VERSION 5.8 ;
BUSBITCHARS "[]" ;
DIVIDERCHAR "/" ;
UNITS
    DATABASE MICRONS 1000 ;
END UNITS

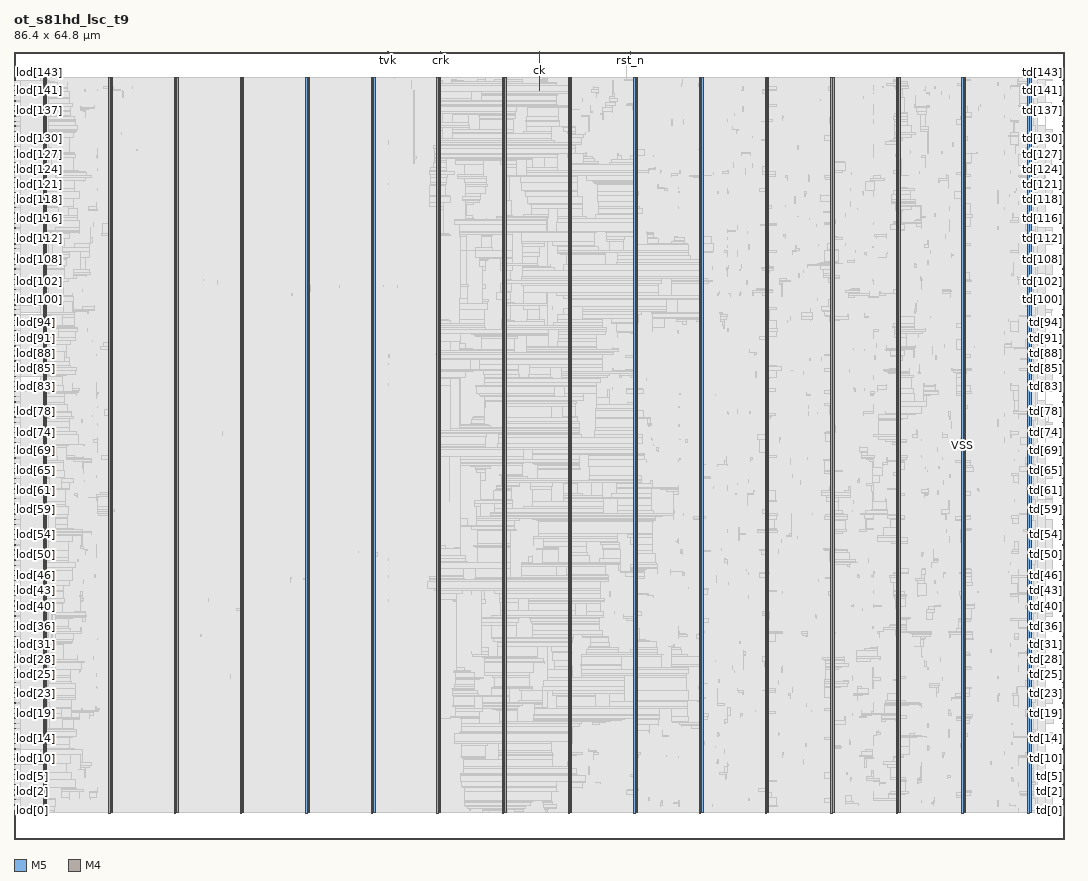
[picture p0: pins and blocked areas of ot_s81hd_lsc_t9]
MACRO ot_s81hd_lsc_t9
  FOREIGN ot_s81hd_lsc_t9 0 0 ;
  CLASS BLOCK ;
  SIZE 86.4 BY 64.8 ;
  PIN ck
    DIRECTION INPUT ;
    USE SIGNAL ;
    PORT
      LAYER M5 ;
        RECT  43.2 64.716 43.224 64.8 ;
    END
    PORT
      LAYER M5 ;
        RECT  43.2 61.619 43.224 64.784 ;
    END
  END ck
  PIN crk
    DIRECTION INPUT ;
    USE SIGNAL ;
    PORT
      LAYER M5 ;
        RECT  35.088 64.716 35.112 64.8 ;
    END
    PORT
      LAYER M5 ;
        RECT  35.088 64.691 35.112 64.784 ;
    END
  END crk
  PIN lod[0]
    DIRECTION OUTPUT ;
    USE SIGNAL ;
    PORT
      LAYER M4 ;
        RECT  0 2.352 0.084 2.376 ;
    END
  END lod[0]
  PIN lod[100]
    DIRECTION OUTPUT ;
    USE SIGNAL ;
    PORT
      LAYER M4 ;
        RECT  0 44.352 0.084 44.376 ;
    END
  END lod[100]
  PIN lod[101]
    DIRECTION OUTPUT ;
    USE SIGNAL ;
    PORT
      LAYER M4 ;
        RECT  0 44.784 0.084 44.808 ;
    END
  END lod[101]
  PIN lod[102]
    DIRECTION OUTPUT ;
    USE SIGNAL ;
    PORT
      LAYER M4 ;
        RECT  0 45.216 0.084 45.24 ;
    END
  END lod[102]
  PIN lod[103]
    DIRECTION OUTPUT ;
    USE SIGNAL ;
    PORT
      LAYER M4 ;
        RECT  0 45.6 0.084 45.624 ;
    END
  END lod[103]
  PIN lod[104]
    DIRECTION OUTPUT ;
    USE SIGNAL ;
    PORT
      LAYER M4 ;
        RECT  0 46.032 0.084 46.056 ;
    END
  END lod[104]
  PIN lod[105]
    DIRECTION OUTPUT ;
    USE SIGNAL ;
    PORT
      LAYER M4 ;
        RECT  0 46.464 0.084 46.488 ;
    END
  END lod[105]
  PIN lod[106]
    DIRECTION OUTPUT ;
    USE SIGNAL ;
    PORT
      LAYER M4 ;
        RECT  0 46.896 0.084 46.92 ;
    END
  END lod[106]
  PIN lod[107]
    DIRECTION OUTPUT ;
    USE SIGNAL ;
    PORT
      LAYER M4 ;
        RECT  0 47.28 0.084 47.304 ;
    END
  END lod[107]
  PIN lod[108]
    DIRECTION OUTPUT ;
    USE SIGNAL ;
    PORT
      LAYER M4 ;
        RECT  0 47.712 0.084 47.736 ;
    END
  END lod[108]
  PIN lod[109]
    DIRECTION OUTPUT ;
    USE SIGNAL ;
    PORT
      LAYER M4 ;
        RECT  0 48.144 0.084 48.168 ;
    END
  END lod[109]
  PIN lod[10]
    DIRECTION OUTPUT ;
    USE SIGNAL ;
    PORT
      LAYER M4 ;
        RECT  0 6.576 0.084 6.6 ;
    END
  END lod[10]
  PIN lod[110]
    DIRECTION OUTPUT ;
    USE SIGNAL ;
    PORT
      LAYER M4 ;
        RECT  0 48.576 0.084 48.6 ;
    END
  END lod[110]
  PIN lod[111]
    DIRECTION OUTPUT ;
    USE SIGNAL ;
    PORT
      LAYER M4 ;
        RECT  0 48.96 0.084 48.984 ;
    END
  END lod[111]
  PIN lod[112]
    DIRECTION OUTPUT ;
    USE SIGNAL ;
    PORT
      LAYER M4 ;
        RECT  0 49.392 0.084 49.416 ;
    END
  END lod[112]
  PIN lod[113]
    DIRECTION OUTPUT ;
    USE SIGNAL ;
    PORT
      LAYER M4 ;
        RECT  0 49.824 0.084 49.848 ;
    END
  END lod[113]
  PIN lod[114]
    DIRECTION OUTPUT ;
    USE SIGNAL ;
    PORT
      LAYER M4 ;
        RECT  0 50.256 0.084 50.28 ;
    END
  END lod[114]
  PIN lod[115]
    DIRECTION OUTPUT ;
    USE SIGNAL ;
    PORT
      LAYER M4 ;
        RECT  0 50.64 0.084 50.664 ;
    END
  END lod[115]
  PIN lod[116]
    DIRECTION OUTPUT ;
    USE SIGNAL ;
    PORT
      LAYER M4 ;
        RECT  0 51.072 0.084 51.096 ;
    END
  END lod[116]
  PIN lod[117]
    DIRECTION OUTPUT ;
    USE SIGNAL ;
    PORT
      LAYER M4 ;
        RECT  0 51.504 0.084 51.528 ;
    END
  END lod[117]
  PIN lod[118]
    DIRECTION OUTPUT ;
    USE SIGNAL ;
    PORT
      LAYER M4 ;
        RECT  0 51.936 0.084 51.96 ;
    END
  END lod[118]
  PIN lod[119]
    DIRECTION OUTPUT ;
    USE SIGNAL ;
    PORT
      LAYER M4 ;
        RECT  0 52.32 0.084 52.344 ;
    END
  END lod[119]
  PIN lod[11]
    DIRECTION OUTPUT ;
    USE SIGNAL ;
    PORT
      LAYER M4 ;
        RECT  0 6.96 0.084 6.984 ;
    END
  END lod[11]
  PIN lod[120]
    DIRECTION OUTPUT ;
    USE SIGNAL ;
    PORT
      LAYER M4 ;
        RECT  0 52.752 0.084 52.776 ;
    END
  END lod[120]
  PIN lod[121]
    DIRECTION OUTPUT ;
    USE SIGNAL ;
    PORT
      LAYER M4 ;
        RECT  0 53.184 0.084 53.208 ;
    END
  END lod[121]
  PIN lod[122]
    DIRECTION OUTPUT ;
    USE SIGNAL ;
    PORT
      LAYER M4 ;
        RECT  0 53.616 0.084 53.64 ;
    END
  END lod[122]
  PIN lod[123]
    DIRECTION OUTPUT ;
    USE SIGNAL ;
    PORT
      LAYER M4 ;
        RECT  0 54 0.084 54.024 ;
    END
  END lod[123]
  PIN lod[124]
    DIRECTION OUTPUT ;
    USE SIGNAL ;
    PORT
      LAYER M4 ;
        RECT  0 54.432 0.084 54.456 ;
    END
  END lod[124]
  PIN lod[125]
    DIRECTION OUTPUT ;
    USE SIGNAL ;
    PORT
      LAYER M4 ;
        RECT  0 54.864 0.084 54.888 ;
    END
  END lod[125]
  PIN lod[126]
    DIRECTION OUTPUT ;
    USE SIGNAL ;
    PORT
      LAYER M4 ;
        RECT  0 55.296 0.084 55.32 ;
    END
  END lod[126]
  PIN lod[127]
    DIRECTION OUTPUT ;
    USE SIGNAL ;
    PORT
      LAYER M4 ;
        RECT  0 55.68 0.084 55.704 ;
    END
  END lod[127]
  PIN lod[128]
    DIRECTION OUTPUT ;
    USE SIGNAL ;
    PORT
      LAYER M4 ;
        RECT  0 56.112 0.084 56.136 ;
    END
  END lod[128]
  PIN lod[129]
    DIRECTION OUTPUT ;
    USE SIGNAL ;
    PORT
      LAYER M4 ;
        RECT  0 56.544 0.084 56.568 ;
    END
  END lod[129]
  PIN lod[12]
    DIRECTION OUTPUT ;
    USE SIGNAL ;
    PORT
      LAYER M4 ;
        RECT  0 7.392 0.084 7.416 ;
    END
  END lod[12]
  PIN lod[130]
    DIRECTION OUTPUT ;
    USE SIGNAL ;
    PORT
      LAYER M4 ;
        RECT  0 56.976 0.084 57 ;
    END
  END lod[130]
  PIN lod[131]
    DIRECTION OUTPUT ;
    USE SIGNAL ;
    PORT
      LAYER M4 ;
        RECT  0 57.36 0.084 57.384 ;
    END
  END lod[131]
  PIN lod[132]
    DIRECTION OUTPUT ;
    USE SIGNAL ;
    PORT
      LAYER M4 ;
        RECT  0 57.792 0.084 57.816 ;
    END
  END lod[132]
  PIN lod[133]
    DIRECTION OUTPUT ;
    USE SIGNAL ;
    PORT
      LAYER M4 ;
        RECT  0 58.224 0.084 58.248 ;
    END
  END lod[133]
  PIN lod[134]
    DIRECTION OUTPUT ;
    USE SIGNAL ;
    PORT
      LAYER M4 ;
        RECT  0 58.656 0.084 58.68 ;
    END
  END lod[134]
  PIN lod[135]
    DIRECTION OUTPUT ;
    USE SIGNAL ;
    PORT
      LAYER M4 ;
        RECT  0 59.04 0.084 59.064 ;
    END
  END lod[135]
  PIN lod[136]
    DIRECTION OUTPUT ;
    USE SIGNAL ;
    PORT
      LAYER M4 ;
        RECT  0 59.472 0.084 59.496 ;
    END
  END lod[136]
  PIN lod[137]
    DIRECTION OUTPUT ;
    USE SIGNAL ;
    PORT
      LAYER M4 ;
        RECT  0 59.904 0.084 59.928 ;
    END
  END lod[137]
  PIN lod[138]
    DIRECTION OUTPUT ;
    USE SIGNAL ;
    PORT
      LAYER M4 ;
        RECT  0 60.336 0.084 60.36 ;
    END
  END lod[138]
  PIN lod[139]
    DIRECTION OUTPUT ;
    USE SIGNAL ;
    PORT
      LAYER M4 ;
        RECT  0 60.72 0.084 60.744 ;
    END
  END lod[139]
  PIN lod[13]
    DIRECTION OUTPUT ;
    USE SIGNAL ;
    PORT
      LAYER M4 ;
        RECT  0 7.824 0.084 7.848 ;
    END
  END lod[13]
  PIN lod[140]
    DIRECTION OUTPUT ;
    USE SIGNAL ;
    PORT
      LAYER M4 ;
        RECT  0 61.152 0.084 61.176 ;
    END
  END lod[140]
  PIN lod[141]
    DIRECTION OUTPUT ;
    USE SIGNAL ;
    PORT
      LAYER M4 ;
        RECT  0 61.584 0.084 61.608 ;
    END
  END lod[141]
  PIN lod[142]
    DIRECTION OUTPUT ;
    USE SIGNAL ;
    PORT
      LAYER M4 ;
        RECT  0 62.016 0.084 62.04 ;
    END
  END lod[142]
  PIN lod[143]
    DIRECTION OUTPUT ;
    USE SIGNAL ;
    PORT
      LAYER M4 ;
        RECT  0 62.4 0.084 62.424 ;
    END
  END lod[143]
  PIN lod[14]
    DIRECTION OUTPUT ;
    USE SIGNAL ;
    PORT
      LAYER M4 ;
        RECT  0 8.256 0.084 8.28 ;
    END
  END lod[14]
  PIN lod[15]
    DIRECTION OUTPUT ;
    USE SIGNAL ;
    PORT
      LAYER M4 ;
        RECT  0 8.64 0.084 8.664 ;
    END
  END lod[15]
  PIN lod[16]
    DIRECTION OUTPUT ;
    USE SIGNAL ;
    PORT
      LAYER M4 ;
        RECT  0 9.072 0.084 9.096 ;
    END
  END lod[16]
  PIN lod[17]
    DIRECTION OUTPUT ;
    USE SIGNAL ;
    PORT
      LAYER M4 ;
        RECT  0 9.504 0.084 9.528 ;
    END
  END lod[17]
  PIN lod[18]
    DIRECTION OUTPUT ;
    USE SIGNAL ;
    PORT
      LAYER M4 ;
        RECT  0 9.936 0.084 9.96 ;
    END
  END lod[18]
  PIN lod[19]
    DIRECTION OUTPUT ;
    USE SIGNAL ;
    PORT
      LAYER M4 ;
        RECT  0 10.32 0.084 10.344 ;
    END
  END lod[19]
  PIN lod[1]
    DIRECTION OUTPUT ;
    USE SIGNAL ;
    PORT
      LAYER M4 ;
        RECT  0 2.784 0.084 2.808 ;
    END
  END lod[1]
  PIN lod[20]
    DIRECTION OUTPUT ;
    USE SIGNAL ;
    PORT
      LAYER M4 ;
        RECT  0 10.752 0.084 10.776 ;
    END
  END lod[20]
  PIN lod[21]
    DIRECTION OUTPUT ;
    USE SIGNAL ;
    PORT
      LAYER M4 ;
        RECT  0 11.184 0.084 11.208 ;
    END
  END lod[21]
  PIN lod[22]
    DIRECTION OUTPUT ;
    USE SIGNAL ;
    PORT
      LAYER M4 ;
        RECT  0 11.616 0.084 11.64 ;
    END
  END lod[22]
  PIN lod[23]
    DIRECTION OUTPUT ;
    USE SIGNAL ;
    PORT
      LAYER M4 ;
        RECT  0 12 0.084 12.024 ;
    END
  END lod[23]
  PIN lod[24]
    DIRECTION OUTPUT ;
    USE SIGNAL ;
    PORT
      LAYER M4 ;
        RECT  0 12.432 0.084 12.456 ;
    END
  END lod[24]
  PIN lod[25]
    DIRECTION OUTPUT ;
    USE SIGNAL ;
    PORT
      LAYER M4 ;
        RECT  0 12.864 0.084 12.888 ;
    END
  END lod[25]
  PIN lod[26]
    DIRECTION OUTPUT ;
    USE SIGNAL ;
    PORT
      LAYER M4 ;
        RECT  0 13.296 0.084 13.32 ;
    END
  END lod[26]
  PIN lod[27]
    DIRECTION OUTPUT ;
    USE SIGNAL ;
    PORT
      LAYER M4 ;
        RECT  0 13.68 0.084 13.704 ;
    END
  END lod[27]
  PIN lod[28]
    DIRECTION OUTPUT ;
    USE SIGNAL ;
    PORT
      LAYER M4 ;
        RECT  0 14.112 0.084 14.136 ;
    END
  END lod[28]
  PIN lod[29]
    DIRECTION OUTPUT ;
    USE SIGNAL ;
    PORT
      LAYER M4 ;
        RECT  0 14.544 0.084 14.568 ;
    END
  END lod[29]
  PIN lod[2]
    DIRECTION OUTPUT ;
    USE SIGNAL ;
    PORT
      LAYER M4 ;
        RECT  0 3.216 0.084 3.24 ;
    END
  END lod[2]
  PIN lod[30]
    DIRECTION OUTPUT ;
    USE SIGNAL ;
    PORT
      LAYER M4 ;
        RECT  0 14.976 0.084 15 ;
    END
  END lod[30]
  PIN lod[31]
    DIRECTION OUTPUT ;
    USE SIGNAL ;
    PORT
      LAYER M4 ;
        RECT  0 15.36 0.084 15.384 ;
    END
  END lod[31]
  PIN lod[32]
    DIRECTION OUTPUT ;
    USE SIGNAL ;
    PORT
      LAYER M4 ;
        RECT  0 15.792 0.084 15.816 ;
    END
  END lod[32]
  PIN lod[33]
    DIRECTION OUTPUT ;
    USE SIGNAL ;
    PORT
      LAYER M4 ;
        RECT  0 16.224 0.084 16.248 ;
    END
  END lod[33]
  PIN lod[34]
    DIRECTION OUTPUT ;
    USE SIGNAL ;
    PORT
      LAYER M4 ;
        RECT  0 16.656 0.084 16.68 ;
    END
  END lod[34]
  PIN lod[35]
    DIRECTION OUTPUT ;
    USE SIGNAL ;
    PORT
      LAYER M4 ;
        RECT  0 17.04 0.084 17.064 ;
    END
  END lod[35]
  PIN lod[36]
    DIRECTION OUTPUT ;
    USE SIGNAL ;
    PORT
      LAYER M4 ;
        RECT  0 17.472 0.084 17.496 ;
    END
  END lod[36]
  PIN lod[37]
    DIRECTION OUTPUT ;
    USE SIGNAL ;
    PORT
      LAYER M4 ;
        RECT  0 17.904 0.084 17.928 ;
    END
  END lod[37]
  PIN lod[38]
    DIRECTION OUTPUT ;
    USE SIGNAL ;
    PORT
      LAYER M4 ;
        RECT  0 18.336 0.084 18.36 ;
    END
  END lod[38]
  PIN lod[39]
    DIRECTION OUTPUT ;
    USE SIGNAL ;
    PORT
      LAYER M4 ;
        RECT  0 18.72 0.084 18.744 ;
    END
  END lod[39]
  PIN lod[3]
    DIRECTION OUTPUT ;
    USE SIGNAL ;
    PORT
      LAYER M4 ;
        RECT  0 3.6 0.084 3.624 ;
    END
  END lod[3]
  PIN lod[40]
    DIRECTION OUTPUT ;
    USE SIGNAL ;
    PORT
      LAYER M4 ;
        RECT  0 19.152 0.084 19.176 ;
    END
  END lod[40]
  PIN lod[41]
    DIRECTION OUTPUT ;
    USE SIGNAL ;
    PORT
      LAYER M4 ;
        RECT  0 19.584 0.084 19.608 ;
    END
  END lod[41]
  PIN lod[42]
    DIRECTION OUTPUT ;
    USE SIGNAL ;
    PORT
      LAYER M4 ;
        RECT  0 20.016 0.084 20.04 ;
    END
  END lod[42]
  PIN lod[43]
    DIRECTION OUTPUT ;
    USE SIGNAL ;
    PORT
      LAYER M4 ;
        RECT  0 20.4 0.084 20.424 ;
    END
  END lod[43]
  PIN lod[44]
    DIRECTION OUTPUT ;
    USE SIGNAL ;
    PORT
      LAYER M4 ;
        RECT  0 20.832 0.084 20.856 ;
    END
  END lod[44]
  PIN lod[45]
    DIRECTION OUTPUT ;
    USE SIGNAL ;
    PORT
      LAYER M4 ;
        RECT  0 21.264 0.084 21.288 ;
    END
  END lod[45]
  PIN lod[46]
    DIRECTION OUTPUT ;
    USE SIGNAL ;
    PORT
      LAYER M4 ;
        RECT  0 21.696 0.084 21.72 ;
    END
  END lod[46]
  PIN lod[47]
    DIRECTION OUTPUT ;
    USE SIGNAL ;
    PORT
      LAYER M4 ;
        RECT  0 22.08 0.084 22.104 ;
    END
  END lod[47]
  PIN lod[48]
    DIRECTION OUTPUT ;
    USE SIGNAL ;
    PORT
      LAYER M4 ;
        RECT  0 22.512 0.084 22.536 ;
    END
  END lod[48]
  PIN lod[49]
    DIRECTION OUTPUT ;
    USE SIGNAL ;
    PORT
      LAYER M4 ;
        RECT  0 22.944 0.084 22.968 ;
    END
  END lod[49]
  PIN lod[4]
    DIRECTION OUTPUT ;
    USE SIGNAL ;
    PORT
      LAYER M4 ;
        RECT  0 4.032 0.084 4.056 ;
    END
  END lod[4]
  PIN lod[50]
    DIRECTION OUTPUT ;
    USE SIGNAL ;
    PORT
      LAYER M4 ;
        RECT  0 23.376 0.084 23.4 ;
    END
  END lod[50]
  PIN lod[51]
    DIRECTION OUTPUT ;
    USE SIGNAL ;
    PORT
      LAYER M4 ;
        RECT  0 23.76 0.084 23.784 ;
    END
  END lod[51]
  PIN lod[52]
    DIRECTION OUTPUT ;
    USE SIGNAL ;
    PORT
      LAYER M4 ;
        RECT  0 24.192 0.084 24.216 ;
    END
  END lod[52]
  PIN lod[53]
    DIRECTION OUTPUT ;
    USE SIGNAL ;
    PORT
      LAYER M4 ;
        RECT  0 24.624 0.084 24.648 ;
    END
  END lod[53]
  PIN lod[54]
    DIRECTION OUTPUT ;
    USE SIGNAL ;
    PORT
      LAYER M4 ;
        RECT  0 25.056 0.084 25.08 ;
    END
  END lod[54]
  PIN lod[55]
    DIRECTION OUTPUT ;
    USE SIGNAL ;
    PORT
      LAYER M4 ;
        RECT  0 25.44 0.084 25.464 ;
    END
  END lod[55]
  PIN lod[56]
    DIRECTION OUTPUT ;
    USE SIGNAL ;
    PORT
      LAYER M4 ;
        RECT  0 25.872 0.084 25.896 ;
    END
  END lod[56]
  PIN lod[57]
    DIRECTION OUTPUT ;
    USE SIGNAL ;
    PORT
      LAYER M4 ;
        RECT  0 26.304 0.084 26.328 ;
    END
  END lod[57]
  PIN lod[58]
    DIRECTION OUTPUT ;
    USE SIGNAL ;
    PORT
      LAYER M4 ;
        RECT  0 26.736 0.084 26.76 ;
    END
  END lod[58]
  PIN lod[59]
    DIRECTION OUTPUT ;
    USE SIGNAL ;
    PORT
      LAYER M4 ;
        RECT  0 27.12 0.084 27.144 ;
    END
  END lod[59]
  PIN lod[5]
    DIRECTION OUTPUT ;
    USE SIGNAL ;
    PORT
      LAYER M4 ;
        RECT  0 4.464 0.084 4.488 ;
    END
  END lod[5]
  PIN lod[60]
    DIRECTION OUTPUT ;
    USE SIGNAL ;
    PORT
      LAYER M4 ;
        RECT  0 27.552 0.084 27.576 ;
    END
  END lod[60]
  PIN lod[61]
    DIRECTION OUTPUT ;
    USE SIGNAL ;
    PORT
      LAYER M4 ;
        RECT  0 27.984 0.084 28.008 ;
    END
  END lod[61]
  PIN lod[62]
    DIRECTION OUTPUT ;
    USE SIGNAL ;
    PORT
      LAYER M4 ;
        RECT  0 28.416 0.084 28.44 ;
    END
  END lod[62]
  PIN lod[63]
    DIRECTION OUTPUT ;
    USE SIGNAL ;
    PORT
      LAYER M4 ;
        RECT  0 28.8 0.084 28.824 ;
    END
  END lod[63]
  PIN lod[64]
    DIRECTION OUTPUT ;
    USE SIGNAL ;
    PORT
      LAYER M4 ;
        RECT  0 29.232 0.084 29.256 ;
    END
  END lod[64]
  PIN lod[65]
    DIRECTION OUTPUT ;
    USE SIGNAL ;
    PORT
      LAYER M4 ;
        RECT  0 29.664 0.084 29.688 ;
    END
  END lod[65]
  PIN lod[66]
    DIRECTION OUTPUT ;
    USE SIGNAL ;
    PORT
      LAYER M4 ;
        RECT  0 30.096 0.084 30.12 ;
    END
  END lod[66]
  PIN lod[67]
    DIRECTION OUTPUT ;
    USE SIGNAL ;
    PORT
      LAYER M4 ;
        RECT  0 30.48 0.084 30.504 ;
    END
  END lod[67]
  PIN lod[68]
    DIRECTION OUTPUT ;
    USE SIGNAL ;
    PORT
      LAYER M4 ;
        RECT  0 30.912 0.084 30.936 ;
    END
  END lod[68]
  PIN lod[69]
    DIRECTION OUTPUT ;
    USE SIGNAL ;
    PORT
      LAYER M4 ;
        RECT  0 31.344 0.084 31.368 ;
    END
  END lod[69]
  PIN lod[6]
    DIRECTION OUTPUT ;
    USE SIGNAL ;
    PORT
      LAYER M4 ;
        RECT  0 4.896 0.084 4.92 ;
    END
  END lod[6]
  PIN lod[70]
    DIRECTION OUTPUT ;
    USE SIGNAL ;
    PORT
      LAYER M4 ;
        RECT  0 31.776 0.084 31.8 ;
    END
  END lod[70]
  PIN lod[71]
    DIRECTION OUTPUT ;
    USE SIGNAL ;
    PORT
      LAYER M4 ;
        RECT  0 32.16 0.084 32.184 ;
    END
  END lod[71]
  PIN lod[72]
    DIRECTION OUTPUT ;
    USE SIGNAL ;
    PORT
      LAYER M4 ;
        RECT  0 32.592 0.084 32.616 ;
    END
  END lod[72]
  PIN lod[73]
    DIRECTION OUTPUT ;
    USE SIGNAL ;
    PORT
      LAYER M4 ;
        RECT  0 33.024 0.084 33.048 ;
    END
  END lod[73]
  PIN lod[74]
    DIRECTION OUTPUT ;
    USE SIGNAL ;
    PORT
      LAYER M4 ;
        RECT  0 33.456 0.084 33.48 ;
    END
  END lod[74]
  PIN lod[75]
    DIRECTION OUTPUT ;
    USE SIGNAL ;
    PORT
      LAYER M4 ;
        RECT  0 33.84 0.084 33.864 ;
    END
  END lod[75]
  PIN lod[76]
    DIRECTION OUTPUT ;
    USE SIGNAL ;
    PORT
      LAYER M4 ;
        RECT  0 34.272 0.084 34.296 ;
    END
  END lod[76]
  PIN lod[77]
    DIRECTION OUTPUT ;
    USE SIGNAL ;
    PORT
      LAYER M4 ;
        RECT  0 34.704 0.084 34.728 ;
    END
  END lod[77]
  PIN lod[78]
    DIRECTION OUTPUT ;
    USE SIGNAL ;
    PORT
      LAYER M4 ;
        RECT  0 35.136 0.084 35.16 ;
    END
  END lod[78]
  PIN lod[79]
    DIRECTION OUTPUT ;
    USE SIGNAL ;
    PORT
      LAYER M4 ;
        RECT  0 35.52 0.084 35.544 ;
    END
  END lod[79]
  PIN lod[7]
    DIRECTION OUTPUT ;
    USE SIGNAL ;
    PORT
      LAYER M4 ;
        RECT  0 5.28 0.084 5.304 ;
    END
  END lod[7]
  PIN lod[80]
    DIRECTION OUTPUT ;
    USE SIGNAL ;
    PORT
      LAYER M4 ;
        RECT  0 35.952 0.084 35.976 ;
    END
  END lod[80]
  PIN lod[81]
    DIRECTION OUTPUT ;
    USE SIGNAL ;
    PORT
      LAYER M4 ;
        RECT  0 36.384 0.084 36.408 ;
    END
  END lod[81]
  PIN lod[82]
    DIRECTION OUTPUT ;
    USE SIGNAL ;
    PORT
      LAYER M4 ;
        RECT  0 36.816 0.084 36.84 ;
    END
  END lod[82]
  PIN lod[83]
    DIRECTION OUTPUT ;
    USE SIGNAL ;
    PORT
      LAYER M4 ;
        RECT  0 37.2 0.084 37.224 ;
    END
  END lod[83]
  PIN lod[84]
    DIRECTION OUTPUT ;
    USE SIGNAL ;
    PORT
      LAYER M4 ;
        RECT  0 37.632 0.084 37.656 ;
    END
  END lod[84]
  PIN lod[85]
    DIRECTION OUTPUT ;
    USE SIGNAL ;
    PORT
      LAYER M4 ;
        RECT  0 38.064 0.084 38.088 ;
    END
  END lod[85]
  PIN lod[86]
    DIRECTION OUTPUT ;
    USE SIGNAL ;
    PORT
      LAYER M4 ;
        RECT  0 38.496 0.084 38.52 ;
    END
  END lod[86]
  PIN lod[87]
    DIRECTION OUTPUT ;
    USE SIGNAL ;
    PORT
      LAYER M4 ;
        RECT  0 38.88 0.084 38.904 ;
    END
  END lod[87]
  PIN lod[88]
    DIRECTION OUTPUT ;
    USE SIGNAL ;
    PORT
      LAYER M4 ;
        RECT  0 39.312 0.084 39.336 ;
    END
  END lod[88]
  PIN lod[89]
    DIRECTION OUTPUT ;
    USE SIGNAL ;
    PORT
      LAYER M4 ;
        RECT  0 39.744 0.084 39.768 ;
    END
  END lod[89]
  PIN lod[8]
    DIRECTION OUTPUT ;
    USE SIGNAL ;
    PORT
      LAYER M4 ;
        RECT  0 5.712 0.084 5.736 ;
    END
  END lod[8]
  PIN lod[90]
    DIRECTION OUTPUT ;
    USE SIGNAL ;
    PORT
      LAYER M4 ;
        RECT  0 40.176 0.084 40.2 ;
    END
  END lod[90]
  PIN lod[91]
    DIRECTION OUTPUT ;
    USE SIGNAL ;
    PORT
      LAYER M4 ;
        RECT  0 40.56 0.084 40.584 ;
    END
  END lod[91]
  PIN lod[92]
    DIRECTION OUTPUT ;
    USE SIGNAL ;
    PORT
      LAYER M4 ;
        RECT  0 40.992 0.084 41.016 ;
    END
  END lod[92]
  PIN lod[93]
    DIRECTION OUTPUT ;
    USE SIGNAL ;
    PORT
      LAYER M4 ;
        RECT  0 41.424 0.084 41.448 ;
    END
  END lod[93]
  PIN lod[94]
    DIRECTION OUTPUT ;
    USE SIGNAL ;
    PORT
      LAYER M4 ;
        RECT  0 41.856 0.084 41.88 ;
    END
  END lod[94]
  PIN lod[95]
    DIRECTION OUTPUT ;
    USE SIGNAL ;
    PORT
      LAYER M4 ;
        RECT  0 42.24 0.084 42.264 ;
    END
  END lod[95]
  PIN lod[96]
    DIRECTION OUTPUT ;
    USE SIGNAL ;
    PORT
      LAYER M4 ;
        RECT  0 42.672 0.084 42.696 ;
    END
  END lod[96]
  PIN lod[97]
    DIRECTION OUTPUT ;
    USE SIGNAL ;
    PORT
      LAYER M4 ;
        RECT  0 43.104 0.084 43.128 ;
    END
  END lod[97]
  PIN lod[98]
    DIRECTION OUTPUT ;
    USE SIGNAL ;
    PORT
      LAYER M4 ;
        RECT  0 43.536 0.084 43.56 ;
    END
  END lod[98]
  PIN lod[99]
    DIRECTION OUTPUT ;
    USE SIGNAL ;
    PORT
      LAYER M4 ;
        RECT  0 43.92 0.084 43.944 ;
    END
  END lod[99]
  PIN lod[9]
    DIRECTION OUTPUT ;
    USE SIGNAL ;
    PORT
      LAYER M4 ;
        RECT  0 6.144 0.084 6.168 ;
    END
  END lod[9]
  PIN rst_n
    DIRECTION INPUT ;
    USE SIGNAL ;
    PORT
      LAYER M5 ;
        RECT  50.736 64.716 50.76 64.8 ;
    END
    PORT
      LAYER M5 ;
        RECT  50.736 63.829 50.76 64.784 ;
    END
  END rst_n
  PIN td[0]
    DIRECTION INPUT ;
    USE SIGNAL ;
    PORT
      LAYER M4 ;
        RECT  86.316 2.352 86.4 2.376 ;
    END
  END td[0]
  PIN td[100]
    DIRECTION INPUT ;
    USE SIGNAL ;
    PORT
      LAYER M4 ;
        RECT  86.316 44.352 86.4 44.376 ;
    END
  END td[100]
  PIN td[101]
    DIRECTION INPUT ;
    USE SIGNAL ;
    PORT
      LAYER M4 ;
        RECT  86.316 44.784 86.4 44.808 ;
    END
  END td[101]
  PIN td[102]
    DIRECTION INPUT ;
    USE SIGNAL ;
    PORT
      LAYER M4 ;
        RECT  86.316 45.216 86.4 45.24 ;
    END
  END td[102]
  PIN td[103]
    DIRECTION INPUT ;
    USE SIGNAL ;
    PORT
      LAYER M4 ;
        RECT  86.316 45.6 86.4 45.624 ;
    END
  END td[103]
  PIN td[104]
    DIRECTION INPUT ;
    USE SIGNAL ;
    PORT
      LAYER M4 ;
        RECT  86.316 46.032 86.4 46.056 ;
    END
  END td[104]
  PIN td[105]
    DIRECTION INPUT ;
    USE SIGNAL ;
    PORT
      LAYER M4 ;
        RECT  86.316 46.464 86.4 46.488 ;
    END
  END td[105]
  PIN td[106]
    DIRECTION INPUT ;
    USE SIGNAL ;
    PORT
      LAYER M4 ;
        RECT  86.316 46.896 86.4 46.92 ;
    END
  END td[106]
  PIN td[107]
    DIRECTION INPUT ;
    USE SIGNAL ;
    PORT
      LAYER M4 ;
        RECT  86.316 47.28 86.4 47.304 ;
    END
  END td[107]
  PIN td[108]
    DIRECTION INPUT ;
    USE SIGNAL ;
    PORT
      LAYER M4 ;
        RECT  86.316 47.712 86.4 47.736 ;
    END
  END td[108]
  PIN td[109]
    DIRECTION INPUT ;
    USE SIGNAL ;
    PORT
      LAYER M4 ;
        RECT  86.316 48.144 86.4 48.168 ;
    END
  END td[109]
  PIN td[10]
    DIRECTION INPUT ;
    USE SIGNAL ;
    PORT
      LAYER M4 ;
        RECT  86.316 6.576 86.4 6.6 ;
    END
  END td[10]
  PIN td[110]
    DIRECTION INPUT ;
    USE SIGNAL ;
    PORT
      LAYER M4 ;
        RECT  86.316 48.576 86.4 48.6 ;
    END
  END td[110]
  PIN td[111]
    DIRECTION INPUT ;
    USE SIGNAL ;
    PORT
      LAYER M4 ;
        RECT  86.316 48.96 86.4 48.984 ;
    END
  END td[111]
  PIN td[112]
    DIRECTION INPUT ;
    USE SIGNAL ;
    PORT
      LAYER M4 ;
        RECT  86.316 49.392 86.4 49.416 ;
    END
  END td[112]
  PIN td[113]
    DIRECTION INPUT ;
    USE SIGNAL ;
    PORT
      LAYER M4 ;
        RECT  86.316 49.824 86.4 49.848 ;
    END
  END td[113]
  PIN td[114]
    DIRECTION INPUT ;
    USE SIGNAL ;
    PORT
      LAYER M4 ;
        RECT  86.316 50.256 86.4 50.28 ;
    END
  END td[114]
  PIN td[115]
    DIRECTION INPUT ;
    USE SIGNAL ;
    PORT
      LAYER M4 ;
        RECT  86.316 50.64 86.4 50.664 ;
    END
  END td[115]
  PIN td[116]
    DIRECTION INPUT ;
    USE SIGNAL ;
    PORT
      LAYER M4 ;
        RECT  86.316 51.072 86.4 51.096 ;
    END
  END td[116]
  PIN td[117]
    DIRECTION INPUT ;
    USE SIGNAL ;
    PORT
      LAYER M4 ;
        RECT  86.316 51.504 86.4 51.528 ;
    END
  END td[117]
  PIN td[118]
    DIRECTION INPUT ;
    USE SIGNAL ;
    PORT
      LAYER M4 ;
        RECT  86.316 51.936 86.4 51.96 ;
    END
  END td[118]
  PIN td[119]
    DIRECTION INPUT ;
    USE SIGNAL ;
    PORT
      LAYER M4 ;
        RECT  86.316 52.32 86.4 52.344 ;
    END
  END td[119]
  PIN td[11]
    DIRECTION INPUT ;
    USE SIGNAL ;
    PORT
      LAYER M4 ;
        RECT  86.316 6.96 86.4 6.984 ;
    END
  END td[11]
  PIN td[120]
    DIRECTION INPUT ;
    USE SIGNAL ;
    PORT
      LAYER M4 ;
        RECT  86.316 52.752 86.4 52.776 ;
    END
  END td[120]
  PIN td[121]
    DIRECTION INPUT ;
    USE SIGNAL ;
    PORT
      LAYER M4 ;
        RECT  86.316 53.184 86.4 53.208 ;
    END
  END td[121]
  PIN td[122]
    DIRECTION INPUT ;
    USE SIGNAL ;
    PORT
      LAYER M4 ;
        RECT  86.316 53.616 86.4 53.64 ;
    END
  END td[122]
  PIN td[123]
    DIRECTION INPUT ;
    USE SIGNAL ;
    PORT
      LAYER M4 ;
        RECT  86.316 54 86.4 54.024 ;
    END
  END td[123]
  PIN td[124]
    DIRECTION INPUT ;
    USE SIGNAL ;
    PORT
      LAYER M4 ;
        RECT  86.316 54.432 86.4 54.456 ;
    END
  END td[124]
  PIN td[125]
    DIRECTION INPUT ;
    USE SIGNAL ;
    PORT
      LAYER M4 ;
        RECT  86.316 54.864 86.4 54.888 ;
    END
  END td[125]
  PIN td[126]
    DIRECTION INPUT ;
    USE SIGNAL ;
    PORT
      LAYER M4 ;
        RECT  86.316 55.296 86.4 55.32 ;
    END
  END td[126]
  PIN td[127]
    DIRECTION INPUT ;
    USE SIGNAL ;
    PORT
      LAYER M4 ;
        RECT  86.316 55.68 86.4 55.704 ;
    END
  END td[127]
  PIN td[128]
    DIRECTION INPUT ;
    USE SIGNAL ;
    PORT
      LAYER M4 ;
        RECT  86.316 56.112 86.4 56.136 ;
    END
  END td[128]
  PIN td[129]
    DIRECTION INPUT ;
    USE SIGNAL ;
    PORT
      LAYER M4 ;
        RECT  86.316 56.544 86.4 56.568 ;
    END
  END td[129]
  PIN td[12]
    DIRECTION INPUT ;
    USE SIGNAL ;
    PORT
      LAYER M4 ;
        RECT  86.316 7.392 86.4 7.416 ;
    END
  END td[12]
  PIN td[130]
    DIRECTION INPUT ;
    USE SIGNAL ;
    PORT
      LAYER M4 ;
        RECT  86.316 56.976 86.4 57 ;
    END
  END td[130]
  PIN td[131]
    DIRECTION INPUT ;
    USE SIGNAL ;
    PORT
      LAYER M4 ;
        RECT  86.316 57.36 86.4 57.384 ;
    END
  END td[131]
  PIN td[132]
    DIRECTION INPUT ;
    USE SIGNAL ;
    PORT
      LAYER M4 ;
        RECT  86.316 57.792 86.4 57.816 ;
    END
  END td[132]
  PIN td[133]
    DIRECTION INPUT ;
    USE SIGNAL ;
    PORT
      LAYER M4 ;
        RECT  86.316 58.224 86.4 58.248 ;
    END
  END td[133]
  PIN td[134]
    DIRECTION INPUT ;
    USE SIGNAL ;
    PORT
      LAYER M4 ;
        RECT  86.316 58.656 86.4 58.68 ;
    END
  END td[134]
  PIN td[135]
    DIRECTION INPUT ;
    USE SIGNAL ;
    PORT
      LAYER M4 ;
        RECT  86.316 59.04 86.4 59.064 ;
    END
  END td[135]
  PIN td[136]
    DIRECTION INPUT ;
    USE SIGNAL ;
    PORT
      LAYER M4 ;
        RECT  86.316 59.472 86.4 59.496 ;
    END
  END td[136]
  PIN td[137]
    DIRECTION INPUT ;
    USE SIGNAL ;
    PORT
      LAYER M4 ;
        RECT  86.316 59.904 86.4 59.928 ;
    END
  END td[137]
  PIN td[138]
    DIRECTION INPUT ;
    USE SIGNAL ;
    PORT
      LAYER M4 ;
        RECT  86.316 60.336 86.4 60.36 ;
    END
  END td[138]
  PIN td[139]
    DIRECTION INPUT ;
    USE SIGNAL ;
    PORT
      LAYER M4 ;
        RECT  86.316 60.72 86.4 60.744 ;
    END
  END td[139]
  PIN td[13]
    DIRECTION INPUT ;
    USE SIGNAL ;
    PORT
      LAYER M4 ;
        RECT  86.316 7.824 86.4 7.848 ;
    END
  END td[13]
  PIN td[140]
    DIRECTION INPUT ;
    USE SIGNAL ;
    PORT
      LAYER M4 ;
        RECT  86.316 61.152 86.4 61.176 ;
    END
  END td[140]
  PIN td[141]
    DIRECTION INPUT ;
    USE SIGNAL ;
    PORT
      LAYER M4 ;
        RECT  86.316 61.584 86.4 61.608 ;
    END
  END td[141]
  PIN td[142]
    DIRECTION INPUT ;
    USE SIGNAL ;
    PORT
      LAYER M4 ;
        RECT  86.316 62.016 86.4 62.04 ;
    END
  END td[142]
  PIN td[143]
    DIRECTION INPUT ;
    USE SIGNAL ;
    PORT
      LAYER M4 ;
        RECT  86.316 62.4 86.4 62.424 ;
    END
  END td[143]
  PIN td[14]
    DIRECTION INPUT ;
    USE SIGNAL ;
    PORT
      LAYER M4 ;
        RECT  86.316 8.256 86.4 8.28 ;
    END
  END td[14]
  PIN td[15]
    DIRECTION INPUT ;
    USE SIGNAL ;
    PORT
      LAYER M4 ;
        RECT  86.316 8.64 86.4 8.664 ;
    END
  END td[15]
  PIN td[16]
    DIRECTION INPUT ;
    USE SIGNAL ;
    PORT
      LAYER M4 ;
        RECT  86.316 9.072 86.4 9.096 ;
    END
  END td[16]
  PIN td[17]
    DIRECTION INPUT ;
    USE SIGNAL ;
    PORT
      LAYER M4 ;
        RECT  86.316 9.504 86.4 9.528 ;
    END
  END td[17]
  PIN td[18]
    DIRECTION INPUT ;
    USE SIGNAL ;
    PORT
      LAYER M4 ;
        RECT  86.316 9.936 86.4 9.96 ;
    END
  END td[18]
  PIN td[19]
    DIRECTION INPUT ;
    USE SIGNAL ;
    PORT
      LAYER M4 ;
        RECT  86.316 10.32 86.4 10.344 ;
    END
  END td[19]
  PIN td[1]
    DIRECTION INPUT ;
    USE SIGNAL ;
    PORT
      LAYER M4 ;
        RECT  86.316 2.784 86.4 2.808 ;
    END
  END td[1]
  PIN td[20]
    DIRECTION INPUT ;
    USE SIGNAL ;
    PORT
      LAYER M4 ;
        RECT  86.316 10.752 86.4 10.776 ;
    END
  END td[20]
  PIN td[21]
    DIRECTION INPUT ;
    USE SIGNAL ;
    PORT
      LAYER M4 ;
        RECT  86.316 11.184 86.4 11.208 ;
    END
  END td[21]
  PIN td[22]
    DIRECTION INPUT ;
    USE SIGNAL ;
    PORT
      LAYER M4 ;
        RECT  86.316 11.616 86.4 11.64 ;
    END
  END td[22]
  PIN td[23]
    DIRECTION INPUT ;
    USE SIGNAL ;
    PORT
      LAYER M4 ;
        RECT  86.316 12 86.4 12.024 ;
    END
  END td[23]
  PIN td[24]
    DIRECTION INPUT ;
    USE SIGNAL ;
    PORT
      LAYER M4 ;
        RECT  86.316 12.432 86.4 12.456 ;
    END
  END td[24]
  PIN td[25]
    DIRECTION INPUT ;
    USE SIGNAL ;
    PORT
      LAYER M4 ;
        RECT  86.316 12.864 86.4 12.888 ;
    END
  END td[25]
  PIN td[26]
    DIRECTION INPUT ;
    USE SIGNAL ;
    PORT
      LAYER M4 ;
        RECT  86.316 13.296 86.4 13.32 ;
    END
  END td[26]
  PIN td[27]
    DIRECTION INPUT ;
    USE SIGNAL ;
    PORT
      LAYER M4 ;
        RECT  86.316 13.68 86.4 13.704 ;
    END
  END td[27]
  PIN td[28]
    DIRECTION INPUT ;
    USE SIGNAL ;
    PORT
      LAYER M4 ;
        RECT  86.316 14.112 86.4 14.136 ;
    END
  END td[28]
  PIN td[29]
    DIRECTION INPUT ;
    USE SIGNAL ;
    PORT
      LAYER M4 ;
        RECT  86.316 14.544 86.4 14.568 ;
    END
  END td[29]
  PIN td[2]
    DIRECTION INPUT ;
    USE SIGNAL ;
    PORT
      LAYER M4 ;
        RECT  86.316 3.216 86.4 3.24 ;
    END
  END td[2]
  PIN td[30]
    DIRECTION INPUT ;
    USE SIGNAL ;
    PORT
      LAYER M4 ;
        RECT  86.316 14.976 86.4 15 ;
    END
  END td[30]
  PIN td[31]
    DIRECTION INPUT ;
    USE SIGNAL ;
    PORT
      LAYER M4 ;
        RECT  86.316 15.36 86.4 15.384 ;
    END
  END td[31]
  PIN td[32]
    DIRECTION INPUT ;
    USE SIGNAL ;
    PORT
      LAYER M4 ;
        RECT  86.316 15.792 86.4 15.816 ;
    END
  END td[32]
  PIN td[33]
    DIRECTION INPUT ;
    USE SIGNAL ;
    PORT
      LAYER M4 ;
        RECT  86.316 16.224 86.4 16.248 ;
    END
  END td[33]
  PIN td[34]
    DIRECTION INPUT ;
    USE SIGNAL ;
    PORT
      LAYER M4 ;
        RECT  86.316 16.656 86.4 16.68 ;
    END
  END td[34]
  PIN td[35]
    DIRECTION INPUT ;
    USE SIGNAL ;
    PORT
      LAYER M4 ;
        RECT  86.316 17.04 86.4 17.064 ;
    END
  END td[35]
  PIN td[36]
    DIRECTION INPUT ;
    USE SIGNAL ;
    PORT
      LAYER M4 ;
        RECT  86.316 17.472 86.4 17.496 ;
    END
  END td[36]
  PIN td[37]
    DIRECTION INPUT ;
    USE SIGNAL ;
    PORT
      LAYER M4 ;
        RECT  86.316 17.904 86.4 17.928 ;
    END
  END td[37]
  PIN td[38]
    DIRECTION INPUT ;
    USE SIGNAL ;
    PORT
      LAYER M4 ;
        RECT  86.316 18.336 86.4 18.36 ;
    END
  END td[38]
  PIN td[39]
    DIRECTION INPUT ;
    USE SIGNAL ;
    PORT
      LAYER M4 ;
        RECT  86.316 18.72 86.4 18.744 ;
    END
  END td[39]
  PIN td[3]
    DIRECTION INPUT ;
    USE SIGNAL ;
    PORT
      LAYER M4 ;
        RECT  86.316 3.6 86.4 3.624 ;
    END
  END td[3]
  PIN td[40]
    DIRECTION INPUT ;
    USE SIGNAL ;
    PORT
      LAYER M4 ;
        RECT  86.316 19.152 86.4 19.176 ;
    END
  END td[40]
  PIN td[41]
    DIRECTION INPUT ;
    USE SIGNAL ;
    PORT
      LAYER M4 ;
        RECT  86.316 19.584 86.4 19.608 ;
    END
  END td[41]
  PIN td[42]
    DIRECTION INPUT ;
    USE SIGNAL ;
    PORT
      LAYER M4 ;
        RECT  86.316 20.016 86.4 20.04 ;
    END
  END td[42]
  PIN td[43]
    DIRECTION INPUT ;
    USE SIGNAL ;
    PORT
      LAYER M4 ;
        RECT  86.316 20.4 86.4 20.424 ;
    END
  END td[43]
  PIN td[44]
    DIRECTION INPUT ;
    USE SIGNAL ;
    PORT
      LAYER M4 ;
        RECT  86.316 20.832 86.4 20.856 ;
    END
  END td[44]
  PIN td[45]
    DIRECTION INPUT ;
    USE SIGNAL ;
    PORT
      LAYER M4 ;
        RECT  86.316 21.264 86.4 21.288 ;
    END
  END td[45]
  PIN td[46]
    DIRECTION INPUT ;
    USE SIGNAL ;
    PORT
      LAYER M4 ;
        RECT  86.316 21.696 86.4 21.72 ;
    END
  END td[46]
  PIN td[47]
    DIRECTION INPUT ;
    USE SIGNAL ;
    PORT
      LAYER M4 ;
        RECT  86.316 22.08 86.4 22.104 ;
    END
  END td[47]
  PIN td[48]
    DIRECTION INPUT ;
    USE SIGNAL ;
    PORT
      LAYER M4 ;
        RECT  86.316 22.512 86.4 22.536 ;
    END
  END td[48]
  PIN td[49]
    DIRECTION INPUT ;
    USE SIGNAL ;
    PORT
      LAYER M4 ;
        RECT  86.316 22.944 86.4 22.968 ;
    END
  END td[49]
  PIN td[4]
    DIRECTION INPUT ;
    USE SIGNAL ;
    PORT
      LAYER M4 ;
        RECT  86.316 4.032 86.4 4.056 ;
    END
  END td[4]
  PIN td[50]
    DIRECTION INPUT ;
    USE SIGNAL ;
    PORT
      LAYER M4 ;
        RECT  86.316 23.376 86.4 23.4 ;
    END
  END td[50]
  PIN td[51]
    DIRECTION INPUT ;
    USE SIGNAL ;
    PORT
      LAYER M4 ;
        RECT  86.316 23.76 86.4 23.784 ;
    END
  END td[51]
  PIN td[52]
    DIRECTION INPUT ;
    USE SIGNAL ;
    PORT
      LAYER M4 ;
        RECT  86.316 24.192 86.4 24.216 ;
    END
  END td[52]
  PIN td[53]
    DIRECTION INPUT ;
    USE SIGNAL ;
    PORT
      LAYER M4 ;
        RECT  86.316 24.624 86.4 24.648 ;
    END
  END td[53]
  PIN td[54]
    DIRECTION INPUT ;
    USE SIGNAL ;
    PORT
      LAYER M4 ;
        RECT  86.316 25.056 86.4 25.08 ;
    END
  END td[54]
  PIN td[55]
    DIRECTION INPUT ;
    USE SIGNAL ;
    PORT
      LAYER M4 ;
        RECT  86.316 25.44 86.4 25.464 ;
    END
  END td[55]
  PIN td[56]
    DIRECTION INPUT ;
    USE SIGNAL ;
    PORT
      LAYER M4 ;
        RECT  86.316 25.872 86.4 25.896 ;
    END
  END td[56]
  PIN td[57]
    DIRECTION INPUT ;
    USE SIGNAL ;
    PORT
      LAYER M4 ;
        RECT  86.316 26.304 86.4 26.328 ;
    END
  END td[57]
  PIN td[58]
    DIRECTION INPUT ;
    USE SIGNAL ;
    PORT
      LAYER M4 ;
        RECT  86.316 26.736 86.4 26.76 ;
    END
  END td[58]
  PIN td[59]
    DIRECTION INPUT ;
    USE SIGNAL ;
    PORT
      LAYER M4 ;
        RECT  86.316 27.12 86.4 27.144 ;
    END
  END td[59]
  PIN td[5]
    DIRECTION INPUT ;
    USE SIGNAL ;
    PORT
      LAYER M4 ;
        RECT  86.316 4.464 86.4 4.488 ;
    END
  END td[5]
  PIN td[60]
    DIRECTION INPUT ;
    USE SIGNAL ;
    PORT
      LAYER M4 ;
        RECT  86.316 27.552 86.4 27.576 ;
    END
  END td[60]
  PIN td[61]
    DIRECTION INPUT ;
    USE SIGNAL ;
    PORT
      LAYER M4 ;
        RECT  86.316 27.984 86.4 28.008 ;
    END
  END td[61]
  PIN td[62]
    DIRECTION INPUT ;
    USE SIGNAL ;
    PORT
      LAYER M4 ;
        RECT  86.316 28.416 86.4 28.44 ;
    END
  END td[62]
  PIN td[63]
    DIRECTION INPUT ;
    USE SIGNAL ;
    PORT
      LAYER M4 ;
        RECT  86.316 28.8 86.4 28.824 ;
    END
  END td[63]
  PIN td[64]
    DIRECTION INPUT ;
    USE SIGNAL ;
    PORT
      LAYER M4 ;
        RECT  86.316 29.232 86.4 29.256 ;
    END
  END td[64]
  PIN td[65]
    DIRECTION INPUT ;
    USE SIGNAL ;
    PORT
      LAYER M4 ;
        RECT  86.316 29.664 86.4 29.688 ;
    END
  END td[65]
  PIN td[66]
    DIRECTION INPUT ;
    USE SIGNAL ;
    PORT
      LAYER M4 ;
        RECT  86.316 30.096 86.4 30.12 ;
    END
  END td[66]
  PIN td[67]
    DIRECTION INPUT ;
    USE SIGNAL ;
    PORT
      LAYER M4 ;
        RECT  86.316 30.48 86.4 30.504 ;
    END
  END td[67]
  PIN td[68]
    DIRECTION INPUT ;
    USE SIGNAL ;
    PORT
      LAYER M4 ;
        RECT  86.316 30.912 86.4 30.936 ;
    END
  END td[68]
  PIN td[69]
    DIRECTION INPUT ;
    USE SIGNAL ;
    PORT
      LAYER M4 ;
        RECT  86.316 31.344 86.4 31.368 ;
    END
  END td[69]
  PIN td[6]
    DIRECTION INPUT ;
    USE SIGNAL ;
    PORT
      LAYER M4 ;
        RECT  86.316 4.896 86.4 4.92 ;
    END
  END td[6]
  PIN td[70]
    DIRECTION INPUT ;
    USE SIGNAL ;
    PORT
      LAYER M4 ;
        RECT  86.316 31.776 86.4 31.8 ;
    END
  END td[70]
  PIN td[71]
    DIRECTION INPUT ;
    USE SIGNAL ;
    PORT
      LAYER M4 ;
        RECT  86.316 32.16 86.4 32.184 ;
    END
  END td[71]
  PIN td[72]
    DIRECTION INPUT ;
    USE SIGNAL ;
    PORT
      LAYER M4 ;
        RECT  86.316 32.592 86.4 32.616 ;
    END
  END td[72]
  PIN td[73]
    DIRECTION INPUT ;
    USE SIGNAL ;
    PORT
      LAYER M4 ;
        RECT  86.316 33.024 86.4 33.048 ;
    END
  END td[73]
  PIN td[74]
    DIRECTION INPUT ;
    USE SIGNAL ;
    PORT
      LAYER M4 ;
        RECT  86.316 33.456 86.4 33.48 ;
    END
  END td[74]
  PIN td[75]
    DIRECTION INPUT ;
    USE SIGNAL ;
    PORT
      LAYER M4 ;
        RECT  86.316 33.84 86.4 33.864 ;
    END
  END td[75]
  PIN td[76]
    DIRECTION INPUT ;
    USE SIGNAL ;
    PORT
      LAYER M4 ;
        RECT  86.316 34.272 86.4 34.296 ;
    END
  END td[76]
  PIN td[77]
    DIRECTION INPUT ;
    USE SIGNAL ;
    PORT
      LAYER M4 ;
        RECT  86.316 34.704 86.4 34.728 ;
    END
  END td[77]
  PIN td[78]
    DIRECTION INPUT ;
    USE SIGNAL ;
    PORT
      LAYER M4 ;
        RECT  86.316 35.136 86.4 35.16 ;
    END
  END td[78]
  PIN td[79]
    DIRECTION INPUT ;
    USE SIGNAL ;
    PORT
      LAYER M4 ;
        RECT  86.316 35.52 86.4 35.544 ;
    END
  END td[79]
  PIN td[7]
    DIRECTION INPUT ;
    USE SIGNAL ;
    PORT
      LAYER M4 ;
        RECT  86.316 5.28 86.4 5.304 ;
    END
  END td[7]
  PIN td[80]
    DIRECTION INPUT ;
    USE SIGNAL ;
    PORT
      LAYER M4 ;
        RECT  86.316 35.952 86.4 35.976 ;
    END
  END td[80]
  PIN td[81]
    DIRECTION INPUT ;
    USE SIGNAL ;
    PORT
      LAYER M4 ;
        RECT  86.316 36.384 86.4 36.408 ;
    END
  END td[81]
  PIN td[82]
    DIRECTION INPUT ;
    USE SIGNAL ;
    PORT
      LAYER M4 ;
        RECT  86.316 36.816 86.4 36.84 ;
    END
  END td[82]
  PIN td[83]
    DIRECTION INPUT ;
    USE SIGNAL ;
    PORT
      LAYER M4 ;
        RECT  86.316 37.2 86.4 37.224 ;
    END
  END td[83]
  PIN td[84]
    DIRECTION INPUT ;
    USE SIGNAL ;
    PORT
      LAYER M4 ;
        RECT  86.316 37.632 86.4 37.656 ;
    END
  END td[84]
  PIN td[85]
    DIRECTION INPUT ;
    USE SIGNAL ;
    PORT
      LAYER M4 ;
        RECT  86.316 38.064 86.4 38.088 ;
    END
  END td[85]
  PIN td[86]
    DIRECTION INPUT ;
    USE SIGNAL ;
    PORT
      LAYER M4 ;
        RECT  86.316 38.496 86.4 38.52 ;
    END
  END td[86]
  PIN td[87]
    DIRECTION INPUT ;
    USE SIGNAL ;
    PORT
      LAYER M4 ;
        RECT  86.316 38.88 86.4 38.904 ;
    END
  END td[87]
  PIN td[88]
    DIRECTION INPUT ;
    USE SIGNAL ;
    PORT
      LAYER M4 ;
        RECT  86.316 39.312 86.4 39.336 ;
    END
  END td[88]
  PIN td[89]
    DIRECTION INPUT ;
    USE SIGNAL ;
    PORT
      LAYER M4 ;
        RECT  86.316 39.744 86.4 39.768 ;
    END
  END td[89]
  PIN td[8]
    DIRECTION INPUT ;
    USE SIGNAL ;
    PORT
      LAYER M4 ;
        RECT  86.316 5.712 86.4 5.736 ;
    END
  END td[8]
  PIN td[90]
    DIRECTION INPUT ;
    USE SIGNAL ;
    PORT
      LAYER M4 ;
        RECT  86.316 40.176 86.4 40.2 ;
    END
  END td[90]
  PIN td[91]
    DIRECTION INPUT ;
    USE SIGNAL ;
    PORT
      LAYER M4 ;
        RECT  86.316 40.56 86.4 40.584 ;
    END
  END td[91]
  PIN td[92]
    DIRECTION INPUT ;
    USE SIGNAL ;
    PORT
      LAYER M4 ;
        RECT  86.316 40.992 86.4 41.016 ;
    END
  END td[92]
  PIN td[93]
    DIRECTION INPUT ;
    USE SIGNAL ;
    PORT
      LAYER M4 ;
        RECT  86.316 41.424 86.4 41.448 ;
    END
  END td[93]
  PIN td[94]
    DIRECTION INPUT ;
    USE SIGNAL ;
    PORT
      LAYER M4 ;
        RECT  86.316 41.856 86.4 41.88 ;
    END
  END td[94]
  PIN td[95]
    DIRECTION INPUT ;
    USE SIGNAL ;
    PORT
      LAYER M4 ;
        RECT  86.316 42.24 86.4 42.264 ;
    END
  END td[95]
  PIN td[96]
    DIRECTION INPUT ;
    USE SIGNAL ;
    PORT
      LAYER M4 ;
        RECT  86.316 42.672 86.4 42.696 ;
    END
  END td[96]
  PIN td[97]
    DIRECTION INPUT ;
    USE SIGNAL ;
    PORT
      LAYER M4 ;
        RECT  86.316 43.104 86.4 43.128 ;
    END
  END td[97]
  PIN td[98]
    DIRECTION INPUT ;
    USE SIGNAL ;
    PORT
      LAYER M4 ;
        RECT  86.316 43.536 86.4 43.56 ;
    END
  END td[98]
  PIN td[99]
    DIRECTION INPUT ;
    USE SIGNAL ;
    PORT
      LAYER M4 ;
        RECT  86.316 43.92 86.4 43.944 ;
    END
  END td[99]
  PIN td[9]
    DIRECTION INPUT ;
    USE SIGNAL ;
    PORT
      LAYER M4 ;
        RECT  86.316 6.144 86.4 6.168 ;
    END
  END td[9]
  PIN tvk
    DIRECTION INPUT ;
    USE SIGNAL ;
    PORT
      LAYER M5 ;
        RECT  30.768 64.716 30.792 64.8 ;
    END
    PORT
      LAYER M5 ;
        RECT  30.768 64.691 30.792 64.784 ;
    END
  END tvk
  PIN VDD
    DIRECTION INOUT ;
    USE POWER ;
    PORT
      LAYER M5 ;
        RECT  83.592 2.151 83.712 62.649 ;
        RECT  78.192 2.151 78.312 62.649 ;
        RECT  72.792 2.151 72.912 62.649 ;
        RECT  67.392 2.151 67.512 62.649 ;
        RECT  61.992 2.151 62.112 62.649 ;
        RECT  56.592 2.151 56.712 62.649 ;
        RECT  51.192 2.151 51.312 62.649 ;
        RECT  45.792 2.151 45.912 62.649 ;
        RECT  40.392 2.151 40.512 62.649 ;
        RECT  34.992 2.151 35.112 62.649 ;
        RECT  29.592 2.151 29.712 62.649 ;
        RECT  24.192 2.151 24.312 62.649 ;
        RECT  18.792 2.151 18.912 62.649 ;
        RECT  13.392 2.151 13.512 62.649 ;
        RECT  7.992 2.151 8.112 62.649 ;
        RECT  2.592 2.151 2.712 62.649 ;
    END
  END VDD
  PIN VSS
    DIRECTION INOUT ;
    USE GROUND ;
    PORT
      LAYER M5 ;
        RECT  83.4 2.137 83.52 62.663 ;
        RECT  78 2.137 78.12 62.663 ;
        RECT  72.6 2.137 72.72 62.663 ;
        RECT  67.2 2.137 67.32 62.663 ;
        RECT  61.8 2.137 61.92 62.663 ;
        RECT  56.4 2.137 56.52 62.663 ;
        RECT  51 2.137 51.12 62.663 ;
        RECT  45.6 2.137 45.72 62.663 ;
        RECT  40.2 2.137 40.32 62.663 ;
        RECT  34.8 2.137 34.92 62.663 ;
        RECT  29.4 2.137 29.52 62.663 ;
        RECT  24 2.137 24.12 62.663 ;
        RECT  18.6 2.137 18.72 62.663 ;
        RECT  13.2 2.137 13.32 62.663 ;
        RECT  7.8 2.137 7.92 62.663 ;
        RECT  2.4 2.137 2.52 62.663 ;
    END
  END VSS
  # OT_OBS_CLOSED layer=M5 d_um=1.536 added=125
  OBS
    LAYER RVTN ;
     RECT  2.16 2.16 84.24 2.295 ;
     RECT  2.16 2.565 84.24 2.835 ;
     RECT  2.16 3.105 84.24 3.375 ;
     RECT  2.16 3.645 84.24 3.915 ;
     RECT  2.16 4.185 84.24 4.455 ;
     RECT  2.16 4.725 84.24 4.995 ;
     RECT  2.16 5.265 84.24 5.535 ;
     RECT  2.16 5.805 84.24 6.075 ;
     RECT  2.16 6.345 84.24 6.615 ;
     RECT  2.16 6.885 84.24 7.155 ;
     RECT  2.16 7.425 84.24 7.695 ;
     RECT  2.16 7.965 84.24 8.235 ;
     RECT  2.16 8.505 84.24 8.775 ;
     RECT  2.16 9.045 84.24 9.315 ;
     RECT  2.16 9.585 84.24 9.855 ;
     RECT  2.16 10.125 84.24 10.395 ;
     RECT  2.16 10.665 84.24 10.935 ;
     RECT  2.16 11.205 84.24 11.475 ;
     RECT  2.16 11.745 84.24 12.015 ;
     RECT  2.16 12.285 84.24 12.555 ;
     RECT  2.16 12.825 84.24 13.095 ;
     RECT  2.16 13.365 84.24 13.635 ;
     RECT  2.16 13.905 84.24 14.175 ;
     RECT  2.16 14.445 84.24 14.715 ;
     RECT  2.16 14.985 84.24 15.255 ;
     RECT  2.16 15.525 84.24 15.795 ;
     RECT  2.16 16.065 84.24 16.335 ;
     RECT  2.16 16.605 84.24 16.875 ;
     RECT  2.16 17.145 84.24 17.415 ;
     RECT  2.16 17.685 84.24 17.955 ;
     RECT  2.16 18.225 84.24 18.495 ;
     RECT  2.16 18.765 84.24 19.035 ;
     RECT  2.16 19.305 84.24 19.575 ;
     RECT  2.16 19.845 84.24 20.115 ;
     RECT  2.16 20.385 84.24 20.655 ;
     RECT  2.16 20.925 84.24 21.195 ;
     RECT  2.16 21.465 84.24 21.735 ;
     RECT  2.16 22.005 84.24 22.275 ;
     RECT  2.16 22.545 84.24 22.815 ;
     RECT  2.16 23.085 84.24 23.355 ;
     RECT  2.16 23.625 84.24 23.895 ;
     RECT  2.16 24.165 84.24 24.435 ;
     RECT  2.16 24.705 84.24 24.975 ;
     RECT  2.16 25.245 84.24 25.515 ;
     RECT  2.16 25.785 84.24 26.055 ;
     RECT  2.16 26.325 84.24 26.595 ;
     RECT  2.16 26.865 84.24 27.135 ;
     RECT  2.16 27.405 84.24 27.675 ;
     RECT  2.16 27.945 84.24 28.215 ;
     RECT  2.16 28.485 84.24 28.755 ;
     RECT  2.16 29.025 84.24 29.295 ;
     RECT  2.16 29.565 84.24 29.835 ;
     RECT  2.16 30.105 84.24 30.375 ;
     RECT  2.16 30.645 84.24 30.915 ;
     RECT  2.16 31.185 84.24 31.455 ;
     RECT  2.16 31.725 84.24 31.995 ;
     RECT  2.16 32.265 84.24 32.535 ;
     RECT  2.16 32.805 84.24 33.075 ;
     RECT  2.16 33.345 84.24 33.615 ;
     RECT  2.16 33.885 84.24 34.155 ;
     RECT  2.16 34.425 84.24 34.695 ;
     RECT  2.16 34.965 84.24 35.235 ;
     RECT  2.16 35.505 84.24 35.775 ;
     RECT  2.16 36.045 84.24 36.315 ;
     RECT  2.16 36.585 84.24 36.855 ;
     RECT  2.16 37.125 84.24 37.395 ;
     RECT  2.16 37.665 84.24 37.935 ;
     RECT  2.16 38.205 84.24 38.475 ;
     RECT  2.16 38.745 84.24 39.015 ;
     RECT  2.16 39.285 84.24 39.555 ;
     RECT  2.16 39.825 84.24 40.095 ;
     RECT  2.16 40.365 84.24 40.635 ;
     RECT  2.16 40.905 84.24 41.175 ;
     RECT  2.16 41.445 84.24 41.715 ;
     RECT  2.16 41.985 84.24 42.255 ;
     RECT  2.16 42.525 84.24 42.795 ;
     RECT  2.16 43.065 84.24 43.335 ;
     RECT  2.16 43.605 84.24 43.875 ;
     RECT  2.16 44.145 84.24 44.415 ;
     RECT  2.16 44.685 84.24 44.955 ;
     RECT  2.16 45.225 84.24 45.495 ;
     RECT  2.16 45.765 84.24 46.035 ;
     RECT  2.16 46.305 84.24 46.575 ;
     RECT  2.16 46.845 84.24 47.115 ;
     RECT  2.16 47.385 84.24 47.655 ;
     RECT  2.16 47.925 84.24 48.195 ;
     RECT  2.16 48.465 84.24 48.735 ;
     RECT  2.16 49.005 84.24 49.275 ;
     RECT  2.16 49.545 84.24 49.815 ;
     RECT  2.16 50.085 84.24 50.355 ;
     RECT  2.16 50.625 84.24 50.895 ;
     RECT  2.16 51.165 84.24 51.435 ;
     RECT  2.16 51.705 84.24 51.975 ;
     RECT  2.16 52.245 84.24 52.515 ;
     RECT  2.16 52.785 84.24 53.055 ;
     RECT  2.16 53.325 84.24 53.595 ;
     RECT  2.16 53.865 84.24 54.135 ;
     RECT  2.16 54.405 84.24 54.675 ;
     RECT  2.16 54.945 84.24 55.215 ;
     RECT  2.16 55.485 84.24 55.755 ;
     RECT  2.16 56.025 84.24 56.295 ;
     RECT  2.16 56.565 84.24 56.835 ;
     RECT  2.16 57.105 84.24 57.375 ;
     RECT  2.16 57.645 84.24 57.915 ;
     RECT  2.16 58.185 84.24 58.455 ;
     RECT  2.16 58.725 84.24 58.995 ;
     RECT  2.16 59.265 84.24 59.535 ;
     RECT  2.16 59.805 84.24 60.075 ;
     RECT  2.16 60.345 84.24 60.615 ;
     RECT  2.16 60.885 84.24 61.155 ;
     RECT  2.16 61.425 84.24 61.695 ;
     RECT  2.16 61.965 84.24 62.235 ;
     RECT  2.16 62.505 84.24 62.64 ;
    LAYER RVTP ;
     RECT  2.16 2.295 84.24 2.565 ;
     RECT  2.16 2.835 84.24 3.105 ;
     RECT  2.16 3.375 84.24 3.645 ;
     RECT  2.16 3.915 84.24 4.185 ;
     RECT  2.16 4.455 84.24 4.725 ;
     RECT  2.16 4.995 84.24 5.265 ;
     RECT  2.16 5.535 84.24 5.805 ;
     RECT  2.16 6.075 84.24 6.345 ;
     RECT  2.16 6.615 84.24 6.885 ;
     RECT  2.16 7.155 84.24 7.425 ;
     RECT  2.16 7.695 84.24 7.965 ;
     RECT  2.16 8.235 84.24 8.505 ;
     RECT  2.16 8.775 84.24 9.045 ;
     RECT  2.16 9.315 84.24 9.585 ;
     RECT  2.16 9.855 84.24 10.125 ;
     RECT  2.16 10.395 84.24 10.665 ;
     RECT  2.16 10.935 84.24 11.205 ;
     RECT  2.16 11.475 84.24 11.745 ;
     RECT  2.16 12.015 84.24 12.285 ;
     RECT  2.16 12.555 84.24 12.825 ;
     RECT  2.16 13.095 84.24 13.365 ;
     RECT  2.16 13.635 84.24 13.905 ;
     RECT  2.16 14.175 84.24 14.445 ;
     RECT  2.16 14.715 84.24 14.985 ;
     RECT  2.16 15.255 84.24 15.525 ;
     RECT  2.16 15.795 84.24 16.065 ;
     RECT  2.16 16.335 84.24 16.605 ;
     RECT  2.16 16.875 84.24 17.145 ;
     RECT  2.16 17.415 84.24 17.685 ;
     RECT  2.16 17.955 84.24 18.225 ;
     RECT  2.16 18.495 84.24 18.765 ;
     RECT  2.16 19.035 84.24 19.305 ;
     RECT  2.16 19.575 84.24 19.845 ;
     RECT  2.16 20.115 84.24 20.385 ;
     RECT  2.16 20.655 84.24 20.925 ;
     RECT  2.16 21.195 84.24 21.465 ;
     RECT  2.16 21.735 84.24 22.005 ;
     RECT  2.16 22.275 84.24 22.545 ;
     RECT  2.16 22.815 84.24 23.085 ;
     RECT  2.16 23.355 84.24 23.625 ;
     RECT  2.16 23.895 84.24 24.165 ;
     RECT  2.16 24.435 84.24 24.705 ;
     RECT  2.16 24.975 84.24 25.245 ;
     RECT  2.16 25.515 84.24 25.785 ;
     RECT  2.16 26.055 84.24 26.325 ;
     RECT  2.16 26.595 84.24 26.865 ;
     RECT  2.16 27.135 84.24 27.405 ;
     RECT  2.16 27.675 84.24 27.945 ;
     RECT  2.16 28.215 84.24 28.485 ;
     RECT  2.16 28.755 84.24 29.025 ;
     RECT  2.16 29.295 84.24 29.565 ;
     RECT  2.16 29.835 84.24 30.105 ;
     RECT  2.16 30.375 84.24 30.645 ;
     RECT  2.16 30.915 84.24 31.185 ;
     RECT  2.16 31.455 84.24 31.725 ;
     RECT  2.16 31.995 84.24 32.265 ;
     RECT  2.16 32.535 84.24 32.805 ;
     RECT  2.16 33.075 84.24 33.345 ;
     RECT  2.16 33.615 84.24 33.885 ;
     RECT  2.16 34.155 84.24 34.425 ;
     RECT  2.16 34.695 84.24 34.965 ;
     RECT  2.16 35.235 84.24 35.505 ;
     RECT  2.16 35.775 84.24 36.045 ;
     RECT  2.16 36.315 84.24 36.585 ;
     RECT  2.16 36.855 84.24 37.125 ;
     RECT  2.16 37.395 84.24 37.665 ;
     RECT  2.16 37.935 84.24 38.205 ;
     RECT  2.16 38.475 84.24 38.745 ;
     RECT  2.16 39.015 84.24 39.285 ;
     RECT  2.16 39.555 84.24 39.825 ;
     RECT  2.16 40.095 84.24 40.365 ;
     RECT  2.16 40.635 84.24 40.905 ;
     RECT  2.16 41.175 84.24 41.445 ;
     RECT  2.16 41.715 84.24 41.985 ;
     RECT  2.16 42.255 84.24 42.525 ;
     RECT  2.16 42.795 84.24 43.065 ;
     RECT  2.16 43.335 84.24 43.605 ;
     RECT  2.16 43.875 84.24 44.145 ;
     RECT  2.16 44.415 84.24 44.685 ;
     RECT  2.16 44.955 84.24 45.225 ;
     RECT  2.16 45.495 84.24 45.765 ;
     RECT  2.16 46.035 84.24 46.305 ;
     RECT  2.16 46.575 84.24 46.845 ;
     RECT  2.16 47.115 84.24 47.385 ;
     RECT  2.16 47.655 84.24 47.925 ;
     RECT  2.16 48.195 84.24 48.465 ;
     RECT  2.16 48.735 84.24 49.005 ;
     RECT  2.16 49.275 84.24 49.545 ;
     RECT  2.16 49.815 84.24 50.085 ;
     RECT  2.16 50.355 84.24 50.625 ;
     RECT  2.16 50.895 84.24 51.165 ;
     RECT  2.16 51.435 84.24 51.705 ;
     RECT  2.16 51.975 84.24 52.245 ;
     RECT  2.16 52.515 84.24 52.785 ;
     RECT  2.16 53.055 84.24 53.325 ;
     RECT  2.16 53.595 84.24 53.865 ;
     RECT  2.16 54.135 84.24 54.405 ;
     RECT  2.16 54.675 84.24 54.945 ;
     RECT  2.16 55.215 84.24 55.485 ;
     RECT  2.16 55.755 84.24 56.025 ;
     RECT  2.16 56.295 84.24 56.565 ;
     RECT  2.16 56.835 84.24 57.105 ;
     RECT  2.16 57.375 84.24 57.645 ;
     RECT  2.16 57.915 84.24 58.185 ;
     RECT  2.16 58.455 84.24 58.725 ;
     RECT  2.16 58.995 84.24 59.265 ;
     RECT  2.16 59.535 84.24 59.805 ;
     RECT  2.16 60.075 84.24 60.345 ;
     RECT  2.16 60.615 84.24 60.885 ;
     RECT  2.16 61.155 84.24 61.425 ;
     RECT  2.16 61.695 84.24 61.965 ;
     RECT  2.16 62.235 84.24 62.505 ;
    LAYER M1 ;
     RECT  2.16 2.151 84.24 62.649 ;
    LAYER M2 ;
     RECT  0.103 6.822 0.535 6.84 ;
     RECT  0.103 43.848 0.535 43.866 ;
     RECT  0.535 6.156 2.16 6.84 ;
     RECT  0.103 14.454 2.16 14.472 ;
     RECT  0.535 16.416 2.16 16.434 ;
     RECT  0.103 18.198 2.16 18.216 ;
     RECT  0.535 19.926 2.16 19.944 ;
     RECT  0.535 21.546 2.16 21.564 ;
     RECT  0.535 24.408 2.16 24.426 ;
     RECT  0.103 28.998 2.16 29.016 ;
     RECT  0.535 31.266 2.16 31.284 ;
     RECT  0.535 36.936 2.16 37.494 ;
     RECT  0.535 38.484 2.16 38.502 ;
     RECT  0.103 40.266 2.16 40.284 ;
     RECT  0.535 43.308 2.16 43.866 ;
     RECT  0.535 45 2.16 45.018 ;
     RECT  0.535 48.438 2.16 48.456 ;
     RECT  0.103 51.786 2.16 51.804 ;
     RECT  0.535 52.866 2.16 53.424 ;
     RECT  0.535 54.954 2.16 54.972 ;
     RECT  0.103 56.304 2.16 56.322 ;
     RECT  0.535 57.546 2.16 57.564 ;
     RECT  2.16 2.151 40.567 62.649 ;
     RECT  40.567 2.151 43.871 62.694 ;
     RECT  43.871 2.151 84.24 62.649 ;
     RECT  84.24 8.712 84.875 13.392 ;
     RECT  84.24 18 84.875 19.332 ;
     RECT  84.24 20.16 84.875 27.936 ;
     RECT  84.24 28.8 84.875 32.256 ;
     RECT  84.24 33.048 84.875 36.108 ;
     RECT  84.24 39.762 84.875 44.136 ;
     RECT  84.24 51.21 84.875 53.586 ;
     RECT  84.24 59.58 84.875 59.832 ;
     RECT  84.24 2.538 84.911 3.87 ;
     RECT  84.24 4.734 84.911 6.03 ;
     RECT  84.24 6.822 84.911 7.92 ;
     RECT  84.875 8.712 84.911 9.612 ;
     RECT  84.875 10.71 84.911 13.32 ;
     RECT  84.24 14.148 84.911 17.1 ;
     RECT  84.875 18 84.911 18.45 ;
     RECT  84.875 19.242 84.911 19.332 ;
     RECT  84.875 20.16 84.911 20.178 ;
     RECT  84.875 21.132 84.911 27.936 ;
     RECT  84.875 28.8 84.911 28.818 ;
     RECT  84.875 29.772 84.911 32.256 ;
     RECT  84.875 33.048 84.911 34.11 ;
     RECT  84.875 34.938 84.911 36.108 ;
     RECT  84.24 36.9 84.911 39.006 ;
     RECT  84.875 39.762 84.911 42.48 ;
     RECT  84.875 43.308 84.911 44.136 ;
     RECT  84.24 44.892 84.911 45.756 ;
     RECT  84.24 46.548 84.911 50.31 ;
     RECT  84.875 51.21 84.911 52.2 ;
     RECT  84.24 54.378 84.911 58.716 ;
     RECT  84.875 59.58 84.911 59.76 ;
     RECT  84.24 60.588 84.911 62.46 ;
     RECT  84.911 31.662 84.947 32.256 ;
     RECT  84.911 4.734 85.127 4.986 ;
     RECT  84.911 34.938 85.127 34.956 ;
     RECT  84.911 16.038 85.379 16.29 ;
     RECT  84.911 43.308 85.379 43.56 ;
     RECT  84.911 54.918 85.379 55.476 ;
     RECT  84.911 56.268 85.379 56.556 ;
     RECT  84.911 60.588 85.379 60.606 ;
     RECT  84.911 2.538 85.487 2.556 ;
     RECT  84.911 3.348 85.487 3.87 ;
     RECT  85.127 4.968 85.487 4.986 ;
     RECT  84.911 6.822 85.487 6.84 ;
     RECT  84.911 7.902 85.487 7.92 ;
     RECT  84.911 8.712 85.487 8.73 ;
     RECT  84.911 11.448 85.487 11.466 ;
     RECT  84.911 12.258 85.487 12.276 ;
     RECT  84.911 13.302 85.487 13.32 ;
     RECT  84.911 14.652 85.487 14.67 ;
     RECT  85.379 16.272 85.487 16.29 ;
     RECT  84.911 17.082 85.487 17.1 ;
     RECT  84.911 18.432 85.487 18.45 ;
     RECT  84.911 19.242 85.487 19.26 ;
     RECT  84.911 21.402 85.487 21.996 ;
     RECT  84.911 22.788 85.487 22.806 ;
     RECT  84.911 23.598 85.487 23.616 ;
     RECT  84.911 24.408 85.487 24.426 ;
     RECT  84.911 25.218 85.487 25.236 ;
     RECT  84.911 26.298 85.487 26.316 ;
     RECT  84.911 27.108 85.487 27.936 ;
     RECT  84.911 29.772 85.487 29.79 ;
     RECT  84.911 30.582 85.487 30.6 ;
     RECT  84.947 32.238 85.487 32.256 ;
     RECT  84.911 33.282 85.487 33.3 ;
     RECT  84.911 34.092 85.487 34.11 ;
     RECT  84.911 35.748 85.487 35.766 ;
     RECT  84.911 37.098 85.487 38.7 ;
     RECT  84.911 40.068 85.487 40.086 ;
     RECT  84.911 41.688 85.487 41.706 ;
     RECT  85.379 43.542 85.487 43.56 ;
     RECT  84.911 45.432 85.487 45.45 ;
     RECT  84.911 46.548 85.487 46.566 ;
     RECT  84.911 47.358 85.487 47.88 ;
     RECT  84.911 49.212 85.487 49.23 ;
     RECT  84.911 50.058 85.487 50.31 ;
     RECT  84.911 51.372 85.487 51.39 ;
     RECT  84.875 52.992 85.487 53.586 ;
     RECT  85.379 55.458 85.487 55.476 ;
     RECT  85.379 56.538 85.487 56.556 ;
     RECT  84.911 57.852 85.487 58.41 ;
     RECT  84.911 59.742 85.487 59.76 ;
     RECT  84.911 61.632 85.487 61.65 ;
     RECT  84.911 62.442 85.487 62.46 ;
     RECT  84.911 9.522 85.523 9.54 ;
     RECT  85.487 37.602 86.315 37.62 ;
    LAYER M3 ;
     RECT  2.415 2.143 2.505 2.227 ;
     RECT  41.148 2.191 41.166 2.263 ;
     RECT  2.412 2.227 2.505 2.285 ;
     RECT  83.415 2.143 83.505 2.335 ;
     RECT  2.415 2.285 2.505 2.347 ;
     RECT  3.276 2.191 3.294 2.347 ;
     RECT  38.52 2.191 39.114 2.371 ;
     RECT  40.215 2.143 40.305 2.371 ;
     RECT  7.815 2.143 7.905 2.413 ;
     RECT  13.215 2.143 13.305 2.413 ;
     RECT  18.615 2.143 18.705 2.413 ;
     RECT  24.015 2.143 24.105 2.413 ;
     RECT  29.415 2.143 29.505 2.413 ;
     RECT  34.815 2.143 34.905 2.413 ;
     RECT  38.52 2.371 40.305 2.413 ;
     RECT  41.148 2.263 41.922 2.413 ;
     RECT  45.615 2.143 45.705 2.413 ;
     RECT  51.015 2.143 51.105 2.413 ;
     RECT  56.415 2.143 56.505 2.413 ;
     RECT  61.815 2.143 61.905 2.413 ;
     RECT  67.215 2.143 67.305 2.413 ;
     RECT  72.615 2.143 72.705 2.413 ;
     RECT  78.015 2.143 78.105 2.413 ;
     RECT  43.74 2.227 43.902 2.461 ;
     RECT  37.512 2.371 37.53 2.497 ;
     RECT  38.52 2.413 41.922 2.497 ;
     RECT  82.62 2.191 82.638 2.525 ;
     RECT  37.512 2.497 41.922 2.533 ;
     RECT  43.632 2.461 44.01 2.533 ;
     RECT  43.632 2.533 44.658 2.605 ;
     RECT  2.415 2.347 3.294 2.641 ;
     RECT  37.296 2.533 42.102 2.641 ;
     RECT  61.815 2.413 62.097 2.641 ;
     RECT  85.464 2.347 85.482 2.641 ;
     RECT  37.116 2.641 42.102 2.731 ;
     RECT  61.815 2.641 62.802 2.759 ;
     RECT  37.116 2.731 42.498 2.767 ;
     RECT  75.636 2.731 75.654 2.767 ;
     RECT  82.404 2.641 82.422 2.767 ;
     RECT  53.208 2.641 53.226 2.779 ;
     RECT  81.936 2.767 82.422 2.795 ;
     RECT  43.56 2.605 44.658 2.831 ;
     RECT  57.492 2.641 57.51 2.831 ;
     RECT  54.72 2.641 54.738 2.911 ;
     RECT  68.436 2.803 68.454 2.911 ;
     RECT  69.48 2.731 69.498 2.911 ;
     RECT  75.636 2.767 75.69 2.911 ;
     RECT  68.4 2.911 69.498 2.939 ;
     RECT  81.936 2.795 81.954 2.939 ;
     RECT  43.56 2.831 44.334 3.001 ;
     RECT  67.215 2.413 67.497 3.001 ;
     RECT  75.492 2.911 75.69 3.001 ;
     RECT  37.044 2.767 42.498 3.019 ;
     RECT  53.208 2.779 53.37 3.029 ;
     RECT  54.288 2.911 54.738 3.029 ;
     RECT  75.492 3.001 75.762 3.029 ;
     RECT  68.4 2.939 69.102 3.065 ;
     RECT  75.636 3.029 75.762 3.065 ;
     RECT  43.488 3.001 44.334 3.101 ;
     RECT  37.044 3.019 42.606 3.109 ;
     RECT  75.672 3.065 75.762 3.137 ;
     RECT  72.615 2.413 72.897 3.145 ;
     RECT  53.316 3.029 53.37 3.173 ;
     RECT  80.964 2.641 80.982 3.173 ;
     RECT  34.815 2.413 35.097 3.181 ;
     RECT  37.044 3.109 42.714 3.181 ;
     RECT  43.488 3.101 44.226 3.181 ;
     RECT  71.928 3.145 72.897 3.181 ;
     RECT  53.316 3.173 53.334 3.197 ;
     RECT  54.72 3.029 54.738 3.209 ;
     RECT  74.664 3.001 74.682 3.209 ;
     RECT  2.415 2.641 3.438 3.211 ;
     RECT  2.304 3.211 3.438 3.299 ;
     RECT  60.48 3.145 60.498 3.299 ;
     RECT  66.708 3.001 67.497 3.299 ;
     RECT  70.74 3.181 72.897 3.299 ;
     RECT  83.415 2.335 84.042 3.299 ;
     RECT  34.776 3.181 35.097 3.371 ;
     RECT  71.496 3.299 72.897 3.371 ;
     RECT  6.264 3.271 6.282 3.403 ;
     RECT  2.304 3.299 2.862 3.407 ;
     RECT  61.815 2.759 62.73 3.407 ;
     RECT  75.744 3.137 75.762 3.407 ;
     RECT  52.236 3.145 52.254 3.437 ;
     RECT  4.572 3.271 4.59 3.451 ;
     RECT  6.264 3.403 6.462 3.451 ;
     RECT  78.015 2.413 78.297 3.451 ;
     RECT  77.58 3.451 78.297 3.541 ;
     RECT  68.4 3.065 68.922 3.569 ;
     RECT  83.415 3.299 83.898 3.577 ;
     RECT  68.4 3.569 68.418 3.605 ;
     RECT  84.888 2.641 85.482 3.629 ;
     RECT  82.836 3.577 83.898 3.641 ;
     RECT  51.015 2.413 51.297 3.685 ;
     RECT  71.928 3.371 72.897 3.685 ;
     RECT  71.928 3.685 73.386 3.721 ;
     RECT  82.836 3.641 83.862 3.721 ;
     RECT  71.928 3.721 73.638 3.749 ;
     RECT  77.58 3.541 78.678 3.811 ;
     RECT  61.815 3.407 62.334 3.839 ;
     RECT  77.58 3.811 78.822 3.839 ;
     RECT  6.228 3.451 6.822 3.847 ;
     RECT  6.228 3.847 6.858 3.875 ;
     RECT  72.144 3.749 73.638 3.875 ;
     RECT  82.764 3.721 83.862 3.875 ;
     RECT  37.044 3.181 44.226 3.883 ;
     RECT  72.144 3.875 73.386 3.911 ;
     RECT  3.924 3.451 4.59 3.919 ;
     RECT  5.364 3.343 5.382 3.919 ;
     RECT  61.815 3.839 62.097 3.919 ;
     RECT  37.044 3.883 44.766 3.92 ;
     RECT  70.74 3.299 70.758 3.947 ;
     RECT  78.015 3.839 78.822 3.947 ;
     RECT  50.364 3.685 51.297 3.965 ;
     RECT  78.015 3.947 78.75 3.983 ;
     RECT  50.508 3.965 51.297 3.991 ;
     RECT  85.464 3.629 85.482 4.061 ;
     RECT  3.924 3.919 5.742 4.109 ;
     RECT  50.508 3.991 51.354 4.109 ;
     RECT  3.924 4.109 5.166 4.145 ;
     RECT  51.015 4.109 51.354 4.145 ;
     RECT  61.272 3.919 62.097 4.145 ;
     RECT  2.376 3.407 2.862 4.157 ;
     RECT  2.415 4.157 2.862 4.225 ;
     RECT  3.924 4.145 5.022 4.225 ;
     RECT  37.044 3.92 44.622 4.225 ;
     RECT  6.84 3.875 6.858 4.253 ;
     RECT  36.972 4.225 44.622 4.261 ;
     RECT  45.615 2.413 45.897 4.261 ;
     RECT  46.764 4.117 46.782 4.261 ;
     RECT  36.9 4.261 44.622 4.351 ;
     RECT  83.415 3.875 83.862 4.495 ;
     RECT  71.208 4.423 71.226 4.603 ;
     RECT  48.24 4.603 48.258 4.621 ;
     RECT  74.376 4.555 74.394 4.621 ;
     RECT  47.88 4.621 48.258 4.649 ;
     RECT  71.208 4.603 71.694 4.649 ;
     RECT  83.415 4.495 84.042 4.649 ;
     RECT  45.615 4.261 46.782 4.651 ;
     RECT  47.88 4.649 47.898 4.685 ;
     RECT  63.612 4.621 63.63 4.685 ;
     RECT  82.62 4.351 82.638 4.685 ;
     RECT  36.864 4.351 44.622 4.729 ;
     RECT  61.815 4.145 62.097 4.729 ;
     RECT  71.208 4.649 71.226 4.729 ;
     RECT  72.615 3.911 73.386 4.729 ;
     RECT  83.415 4.649 83.97 4.757 ;
     RECT  36.864 4.729 44.658 4.765 ;
     RECT  45.615 4.651 46.998 4.765 ;
     RECT  70.704 4.729 71.226 4.801 ;
     RECT  74.376 4.621 74.682 4.801 ;
     RECT  82.152 4.729 82.242 4.801 ;
     RECT  61.815 4.729 62.73 4.829 ;
     RECT  72.615 4.729 73.458 4.829 ;
     RECT  2.415 4.225 5.022 4.891 ;
     RECT  68.796 4.765 68.814 4.891 ;
     RECT  85.104 4.459 85.122 4.891 ;
     RECT  2.304 4.891 5.022 4.919 ;
     RECT  74.34 4.801 74.682 4.919 ;
     RECT  72.615 4.829 73.386 4.927 ;
     RECT  70.128 4.801 71.226 4.955 ;
     RECT  74.34 4.919 74.646 4.955 ;
     RECT  58.536 4.927 58.554 4.963 ;
     RECT  67.215 3.299 67.497 4.963 ;
     RECT  84.888 4.891 85.122 4.963 ;
     RECT  82.116 4.801 82.242 4.991 ;
     RECT  82.116 4.991 82.134 5.027 ;
     RECT  68.796 4.891 68.886 5.063 ;
     RECT  76.824 4.963 76.842 5.071 ;
     RECT  72.144 4.927 73.386 5.099 ;
     RECT  74.52 4.955 74.646 5.099 ;
     RECT  70.128 4.955 70.758 5.117 ;
     RECT  51.015 4.145 51.297 5.161 ;
     RECT  36.756 4.765 46.998 5.189 ;
     RECT  76.824 5.071 77.094 5.225 ;
     RECT  58.536 4.963 58.626 5.269 ;
     RECT  50.688 5.161 51.297 5.297 ;
     RECT  84.888 4.963 85.482 5.309 ;
     RECT  36.756 5.189 46.35 5.333 ;
     RECT  36.756 5.333 46.278 5.369 ;
     RECT  58.032 5.269 58.626 5.459 ;
     RECT  68.544 5.341 68.562 5.459 ;
     RECT  70.56 5.117 70.758 5.459 ;
     RECT  58.428 5.459 58.626 5.467 ;
     RECT  2.304 4.919 4.734 5.495 ;
     RECT  66.708 4.963 67.497 5.495 ;
     RECT  70.56 5.459 70.722 5.603 ;
     RECT  5.832 5.035 5.85 5.701 ;
     RECT  5.292 5.701 5.85 5.741 ;
     RECT  36.972 5.369 46.278 5.765 ;
     RECT  83.415 4.757 83.898 5.801 ;
     RECT  72.144 5.099 72.897 5.845 ;
     RECT  82.116 5.773 82.134 5.873 ;
     RECT  5.436 5.741 5.85 5.881 ;
     RECT  74.628 5.099 74.646 5.881 ;
     RECT  36.972 5.765 45.897 5.999 ;
     RECT  47.304 5.341 47.322 5.999 ;
     RECT  58.428 5.467 58.734 5.999 ;
     RECT  74.628 5.881 74.682 5.999 ;
     RECT  58.716 5.999 58.734 6.007 ;
     RECT  5.436 5.881 6.174 6.079 ;
     RECT  71.856 5.845 72.897 6.091 ;
     RECT  58.716 6.007 58.77 6.107 ;
     RECT  71.64 6.091 72.897 6.151 ;
     RECT  2.304 5.495 4.302 6.173 ;
     RECT  84.888 5.309 84.906 6.173 ;
     RECT  2.415 6.173 4.302 6.241 ;
     RECT  5.436 6.079 6.39 6.269 ;
     RECT  58.716 6.107 58.734 6.269 ;
     RECT  74.664 5.999 74.682 6.269 ;
     RECT  57.78 6.235 57.942 6.275 ;
     RECT  45.576 5.999 45.897 6.341 ;
     RECT  71.568 6.151 72.897 6.341 ;
     RECT  72.108 6.341 72.897 6.413 ;
     RECT  80.388 6.151 80.406 6.413 ;
     RECT  57.924 6.275 57.942 6.539 ;
     RECT  36.972 5.999 44.298 6.575 ;
     RECT  64.944 6.151 64.962 6.575 ;
     RECT  0.54 6.151 0.558 6.605 ;
     RECT  36.972 6.575 38.826 6.619 ;
     RECT  70.02 5.881 70.11 6.619 ;
     RECT  83.415 5.801 83.862 6.655 ;
     RECT  36.936 6.619 38.826 6.691 ;
     RECT  51.015 5.297 51.297 6.691 ;
     RECT  72.396 6.413 72.897 6.691 ;
     RECT  82.656 6.007 82.674 6.691 ;
     RECT  83.415 6.655 84.042 6.691 ;
     RECT  70.02 6.619 70.722 6.719 ;
     RECT  36.828 6.691 38.826 6.763 ;
     RECT  78.015 3.983 78.297 6.781 ;
     RECT  70.02 6.719 70.614 6.808 ;
     RECT  36.756 6.763 38.826 6.809 ;
     RECT  54.648 6.691 54.666 6.809 ;
     RECT  72.396 6.691 73.17 6.809 ;
     RECT  82.656 6.691 84.042 6.809 ;
     RECT  53.712 6.808 53.73 6.845 ;
     RECT  69.588 6.808 70.614 6.845 ;
     RECT  82.656 6.809 83.862 6.845 ;
     RECT  85.464 6.571 85.482 6.845 ;
     RECT  45.615 6.341 45.897 6.859 ;
     RECT  39.888 6.575 44.298 6.907 ;
     RECT  47.664 6.511 47.682 6.925 ;
     RECT  72.615 6.809 73.17 6.925 ;
     RECT  39.888 6.907 44.37 6.953 ;
     RECT  2.415 6.241 4.662 6.961 ;
     RECT  5.436 6.269 5.67 6.961 ;
     RECT  45.615 6.859 46.314 6.961 ;
     RECT  51.015 6.691 51.354 6.961 ;
     RECT  63.216 6.691 63.234 6.961 ;
     RECT  76.428 6.691 76.446 6.961 ;
     RECT  0.108 6.817 0.126 6.989 ;
     RECT  39.888 6.953 44.298 7.079 ;
     RECT  45.615 6.961 46.818 7.079 ;
     RECT  47.664 6.925 48.078 7.079 ;
     RECT  51.015 6.961 51.534 7.079 ;
     RECT  63.216 6.961 63.342 7.079 ;
     RECT  76.428 6.961 76.59 7.079 ;
     RECT  83.232 6.845 83.862 7.079 ;
     RECT  45.615 7.079 46.314 7.115 ;
     RECT  51.015 7.079 51.354 7.115 ;
     RECT  63.216 7.079 63.234 7.115 ;
     RECT  76.428 7.079 76.446 7.115 ;
     RECT  69.732 6.845 70.614 7.187 ;
     RECT  81.504 6.961 81.522 7.187 ;
     RECT  47.664 7.079 47.934 7.231 ;
     RECT  39.888 7.079 44.262 7.259 ;
     RECT  47.268 7.231 47.934 7.259 ;
     RECT  2.415 6.961 5.67 7.349 ;
     RECT  58.464 7.051 58.482 7.349 ;
     RECT  2.415 7.349 5.562 7.385 ;
     RECT  70.092 7.187 70.614 7.385 ;
     RECT  84.888 6.955 84.906 7.387 ;
     RECT  2.415 7.385 4.95 7.421 ;
     RECT  47.268 7.259 47.286 7.421 ;
     RECT  75.204 7.321 75.222 7.429 ;
     RECT  67.215 5.495 67.497 7.435 ;
     RECT  34.815 3.371 35.097 7.501 ;
     RECT  67.215 7.435 67.986 7.501 ;
     RECT  77.976 6.781 78.297 7.501 ;
     RECT  72.615 6.925 73.674 7.591 ;
     RECT  34.776 7.501 35.097 7.619 ;
     RECT  57.744 7.501 57.762 7.619 ;
     RECT  67.215 7.501 68.13 7.619 ;
     RECT  75.204 7.429 75.33 7.619 ;
     RECT  67.215 7.619 67.986 7.655 ;
     RECT  75.204 7.619 75.222 7.655 ;
     RECT  84.852 7.387 84.906 7.691 ;
     RECT  36.792 6.809 38.826 7.699 ;
     RECT  56.415 2.413 56.697 7.735 ;
     RECT  2.415 7.421 4.59 7.771 ;
     RECT  84.888 7.691 84.906 7.819 ;
     RECT  36.792 7.699 38.97 7.861 ;
     RECT  39.888 7.259 44.226 7.861 ;
     RECT  65.16 7.627 65.178 7.889 ;
     RECT  77.904 7.501 78.297 7.889 ;
     RECT  45.615 7.115 45.897 7.897 ;
     RECT  82.116 7.771 82.134 7.925 ;
     RECT  56.415 7.735 56.79 7.997 ;
     RECT  68.724 7.771 68.85 8.033 ;
     RECT  36.252 7.861 44.226 8.041 ;
     RECT  45.615 7.897 45.99 8.041 ;
     RECT  83.376 7.079 83.862 8.041 ;
     RECT  68.724 8.033 68.742 8.159 ;
     RECT  67.215 7.655 67.497 8.167 ;
     RECT  2.304 7.771 4.59 8.311 ;
     RECT  72.615 7.591 73.71 8.311 ;
     RECT  83.376 8.041 83.898 8.311 ;
     RECT  66.708 8.167 67.497 8.339 ;
     RECT  2.304 8.311 4.842 8.401 ;
     RECT  53.352 8.395 53.37 8.401 ;
     RECT  72.615 8.311 74.25 8.401 ;
     RECT  75.096 8.311 75.114 8.401 ;
     RECT  78.015 7.889 78.297 8.401 ;
     RECT  72.615 8.401 75.114 8.429 ;
     RECT  82.224 8.311 83.898 8.429 ;
     RECT  70.704 7.699 70.722 8.491 ;
     RECT  72.615 8.429 74.646 8.525 ;
     RECT  53.352 8.401 53.838 8.537 ;
     RECT  70.704 8.491 70.938 8.537 ;
     RECT  73.656 8.525 74.646 8.537 ;
     RECT  57.924 8.401 57.942 8.545 ;
     RECT  62.892 8.509 62.91 8.581 ;
     RECT  36.252 8.041 45.99 8.699 ;
     RECT  57.924 8.545 58.05 8.699 ;
     RECT  62.892 8.581 63.018 8.699 ;
     RECT  73.656 8.537 74.106 8.699 ;
     RECT  78.015 8.401 78.426 8.699 ;
     RECT  57.924 8.699 57.942 8.735 ;
     RECT  62.892 8.699 62.91 8.735 ;
     RECT  70.992 8.581 71.262 8.735 ;
     RECT  84.888 7.819 85.482 8.735 ;
     RECT  36.648 8.699 45.99 8.771 ;
     RECT  74.088 8.699 74.106 8.771 ;
     RECT  82.224 8.429 82.242 8.807 ;
     RECT  52.272 8.683 52.29 8.851 ;
     RECT  83.415 8.429 83.898 8.851 ;
     RECT  2.304 8.401 5.13 8.879 ;
     RECT  36.72 8.771 45.99 8.879 ;
     RECT  70.992 8.735 71.118 8.879 ;
     RECT  53.352 8.537 53.37 8.909 ;
     RECT  51.015 7.115 51.297 8.941 ;
     RECT  52.236 8.851 52.29 8.941 ;
     RECT  71.1 8.879 71.118 8.969 ;
     RECT  76.932 8.311 76.95 9.005 ;
     RECT  83.415 8.851 84.042 9.005 ;
     RECT  2.415 8.879 5.13 9.041 ;
     RECT  2.415 9.041 4.914 9.113 ;
     RECT  56.415 7.997 56.697 9.121 ;
     RECT  36.792 8.879 45.99 9.239 ;
     RECT  54.9 9.283 54.918 9.355 ;
     RECT  55.728 9.121 56.697 9.355 ;
     RECT  51.015 8.941 52.29 9.391 ;
     RECT  53.028 9.319 53.046 9.391 ;
     RECT  67.215 8.339 67.497 9.391 ;
     RECT  54.9 9.355 56.697 9.451 ;
     RECT  36.792 9.239 46.53 9.481 ;
     RECT  84.888 8.735 84.906 9.499 ;
     RECT  36.792 9.481 46.71 9.509 ;
     RECT  75.204 9.211 75.222 9.509 ;
     RECT  78.015 8.699 78.297 9.517 ;
     RECT  84.852 9.499 84.906 9.517 ;
     RECT  39.06 9.509 39.078 9.545 ;
     RECT  39.888 9.509 46.71 9.545 ;
     RECT  82.116 9.391 82.134 9.545 ;
     RECT  54.756 9.451 56.697 9.553 ;
     RECT  54.324 9.553 56.697 9.589 ;
     RECT  58.5 9.481 58.518 9.589 ;
     RECT  54.18 9.589 56.697 9.617 ;
     RECT  47.592 9.391 48.186 9.625 ;
     RECT  39.96 9.545 46.71 9.661 ;
     RECT  47.592 9.625 48.654 9.661 ;
     RECT  54.18 9.617 55.53 9.661 ;
     RECT  71.352 9.643 71.37 9.661 ;
     RECT  39.96 9.661 49.122 9.689 ;
     RECT  78.015 9.517 78.642 9.751 ;
     RECT  67.215 9.391 68.418 9.779 ;
     RECT  72.615 8.525 72.897 9.781 ;
     RECT  42.768 9.689 49.122 9.787 ;
     RECT  58.5 9.589 58.734 9.815 ;
     RECT  42.768 9.787 50.022 9.823 ;
     RECT  51.015 9.391 53.046 9.823 ;
     RECT  71.352 9.661 71.694 9.823 ;
     RECT  72.504 9.781 72.897 9.823 ;
     RECT  4.032 9.113 4.914 9.859 ;
     RECT  56.415 9.617 56.697 9.859 ;
     RECT  34.815 7.619 35.097 9.883 ;
     RECT  42.768 9.823 50.202 9.883 ;
     RECT  51.015 9.823 53.082 9.883 ;
     RECT  2.415 9.113 2.862 9.895 ;
     RECT  4.032 9.859 5.418 9.895 ;
     RECT  34.815 9.883 35.802 9.895 ;
     RECT  36.792 9.509 38.286 9.895 ;
     RECT  34.812 9.895 35.802 9.923 ;
     RECT  71.352 9.823 72.897 9.931 ;
     RECT  77.544 9.751 78.642 9.931 ;
     RECT  83.415 9.005 83.898 9.931 ;
     RECT  2.415 9.895 5.418 9.959 ;
     RECT  84.852 9.517 85.518 9.965 ;
     RECT  35.928 9.931 35.946 10.021 ;
     RECT  36.72 9.895 38.286 10.021 ;
     RECT  77.544 9.931 78.75 10.021 ;
     RECT  35.928 10.021 38.286 10.049 ;
     RECT  77.544 10.021 78.822 10.049 ;
     RECT  83.415 9.931 84.042 10.049 ;
     RECT  83.415 10.049 83.898 10.057 ;
     RECT  68.364 9.779 68.418 10.061 ;
     RECT  54.144 9.661 55.53 10.085 ;
     RECT  69.588 10.027 70.11 10.085 ;
     RECT  56.415 9.859 57.078 10.093 ;
     RECT  78.015 10.049 78.822 10.093 ;
     RECT  34.812 9.923 35.097 10.129 ;
     RECT  42.768 9.883 53.082 10.129 ;
     RECT  59.796 10.021 59.814 10.129 ;
     RECT  6.228 9.895 6.246 10.165 ;
     RECT  58.716 9.815 58.734 10.165 ;
     RECT  83.268 10.057 83.898 10.165 ;
     RECT  71.352 9.931 73.458 10.193 ;
     RECT  69.732 10.085 70.11 10.201 ;
     RECT  34.776 10.129 35.097 10.229 ;
     RECT  42.768 10.129 53.118 10.229 ;
     RECT  78.015 10.093 78.858 10.229 ;
     RECT  69.732 10.201 70.542 10.267 ;
     RECT  71.352 10.193 72.897 10.267 ;
     RECT  61.815 4.829 62.097 10.291 ;
     RECT  2.415 9.959 3.906 10.315 ;
     RECT  56.415 10.093 57.114 10.319 ;
     RECT  59.796 10.129 59.958 10.319 ;
     RECT  68.976 10.201 68.994 10.319 ;
     RECT  59.796 10.319 59.814 10.355 ;
     RECT  69.732 10.267 72.897 10.355 ;
     RECT  76.932 10.129 77.166 10.355 ;
     RECT  4.752 9.959 5.418 10.435 ;
     RECT  6.228 10.165 6.57 10.435 ;
     RECT  70.524 10.355 70.722 10.463 ;
     RECT  4.752 10.435 6.57 10.471 ;
     RECT  36.324 10.049 38.286 10.471 ;
     RECT  61.815 10.291 62.694 10.499 ;
     RECT  61.02 10.471 61.038 10.541 ;
     RECT  67.215 9.779 67.497 10.561 ;
     RECT  4.752 10.471 6.93 10.589 ;
     RECT  65.592 10.471 65.61 10.589 ;
     RECT  69.732 10.355 69.75 10.589 ;
     RECT  76.932 10.355 77.058 10.589 ;
     RECT  39.96 9.689 41.454 10.597 ;
     RECT  76.932 10.589 76.95 10.625 ;
     RECT  39.708 10.597 41.454 10.633 ;
     RECT  6.732 10.589 6.93 10.669 ;
     RECT  83.232 10.165 83.898 10.697 ;
     RECT  2.304 10.315 3.906 10.699 ;
     RECT  4.752 10.589 4.77 10.699 ;
     RECT  36.324 10.471 38.574 10.699 ;
     RECT  39.384 10.633 41.454 10.699 ;
     RECT  42.804 10.229 53.118 10.705 ;
     RECT  54.144 10.085 55.422 10.705 ;
     RECT  36.324 10.699 41.454 10.733 ;
     RECT  42.804 10.705 55.422 10.733 ;
     RECT  66.708 10.561 67.497 10.733 ;
     RECT  84.852 9.965 84.906 10.747 ;
     RECT  5.58 10.589 5.598 10.753 ;
     RECT  6.732 10.669 7.074 10.769 ;
     RECT  42.804 10.733 43.902 10.769 ;
     RECT  2.304 10.699 4.77 10.781 ;
     RECT  84.816 10.747 84.906 10.814 ;
     RECT  6.732 10.769 6.822 10.859 ;
     RECT  42.804 10.769 43.83 10.859 ;
     RECT  58.716 10.165 58.95 10.859 ;
     RECT  44.676 10.733 55.422 10.877 ;
     RECT  36.324 10.733 37.854 10.891 ;
     RECT  38.592 10.733 41.454 10.891 ;
     RECT  44.676 10.877 48.042 10.895 ;
     RECT  48.78 10.877 55.422 10.895 ;
     RECT  6.732 10.859 6.75 10.931 ;
     RECT  36.072 10.891 37.854 10.967 ;
     RECT  71.64 10.355 72.897 10.975 ;
     RECT  38.592 10.891 41.562 11.011 ;
     RECT  57.852 10.987 57.87 11.011 ;
     RECT  74.664 10.831 74.682 11.011 ;
     RECT  82.656 10.831 82.674 11.011 ;
     RECT  42.804 10.859 43.506 11.069 ;
     RECT  71.64 10.975 73.602 11.101 ;
     RECT  74.52 11.011 74.682 11.101 ;
     RECT  57.852 11.011 58.482 11.129 ;
     RECT  65.232 10.867 65.25 11.129 ;
     RECT  71.64 11.101 74.682 11.129 ;
     RECT  38.592 11.011 41.85 11.137 ;
     RECT  42.804 11.069 43.47 11.137 ;
     RECT  71.64 11.129 74.538 11.165 ;
     RECT  84.888 10.814 84.906 11.179 ;
     RECT  71.712 11.165 74.538 11.201 ;
     RECT  83.415 10.697 83.898 11.245 ;
     RECT  71.712 11.201 73.602 11.261 ;
     RECT  38.592 11.137 43.47 11.273 ;
     RECT  70.704 10.463 70.722 11.273 ;
     RECT  74.52 11.201 74.538 11.273 ;
     RECT  56.415 10.319 56.697 11.281 ;
     RECT  48.996 10.895 55.422 11.309 ;
     RECT  51.015 11.309 55.422 11.371 ;
     RECT  56.232 11.281 56.697 11.371 ;
     RECT  51.015 11.371 56.697 11.399 ;
     RECT  71.712 11.261 73.35 11.399 ;
     RECT  41.544 11.273 43.47 11.405 ;
     RECT  2.415 10.781 4.77 11.515 ;
     RECT  56.415 11.399 56.697 11.551 ;
     RECT  77.148 11.371 77.166 11.551 ;
     RECT  78.015 10.229 78.297 11.551 ;
     RECT  2.415 11.515 5.058 11.611 ;
     RECT  67.215 10.733 67.497 11.641 ;
     RECT  56.415 11.551 56.862 11.669 ;
     RECT  77.148 11.551 78.297 11.669 ;
     RECT  36.144 10.967 37.854 11.713 ;
     RECT  38.592 11.273 40.806 11.713 ;
     RECT  44.676 10.895 47.862 11.713 ;
     RECT  77.436 11.669 78.297 11.713 ;
     RECT  82.224 11.011 82.674 11.777 ;
     RECT  44.64 11.713 47.862 11.785 ;
     RECT  36.144 11.713 40.806 11.803 ;
     RECT  36.108 11.803 40.806 11.813 ;
     RECT  80.964 11.281 80.982 11.813 ;
     RECT  63.864 11.551 63.882 11.821 ;
     RECT  69.372 11.419 69.39 11.821 ;
     RECT  82.224 11.777 82.602 11.821 ;
     RECT  2.304 11.611 5.058 11.849 ;
     RECT  36.108 11.813 38.538 11.849 ;
     RECT  69.048 11.821 69.822 11.911 ;
     RECT  36.108 11.849 38.214 11.939 ;
     RECT  69.048 11.911 70.326 11.939 ;
     RECT  77.436 11.713 78.642 11.939 ;
     RECT  44.352 11.785 47.862 11.947 ;
     RECT  48.996 11.309 50.202 11.947 ;
     RECT  63.756 11.821 63.882 11.975 ;
     RECT  71.892 11.399 72.897 11.975 ;
     RECT  81.036 11.821 81.054 11.975 ;
     RECT  82.188 11.821 82.602 11.975 ;
     RECT  59.976 11.911 59.994 12.055 ;
     RECT  34.815 10.229 35.097 12.091 ;
     RECT  61.815 10.499 62.097 12.091 ;
     RECT  75.888 11.713 75.906 12.091 ;
     RECT  41.724 11.405 43.47 12.181 ;
     RECT  59.652 12.055 59.994 12.181 ;
     RECT  61.815 12.091 62.622 12.181 ;
     RECT  61.815 12.181 62.694 12.187 ;
     RECT  34.776 12.091 35.097 12.209 ;
     RECT  36.108 11.939 38.106 12.209 ;
     RECT  51.015 11.399 55.53 12.209 ;
     RECT  59.508 12.181 59.994 12.209 ;
     RECT  83.415 11.245 84.042 12.209 ;
     RECT  44.352 11.947 50.202 12.217 ;
     RECT  41.616 12.181 43.47 12.245 ;
     RECT  51.015 12.209 55.422 12.245 ;
     RECT  61.632 12.187 62.694 12.245 ;
     RECT  43.452 12.245 43.47 12.253 ;
     RECT  44.244 12.217 50.202 12.253 ;
     RECT  84.888 11.179 85.482 12.281 ;
     RECT  36.108 12.209 37.854 12.325 ;
     RECT  69.372 11.939 70.326 12.353 ;
     RECT  2.415 11.849 5.058 12.361 ;
     RECT  36.072 12.325 37.854 12.361 ;
     RECT  39.312 11.813 40.806 12.361 ;
     RECT  41.616 12.245 42.642 12.361 ;
     RECT  56.415 11.669 56.754 12.361 ;
     RECT  78.015 11.939 78.642 12.361 ;
     RECT  61.815 12.245 62.694 12.389 ;
     RECT  36 12.361 37.854 12.413 ;
     RECT  57.852 11.129 57.87 12.413 ;
     RECT  59.508 12.209 59.526 12.413 ;
     RECT  6.84 12.361 6.858 12.451 ;
     RECT  75.888 12.091 76.05 12.451 ;
     RECT  6.804 12.451 6.858 12.479 ;
     RECT  39.312 12.361 42.642 12.479 ;
     RECT  64.08 12.055 64.098 12.479 ;
     RECT  78.015 12.361 78.75 12.479 ;
     RECT  82.512 11.975 82.602 12.479 ;
     RECT  66.708 11.641 67.497 12.487 ;
     RECT  75.348 12.451 76.05 12.487 ;
     RECT  36.252 12.413 37.854 12.515 ;
     RECT  39.42 12.479 42.642 12.515 ;
     RECT  69.372 12.353 69.75 12.515 ;
     RECT  66.708 12.487 67.986 12.523 ;
     RECT  82.584 12.479 82.602 12.523 ;
     RECT  83.415 12.209 83.862 12.523 ;
     RECT  6.804 12.479 6.822 12.551 ;
     RECT  39.492 12.515 42.642 12.551 ;
     RECT  0.108 12.427 0.126 12.557 ;
     RECT  43.452 12.253 50.202 12.557 ;
     RECT  56.304 12.361 56.754 12.557 ;
     RECT  69.732 12.515 69.75 12.557 ;
     RECT  82.584 12.523 83.862 12.587 ;
     RECT  75.348 12.487 76.086 12.631 ;
     RECT  36.288 12.515 37.854 12.749 ;
     RECT  56.415 12.557 56.754 12.757 ;
     RECT  75.348 12.631 76.194 12.785 ;
     RECT  66.708 12.523 68.562 12.793 ;
     RECT  56.415 12.757 57.078 12.797 ;
     RECT  2.415 12.361 5.094 12.821 ;
     RECT  84.888 12.281 84.906 12.859 ;
     RECT  2.415 12.821 4.734 12.941 ;
     RECT  66.708 12.793 68.634 12.941 ;
     RECT  66.708 12.941 67.497 12.991 ;
     RECT  43.56 12.557 50.202 13.019 ;
     RECT  62.892 12.721 62.91 13.019 ;
     RECT  68.256 12.941 68.634 13.019 ;
     RECT  83.232 12.587 83.862 13.019 ;
     RECT  72.615 11.975 72.897 13.027 ;
     RECT  70.668 12.361 70.722 13.063 ;
     RECT  72.396 13.027 72.897 13.085 ;
     RECT  57.996 12.901 58.014 13.091 ;
     RECT  66.672 12.991 67.497 13.091 ;
     RECT  36.324 12.749 37.854 13.099 ;
     RECT  34.815 12.209 35.097 13.171 ;
     RECT  72.615 13.085 72.897 13.171 ;
     RECT  36.324 13.099 38.322 13.243 ;
     RECT  51.015 12.245 55.314 13.261 ;
     RECT  84.852 12.859 84.906 13.288 ;
     RECT  43.884 13.019 50.202 13.289 ;
     RECT  70.668 13.063 71.262 13.289 ;
     RECT  76.392 13.027 76.41 13.289 ;
     RECT  2.415 12.941 4.662 13.291 ;
     RECT  39.528 12.551 42.426 13.297 ;
     RECT  36.324 13.243 38.61 13.325 ;
     RECT  84.852 13.288 85.482 13.325 ;
     RECT  72.615 13.171 73.35 13.361 ;
     RECT  80.964 13.171 80.982 13.397 ;
     RECT  39.348 13.297 42.426 13.441 ;
     RECT  46.728 13.289 50.202 13.441 ;
     RECT  50.976 13.261 55.314 13.441 ;
     RECT  83.376 13.019 83.862 13.441 ;
     RECT  2.304 13.291 4.662 13.469 ;
     RECT  68.976 13.027 68.994 13.469 ;
     RECT  17.784 13.171 17.802 13.559 ;
     RECT  83.376 13.441 84.042 13.595 ;
     RECT  46.728 13.441 55.314 13.603 ;
     RECT  6.804 13.333 6.822 13.631 ;
     RECT  83.376 13.595 83.862 13.667 ;
     RECT  36.324 13.325 37.854 13.669 ;
     RECT  36.216 13.669 37.854 13.703 ;
     RECT  36.216 13.703 37.566 13.711 ;
     RECT  38.736 13.441 42.426 13.711 ;
     RECT  36.144 13.711 37.566 13.757 ;
     RECT  5.4 13.675 5.418 13.801 ;
     RECT  36.216 13.757 37.566 13.829 ;
     RECT  59.256 13.711 59.274 13.829 ;
     RECT  36.432 13.829 37.17 13.901 ;
     RECT  46.728 13.603 55.494 13.907 ;
     RECT  5.4 13.801 5.454 13.909 ;
     RECT  43.884 13.289 45.954 13.949 ;
     RECT  2.415 13.469 4.662 13.981 ;
     RECT  5.4 13.909 5.562 13.981 ;
     RECT  66.744 13.091 67.497 13.981 ;
     RECT  78.015 12.479 78.297 13.981 ;
     RECT  63.18 13.711 63.198 14.071 ;
     RECT  34.776 13.171 35.097 14.099 ;
     RECT  50.94 13.907 55.494 14.099 ;
     RECT  63.18 14.071 63.27 14.099 ;
     RECT  70.668 13.289 70.686 14.099 ;
     RECT  75.204 13.981 75.222 14.099 ;
     RECT  56.415 12.797 56.697 14.107 ;
     RECT  36.432 13.901 37.098 14.135 ;
     RECT  78.015 13.981 78.75 14.135 ;
     RECT  66.744 13.981 67.842 14.143 ;
     RECT  54.108 14.099 55.494 14.203 ;
     RECT  56.376 14.107 56.697 14.203 ;
     RECT  44.46 13.949 45.954 14.207 ;
     RECT  78.015 14.135 78.678 14.207 ;
     RECT  61.815 12.389 62.097 14.215 ;
     RECT  66.744 14.143 68.094 14.215 ;
     RECT  59.112 13.945 59.13 14.237 ;
     RECT  63.252 14.099 63.27 14.243 ;
     RECT  82.656 13.801 82.674 14.243 ;
     RECT  46.728 13.907 50.022 14.251 ;
     RECT  46.656 14.251 50.022 14.369 ;
     RECT  54.108 14.203 56.697 14.369 ;
     RECT  66.744 14.215 68.706 14.441 ;
     RECT  38.736 13.711 42.786 14.485 ;
     RECT  43.668 14.413 43.686 14.485 ;
     RECT  2.415 13.981 5.562 14.521 ;
     RECT  84.852 13.325 84.906 14.539 ;
     RECT  2.304 14.521 5.778 14.573 ;
     RECT  61.74 14.215 62.097 14.611 ;
     RECT  69.3 14.611 69.786 14.635 ;
     RECT  2.415 14.573 5.778 14.639 ;
     RECT  38.736 14.485 43.686 14.639 ;
     RECT  74.916 14.179 75.078 14.639 ;
     RECT  57.708 14.635 57.726 14.675 ;
     RECT  74.916 14.639 74.934 14.675 ;
     RECT  84.852 14.539 85.482 14.675 ;
     RECT  66.744 14.441 68.31 14.683 ;
     RECT  44.46 14.207 45.897 14.719 ;
     RECT  84.852 14.675 84.906 14.747 ;
     RECT  66.708 14.683 68.31 14.755 ;
     RECT  2.415 14.639 5.238 14.783 ;
     RECT  83.415 13.667 83.862 14.791 ;
     RECT  38.736 14.639 43.542 14.819 ;
     RECT  69.3 14.635 70.47 14.827 ;
     RECT  71.244 14.791 71.262 14.827 ;
     RECT  66.492 14.755 68.31 14.909 ;
     RECT  66.492 14.909 67.497 14.945 ;
     RECT  76.212 14.611 76.23 14.945 ;
     RECT  83.415 14.791 83.898 14.945 ;
     RECT  34.815 14.099 35.097 14.953 ;
     RECT  38.736 14.819 43.074 14.953 ;
     RECT  6.552 14.791 6.57 14.981 ;
     RECT  46.728 14.369 50.022 14.989 ;
     RECT  51.015 14.099 53.262 14.989 ;
     RECT  74.736 14.953 74.754 14.989 ;
     RECT  0.108 14.449 0.126 15.005 ;
     RECT  54.144 14.369 56.697 15.017 ;
     RECT  61.56 14.611 62.097 15.017 ;
     RECT  38.592 14.953 43.074 15.025 ;
     RECT  37.764 15.025 43.074 15.053 ;
     RECT  68.22 14.909 68.238 15.053 ;
     RECT  69.3 14.827 71.262 15.053 ;
     RECT  74.664 14.989 74.754 15.053 ;
     RECT  60.048 13.981 60.066 15.061 ;
     RECT  78.015 14.207 78.297 15.061 ;
     RECT  5.22 14.783 5.238 15.089 ;
     RECT  83.415 14.945 83.826 15.089 ;
     RECT  46.728 14.989 53.262 15.151 ;
     RECT  37.764 15.053 39.042 15.179 ;
     RECT  46.728 15.151 53.406 15.179 ;
     RECT  60.048 15.061 60.174 15.187 ;
     RECT  47.124 15.179 53.406 15.197 ;
     RECT  54.144 15.017 55.386 15.215 ;
     RECT  78.015 15.061 78.678 15.215 ;
     RECT  82.656 14.989 82.674 15.259 ;
     RECT  83.415 15.089 83.754 15.259 ;
     RECT  44.28 14.719 45.897 15.307 ;
     RECT  47.124 15.197 52.974 15.323 ;
     RECT  78.015 15.215 78.642 15.323 ;
     RECT  34.776 14.953 35.097 15.359 ;
     RECT  44.28 15.307 45.954 15.359 ;
     RECT  82.656 15.259 83.754 15.359 ;
     RECT  37.62 15.295 37.638 15.389 ;
     RECT  38.448 15.179 39.042 15.449 ;
     RECT  60.012 15.187 60.174 15.449 ;
     RECT  83.232 15.359 83.754 15.449 ;
     RECT  44.28 15.359 45.897 15.457 ;
     RECT  60.012 15.449 60.03 15.485 ;
     RECT  69.3 15.053 71.082 15.521 ;
     RECT  84.888 14.747 84.906 15.521 ;
     RECT  50.724 15.323 52.974 15.593 ;
     RECT  54.144 15.215 54.918 15.593 ;
     RECT  80.388 15.331 80.406 15.593 ;
     RECT  47.124 15.323 49.77 15.629 ;
     RECT  69.948 15.521 71.082 15.677 ;
     RECT  47.232 15.629 49.77 15.719 ;
     RECT  51.015 15.593 52.974 15.719 ;
     RECT  54.144 15.593 54.846 15.719 ;
     RECT  70.452 15.677 71.082 15.719 ;
     RECT  38.448 15.449 39.006 15.755 ;
     RECT  47.268 15.719 49.662 15.755 ;
     RECT  70.668 15.719 71.082 15.791 ;
     RECT  39.78 15.053 43.074 15.799 ;
     RECT  44.208 15.457 45.897 15.799 ;
     RECT  47.268 15.755 49.014 15.827 ;
     RECT  54.144 15.719 54.378 15.829 ;
     RECT  74.664 15.053 74.682 15.829 ;
     RECT  83.415 15.449 83.754 15.835 ;
     RECT  71.064 15.791 71.082 15.863 ;
     RECT  53.82 15.829 54.378 15.869 ;
     RECT  74.124 15.829 74.682 15.869 ;
     RECT  74.628 15.869 74.682 15.871 ;
     RECT  54.252 15.869 54.378 16.025 ;
     RECT  2.415 14.783 4.05 16.033 ;
     RECT  2.304 16.033 4.05 16.069 ;
     RECT  81.972 15.871 81.99 16.097 ;
     RECT  47.448 15.827 49.014 16.133 ;
     RECT  2.304 16.069 4.77 16.141 ;
     RECT  39.78 15.799 45.897 16.141 ;
     RECT  85.356 15.787 85.374 16.219 ;
     RECT  2.304 16.141 4.806 16.253 ;
     RECT  51.015 15.719 52.902 16.259 ;
     RECT  59.724 16.105 59.742 16.259 ;
     RECT  39.78 16.141 45.954 16.267 ;
     RECT  61.815 15.017 62.097 16.267 ;
     RECT  85.356 16.219 85.482 16.295 ;
     RECT  51.015 16.259 52.29 16.331 ;
     RECT  51.015 16.331 51.93 16.397 ;
     RECT  2.415 16.253 4.806 16.411 ;
     RECT  74.628 15.871 74.826 16.411 ;
     RECT  78.015 15.323 78.297 16.411 ;
     RECT  39.492 16.267 45.954 16.501 ;
     RECT  74.628 16.411 74.934 16.501 ;
     RECT  6.84 16.411 6.858 16.529 ;
     RECT  78.015 16.411 78.966 16.529 ;
     RECT  83.415 15.835 84.042 16.529 ;
     RECT  56.415 15.017 56.697 16.537 ;
     RECT  47.448 16.133 48.942 16.555 ;
     RECT  82.368 16.411 82.674 16.565 ;
     RECT  39.312 16.501 46.026 16.601 ;
     RECT  42.66 16.601 46.026 16.609 ;
     RECT  54.648 16.537 54.666 16.645 ;
     RECT  74.628 16.501 75.006 16.645 ;
     RECT  46.8 16.555 48.942 16.673 ;
     RECT  54.648 16.645 55.386 16.673 ;
     RECT  65.268 16.645 65.286 16.681 ;
     RECT  74.628 16.645 75.258 16.681 ;
     RECT  0.54 16.411 0.558 16.685 ;
     RECT  65.16 16.681 65.286 16.771 ;
     RECT  72.615 13.361 72.897 16.771 ;
     RECT  73.908 16.681 75.438 16.795 ;
     RECT  15.372 16.681 15.39 16.799 ;
     RECT  54.684 16.673 55.386 16.799 ;
     RECT  56.16 16.537 56.697 16.799 ;
     RECT  77.004 16.609 77.022 16.807 ;
     RECT  78.015 16.529 78.858 16.807 ;
     RECT  73.908 16.795 75.51 16.835 ;
     RECT  42.66 16.609 46.062 16.843 ;
     RECT  46.8 16.673 48.438 16.843 ;
     RECT  82.368 16.565 82.638 16.871 ;
     RECT  2.415 16.411 4.878 16.879 ;
     RECT  61.815 16.267 62.694 16.879 ;
     RECT  64.908 16.771 65.286 16.879 ;
     RECT  67.215 14.945 67.497 16.879 ;
     RECT  83.415 16.529 83.898 16.879 ;
     RECT  71.208 16.609 71.226 16.891 ;
     RECT  73.908 16.835 75.474 16.891 ;
     RECT  54.684 16.799 55.242 16.943 ;
     RECT  56.304 16.799 56.697 16.943 ;
     RECT  56.415 16.943 56.697 16.951 ;
     RECT  72.504 16.771 72.897 16.951 ;
     RECT  73.728 16.891 75.474 16.951 ;
     RECT  77.004 16.807 78.858 16.951 ;
     RECT  61.815 16.879 63.27 16.979 ;
     RECT  67.215 16.879 67.626 16.979 ;
     RECT  84.888 16.651 84.906 17.035 ;
     RECT  71.064 16.891 71.226 17.041 ;
     RECT  54.684 16.943 54.738 17.069 ;
     RECT  56.415 16.951 56.826 17.069 ;
     RECT  61.815 16.979 63.198 17.069 ;
     RECT  64.764 16.879 65.286 17.069 ;
     RECT  72.504 16.951 75.474 17.069 ;
     RECT  76.86 16.951 78.858 17.069 ;
     RECT  71.064 17.041 71.55 17.075 ;
     RECT  2.415 16.879 5.562 17.105 ;
     RECT  61.815 17.069 62.262 17.105 ;
     RECT  64.764 17.069 65.178 17.105 ;
     RECT  72.504 17.069 73.602 17.105 ;
     RECT  74.988 17.069 75.474 17.105 ;
     RECT  76.86 17.069 78.714 17.105 ;
     RECT  84.888 17.035 85.482 17.105 ;
     RECT  42.66 16.843 48.438 17.165 ;
     RECT  71.532 17.075 71.55 17.221 ;
     RECT  72.504 17.105 73.422 17.221 ;
     RECT  2.415 17.105 4.626 17.339 ;
     RECT  51.015 16.397 51.462 17.339 ;
     RECT  67.215 16.979 67.554 17.339 ;
     RECT  77.544 17.105 78.297 17.339 ;
     RECT  83.376 16.879 83.898 17.347 ;
     RECT  5.436 17.105 5.562 17.375 ;
     RECT  71.532 17.221 73.422 17.375 ;
     RECT  82.656 17.347 83.898 17.375 ;
     RECT  2.415 17.339 4.446 17.467 ;
     RECT  70.668 17.347 70.686 17.483 ;
     RECT  2.304 17.467 4.446 17.519 ;
     RECT  54.684 17.069 54.702 17.519 ;
     RECT  38.448 15.755 38.466 17.581 ;
     RECT  39.312 16.601 41.382 17.581 ;
     RECT  72.072 17.375 73.422 17.609 ;
     RECT  42.66 17.165 48.15 17.611 ;
     RECT  72.144 17.609 73.422 17.645 ;
     RECT  42.624 17.611 48.15 17.761 ;
     RECT  38.448 17.581 41.382 17.851 ;
     RECT  56.415 17.069 56.697 17.851 ;
     RECT  77.724 17.339 78.297 17.887 ;
     RECT  84.888 17.105 84.906 17.899 ;
     RECT  42.588 17.761 48.15 17.923 ;
     RECT  82.656 17.375 83.862 17.959 ;
     RECT  51.015 17.339 51.297 17.995 ;
     RECT  61.815 17.105 62.097 18.031 ;
     RECT  72.615 17.645 73.422 18.031 ;
     RECT  77.724 17.887 78.714 18.031 ;
     RECT  2.415 17.519 4.446 18.121 ;
     RECT  42.48 17.923 48.15 18.121 ;
     RECT  50.364 17.995 51.297 18.121 ;
     RECT  72.615 18.031 73.602 18.121 ;
     RECT  56.415 17.851 57.114 18.149 ;
     RECT  81.972 17.959 83.862 18.149 ;
     RECT  38.448 17.851 41.49 18.184 ;
     RECT  77.724 18.031 78.75 18.185 ;
     RECT  56.415 18.149 56.697 18.193 ;
     RECT  66.024 18.121 66.042 18.193 ;
     RECT  38.448 18.184 41.562 18.221 ;
     RECT  72.615 18.121 73.782 18.221 ;
     RECT  39.312 18.221 41.562 18.235 ;
     RECT  42.444 18.121 48.15 18.235 ;
     RECT  2.415 18.121 4.806 18.265 ;
     RECT  5.652 17.887 5.922 18.265 ;
     RECT  50.148 18.121 51.297 18.269 ;
     RECT  2.415 18.265 5.922 18.301 ;
     RECT  56.376 18.193 56.697 18.329 ;
     RECT  84.852 17.899 84.906 18.331 ;
     RECT  0.108 18.193 0.126 18.365 ;
     RECT  51.015 18.269 51.297 18.379 ;
     RECT  61.815 18.031 62.154 18.391 ;
     RECT  2.415 18.301 5.994 18.419 ;
     RECT  39.312 18.235 48.51 18.419 ;
     RECT  65.916 18.193 66.042 18.419 ;
     RECT  65.916 18.419 65.934 18.455 ;
     RECT  50.148 18.269 50.166 18.491 ;
     RECT  84.852 18.331 85.482 18.527 ;
     RECT  61.596 18.391 62.154 18.571 ;
     RECT  83.376 18.149 83.862 18.571 ;
     RECT  2.415 18.419 5.886 18.599 ;
     RECT  75.06 18.031 75.618 18.661 ;
     RECT  5.004 18.599 5.886 18.689 ;
     RECT  47.088 18.419 48.51 18.689 ;
     RECT  49.428 18.571 49.446 18.689 ;
     RECT  51.015 18.379 51.606 18.689 ;
     RECT  61.596 18.571 62.19 18.701 ;
     RECT  5.004 18.689 5.454 18.725 ;
     RECT  61.596 18.701 62.097 18.749 ;
     RECT  39.996 18.419 46.17 18.833 ;
     RECT  18.615 2.413 18.897 18.841 ;
     RECT  75.06 18.661 75.726 18.869 ;
     RECT  78.015 18.185 78.75 18.931 ;
     RECT  83.376 18.571 84.042 18.931 ;
     RECT  18.288 18.841 18.897 18.959 ;
     RECT  69.84 18.805 69.858 18.959 ;
     RECT  72.615 18.221 72.897 18.967 ;
     RECT  70.704 19.039 70.722 19.111 ;
     RECT  72.576 18.967 72.897 19.111 ;
     RECT  75.24 18.869 75.726 19.111 ;
     RECT  75.24 19.111 76.23 19.133 ;
     RECT  68.904 19.111 69.066 19.181 ;
     RECT  78.015 18.931 79.002 19.201 ;
     RECT  70.704 19.111 71.37 19.229 ;
     RECT  75.708 19.133 76.23 19.229 ;
     RECT  83.232 18.931 84.042 19.229 ;
     RECT  70.704 19.229 70.722 19.265 ;
     RECT  78.015 19.201 79.074 19.265 ;
     RECT  84.888 18.527 85.482 19.265 ;
     RECT  76.212 19.229 76.23 19.301 ;
     RECT  69.048 19.181 69.066 19.337 ;
     RECT  2.415 18.599 4.014 19.345 ;
     RECT  79.056 19.265 79.074 19.373 ;
     RECT  38.448 18.221 38.466 19.381 ;
     RECT  42.336 18.833 46.17 19.381 ;
     RECT  47.088 18.689 48.294 19.381 ;
     RECT  2.415 19.345 4.086 19.471 ;
     RECT  39.996 18.833 41.526 19.471 ;
     RECT  83.415 19.229 84.042 19.499 ;
     RECT  42.336 19.381 48.294 19.507 ;
     RECT  83.415 19.499 83.898 19.535 ;
     RECT  5.436 18.725 5.454 19.579 ;
     RECT  36.432 14.135 36.45 19.579 ;
     RECT  5.436 19.579 5.634 19.651 ;
     RECT  34.815 15.359 35.097 19.651 ;
     RECT  36.144 19.579 36.45 19.651 ;
     RECT  42.336 19.507 48.618 19.651 ;
     RECT  30.78 19.579 30.798 19.679 ;
     RECT  38.448 19.381 38.79 19.679 ;
     RECT  34.776 19.651 35.097 19.741 ;
     RECT  36.072 19.651 36.45 19.741 ;
     RECT  78.015 19.265 78.297 19.741 ;
     RECT  39.96 19.471 41.526 19.768 ;
     RECT  42.3 19.651 48.618 19.768 ;
     RECT  5.436 19.651 5.706 19.769 ;
     RECT  15.984 19.507 16.002 19.769 ;
     RECT  39.96 19.768 48.618 19.769 ;
     RECT  72.576 19.111 73.35 19.777 ;
     RECT  2.415 19.471 4.158 19.805 ;
     RECT  5.436 19.769 5.634 19.921 ;
     RECT  72.468 19.777 73.35 19.921 ;
     RECT  82.656 19.471 82.674 19.921 ;
     RECT  52.596 19.849 52.614 20.011 ;
     RECT  72.396 19.921 73.458 20.011 ;
     RECT  74.376 19.921 74.394 20.011 ;
     RECT  77.904 19.741 78.297 20.011 ;
     RECT  84.888 19.265 84.906 20.011 ;
     RECT  52.164 20.011 52.614 20.039 ;
     RECT  83.415 19.535 83.862 20.039 ;
     RECT  0.54 19.921 0.558 20.045 ;
     RECT  67.215 17.339 67.497 20.059 ;
     RECT  74.376 20.011 74.682 20.059 ;
     RECT  5.4 19.921 5.634 20.075 ;
     RECT  60.408 19.777 60.426 20.075 ;
     RECT  56.415 18.329 56.697 20.083 ;
     RECT  72.36 20.011 73.458 20.093 ;
     RECT  51.015 18.689 51.297 20.155 ;
     RECT  52.164 20.039 52.182 20.155 ;
     RECT  81.972 19.921 82.674 20.155 ;
     RECT  83.415 20.039 83.79 20.155 ;
     RECT  81.972 20.155 83.79 20.183 ;
     RECT  34.776 19.741 36.45 20.191 ;
     RECT  39.96 19.769 48.294 20.191 ;
     RECT  51.015 20.155 52.182 20.192 ;
     RECT  52.164 20.192 52.182 20.219 ;
     RECT  82.584 20.183 83.79 20.309 ;
     RECT  5.472 20.075 5.634 20.345 ;
     RECT  63.252 20.191 63.27 20.345 ;
     RECT  66.996 20.059 67.497 20.345 ;
     RECT  72.36 20.093 73.278 20.345 ;
     RECT  49.032 19.921 49.05 20.381 ;
     RECT  75.996 20.191 76.014 20.381 ;
     RECT  77.832 20.011 78.297 20.381 ;
     RECT  79.308 20.281 79.326 20.381 ;
     RECT  61.815 18.749 62.097 20.389 ;
     RECT  2.415 19.805 4.086 20.395 ;
     RECT  70.704 20.191 70.722 20.417 ;
     RECT  39.564 20.191 48.294 20.453 ;
     RECT  34.776 20.191 36.882 20.461 ;
     RECT  37.62 20.107 37.638 20.461 ;
     RECT  38.448 19.679 38.754 20.461 ;
     RECT  39.564 20.453 48.222 20.461 ;
     RECT  2.304 20.395 4.086 20.489 ;
     RECT  61.815 20.389 62.766 20.489 ;
     RECT  72.396 20.345 72.954 20.489 ;
     RECT  56.415 20.083 57.042 20.539 ;
     RECT  56.415 20.539 57.114 20.579 ;
     RECT  34.596 20.461 48.222 20.587 ;
     RECT  55.512 20.623 55.53 20.669 ;
     RECT  78.015 20.381 78.297 20.821 ;
     RECT  83.415 20.309 83.79 20.821 ;
     RECT  2.415 20.489 4.086 20.875 ;
     RECT  84.852 20.011 84.906 20.885 ;
     RECT  0.108 20.827 0.126 20.957 ;
     RECT  74.376 20.059 75.078 20.993 ;
     RECT  82.584 20.309 82.674 21.001 ;
     RECT  72.396 20.489 72.897 21.115 ;
     RECT  58.752 20.929 58.77 21.119 ;
     RECT  78.015 20.821 78.858 21.119 ;
     RECT  84.888 20.885 84.906 21.155 ;
     RECT  33.984 20.587 48.222 21.191 ;
     RECT  34.164 21.191 48.222 21.211 ;
     RECT  2.415 20.875 4.59 21.235 ;
     RECT  74.376 20.993 74.898 21.235 ;
     RECT  2.415 21.235 4.842 21.259 ;
     RECT  75.78 21.001 75.798 21.263 ;
     RECT  2.304 21.259 4.842 21.299 ;
     RECT  24.015 2.413 24.297 21.361 ;
     RECT  5.724 21.019 5.742 21.389 ;
     RECT  22.716 21.091 22.734 21.389 ;
     RECT  34.164 21.211 48.942 21.389 ;
     RECT  66.204 21.163 66.222 21.389 ;
     RECT  51.015 20.192 51.297 21.397 ;
     RECT  67.215 20.345 67.497 21.397 ;
     RECT  34.164 21.389 37.098 21.425 ;
     RECT  37.872 21.389 48.942 21.425 ;
     RECT  74.16 21.235 74.898 21.425 ;
     RECT  23.832 21.361 24.297 21.437 ;
     RECT  22.788 21.451 22.806 21.497 ;
     RECT  66.744 21.397 67.497 21.497 ;
     RECT  61.815 20.489 62.097 21.505 ;
     RECT  72.108 21.115 72.897 21.505 ;
     RECT  37.944 21.425 48.942 21.533 ;
     RECT  82.116 21.001 82.674 21.541 ;
     RECT  83.415 20.821 83.898 21.541 ;
     RECT  34.164 21.425 36.954 21.569 ;
     RECT  70.74 21.541 70.758 21.595 ;
     RECT  51.015 21.397 51.894 21.631 ;
     RECT  70.596 21.595 70.758 21.631 ;
     RECT  78.015 21.119 78.75 21.631 ;
     RECT  30.78 21.541 30.798 21.659 ;
     RECT  34.776 21.569 36.954 21.659 ;
     RECT  41.76 21.533 48.942 21.659 ;
     RECT  69.444 21.541 69.534 21.659 ;
     RECT  72.036 21.505 72.897 21.659 ;
     RECT  82.116 21.541 84.042 21.659 ;
     RECT  57.816 21.115 57.834 21.677 ;
     RECT  70.524 21.631 70.758 21.677 ;
     RECT  82.656 21.659 84.042 21.695 ;
     RECT  55.044 21.667 55.062 21.703 ;
     RECT  0.54 21.541 0.558 21.725 ;
     RECT  69.444 21.659 69.462 21.731 ;
     RECT  74.664 21.425 74.898 21.775 ;
     RECT  6.66 21.505 6.678 21.803 ;
     RECT  45.504 21.659 48.87 21.803 ;
     RECT  83.415 21.695 84.042 21.803 ;
     RECT  55.044 21.703 55.134 21.811 ;
     RECT  61.308 21.505 62.097 21.811 ;
     RECT  70.704 21.677 70.758 21.811 ;
     RECT  72.396 21.659 72.897 21.811 ;
     RECT  76.5 21.541 76.518 21.811 ;
     RECT  77.976 21.631 78.75 21.811 ;
     RECT  54.972 21.811 55.134 21.929 ;
     RECT  60.408 21.775 60.426 21.929 ;
     RECT  61.308 21.811 62.154 21.929 ;
     RECT  72.396 21.811 73.566 21.929 ;
     RECT  76.5 21.811 76.626 21.929 ;
     RECT  50.328 21.631 51.894 21.937 ;
     RECT  61.308 21.929 62.097 21.965 ;
     RECT  76.5 21.929 76.518 21.965 ;
     RECT  77.832 21.811 78.75 21.965 ;
     RECT  54.036 21.775 54.054 21.973 ;
     RECT  54.972 21.929 54.99 21.973 ;
     RECT  54.036 21.973 54.99 22.001 ;
     RECT  81.828 21.901 81.846 22.001 ;
     RECT  49.896 21.937 51.894 22.037 ;
     RECT  54.036 22.001 54.702 22.037 ;
     RECT  70.704 21.811 70.794 22.037 ;
     RECT  2.415 21.299 4.842 22.072 ;
     RECT  85.464 21.259 85.482 22.075 ;
     RECT  49.896 22.037 49.914 22.081 ;
     RECT  2.304 22.072 4.842 22.109 ;
     RECT  50.688 22.037 51.894 22.109 ;
     RECT  60.264 22.081 60.282 22.157 ;
     RECT  74.664 21.775 75.042 22.199 ;
     RECT  78.015 21.965 78.75 22.199 ;
     RECT  82.656 21.695 82.674 22.199 ;
     RECT  54.036 22.037 54.054 22.205 ;
     RECT  50.724 22.109 51.894 22.207 ;
     RECT  34.815 21.659 36.954 22.219 ;
     RECT  37.944 21.533 40.842 22.219 ;
     RECT  72.615 21.929 73.566 22.235 ;
     RECT  74.772 22.199 75.042 22.235 ;
     RECT  78.015 22.199 78.678 22.235 ;
     RECT  50.724 22.207 52.074 22.243 ;
     RECT  52.92 21.811 52.938 22.243 ;
     RECT  2.34 22.109 4.842 22.351 ;
     RECT  50.724 22.243 52.938 22.351 ;
     RECT  68.724 22.351 68.742 22.411 ;
     RECT  41.76 21.659 44.658 22.441 ;
     RECT  45.504 21.803 48.654 22.441 ;
     RECT  41.76 22.441 48.654 22.549 ;
     RECT  50.724 22.351 52.974 22.577 ;
     RECT  56.415 20.579 56.697 22.585 ;
     RECT  68.58 22.411 68.742 22.585 ;
     RECT  83.415 21.803 83.97 22.585 ;
     RECT  51.015 22.577 52.974 22.613 ;
     RECT  41.76 22.549 48.942 22.621 ;
     RECT  49.752 22.081 49.914 22.621 ;
     RECT  67.176 21.497 67.497 22.621 ;
     RECT  68.58 22.585 68.85 22.621 ;
     RECT  41.76 22.621 49.914 22.685 ;
     RECT  58.716 22.621 58.734 22.711 ;
     RECT  75.492 22.351 75.51 22.711 ;
     RECT  2.34 22.351 5.058 22.739 ;
     RECT  34.815 22.219 40.842 22.739 ;
     RECT  51.015 22.613 52.902 22.739 ;
     RECT  56.415 22.585 56.754 22.739 ;
     RECT  75.492 22.711 75.978 22.739 ;
     RECT  67.176 22.621 68.85 22.741 ;
     RECT  41.76 22.685 42.678 22.775 ;
     RECT  43.452 22.685 49.914 22.775 ;
     RECT  81.972 22.621 81.99 22.775 ;
     RECT  45.615 22.775 49.914 22.781 ;
     RECT  67.176 22.741 69.39 22.781 ;
     RECT  67.176 22.781 69.246 22.795 ;
     RECT  34.815 22.739 37.35 22.811 ;
     RECT  34.815 22.811 37.17 22.855 ;
     RECT  75.636 22.739 75.978 22.891 ;
     RECT  2.34 22.739 4.482 22.939 ;
     RECT  5.256 22.855 5.274 23.009 ;
     RECT  58.5 22.711 58.734 23.009 ;
     RECT  67.104 22.795 69.246 23.009 ;
     RECT  75.636 22.891 76.086 23.009 ;
     RECT  48.204 22.781 49.914 23.045 ;
     RECT  58.5 23.009 58.518 23.045 ;
     RECT  75.636 23.009 75.978 23.045 ;
     RECT  34.812 22.855 37.17 23.069 ;
     RECT  30.78 22.891 30.798 23.081 ;
     RECT  70.308 22.711 70.326 23.081 ;
     RECT  2.304 22.939 4.482 23.189 ;
     RECT  29.415 2.413 29.697 23.275 ;
     RECT  42.3 22.775 42.678 23.279 ;
     RECT  34.815 23.069 37.17 23.309 ;
     RECT  45.615 22.781 47.358 23.309 ;
     RECT  42.66 23.279 42.678 23.351 ;
     RECT  61.815 21.965 62.097 23.431 ;
     RECT  74.7 23.251 74.718 23.431 ;
     RECT  51.015 22.739 52.794 23.459 ;
     RECT  55.008 23.431 55.026 23.512 ;
     RECT  29.415 23.275 29.934 23.549 ;
     RECT  45.615 23.309 47.178 23.549 ;
     RECT  54.864 23.512 55.026 23.549 ;
     RECT  67.104 23.009 68.778 23.549 ;
     RECT  74.7 23.431 74.862 23.549 ;
     RECT  67.104 23.549 68.634 23.585 ;
     RECT  74.7 23.549 74.718 23.585 ;
     RECT  82.044 23.521 82.674 23.621 ;
     RECT  28.368 23.593 28.386 23.645 ;
     RECT  56.415 22.739 56.697 23.659 ;
     RECT  54.864 23.549 54.99 23.692 ;
     RECT  56.415 23.659 57.294 23.699 ;
     RECT  2.415 23.189 4.482 23.701 ;
     RECT  5.868 23.371 5.886 23.701 ;
     RECT  51.015 23.459 52.578 23.701 ;
     RECT  61.488 23.431 62.097 23.701 ;
     RECT  67.104 23.585 68.562 23.701 ;
     RECT  48.528 23.045 49.914 23.791 ;
     RECT  66.672 23.701 68.562 23.791 ;
     RECT  5.868 23.701 6.03 23.819 ;
     RECT  54.828 23.692 54.99 23.819 ;
     RECT  62.892 23.521 62.91 23.819 ;
     RECT  66.6 23.791 68.562 23.819 ;
     RECT  75.636 23.045 75.654 23.819 ;
     RECT  5.868 23.819 5.886 23.827 ;
     RECT  43.452 22.775 44.766 23.827 ;
     RECT  5.724 23.827 5.886 23.855 ;
     RECT  48.384 23.791 49.914 23.855 ;
     RECT  54.828 23.819 54.846 23.855 ;
     RECT  61.38 23.701 62.097 23.855 ;
     RECT  68.544 23.819 68.562 23.855 ;
     RECT  82.188 23.621 82.674 23.855 ;
     RECT  1.152 23.755 1.17 23.885 ;
     RECT  43.02 23.827 44.766 23.885 ;
     RECT  48.384 23.855 49.842 23.891 ;
     RECT  66.6 23.819 67.626 23.891 ;
     RECT  5.724 23.855 5.742 23.899 ;
     RECT  34.815 23.309 36.774 23.927 ;
     RECT  58.212 23.701 58.23 23.927 ;
     RECT  67.215 23.891 67.59 23.927 ;
     RECT  36.252 23.927 36.774 23.963 ;
     RECT  38.124 22.739 40.842 23.971 ;
     RECT  43.596 23.885 44.766 23.971 ;
     RECT  43.596 23.971 44.802 24.061 ;
     RECT  45.615 23.549 47.142 24.061 ;
     RECT  5.472 23.899 5.742 24.089 ;
     RECT  37.98 23.971 40.842 24.091 ;
     RECT  5.472 24.089 5.598 24.125 ;
     RECT  34.815 23.927 35.478 24.125 ;
     RECT  37.836 24.091 40.842 24.131 ;
     RECT  48.384 23.891 49.806 24.205 ;
     RECT  50.94 23.701 52.578 24.205 ;
     RECT  6.804 23.125 6.822 24.233 ;
     RECT  50.724 24.205 52.578 24.233 ;
     RECT  38.124 24.131 40.842 24.331 ;
     RECT  72.615 22.235 72.897 24.331 ;
     RECT  48.24 24.205 49.806 24.359 ;
     RECT  54.684 24.331 54.702 24.403 ;
     RECT  78.015 22.235 78.297 24.403 ;
     RECT  82.332 23.855 82.674 24.467 ;
     RECT  54.612 24.403 54.702 24.469 ;
     RECT  2.415 23.701 4.518 24.475 ;
     RECT  48.24 24.359 49.626 24.475 ;
     RECT  72.18 24.331 73.53 24.475 ;
     RECT  82.332 24.467 82.35 24.503 ;
     RECT  54.468 24.469 54.702 24.509 ;
     RECT  43.596 24.061 47.142 24.511 ;
     RECT  47.88 24.475 49.626 24.511 ;
     RECT  71.244 24.475 73.53 24.511 ;
     RECT  34.815 24.125 35.097 24.601 ;
     RECT  54.612 24.509 54.702 24.629 ;
     RECT  0.54 24.403 0.558 24.653 ;
     RECT  63.144 24.367 63.162 24.665 ;
     RECT  54.684 24.629 54.702 24.701 ;
     RECT  34.776 24.601 35.097 24.737 ;
     RECT  42.768 24.133 42.786 24.745 ;
     RECT  43.596 24.511 49.626 24.745 ;
     RECT  71.028 24.511 73.53 24.773 ;
     RECT  50.724 24.233 52.506 24.781 ;
     RECT  42.768 24.745 49.626 24.899 ;
     RECT  64.476 24.709 64.494 24.899 ;
     RECT  76.968 24.403 76.986 24.899 ;
     RECT  63.54 24.901 63.558 24.907 ;
     RECT  71.028 24.773 72.897 24.935 ;
     RECT  63.54 24.907 63.99 24.941 ;
     RECT  2.415 24.475 4.842 25.003 ;
     RECT  5.58 24.125 5.598 25.003 ;
     RECT  81.504 24.475 81.522 25.007 ;
     RECT  2.415 25.003 5.598 25.051 ;
     RECT  50.508 24.781 52.506 25.051 ;
     RECT  59.652 24.523 59.67 25.051 ;
     RECT  43.128 24.899 49.626 25.099 ;
     RECT  50.508 25.051 52.578 25.099 ;
     RECT  67.215 23.927 67.497 25.141 ;
     RECT  59.652 25.051 60.174 25.169 ;
     RECT  63.828 24.941 63.99 25.169 ;
     RECT  2.412 25.051 5.598 25.249 ;
     RECT  6.372 25.051 6.39 25.249 ;
     RECT  61.815 23.855 62.097 25.249 ;
     RECT  77.904 24.403 78.297 25.285 ;
     RECT  2.412 25.249 6.39 25.313 ;
     RECT  67.215 25.141 68.166 25.321 ;
     RECT  70.092 25.285 70.11 25.321 ;
     RECT  83.415 22.585 84.042 25.321 ;
     RECT  61.164 25.249 62.802 25.349 ;
     RECT  38.124 24.331 40.878 25.411 ;
     RECT  77.868 25.285 78.297 25.411 ;
     RECT  2.412 25.313 5.67 25.439 ;
     RECT  58.716 25.249 58.734 25.439 ;
     RECT  61.164 25.349 62.73 25.439 ;
     RECT  67.215 25.321 68.49 25.439 ;
     RECT  76.716 25.249 76.734 25.439 ;
     RECT  77.868 25.411 78.678 25.439 ;
     RECT  38.124 25.411 41.346 25.447 ;
     RECT  69.588 25.321 70.11 25.447 ;
     RECT  78.015 25.439 78.678 25.447 ;
     RECT  37.62 25.447 41.346 25.469 ;
     RECT  2.412 25.439 5.562 25.475 ;
     RECT  68.4 25.439 68.49 25.475 ;
     RECT  69.588 25.447 70.722 25.475 ;
     RECT  83.088 25.321 84.042 25.475 ;
     RECT  61.815 25.439 62.73 25.547 ;
     RECT  70.092 25.475 70.722 25.547 ;
     RECT  2.412 25.475 4.878 25.583 ;
     RECT  78.015 25.447 78.75 25.583 ;
     RECT  71.532 24.935 72.897 25.619 ;
     RECT  59.652 25.169 59.67 25.661 ;
     RECT  36.756 23.963 36.774 25.717 ;
     RECT  37.62 25.469 41.166 25.717 ;
     RECT  36.756 25.717 41.166 25.781 ;
     RECT  2.412 25.583 4.374 25.861 ;
     RECT  82.188 25.951 82.206 25.987 ;
     RECT  43.128 25.099 52.578 26.095 ;
     RECT  43.128 26.095 52.65 26.203 ;
     RECT  38.052 25.781 41.166 26.221 ;
     RECT  43.128 26.203 52.758 26.221 ;
     RECT  67.215 25.439 67.497 26.221 ;
     RECT  68.4 25.475 68.418 26.221 ;
     RECT  78.015 25.583 78.297 26.221 ;
     RECT  83.415 25.475 84.042 26.249 ;
     RECT  56.415 23.699 56.697 26.251 ;
     RECT  84.888 22.075 85.482 26.321 ;
     RECT  43.02 26.221 52.758 26.329 ;
     RECT  61.815 25.547 62.55 26.329 ;
     RECT  67.215 26.221 68.418 26.329 ;
     RECT  70.092 25.547 70.11 26.329 ;
     RECT  72.108 25.619 72.897 26.329 ;
     RECT  77.436 26.221 78.297 26.329 ;
     RECT  36.756 25.781 37.314 26.333 ;
     RECT  38.052 26.221 41.634 26.365 ;
     RECT  42.66 26.329 52.758 26.365 ;
     RECT  2.304 25.861 4.374 26.401 ;
     RECT  34.815 24.737 35.097 26.401 ;
     RECT  55.944 26.251 56.697 26.401 ;
     RECT  70.092 26.329 70.722 26.401 ;
     RECT  72.108 26.329 73.242 26.401 ;
     RECT  82.188 25.987 82.674 26.401 ;
     RECT  2.304 26.401 4.41 26.429 ;
     RECT  34.776 26.401 35.097 26.519 ;
     RECT  77.436 26.329 78.678 26.519 ;
     RECT  38.052 26.365 52.758 26.527 ;
     RECT  55.944 26.401 56.898 26.555 ;
     RECT  66.708 26.329 68.598 26.555 ;
     RECT  38.052 26.527 53.37 26.573 ;
     RECT  55.944 26.555 56.697 26.573 ;
     RECT  7.815 2.413 8.097 26.587 ;
     RECT  82.116 26.401 82.674 26.591 ;
     RECT  71.892 26.401 73.242 26.627 ;
     RECT  78.015 26.519 78.678 26.627 ;
     RECT  7.524 26.587 8.097 26.635 ;
     RECT  39.204 26.573 53.37 26.635 ;
     RECT  54.288 26.251 54.306 26.635 ;
     RECT  61.815 26.329 62.73 26.635 ;
     RECT  66.78 26.555 68.598 26.663 ;
     RECT  2.415 26.429 4.41 26.671 ;
     RECT  69.948 26.401 70.722 26.671 ;
     RECT  71.892 26.627 72.897 26.671 ;
     RECT  76.68 26.329 76.698 26.671 ;
     RECT  83.415 26.249 83.898 26.671 ;
     RECT  69.66 26.671 72.897 26.699 ;
     RECT  6.984 26.635 8.097 26.761 ;
     RECT  39.204 26.635 54.306 26.761 ;
     RECT  61.815 26.635 62.802 26.761 ;
     RECT  76.32 26.671 76.698 26.761 ;
     RECT  0.108 26.635 0.126 26.765 ;
     RECT  84.888 26.321 84.906 26.765 ;
     RECT  39.204 26.761 54.342 26.789 ;
     RECT  55.08 26.635 55.098 26.789 ;
     RECT  61.596 26.761 62.802 26.789 ;
     RECT  63.972 25.169 63.99 26.789 ;
     RECT  67.215 26.663 68.238 26.789 ;
     RECT  69.66 26.699 71.838 26.789 ;
     RECT  82.764 26.671 83.898 26.789 ;
     RECT  49.644 26.789 52.758 26.813 ;
     RECT  39.204 26.789 48.798 26.825 ;
     RECT  53.604 26.789 54.342 26.825 ;
     RECT  65.664 26.671 65.682 26.825 ;
     RECT  39.24 26.825 48.51 26.897 ;
     RECT  6.84 26.761 8.097 26.941 ;
     RECT  49.644 26.813 52.65 27.059 ;
     RECT  54.252 26.825 54.342 27.059 ;
     RECT  67.215 26.789 68.166 27.059 ;
     RECT  68.976 26.941 68.994 27.059 ;
     RECT  70.056 26.789 71.838 27.059 ;
     RECT  6.84 26.941 8.262 27.095 ;
     RECT  61.596 26.789 62.097 27.095 ;
     RECT  70.596 27.059 71.838 27.095 ;
     RECT  76.32 26.761 76.95 27.095 ;
     RECT  70.596 27.095 71.766 27.131 ;
     RECT  39.564 26.897 48.51 27.197 ;
     RECT  83.415 26.789 83.898 27.211 ;
     RECT  2.415 26.671 4.446 27.329 ;
     RECT  6.84 27.095 8.097 27.341 ;
     RECT  38.052 26.573 38.394 27.355 ;
     RECT  41.94 27.197 48.51 27.365 ;
     RECT  49.644 27.059 52.47 27.473 ;
     RECT  2.415 27.329 4.266 27.547 ;
     RECT  37.908 27.355 38.394 27.607 ;
     RECT  37.908 27.607 38.754 27.643 ;
     RECT  39.564 27.197 41.022 27.643 ;
     RECT  34.815 26.519 35.097 27.679 ;
     RECT  61.815 27.095 62.097 27.751 ;
     RECT  67.215 27.059 67.806 27.751 ;
     RECT  70.668 27.131 71.766 27.773 ;
     RECT  2.304 27.547 4.266 27.779 ;
     RECT  34.776 27.679 35.097 27.779 ;
     RECT  42.66 27.365 48.51 27.779 ;
     RECT  6.84 27.341 6.858 27.841 ;
     RECT  37.908 27.643 41.022 27.869 ;
     RECT  61.815 27.751 62.73 27.869 ;
     RECT  69.048 27.571 69.066 27.869 ;
     RECT  76.932 27.095 76.95 27.869 ;
     RECT  71.676 27.773 71.766 27.905 ;
     RECT  82.296 27.751 82.314 27.905 ;
     RECT  83.415 27.211 84.042 27.905 ;
     RECT  38.376 27.869 41.022 27.941 ;
     RECT  70.668 27.773 70.758 27.941 ;
     RECT  39.348 27.941 40.914 27.965 ;
     RECT  85.464 27.103 85.482 27.979 ;
     RECT  45.252 27.779 48.51 27.985 ;
     RECT  49.644 27.473 52.434 27.985 ;
     RECT  71.676 27.905 71.694 28.049 ;
     RECT  6.804 27.841 6.858 28.075 ;
     RECT  6.156 28.075 6.858 28.111 ;
     RECT  66.852 27.751 67.806 28.111 ;
     RECT  6.156 28.111 6.966 28.139 ;
     RECT  45.252 27.985 52.434 28.139 ;
     RECT  6.804 28.139 6.966 28.147 ;
     RECT  7.815 27.341 8.097 28.147 ;
     RECT  5.22 28.111 5.238 28.219 ;
     RECT  45.252 28.139 48.438 28.283 ;
     RECT  5.112 28.219 5.238 28.291 ;
     RECT  66.852 28.111 68.814 28.291 ;
     RECT  72.615 26.699 72.897 28.291 ;
     RECT  74.916 28.111 74.934 28.291 ;
     RECT  78.015 26.627 78.297 28.291 ;
     RECT  6.804 28.147 8.097 28.319 ;
     RECT  54.252 27.059 54.27 28.381 ;
     RECT  60.336 27.409 60.354 28.381 ;
     RECT  74.916 28.291 75.15 28.381 ;
     RECT  5.004 28.291 5.238 28.409 ;
     RECT  45.252 28.283 46.746 28.409 ;
     RECT  59.4 28.363 59.418 28.409 ;
     RECT  60.336 28.381 60.858 28.409 ;
     RECT  72.615 28.291 73.314 28.409 ;
     RECT  5.004 28.409 5.022 28.445 ;
     RECT  83.415 27.905 83.898 28.445 ;
     RECT  84.888 27.979 85.482 28.445 ;
     RECT  49.176 28.139 52.434 28.451 ;
     RECT  74.916 28.381 75.222 28.453 ;
     RECT  7.092 28.319 8.097 28.481 ;
     RECT  74.736 28.453 75.222 28.489 ;
     RECT  66.456 28.291 68.814 28.493 ;
     RECT  54.252 28.381 54.666 28.561 ;
     RECT  60.84 28.409 60.858 28.561 ;
     RECT  70.668 27.941 70.686 28.561 ;
     RECT  78.015 28.291 78.678 28.589 ;
     RECT  39.42 27.965 40.914 28.679 ;
     RECT  60.84 28.561 60.966 28.679 ;
     RECT  61.815 27.869 62.694 28.679 ;
     RECT  68.364 28.493 68.814 28.679 ;
     RECT  79.416 28.561 79.434 28.679 ;
     RECT  39.564 28.679 40.914 28.715 ;
     RECT  60.84 28.679 60.858 28.715 ;
     RECT  66.456 28.493 67.497 28.715 ;
     RECT  76.032 28.381 76.05 28.715 ;
     RECT  2.415 27.779 4.266 28.723 ;
     RECT  39.636 28.715 40.914 28.751 ;
     RECT  74.664 28.489 75.222 28.787 ;
     RECT  71.856 28.747 71.874 28.789 ;
     RECT  72.615 28.409 72.897 28.789 ;
     RECT  2.415 28.723 4.59 28.795 ;
     RECT  42.66 27.779 44.226 28.795 ;
     RECT  53.712 28.561 54.666 28.795 ;
     RECT  83.415 28.445 83.862 28.795 ;
     RECT  84.888 28.445 84.906 28.795 ;
     RECT  39.672 28.751 40.914 28.823 ;
     RECT  71.856 28.789 72.897 28.823 ;
     RECT  75.204 28.787 75.222 28.823 ;
     RECT  2.304 28.795 4.59 28.829 ;
     RECT  72.216 28.823 72.897 28.829 ;
     RECT  49.608 28.451 52.434 28.831 ;
     RECT  53.208 28.795 54.666 28.831 ;
     RECT  2.304 28.829 2.898 28.859 ;
     RECT  79.308 28.687 79.326 28.859 ;
     RECT  49.608 28.831 54.666 28.949 ;
     RECT  83.304 28.795 83.862 28.949 ;
     RECT  67.068 28.715 67.497 28.985 ;
     RECT  57.564 28.831 57.582 29.021 ;
     RECT  68.688 28.679 68.814 29.021 ;
     RECT  39.708 28.823 40.914 29.029 ;
     RECT  39.708 29.029 41.598 29.035 ;
     RECT  42.48 28.795 44.226 29.035 ;
     RECT  54.648 28.949 54.666 29.057 ;
     RECT  58.716 28.651 58.734 29.057 ;
     RECT  70.596 28.561 70.686 29.065 ;
     RECT  39.708 29.035 41.634 29.069 ;
     RECT  39.96 29.069 41.634 29.129 ;
     RECT  59.508 29.179 59.526 29.219 ;
     RECT  49.608 28.949 52.578 29.255 ;
     RECT  0.108 28.993 0.126 29.261 ;
     RECT  70.128 29.065 70.686 29.261 ;
     RECT  45.252 28.409 46.35 29.263 ;
     RECT  52.416 29.255 52.578 29.291 ;
     RECT  47.484 28.283 48.438 29.299 ;
     RECT  45.18 29.263 46.35 29.323 ;
     RECT  47.268 29.299 48.69 29.323 ;
     RECT  40.104 29.129 41.634 29.335 ;
     RECT  42.48 29.035 44.298 29.335 ;
     RECT  84.852 28.795 84.906 29.363 ;
     RECT  3.924 28.829 4.59 29.371 ;
     RECT  40.104 29.335 44.298 29.371 ;
     RECT  45.18 29.323 48.69 29.371 ;
     RECT  49.608 29.255 51.642 29.371 ;
     RECT  70.668 29.261 70.686 29.371 ;
     RECT  82.656 29.263 82.674 29.371 ;
     RECT  38.376 27.941 38.394 29.461 ;
     RECT  5.796 29.419 5.814 29.489 ;
     RECT  40.104 29.371 51.642 29.489 ;
     RECT  52.416 29.291 52.542 29.489 ;
     RECT  64.728 29.191 64.746 29.489 ;
     RECT  69.408 29.371 69.534 29.489 ;
     RECT  76.464 29.191 76.482 29.489 ;
     RECT  46.728 29.489 51.642 29.501 ;
     RECT  52.416 29.489 52.434 29.525 ;
     RECT  47.268 29.501 51.642 29.561 ;
     RECT  60.444 29.371 60.462 29.597 ;
     RECT  3.924 29.371 4.878 29.633 ;
     RECT  69.516 29.489 69.534 29.633 ;
     RECT  56.415 26.573 56.697 29.641 ;
     RECT  2.415 28.859 2.898 29.659 ;
     RECT  84.888 29.363 84.906 29.659 ;
     RECT  40.104 29.489 45.897 29.669 ;
     RECT  2.304 29.659 2.898 29.731 ;
     RECT  3.924 29.633 4.194 29.731 ;
     RECT  56.415 29.641 57.33 29.731 ;
     RECT  56.376 29.731 57.33 29.789 ;
     RECT  56.415 29.789 57.33 29.795 ;
     RECT  40.104 29.669 42.282 29.867 ;
     RECT  70.668 29.371 71.19 29.875 ;
     RECT  47.34 29.561 51.642 29.903 ;
     RECT  40.104 29.867 41.814 29.911 ;
     RECT  72.615 28.829 72.897 29.911 ;
     RECT  82.224 29.371 82.674 29.911 ;
     RECT  83.415 28.949 83.862 29.911 ;
     RECT  6.804 29.731 6.822 29.939 ;
     RECT  39.96 29.911 41.814 29.981 ;
     RECT  64.044 29.731 64.062 30.029 ;
     RECT  77.004 29.731 77.022 30.029 ;
     RECT  34.815 27.779 35.097 30.037 ;
     RECT  67.215 28.985 67.497 30.037 ;
     RECT  82.08 29.911 82.674 30.065 ;
     RECT  34.776 30.037 35.097 30.137 ;
     RECT  38.376 29.461 38.79 30.145 ;
     RECT  72.36 29.911 72.897 30.173 ;
     RECT  66.708 30.037 67.497 30.235 ;
     RECT  78.015 28.589 78.297 30.271 ;
     RECT  83.415 29.911 84.042 30.271 ;
     RECT  2.304 29.731 4.194 30.299 ;
     RECT  66.708 30.235 68.166 30.299 ;
     RECT  75.132 30.235 75.15 30.335 ;
     RECT  43.092 29.669 45.897 30.379 ;
     RECT  38.088 30.145 38.79 30.415 ;
     RECT  72.615 30.173 72.897 30.415 ;
     RECT  5.724 30.091 5.742 30.451 ;
     RECT  37.944 30.415 38.79 30.451 ;
     RECT  43.092 30.379 46.602 30.479 ;
     RECT  74.988 30.451 75.006 30.569 ;
     RECT  78.015 30.271 78.966 30.569 ;
     RECT  70.668 29.875 71.442 30.605 ;
     RECT  84.888 29.659 85.482 30.605 ;
     RECT  37.944 30.451 39.222 30.613 ;
     RECT  76.104 30.451 76.122 30.641 ;
     RECT  82.764 30.271 84.042 30.641 ;
     RECT  47.34 29.903 51.297 30.649 ;
     RECT  78.015 30.569 78.894 30.713 ;
     RECT  5.652 30.451 5.742 30.721 ;
     RECT  36.756 26.333 36.774 30.721 ;
     RECT  37.548 30.613 39.222 30.721 ;
     RECT  40.215 29.981 41.814 30.721 ;
     RECT  43.092 30.479 46.566 30.749 ;
     RECT  36.756 30.721 39.366 30.763 ;
     RECT  40.176 30.721 41.814 30.763 ;
     RECT  56.415 29.795 56.697 30.805 ;
     RECT  43.092 30.749 46.53 30.811 ;
     RECT  57.852 30.649 57.87 30.811 ;
     RECT  58.68 30.763 58.698 30.811 ;
     RECT  57.852 30.811 58.698 30.839 ;
     RECT  83.232 30.641 84.042 30.839 ;
     RECT  56.415 30.805 56.934 30.845 ;
     RECT  71.496 30.721 71.514 30.847 ;
     RECT  83.232 30.839 83.898 30.875 ;
     RECT  36.756 30.763 41.814 30.883 ;
     RECT  42.804 30.811 46.53 30.907 ;
     RECT  71.496 30.847 71.838 30.983 ;
     RECT  5.616 30.721 5.742 30.991 ;
     RECT  36.756 30.883 41.886 30.991 ;
     RECT  42.66 30.907 46.53 30.991 ;
     RECT  72.615 30.415 73.314 30.991 ;
     RECT  78.015 30.713 78.678 30.991 ;
     RECT  2.304 30.299 4.05 31.019 ;
     RECT  5.616 30.991 6.354 31.081 ;
     RECT  70.668 30.605 70.758 31.099 ;
     RECT  71.82 30.983 71.838 31.099 ;
     RECT  72.612 30.991 73.314 31.099 ;
     RECT  77.472 30.991 78.678 31.109 ;
     RECT  66.708 30.299 67.497 31.117 ;
     RECT  2.415 31.019 4.05 31.145 ;
     RECT  58.464 30.839 58.626 31.145 ;
     RECT  71.82 31.099 73.314 31.145 ;
     RECT  34.815 30.137 35.097 31.153 ;
     RECT  78.015 31.109 78.678 31.181 ;
     RECT  4.932 31.081 6.354 31.189 ;
     RECT  7.815 28.481 8.097 31.189 ;
     RECT  54.684 31.081 54.702 31.189 ;
     RECT  36.756 30.991 46.53 31.217 ;
     RECT  52.056 30.991 52.074 31.217 ;
     RECT  60.624 31.081 60.642 31.225 ;
     RECT  34.776 31.153 35.097 31.253 ;
     RECT  54.684 31.189 54.81 31.253 ;
     RECT  66.6 31.117 67.497 31.253 ;
     RECT  82.332 31.153 82.35 31.253 ;
     RECT  47.304 30.649 51.297 31.261 ;
     RECT  70.38 31.099 70.758 31.261 ;
     RECT  72.615 31.145 73.314 31.261 ;
     RECT  4.32 31.189 6.354 31.289 ;
     RECT  54.792 31.253 54.81 31.289 ;
     RECT  63.864 30.847 63.882 31.289 ;
     RECT  70.128 31.261 70.758 31.291 ;
     RECT  0.54 31.261 0.558 31.373 ;
     RECT  4.32 31.289 5.706 31.379 ;
     RECT  71.82 31.145 71.838 31.379 ;
     RECT  83.232 30.875 83.862 31.379 ;
     RECT  60.624 31.225 60.75 31.415 ;
     RECT  65.268 31.189 65.286 31.415 ;
     RECT  76.392 31.225 76.41 31.415 ;
     RECT  61.815 28.679 62.097 31.423 ;
     RECT  69.768 31.291 70.758 31.423 ;
     RECT  72.615 31.261 73.422 31.423 ;
     RECT  2.415 31.145 3.582 31.451 ;
     RECT  5.688 31.379 5.706 31.451 ;
     RECT  58.608 31.145 58.626 31.451 ;
     RECT  35.82 27.751 35.838 31.459 ;
     RECT  36.756 31.217 41.922 31.459 ;
     RECT  34.815 31.253 35.097 31.495 ;
     RECT  35.82 31.459 41.922 31.495 ;
     RECT  4.32 31.379 4.95 31.523 ;
     RECT  7.236 31.189 8.097 31.523 ;
     RECT  69.768 31.423 70.83 31.523 ;
     RECT  72.615 31.423 73.494 31.523 ;
     RECT  47.304 31.261 51.858 31.531 ;
     RECT  61.815 31.423 62.73 31.559 ;
     RECT  74.664 31.423 74.682 31.559 ;
     RECT  42.696 31.217 46.53 31.621 ;
     RECT  47.268 31.531 51.858 31.621 ;
     RECT  84.888 30.605 84.906 31.657 ;
     RECT  42.696 31.621 51.858 31.721 ;
     RECT  84.888 31.657 84.942 31.757 ;
     RECT  61.815 31.559 62.097 31.765 ;
     RECT  69.768 31.523 70.218 31.765 ;
     RECT  83.415 31.379 83.862 31.801 ;
     RECT  84.924 31.757 84.942 31.805 ;
     RECT  69.624 31.765 70.218 31.891 ;
     RECT  52.992 31.891 53.01 31.927 ;
     RECT  82.62 31.891 82.638 31.991 ;
     RECT  34.815 31.495 41.922 32.011 ;
     RECT  42.696 31.721 51.297 32.011 ;
     RECT  83.415 31.801 83.898 32.035 ;
     RECT  4.32 31.523 4.338 32.071 ;
     RECT  2.415 31.451 3.51 32.155 ;
     RECT  52.848 31.927 53.01 32.189 ;
     RECT  83.415 32.035 84.042 32.189 ;
     RECT  2.304 32.155 3.51 32.197 ;
     RECT  4.284 32.071 4.338 32.197 ;
     RECT  34.815 32.011 51.297 32.225 ;
     RECT  69.552 31.891 70.218 32.225 ;
     RECT  75.96 31.891 75.978 32.225 ;
     RECT  85.464 32.155 85.482 32.261 ;
     RECT  69.552 32.225 69.57 32.297 ;
     RECT  34.815 32.225 38.79 32.299 ;
     RECT  2.304 32.197 4.338 32.341 ;
     RECT  78.015 31.181 78.297 32.341 ;
     RECT  83.415 32.189 83.898 32.341 ;
     RECT  2.304 32.341 4.446 32.369 ;
     RECT  2.415 32.369 4.446 32.431 ;
     RECT  5.76 32.341 5.778 32.431 ;
     RECT  72.615 31.523 72.897 32.431 ;
     RECT  2.415 32.431 5.778 32.459 ;
     RECT  52.596 32.341 52.614 32.459 ;
     RECT  83.376 32.341 83.898 32.467 ;
     RECT  2.415 32.459 5.634 32.477 ;
     RECT  34.74 32.299 38.79 32.495 ;
     RECT  82.836 32.467 83.898 32.495 ;
     RECT  39.816 32.225 51.297 32.567 ;
     RECT  39.888 32.567 51.297 32.575 ;
     RECT  6.84 31.801 6.858 32.611 ;
     RECT  72.252 32.431 72.897 32.611 ;
     RECT  67.215 31.253 67.497 32.701 ;
     RECT  72.252 32.611 73.458 32.731 ;
     RECT  77.688 32.341 78.297 32.765 ;
     RECT  55.296 32.611 55.386 32.837 ;
     RECT  6.552 32.611 6.858 32.873 ;
     RECT  71.748 32.731 73.458 32.873 ;
     RECT  52.524 32.809 52.542 32.881 ;
     RECT  61.308 31.765 62.097 32.881 ;
     RECT  62.964 32.611 62.982 32.881 ;
     RECT  71.748 32.873 72.897 32.881 ;
     RECT  52.452 32.881 52.542 32.909 ;
     RECT  54.792 32.845 54.81 32.909 ;
     RECT  74.664 32.773 74.682 32.909 ;
     RECT  52.452 32.909 52.47 32.999 ;
     RECT  62.964 32.881 63.054 32.999 ;
     RECT  77.868 32.765 78.297 32.999 ;
     RECT  84.888 32.587 84.906 33.019 ;
     RECT  39.888 32.575 51.678 33.035 ;
     RECT  81.504 32.611 81.522 33.035 ;
     RECT  82.836 32.495 83.862 33.035 ;
     RECT  76.392 33.007 76.41 33.043 ;
     RECT  6.84 32.873 6.858 33.071 ;
     RECT  39.888 33.035 46.818 33.071 ;
     RECT  34.815 32.495 38.79 33.151 ;
     RECT  71.1 32.881 72.897 33.151 ;
     RECT  2.415 32.477 5.31 33.269 ;
     RECT  39.888 33.071 46.674 33.269 ;
     RECT  47.772 33.035 51.678 33.269 ;
     RECT  70.704 33.151 72.897 33.269 ;
     RECT  61.2 32.881 62.097 33.305 ;
     RECT  73.944 33.067 74.358 33.305 ;
     RECT  76.392 33.043 76.842 33.305 ;
     RECT  84.888 33.019 85.482 33.305 ;
     RECT  81.972 33.043 82.062 33.313 ;
     RECT  34.815 33.151 38.862 33.385 ;
     RECT  39.888 33.269 46.53 33.385 ;
     RECT  66.744 32.701 67.497 33.385 ;
     RECT  34.815 33.385 46.53 33.413 ;
     RECT  17.172 33.239 17.19 33.421 ;
     RECT  66.672 33.385 67.497 33.421 ;
     RECT  66.672 33.421 67.626 33.437 ;
     RECT  76.392 33.305 76.41 33.449 ;
     RECT  0.108 33.307 0.126 33.485 ;
     RECT  17.136 33.421 17.19 33.485 ;
     RECT  2.415 33.269 5.166 33.539 ;
     RECT  17.172 33.485 17.19 33.539 ;
     RECT  66.816 33.437 67.626 33.539 ;
     RECT  81.972 33.313 82.674 33.539 ;
     RECT  74.268 33.305 74.358 33.575 ;
     RECT  81.972 33.539 81.99 33.575 ;
     RECT  47.772 33.269 51.297 33.581 ;
     RECT  34.815 33.413 46.494 33.611 ;
     RECT  74.268 33.575 74.286 33.719 ;
     RECT  35.892 33.611 46.494 33.809 ;
     RECT  2.415 33.539 4.59 33.835 ;
     RECT  84.888 33.305 84.906 33.835 ;
     RECT  47.808 33.581 51.297 33.845 ;
     RECT  36.684 33.809 46.494 33.881 ;
     RECT  67.215 33.539 67.626 33.989 ;
     RECT  36.684 33.881 39.186 34.013 ;
     RECT  52.236 33.925 52.254 34.051 ;
     RECT  52.236 34.051 52.434 34.075 ;
     RECT  54.72 33.925 54.738 34.079 ;
     RECT  84.852 33.835 84.906 34.087 ;
     RECT  36.684 34.013 39.078 34.115 ;
     RECT  52.092 34.075 52.434 34.151 ;
     RECT  6.84 34.051 6.858 34.187 ;
     RECT  37.548 34.115 38.718 34.205 ;
     RECT  40.215 33.881 46.494 34.219 ;
     RECT  84.852 34.087 85.482 34.301 ;
     RECT  40.215 34.219 46.53 34.349 ;
     RECT  77.148 33.781 77.166 34.349 ;
     RECT  84.852 34.301 85.122 34.349 ;
     RECT  2.304 33.835 4.59 34.385 ;
     RECT  71.1 33.269 72.897 34.459 ;
     RECT  83.415 33.035 83.862 34.465 ;
     RECT  5.58 34.231 5.598 34.493 ;
     RECT  37.62 34.205 38.718 34.493 ;
     RECT  80.964 33.961 80.982 34.493 ;
     RECT  71.1 34.459 72.954 34.501 ;
     RECT  47.88 33.845 51.297 34.591 ;
     RECT  52.092 34.151 52.362 34.591 ;
     RECT  71.1 34.501 73.098 34.591 ;
     RECT  2.415 34.385 4.59 34.627 ;
     RECT  61.815 33.305 62.097 34.627 ;
     RECT  37.728 34.493 38.718 34.655 ;
     RECT  40.215 34.349 46.386 34.655 ;
     RECT  47.88 34.591 52.362 34.655 ;
     RECT  45.144 34.655 46.386 34.691 ;
     RECT  47.88 34.655 52.254 34.691 ;
     RECT  37.836 34.655 38.718 34.727 ;
     RECT  37.836 34.727 37.854 34.763 ;
     RECT  45.144 34.691 46.35 34.763 ;
     RECT  61.815 34.627 62.262 34.771 ;
     RECT  76.968 34.501 77.058 34.771 ;
     RECT  2.415 34.627 4.914 34.799 ;
     RECT  7.815 31.523 8.097 34.861 ;
     RECT  61.815 34.771 62.37 34.861 ;
     RECT  6.48 34.795 6.498 34.889 ;
     RECT  71.1 34.591 73.53 34.891 ;
     RECT  71.1 34.891 74.142 34.925 ;
     RECT  82.656 34.591 82.674 34.933 ;
     RECT  83.415 34.465 84.042 34.933 ;
     RECT  67.215 33.989 67.497 34.969 ;
     RECT  81.504 34.735 81.522 34.997 ;
     RECT  61.815 34.861 62.694 35.033 ;
     RECT  71.676 34.925 74.142 35.033 ;
     RECT  58.788 34.969 58.806 35.041 ;
     RECT  69.876 34.861 69.894 35.041 ;
     RECT  72.615 35.033 74.142 35.041 ;
     RECT  82.656 34.933 84.042 35.041 ;
     RECT  58.716 35.041 58.806 35.069 ;
     RECT  66.132 35.005 66.15 35.069 ;
     RECT  2.415 34.799 4.734 35.131 ;
     RECT  85.104 34.349 85.122 35.131 ;
     RECT  2.304 35.131 4.734 35.159 ;
     RECT  58.716 35.069 58.734 35.159 ;
     RECT  60.552 35.041 60.57 35.159 ;
     RECT  65.34 34.861 65.358 35.159 ;
     RECT  69.876 35.041 70.722 35.159 ;
     RECT  76.896 34.771 77.058 35.159 ;
     RECT  2.304 35.159 4.518 35.168 ;
     RECT  2.415 35.168 4.518 35.195 ;
     RECT  71.676 35.033 71.694 35.195 ;
     RECT  82.224 35.041 84.042 35.195 ;
     RECT  47.88 34.691 51.822 35.231 ;
     RECT  82.224 35.195 82.674 35.231 ;
     RECT  47.88 35.231 51.297 35.275 ;
     RECT  7.416 34.861 8.097 35.303 ;
     RECT  56.415 30.845 56.697 35.323 ;
     RECT  59.544 35.005 59.562 35.357 ;
     RECT  78.015 32.999 78.297 35.401 ;
     RECT  47.844 35.275 51.297 35.429 ;
     RECT  56.412 35.323 56.697 35.465 ;
     RECT  38.7 34.727 38.718 35.509 ;
     RECT  84.888 35.131 85.122 35.515 ;
     RECT  40.215 34.655 44.226 35.581 ;
     RECT  45.144 34.763 46.17 35.581 ;
     RECT  72.615 35.041 74.682 35.581 ;
     RECT  6.84 35.509 6.858 35.609 ;
     RECT  54.72 35.509 54.738 35.609 ;
     RECT  65.376 35.401 65.394 35.699 ;
     RECT  78.015 35.401 78.462 35.699 ;
     RECT  67.104 34.969 67.497 35.707 ;
     RECT  2.415 35.195 4.374 35.735 ;
     RECT  70.704 35.159 70.722 35.735 ;
     RECT  47.916 35.429 51.297 35.741 ;
     RECT  47.916 35.741 49.698 35.771 ;
     RECT  84.888 35.515 85.482 35.771 ;
     RECT  40.215 35.581 46.17 35.815 ;
     RECT  66.708 35.707 67.497 35.843 ;
     RECT  50.508 35.741 51.297 35.885 ;
     RECT  2.415 35.735 4.122 35.947 ;
     RECT  72.615 35.581 75.078 35.969 ;
     RECT  38.7 35.509 38.79 35.977 ;
     RECT  38.7 35.977 39.258 36.013 ;
     RECT  40.215 35.815 46.278 36.013 ;
     RECT  38.7 36.013 46.278 36.049 ;
     RECT  38.7 36.049 46.746 36.085 ;
     RECT  82.296 35.231 82.674 36.121 ;
     RECT  34.815 33.611 35.097 36.247 ;
     RECT  47.916 35.771 48.978 36.311 ;
     RECT  38.7 36.085 46.854 36.391 ;
     RECT  2.304 35.947 4.122 36.419 ;
     RECT  38.412 36.391 46.854 36.419 ;
     RECT  38.412 36.419 44.442 36.475 ;
     RECT  6.804 36.211 6.822 36.481 ;
     RECT  74.88 35.969 75.078 36.481 ;
     RECT  78.015 35.699 78.297 36.481 ;
     RECT  65.232 36.481 65.25 36.517 ;
     RECT  57.708 36.475 57.726 36.545 ;
     RECT  65.232 36.517 65.502 36.557 ;
     RECT  70.452 36.481 70.722 36.589 ;
     RECT  74.88 36.481 75.438 36.589 ;
     RECT  2.415 36.419 4.122 36.619 ;
     RECT  5.112 36.481 5.13 36.619 ;
     RECT  51.015 35.885 51.297 36.625 ;
     RECT  72.615 35.969 74.106 36.653 ;
     RECT  6.804 36.481 6.858 36.661 ;
     RECT  38.34 36.475 44.442 36.661 ;
     RECT  45.288 36.419 46.854 36.661 ;
     RECT  47.916 36.311 47.97 36.661 ;
     RECT  50.4 36.625 51.297 36.661 ;
     RECT  67.215 35.843 67.497 36.661 ;
     RECT  70.452 36.589 70.758 36.661 ;
     RECT  77.58 36.481 78.297 36.661 ;
     RECT  54.792 36.589 54.81 36.689 ;
     RECT  2.415 36.619 5.13 36.751 ;
     RECT  6.804 36.661 6.93 36.779 ;
     RECT  34.776 36.247 35.097 36.779 ;
     RECT  65.232 36.557 65.25 36.779 ;
     RECT  61.815 35.033 62.097 36.787 ;
     RECT  84.888 35.771 84.906 36.811 ;
     RECT  2.415 36.751 5.346 36.815 ;
     RECT  70.452 36.661 70.794 36.815 ;
     RECT  77.58 36.661 78.822 36.815 ;
     RECT  74.88 36.589 76.05 36.823 ;
     RECT  70.74 36.815 70.794 36.851 ;
     RECT  66.708 36.661 67.497 36.887 ;
     RECT  74.88 36.823 76.086 36.923 ;
     RECT  4.824 36.815 5.346 36.931 ;
     RECT  82.224 36.121 82.674 36.931 ;
     RECT  48.852 36.311 48.978 36.959 ;
     RECT  50.4 36.661 51.822 36.959 ;
     RECT  71.064 36.859 71.082 37.021 ;
     RECT  4.824 36.931 5.418 37.049 ;
     RECT  50.4 36.959 51.75 37.049 ;
     RECT  61.815 36.787 62.658 37.049 ;
     RECT  69.192 36.859 69.21 37.049 ;
     RECT  69.984 36.931 70.002 37.049 ;
     RECT  72.615 36.653 74.034 37.049 ;
     RECT  83.415 35.195 84.042 37.049 ;
     RECT  50.4 37.049 51.297 37.085 ;
     RECT  61.815 37.049 62.514 37.085 ;
     RECT  49.212 37.021 49.23 37.121 ;
     RECT  84.888 36.811 85.482 37.121 ;
     RECT  69.048 37.057 69.066 37.133 ;
     RECT  38.088 36.661 44.442 37.201 ;
     RECT  45.288 36.661 47.97 37.201 ;
     RECT  74.88 36.923 75.798 37.201 ;
     RECT  84.888 37.121 84.906 37.229 ;
     RECT  38.016 37.201 47.97 37.277 ;
     RECT  71.064 37.021 71.802 37.319 ;
     RECT  74.808 37.201 75.798 37.319 ;
     RECT  77.58 36.815 78.678 37.319 ;
     RECT  81.972 36.931 82.674 37.319 ;
     RECT  34.815 36.779 35.097 37.327 ;
     RECT  35.892 33.809 35.91 37.327 ;
     RECT  2.415 36.815 4.086 37.355 ;
     RECT  71.784 37.319 71.802 37.391 ;
     RECT  75.78 37.319 75.798 37.391 ;
     RECT  4.824 37.049 4.842 37.463 ;
     RECT  74.808 37.319 74.898 37.463 ;
     RECT  81.972 37.319 82.062 37.463 ;
     RECT  30.78 37.327 30.798 37.499 ;
     RECT  74.88 37.463 74.898 37.499 ;
     RECT  82.044 37.463 82.062 37.499 ;
     RECT  38.7 37.277 47.97 37.561 ;
     RECT  6.804 36.779 6.822 37.589 ;
     RECT  0.54 36.931 0.558 37.661 ;
     RECT  86.292 37.597 86.31 37.661 ;
     RECT  52.02 37.705 52.038 37.859 ;
     RECT  34.815 37.327 35.91 37.867 ;
     RECT  36.684 34.115 36.702 37.867 ;
     RECT  61.815 37.085 62.097 37.867 ;
     RECT  38.7 37.561 48.222 37.895 ;
     RECT  70.74 37.831 70.758 37.939 ;
     RECT  38.7 37.895 44.334 37.967 ;
     RECT  34.815 37.867 36.702 37.975 ;
     RECT  45.072 37.895 48.222 37.975 ;
     RECT  38.7 37.967 44.226 38.003 ;
     RECT  49.86 37.975 49.878 38.011 ;
     RECT  51.015 37.085 51.297 38.011 ;
     RECT  61.815 37.867 62.154 38.011 ;
     RECT  72.615 37.049 73.89 38.011 ;
     RECT  77.58 37.319 78.297 38.011 ;
     RECT  2.415 37.355 4.014 38.059 ;
     RECT  2.304 38.059 4.014 38.101 ;
     RECT  45.072 37.975 48.798 38.107 ;
     RECT  49.86 38.011 49.95 38.107 ;
     RECT  50.724 38.011 51.297 38.107 ;
     RECT  70.704 37.939 70.758 38.129 ;
     RECT  72.615 38.011 73.998 38.129 ;
     RECT  70.74 38.129 70.758 38.165 ;
     RECT  83.415 37.049 83.898 38.173 ;
     RECT  42.336 38.003 44.154 38.201 ;
     RECT  2.304 38.101 4.338 38.203 ;
     RECT  38.7 38.003 41.598 38.237 ;
     RECT  2.304 38.203 4.626 38.245 ;
     RECT  38.7 38.237 41.526 38.245 ;
     RECT  45.072 38.107 48.978 38.281 ;
     RECT  49.86 38.107 51.297 38.281 ;
     RECT  72.615 38.129 73.71 38.281 ;
     RECT  77.544 38.011 78.297 38.281 ;
     RECT  72 38.281 73.71 38.395 ;
     RECT  74.448 38.281 74.61 38.399 ;
     RECT  77.544 38.281 78.354 38.407 ;
     RECT  71.856 38.395 73.71 38.429 ;
     RECT  45.072 38.281 51.297 38.435 ;
     RECT  61.056 38.011 61.074 38.435 ;
     RECT  64.98 38.245 64.998 38.435 ;
     RECT  74.448 38.399 74.538 38.435 ;
     RECT  34.815 37.975 37.134 38.479 ;
     RECT  67.215 36.887 67.497 38.479 ;
     RECT  71.856 38.429 72.954 38.479 ;
     RECT  81.504 38.281 81.522 38.507 ;
     RECT  34.815 38.479 37.818 38.515 ;
     RECT  38.628 38.245 41.526 38.515 ;
     RECT  61.815 38.011 62.73 38.539 ;
     RECT  49.284 38.435 51.297 38.543 ;
     RECT  2.304 38.245 5.094 38.551 ;
     RECT  71.604 38.479 72.954 38.551 ;
     RECT  77.328 38.407 78.354 38.551 ;
     RECT  83.376 38.173 83.898 38.551 ;
     RECT  64.008 38.515 64.026 38.573 ;
     RECT  2.304 38.551 5.13 38.579 ;
     RECT  34.815 38.515 41.526 38.669 ;
     RECT  50.292 38.543 51.297 38.669 ;
     RECT  68.724 38.371 68.742 38.669 ;
     RECT  71.532 38.551 72.954 38.669 ;
     RECT  77.184 38.551 78.75 38.669 ;
     RECT  66.708 38.479 67.497 38.705 ;
     RECT  73.692 38.429 73.71 38.705 ;
     RECT  77.184 38.669 77.202 38.705 ;
     RECT  82.728 38.551 83.97 38.705 ;
     RECT  85.464 38.059 85.482 38.705 ;
     RECT  49.284 38.543 49.302 38.741 ;
     RECT  72.072 38.669 72.954 38.741 ;
     RECT  78.015 38.669 78.75 38.741 ;
     RECT  2.415 38.579 5.13 38.777 ;
     RECT  42.408 38.201 44.154 38.779 ;
     RECT  45.072 38.435 48.438 38.779 ;
     RECT  61.815 38.539 63.162 38.849 ;
     RECT  0.54 38.479 0.558 38.909 ;
     RECT  2.415 38.777 4.662 38.939 ;
     RECT  61.815 38.849 62.766 38.939 ;
     RECT  83.415 38.705 83.97 38.939 ;
     RECT  38.304 38.669 41.526 39.055 ;
     RECT  42.408 38.779 48.438 39.055 ;
     RECT  74.52 38.435 74.538 39.083 ;
     RECT  30.78 39.019 30.798 39.119 ;
     RECT  2.415 38.939 4.554 39.293 ;
     RECT  72.615 38.741 72.954 39.355 ;
     RECT  34.815 38.669 37.566 39.451 ;
     RECT  38.304 39.055 48.438 39.451 ;
     RECT  83.415 38.939 83.898 39.451 ;
     RECT  65.484 39.355 65.502 39.515 ;
     RECT  82.8 39.451 83.898 39.551 ;
     RECT  34.815 39.451 48.438 39.559 ;
     RECT  4.176 39.293 4.554 39.623 ;
     RECT  2.415 39.293 3.402 39.631 ;
     RECT  51.015 38.669 51.297 39.631 ;
     RECT  78.015 38.741 78.297 39.631 ;
     RECT  66.42 39.361 66.438 39.659 ;
     RECT  72.615 39.355 73.134 39.721 ;
     RECT  84.888 38.875 84.906 39.739 ;
     RECT  50.292 39.631 51.297 39.749 ;
     RECT  70.848 39.451 70.866 39.749 ;
     RECT  75.852 39.451 75.87 39.749 ;
     RECT  67.215 38.705 67.497 39.757 ;
     RECT  72.144 39.721 73.134 39.757 ;
     RECT  34.776 39.559 48.438 39.835 ;
     RECT  30.852 39.595 30.87 39.857 ;
     RECT  66.708 39.757 67.497 39.857 ;
     RECT  83.415 39.551 83.898 39.865 ;
     RECT  34.668 39.835 48.438 39.883 ;
     RECT  49.32 39.865 49.338 39.883 ;
     RECT  6.804 39.793 6.822 39.893 ;
     RECT  34.668 39.883 49.338 39.893 ;
     RECT  78.015 39.631 78.678 39.893 ;
     RECT  60.948 39.757 60.966 39.901 ;
     RECT  60.948 39.901 61.074 39.991 ;
     RECT  34.776 39.893 49.338 40.019 ;
     RECT  60.516 39.991 61.074 40.019 ;
     RECT  83.415 39.865 84.042 40.019 ;
     RECT  60.516 40.019 60.966 40.055 ;
     RECT  84.888 39.739 85.482 40.091 ;
     RECT  2.376 39.631 3.402 40.135 ;
     RECT  4.176 39.623 4.338 40.135 ;
     RECT  42.192 40.019 49.338 40.135 ;
     RECT  34.776 40.019 41.202 40.163 ;
     RECT  72.144 39.757 73.278 40.171 ;
     RECT  7.815 35.303 8.097 40.261 ;
     RECT  78.015 39.893 78.297 40.261 ;
     RECT  0.108 40.171 0.126 40.289 ;
     RECT  36.684 40.163 41.202 40.289 ;
     RECT  42.192 40.135 49.734 40.289 ;
     RECT  60.516 40.055 60.534 40.289 ;
     RECT  69.984 40.171 70.002 40.289 ;
     RECT  71.748 40.171 73.278 40.289 ;
     RECT  71.784 40.289 73.278 40.297 ;
     RECT  74.052 39.631 74.07 40.297 ;
     RECT  49.248 40.289 49.734 40.325 ;
     RECT  82.332 40.261 82.35 40.333 ;
     RECT  83.415 40.019 83.862 40.333 ;
     RECT  69.048 40.297 69.066 40.349 ;
     RECT  71.784 40.297 74.07 40.349 ;
     RECT  36.684 40.289 37.71 40.397 ;
     RECT  71.784 40.349 71.838 40.397 ;
     RECT  75.6 39.865 75.618 40.405 ;
     RECT  49.248 40.325 49.266 40.433 ;
     RECT  72.615 40.349 74.07 40.441 ;
     RECT  81.504 39.865 81.522 40.441 ;
     RECT  82.332 40.333 83.862 40.441 ;
     RECT  75.564 40.405 75.618 40.445 ;
     RECT  42.192 40.289 47.97 40.469 ;
     RECT  81.504 40.441 83.862 40.469 ;
     RECT  7.128 40.261 8.097 40.559 ;
     RECT  42.192 40.469 47.898 40.559 ;
     RECT  72.615 40.441 74.214 40.559 ;
     RECT  75.6 40.445 75.618 40.559 ;
     RECT  79.056 40.405 79.074 40.559 ;
     RECT  71.784 40.397 71.802 40.595 ;
     RECT  74.196 40.559 74.214 40.595 ;
     RECT  76.536 40.441 76.554 40.703 ;
     RECT  81.504 40.469 82.098 40.703 ;
     RECT  2.376 40.135 4.338 40.711 ;
     RECT  36.684 40.397 37.134 40.733 ;
     RECT  70.992 40.441 71.01 40.739 ;
     RECT  81.576 40.703 82.098 40.739 ;
     RECT  7.38 40.559 8.097 40.829 ;
     RECT  44.748 40.559 47.898 40.937 ;
     RECT  34.776 40.163 35.91 40.945 ;
     RECT  36.684 40.733 36.702 40.945 ;
     RECT  84.888 40.091 84.906 40.972 ;
     RECT  82.08 40.739 82.098 40.973 ;
     RECT  2.376 40.711 4.626 40.981 ;
     RECT  2.304 40.981 4.626 40.987 ;
     RECT  2.304 40.987 5.094 41.021 ;
     RECT  6.444 40.945 6.462 41.021 ;
     RECT  61.815 38.939 62.097 41.071 ;
     RECT  77.544 40.261 78.297 41.099 ;
     RECT  83.232 40.469 83.862 41.099 ;
     RECT  38.484 40.289 41.202 41.143 ;
     RECT  84.852 40.972 84.906 41.171 ;
     RECT  44.82 40.937 47.898 41.215 ;
     RECT  72.615 40.559 73.422 41.251 ;
     RECT  2.415 41.021 5.094 41.261 ;
     RECT  38.484 41.143 41.454 41.341 ;
     RECT  61.344 41.071 62.097 41.369 ;
     RECT  61.815 41.369 62.097 41.377 ;
     RECT  84.888 41.171 84.906 41.419 ;
     RECT  38.016 41.341 41.454 41.449 ;
     RECT  37.908 41.449 41.454 41.462 ;
     RECT  42.192 40.559 44.01 41.462 ;
     RECT  83.415 41.099 83.862 41.485 ;
     RECT  37.908 41.462 44.01 41.521 ;
     RECT  44.82 41.215 47.934 41.521 ;
     RECT  34.776 40.945 36.702 41.611 ;
     RECT  37.656 41.521 44.01 41.611 ;
     RECT  51.015 39.749 51.297 41.611 ;
     RECT  72.432 41.251 73.422 41.611 ;
     RECT  74.412 41.251 74.43 41.611 ;
     RECT  2.415 41.261 2.898 41.639 ;
     RECT  83.415 41.485 84.042 41.639 ;
     RECT  49.68 41.251 49.698 41.647 ;
     RECT  50.76 41.611 51.297 41.647 ;
     RECT  54.684 41.611 54.702 41.647 ;
     RECT  84.888 41.419 85.482 41.711 ;
     RECT  44.82 41.521 48.69 41.719 ;
     RECT  81.504 41.521 81.522 41.747 ;
     RECT  3.636 41.261 5.094 41.791 ;
     RECT  49.68 41.647 51.297 41.791 ;
     RECT  61.815 41.377 62.73 41.791 ;
     RECT  70.704 41.179 70.722 41.791 ;
     RECT  72.432 41.611 74.754 41.791 ;
     RECT  82.656 41.683 82.674 41.791 ;
     RECT  54.612 41.647 54.702 41.819 ;
     RECT  2.415 41.639 2.697 41.851 ;
     RECT  34.776 41.611 44.01 41.909 ;
     RECT  70.704 41.791 71.154 41.909 ;
     RECT  72.432 41.791 75.042 41.909 ;
     RECT  39.78 41.909 44.01 41.945 ;
     RECT  40.104 41.945 44.01 41.947 ;
     RECT  44.82 41.719 48.762 41.947 ;
     RECT  6.012 41.791 6.03 41.981 ;
     RECT  58.68 41.791 58.77 41.981 ;
     RECT  61.815 41.791 62.802 41.981 ;
     RECT  75.024 41.909 75.042 41.981 ;
     RECT  3.636 41.791 5.238 41.989 ;
     RECT  52.56 41.791 52.578 42.061 ;
     RECT  72.432 41.909 74.106 42.061 ;
     RECT  78.015 41.099 78.297 42.061 ;
     RECT  3.456 41.989 5.238 42.089 ;
     RECT  34.776 41.909 38.826 42.089 ;
     RECT  40.104 41.947 48.762 42.089 ;
     RECT  3.456 42.089 4.95 42.179 ;
     RECT  72.252 42.061 74.106 42.179 ;
     RECT  83.415 41.639 83.862 42.179 ;
     RECT  40.104 42.089 48.438 42.215 ;
     RECT  58.356 42.025 58.482 42.223 ;
     RECT  84.888 41.711 84.906 42.235 ;
     RECT  3.564 42.179 4.95 42.251 ;
     RECT  34.776 42.089 38.754 42.251 ;
     RECT  55.044 42.295 55.062 42.331 ;
     RECT  49.572 41.791 51.297 42.421 ;
     RECT  34.815 42.251 38.754 42.449 ;
     RECT  72.396 42.179 74.106 42.449 ;
     RECT  77.544 42.061 78.297 42.449 ;
     RECT  49.176 42.421 51.297 42.493 ;
     RECT  44.424 42.215 48.438 42.521 ;
     RECT  40.104 42.215 43.65 42.557 ;
     RECT  55.044 42.331 55.35 42.565 ;
     RECT  58.32 42.223 58.482 42.565 ;
     RECT  81.972 41.791 82.674 42.593 ;
     RECT  54.72 42.565 55.35 42.601 ;
     RECT  56.415 35.465 56.697 42.601 ;
     RECT  67.215 39.857 67.497 42.601 ;
     RECT  34.815 42.449 35.91 42.629 ;
     RECT  40.104 42.557 41.202 42.629 ;
     RECT  61.815 41.981 62.73 42.629 ;
     RECT  63.648 42.529 63.666 42.629 ;
     RECT  67.068 42.601 67.497 42.691 ;
     RECT  65.52 42.691 65.538 42.715 ;
     RECT  36.684 42.449 38.754 42.719 ;
     RECT  42.156 42.557 43.65 42.719 ;
     RECT  82.656 42.593 82.674 42.719 ;
     RECT  54.54 42.601 55.35 42.727 ;
     RECT  56.124 42.601 56.697 42.727 ;
     RECT  34.815 42.629 35.766 42.755 ;
     RECT  40.104 42.629 40.878 42.755 ;
     RECT  42.156 42.719 43.254 42.755 ;
     RECT  44.748 42.521 48.438 42.755 ;
     RECT  81.828 42.601 81.846 42.755 ;
     RECT  58.14 42.565 58.482 42.763 ;
     RECT  67.068 42.691 67.914 42.763 ;
     RECT  52.56 42.061 53.55 42.799 ;
     RECT  54.54 42.727 56.697 42.799 ;
     RECT  46.8 42.755 48.438 42.835 ;
     RECT  49.176 42.493 51.39 42.835 ;
     RECT  3.996 42.251 4.95 42.871 ;
     RECT  52.56 42.799 56.697 42.871 ;
     RECT  84.852 42.235 84.906 42.899 ;
     RECT  64.836 42.715 65.718 42.961 ;
     RECT  63.864 42.691 63.882 42.989 ;
     RECT  69.984 42.907 70.29 42.989 ;
     RECT  75.384 42.871 75.402 42.989 ;
     RECT  58.14 42.763 58.59 42.997 ;
     RECT  78.015 42.449 78.297 42.997 ;
     RECT  83.415 42.179 83.79 42.997 ;
     RECT  67.068 42.763 68.634 43.025 ;
     RECT  72.615 42.449 74.106 43.025 ;
     RECT  67.068 43.025 67.497 43.033 ;
     RECT  2.304 41.851 2.697 43.069 ;
     RECT  78.015 42.997 78.678 43.097 ;
     RECT  82.728 42.997 83.79 43.097 ;
     RECT  69.984 42.989 70.002 43.099 ;
     RECT  2.304 43.069 2.934 43.105 ;
     RECT  66.744 43.033 67.497 43.105 ;
     RECT  83.415 43.097 83.79 43.105 ;
     RECT  58.14 42.997 58.698 43.133 ;
     RECT  69.948 43.099 70.002 43.139 ;
     RECT  2.304 43.105 3.114 43.141 ;
     RECT  3.996 42.871 4.986 43.141 ;
     RECT  46.8 42.835 51.39 43.141 ;
     RECT  2.304 43.141 4.986 43.169 ;
     RECT  68.616 43.025 68.634 43.169 ;
     RECT  44.748 42.755 45.897 43.181 ;
     RECT  69.984 43.139 70.002 43.259 ;
     RECT  52.524 42.871 56.697 43.267 ;
     RECT  58.14 43.133 58.266 43.267 ;
     RECT  58.032 43.267 58.266 43.295 ;
     RECT  64.8 42.961 65.718 43.295 ;
     RECT  2.415 43.169 4.986 43.303 ;
     RECT  58.032 43.295 58.05 43.325 ;
     RECT  2.415 43.303 5.094 43.331 ;
     RECT  52.452 43.267 56.697 43.331 ;
     RECT  64.8 43.295 65.538 43.331 ;
     RECT  4.824 43.331 5.094 43.411 ;
     RECT  6.084 43.231 6.102 43.411 ;
     RECT  46.8 43.141 51.606 43.411 ;
     RECT  52.452 43.331 53.694 43.411 ;
     RECT  66.672 43.105 67.497 43.411 ;
     RECT  74.124 43.231 74.142 43.411 ;
     RECT  4.824 43.411 6.102 43.501 ;
     RECT  66.564 43.411 67.497 43.501 ;
     RECT  85.356 43.099 85.374 43.528 ;
     RECT  42.264 42.755 43.254 43.537 ;
     RECT  0.54 43.303 0.558 43.565 ;
     RECT  74.124 43.411 74.25 43.565 ;
     RECT  85.356 43.528 85.482 43.565 ;
     RECT  4.824 43.501 6.606 43.601 ;
     RECT  36.684 42.719 38.718 43.609 ;
     RECT  42.012 43.537 43.254 43.609 ;
     RECT  46.8 43.411 53.694 43.609 ;
     RECT  61.815 42.629 62.154 43.609 ;
     RECT  45.216 43.181 45.897 43.637 ;
     RECT  65.52 43.331 65.538 43.673 ;
     RECT  61.815 43.609 62.73 43.709 ;
     RECT  5.652 43.601 6.606 43.799 ;
     RECT  44.28 43.609 44.298 43.799 ;
     RECT  66.42 43.501 67.497 43.799 ;
     RECT  45.615 43.637 45.897 43.807 ;
     RECT  46.764 43.609 53.694 43.807 ;
     RECT  83.415 43.105 84.042 43.835 ;
     RECT  83.415 43.835 83.898 43.843 ;
     RECT  5.652 43.799 5.67 43.853 ;
     RECT  6.588 43.799 6.606 43.871 ;
     RECT  40.215 42.755 40.878 43.879 ;
     RECT  41.94 43.609 43.254 43.879 ;
     RECT  40.215 43.879 41.13 43.915 ;
     RECT  41.94 43.879 43.866 43.915 ;
     RECT  0.108 43.843 0.126 43.949 ;
     RECT  36.684 43.609 38.934 44.069 ;
     RECT  40.215 43.915 43.866 44.069 ;
     RECT  83.232 43.843 83.898 44.069 ;
     RECT  74.16 43.565 74.25 44.105 ;
     RECT  40.215 44.069 41.202 44.177 ;
     RECT  2.415 43.331 4.086 44.212 ;
     RECT  4.824 43.601 4.878 44.212 ;
     RECT  38.556 44.069 38.934 44.221 ;
     RECT  74.304 44.221 74.322 44.339 ;
     RECT  38.556 44.221 39.006 44.375 ;
     RECT  67.032 43.799 67.497 44.375 ;
     RECT  45.615 43.807 53.694 44.383 ;
     RECT  54.612 43.331 56.697 44.383 ;
     RECT  38.556 44.375 38.79 44.411 ;
     RECT  40.215 44.177 40.878 44.432 ;
     RECT  45.615 44.383 56.697 44.443 ;
     RECT  36.684 44.069 37.314 44.447 ;
     RECT  66.132 44.347 66.15 44.477 ;
     RECT  68.688 44.539 68.706 44.581 ;
     RECT  71.136 44.539 71.154 44.581 ;
     RECT  2.415 44.212 4.878 44.609 ;
     RECT  70.344 44.581 71.154 44.645 ;
     RECT  45.18 44.443 56.697 44.717 ;
     RECT  45.18 44.717 53.01 44.725 ;
     RECT  68.688 44.581 69.174 44.725 ;
     RECT  70.344 44.645 70.434 44.725 ;
     RECT  2.415 44.609 4.842 44.753 ;
     RECT  2.415 44.753 4.086 44.761 ;
     RECT  61.815 43.709 62.097 44.761 ;
     RECT  84.888 43.915 84.906 44.779 ;
     RECT  2.304 44.761 4.086 44.813 ;
     RECT  57.924 44.761 57.942 44.851 ;
     RECT  71.208 44.761 71.694 44.851 ;
     RECT  72.615 43.025 72.897 44.851 ;
     RECT  58.932 44.653 58.95 44.875 ;
     RECT  59.724 44.761 59.814 44.875 ;
     RECT  4.824 44.753 4.842 44.879 ;
     RECT  22.86 44.683 22.878 44.879 ;
     RECT  58.788 44.875 58.95 44.879 ;
     RECT  59.724 44.875 59.886 44.879 ;
     RECT  68.688 44.725 70.434 44.879 ;
     RECT  60.804 44.761 60.822 44.887 ;
     RECT  57.924 44.851 58.05 44.915 ;
     RECT  58.788 44.879 58.806 44.915 ;
     RECT  59.796 44.879 59.886 44.915 ;
     RECT  71.208 44.851 72.897 44.915 ;
     RECT  77.04 44.581 77.058 44.923 ;
     RECT  78.015 43.097 78.297 44.923 ;
     RECT  60.732 44.887 60.822 44.971 ;
     RECT  61.596 44.761 62.097 44.971 ;
     RECT  41.94 44.069 43.83 44.995 ;
     RECT  44.604 44.725 53.01 44.995 ;
     RECT  60.732 44.971 62.097 44.995 ;
     RECT  68.688 44.879 69.57 44.995 ;
     RECT  39.672 44.432 40.878 45.005 ;
     RECT  58.032 44.915 58.05 45.023 ;
     RECT  70.416 44.879 70.434 45.023 ;
     RECT  78.015 44.923 78.678 45.023 ;
     RECT  24.015 21.437 24.297 45.031 ;
     RECT  39.996 45.005 40.878 45.031 ;
     RECT  76.428 44.923 77.058 45.031 ;
     RECT  59.796 44.915 59.814 45.059 ;
     RECT  71.208 44.915 71.334 45.059 ;
     RECT  60.732 44.995 62.442 45.149 ;
     RECT  68.4 44.995 69.57 45.149 ;
     RECT  76.428 45.031 77.166 45.149 ;
     RECT  83.415 44.069 83.898 45.149 ;
     RECT  72.396 44.915 72.897 45.185 ;
     RECT  76.428 45.149 77.058 45.185 ;
     RECT  5.616 45.031 5.634 45.221 ;
     RECT  61.128 45.149 62.442 45.221 ;
     RECT  68.76 45.149 69.57 45.221 ;
     RECT  84.852 44.779 84.906 45.221 ;
     RECT  0.54 44.995 0.558 45.245 ;
     RECT  61.128 45.221 62.097 45.293 ;
     RECT  68.904 45.221 69.57 45.293 ;
     RECT  38.556 44.411 38.574 45.301 ;
     RECT  84.888 45.221 84.906 45.427 ;
     RECT  34.815 42.755 35.097 45.499 ;
     RECT  36.756 44.447 37.314 45.499 ;
     RECT  24.015 45.031 24.426 45.533 ;
     RECT  26.784 45.403 26.802 45.533 ;
     RECT  30.42 45.499 30.438 45.536 ;
     RECT  41.94 44.995 53.01 45.571 ;
     RECT  31.536 45.391 31.554 45.581 ;
     RECT  2.415 44.813 4.086 45.595 ;
     RECT  34.776 45.499 35.097 45.599 ;
     RECT  36.756 45.499 37.386 45.599 ;
     RECT  38.556 45.301 38.79 45.599 ;
     RECT  84.888 45.427 85.482 45.629 ;
     RECT  63.18 44.653 63.198 45.661 ;
     RECT  54.144 44.717 56.697 45.688 ;
     RECT  39.996 45.031 40.95 45.691 ;
     RECT  41.796 45.571 53.01 45.691 ;
     RECT  62.964 45.661 63.198 45.691 ;
     RECT  39.996 45.691 53.01 45.725 ;
     RECT  40.215 45.725 53.01 45.733 ;
     RECT  67.215 44.375 67.497 45.787 ;
     RECT  2.304 45.595 4.086 45.841 ;
     RECT  54.144 45.688 57.186 45.841 ;
     RECT  62.964 45.691 63.234 45.841 ;
     RECT  78.015 45.023 78.297 45.841 ;
     RECT  2.304 45.841 4.446 45.869 ;
     RECT  70.704 45.661 70.722 45.931 ;
     RECT  74.664 45.193 74.682 45.931 ;
     RECT  16.704 45.595 16.722 45.959 ;
     RECT  40.215 45.733 53.298 45.959 ;
     RECT  60.3 45.661 60.318 45.959 ;
     RECT  70.632 45.931 70.722 45.959 ;
     RECT  74.592 45.931 74.682 45.967 ;
     RECT  54.144 45.841 57.51 45.995 ;
     RECT  62.964 45.841 63.882 45.995 ;
     RECT  78.015 45.841 78.75 45.995 ;
     RECT  40.215 45.959 40.95 46.031 ;
     RECT  70.632 45.959 70.65 46.031 ;
     RECT  82.656 45.661 82.674 46.039 ;
     RECT  15.588 45.931 15.606 46.061 ;
     RECT  74.592 45.967 74.754 46.067 ;
     RECT  78.015 45.995 78.678 46.067 ;
     RECT  82.584 46.039 82.674 46.075 ;
     RECT  83.415 45.149 83.862 46.075 ;
     RECT  62.964 45.995 63.558 46.103 ;
     RECT  63.216 46.103 63.558 46.109 ;
     RECT  41.796 45.959 53.298 46.111 ;
     RECT  54.144 45.995 57.042 46.111 ;
     RECT  66.996 45.787 67.497 46.111 ;
     RECT  2.415 45.869 4.446 46.123 ;
     RECT  2.415 46.123 5.166 46.139 ;
     RECT  41.796 46.111 57.042 46.139 ;
     RECT  63.54 46.109 63.558 46.139 ;
     RECT  66.996 46.111 67.95 46.201 ;
     RECT  74.592 46.067 74.682 46.229 ;
     RECT  82.584 46.075 84.042 46.229 ;
     RECT  74.592 46.229 74.61 46.265 ;
     RECT  82.584 46.229 82.602 46.265 ;
     RECT  41.796 46.139 56.697 46.301 ;
     RECT  66.636 46.201 67.95 46.373 ;
     RECT  4.86 46.139 5.166 46.381 ;
     RECT  5.94 46.309 5.958 46.381 ;
     RECT  84.888 45.629 84.906 46.459 ;
     RECT  4.86 46.381 5.958 46.471 ;
     RECT  64.584 46.201 64.602 46.499 ;
     RECT  66.636 46.373 67.554 46.535 ;
     RECT  82.08 46.381 82.278 46.535 ;
     RECT  0.108 46.459 0.126 46.589 ;
     RECT  78.015 46.067 78.642 46.607 ;
     RECT  4.86 46.471 6.282 46.643 ;
     RECT  61.815 45.293 62.097 46.651 ;
     RECT  40.215 46.031 40.878 46.741 ;
     RECT  58.716 46.309 58.734 46.741 ;
     RECT  61.815 46.651 62.154 46.741 ;
     RECT  40.104 46.741 40.878 46.747 ;
     RECT  61.56 46.741 62.154 46.795 ;
     RECT  41.832 46.301 56.697 46.805 ;
     RECT  64.98 46.579 64.998 46.805 ;
     RECT  38.556 45.599 38.574 46.813 ;
     RECT  40.032 46.747 40.878 46.813 ;
     RECT  59.724 46.741 59.742 46.829 ;
     RECT  4.86 46.643 6.246 46.841 ;
     RECT  4.86 46.841 5.922 46.877 ;
     RECT  66.636 46.535 67.497 46.885 ;
     RECT  2.415 46.139 4.122 46.891 ;
     RECT  58.644 46.741 58.734 46.921 ;
     RECT  61.56 46.795 62.478 46.921 ;
     RECT  2.304 46.891 4.122 46.949 ;
     RECT  41.832 46.805 44.514 47.039 ;
     RECT  58.644 46.921 58.806 47.039 ;
     RECT  61.488 46.921 62.478 47.039 ;
     RECT  74.124 47.011 74.142 47.047 ;
     RECT  57.456 46.849 57.474 47.075 ;
     RECT  61.815 47.039 62.478 47.075 ;
     RECT  38.556 46.813 38.79 47.119 ;
     RECT  41.832 47.039 44.154 47.147 ;
     RECT  61.815 47.075 62.154 47.165 ;
     RECT  2.415 46.949 4.122 47.191 ;
     RECT  40.032 46.813 41.022 47.191 ;
     RECT  41.832 47.147 43.182 47.191 ;
     RECT  65.268 47.011 65.286 47.191 ;
     RECT  66.384 46.885 67.497 47.191 ;
     RECT  40.032 47.191 43.182 47.219 ;
     RECT  58.788 47.039 58.806 47.219 ;
     RECT  65.268 47.191 67.497 47.261 ;
     RECT  44.136 47.147 44.154 47.309 ;
     RECT  45.252 46.805 56.697 47.309 ;
     RECT  59.868 46.921 59.886 47.309 ;
     RECT  65.268 47.261 65.286 47.309 ;
     RECT  74.124 47.047 74.25 47.309 ;
     RECT  66.096 47.261 67.497 47.317 ;
     RECT  40.032 47.219 43.11 47.345 ;
     RECT  74.124 47.309 74.142 47.345 ;
     RECT  66.096 47.317 68.202 47.357 ;
     RECT  66.096 47.357 67.842 47.381 ;
     RECT  49.536 47.309 56.697 47.453 ;
     RECT  66.384 47.381 67.842 47.453 ;
     RECT  82.26 46.535 82.278 47.453 ;
     RECT  66.672 47.453 67.842 47.489 ;
     RECT  68.616 47.461 69.138 47.579 ;
     RECT  38.34 47.119 38.79 47.587 ;
     RECT  75.204 47.281 75.222 47.615 ;
     RECT  83.415 46.229 84.042 47.623 ;
     RECT  49.644 47.453 56.697 47.651 ;
     RECT  69.12 47.579 69.138 47.651 ;
     RECT  38.34 47.587 38.934 47.659 ;
     RECT  2.415 47.191 4.302 47.707 ;
     RECT  2.304 47.707 4.302 47.731 ;
     RECT  38.34 47.659 39.006 47.731 ;
     RECT  40.032 47.345 41.022 47.731 ;
     RECT  2.304 47.731 4.41 47.759 ;
     RECT  2.415 47.759 4.41 47.821 ;
     RECT  5.508 46.877 5.922 47.821 ;
     RECT  71.784 47.821 71.802 47.848 ;
     RECT  82.872 47.623 84.042 47.849 ;
     RECT  38.34 47.731 41.022 47.857 ;
     RECT  71.1 47.848 71.802 47.885 ;
     RECT  82.872 47.849 83.898 47.885 ;
     RECT  84.888 46.459 85.482 47.885 ;
     RECT  34.815 45.599 35.097 47.929 ;
     RECT  41.868 47.345 43.11 47.965 ;
     RECT  49.644 47.651 55.638 47.993 ;
     RECT  77.148 47.821 77.166 48.001 ;
     RECT  34.776 47.929 35.097 48.029 ;
     RECT  45.468 47.309 48.69 48.091 ;
     RECT  2.415 47.821 4.59 48.119 ;
     RECT  77.148 48.001 77.274 48.119 ;
     RECT  70.164 48.001 70.182 48.127 ;
     RECT  77.148 48.119 77.166 48.155 ;
     RECT  44.964 48.091 48.69 48.163 ;
     RECT  71.784 47.885 71.802 48.163 ;
     RECT  71.784 48.163 71.874 48.191 ;
     RECT  83.415 47.885 83.898 48.191 ;
     RECT  69.984 48.127 70.182 48.263 ;
     RECT  71.856 48.191 71.874 48.263 ;
     RECT  0.108 48.139 0.126 48.269 ;
     RECT  41.868 47.965 43.218 48.271 ;
     RECT  44.748 48.163 48.69 48.271 ;
     RECT  49.644 47.993 55.53 48.271 ;
     RECT  56.415 47.651 56.697 48.271 ;
     RECT  57.492 48.235 57.51 48.271 ;
     RECT  58.68 47.929 58.698 48.271 ;
     RECT  61.815 47.165 62.097 48.271 ;
     RECT  82.656 48.199 82.674 48.271 ;
     RECT  3.996 48.119 4.59 48.299 ;
     RECT  4.032 48.299 4.59 48.361 ;
     RECT  5.508 47.821 6.246 48.361 ;
     RECT  56.415 48.271 57.51 48.361 ;
     RECT  64.08 48.127 64.098 48.379 ;
     RECT  37.98 47.857 41.022 48.389 ;
     RECT  44.748 48.271 55.53 48.389 ;
     RECT  58.428 48.271 58.698 48.389 ;
     RECT  59.544 47.929 59.562 48.389 ;
     RECT  64.08 48.379 64.35 48.389 ;
     RECT  75.384 48.163 75.402 48.389 ;
     RECT  36.756 45.599 37.242 48.397 ;
     RECT  37.98 48.389 39.474 48.397 ;
     RECT  61.815 48.271 62.73 48.425 ;
     RECT  81.972 48.271 82.674 48.425 ;
     RECT  64.332 48.389 64.35 48.427 ;
     RECT  36.756 48.397 39.474 48.461 ;
     RECT  49.032 48.389 55.53 48.461 ;
     RECT  66.708 47.489 67.842 48.461 ;
     RECT  69.228 48.271 69.246 48.461 ;
     RECT  66.924 48.461 67.842 48.497 ;
     RECT  64.332 48.427 64.674 48.569 ;
     RECT  0.54 48.433 0.558 48.605 ;
     RECT  4.032 48.361 6.246 48.659 ;
     RECT  37.944 48.461 39.402 48.659 ;
     RECT  37.944 48.659 39.33 48.695 ;
     RECT  70.668 48.631 70.686 48.731 ;
     RECT  41.832 48.271 43.218 48.739 ;
     RECT  44.748 48.389 48.114 48.767 ;
     RECT  82.62 48.425 82.674 48.767 ;
     RECT  58.716 48.667 58.734 48.803 ;
     RECT  44.748 48.767 47.79 48.811 ;
     RECT  78.015 46.607 78.297 48.811 ;
     RECT  64.332 48.569 64.35 48.845 ;
     RECT  50.976 48.461 55.53 48.929 ;
     RECT  60.48 48.541 60.498 48.929 ;
     RECT  66.168 48.811 66.186 48.929 ;
     RECT  74.952 48.703 75.222 48.929 ;
     RECT  84.888 47.885 84.906 48.955 ;
     RECT  52.092 48.929 55.386 48.965 ;
     RECT  66.924 48.497 67.554 48.965 ;
     RECT  4.968 48.659 6.246 49.001 ;
     RECT  56.415 48.361 57.546 49.001 ;
     RECT  68.436 48.811 68.454 49.001 ;
     RECT  78.015 48.811 78.678 49.001 ;
     RECT  82.62 48.767 82.638 49.001 ;
     RECT  5.652 49.001 6.246 49.003 ;
     RECT  41.832 48.739 43.614 49.003 ;
     RECT  5.652 49.003 6.318 49.037 ;
     RECT  52.092 48.965 55.206 49.037 ;
     RECT  6.3 49.037 6.318 49.081 ;
     RECT  41.76 49.003 43.614 49.171 ;
     RECT  44.352 48.811 47.79 49.171 ;
     RECT  49.032 48.461 50.13 49.195 ;
     RECT  54.072 49.037 55.206 49.199 ;
     RECT  54.252 49.199 55.206 49.271 ;
     RECT  75.204 48.929 75.222 49.271 ;
     RECT  48.744 49.195 50.13 49.315 ;
     RECT  67.176 48.965 67.554 49.315 ;
     RECT  52.092 49.037 53.01 49.379 ;
     RECT  2.415 48.119 3.186 49.441 ;
     RECT  4.032 48.659 4.194 49.441 ;
     RECT  6.3 49.081 6.462 49.469 ;
     RECT  52.092 49.379 52.83 49.469 ;
     RECT  54.324 49.271 55.134 49.469 ;
     RECT  58.68 49.351 58.698 49.469 ;
     RECT  54.324 49.469 55.062 49.505 ;
     RECT  67.176 49.315 68.202 49.505 ;
     RECT  54.324 49.505 54.594 49.541 ;
     RECT  63.504 49.441 63.522 49.549 ;
     RECT  70.992 49.435 71.01 49.549 ;
     RECT  71.784 49.441 71.802 49.549 ;
     RECT  56.415 49.001 57.366 49.577 ;
     RECT  67.215 49.505 67.734 49.577 ;
     RECT  36.756 48.461 37.206 49.585 ;
     RECT  38.484 48.695 39.33 49.585 ;
     RECT  48.744 49.315 50.238 49.585 ;
     RECT  50.976 48.929 51.297 49.585 ;
     RECT  7.815 40.829 8.097 49.621 ;
     RECT  34.815 48.029 35.097 49.621 ;
     RECT  38.448 49.585 39.33 49.621 ;
     RECT  38.448 49.621 39.366 49.627 ;
     RECT  36.648 49.585 37.206 49.711 ;
     RECT  38.448 49.627 39.402 49.711 ;
     RECT  40.215 48.389 41.022 49.711 ;
     RECT  34.815 49.621 35.91 49.739 ;
     RECT  52.092 49.469 52.65 49.739 ;
     RECT  63.36 49.549 63.522 49.739 ;
     RECT  70.848 49.549 71.802 49.739 ;
     RECT  84.888 48.955 85.482 49.739 ;
     RECT  36.648 49.711 37.422 49.747 ;
     RECT  38.448 49.711 41.022 49.747 ;
     RECT  63.36 49.739 63.378 49.775 ;
     RECT  76.644 49.441 76.662 49.775 ;
     RECT  7.236 49.621 8.097 49.811 ;
     RECT  34.815 49.739 35.73 49.811 ;
     RECT  71.784 49.739 71.802 49.811 ;
     RECT  2.415 49.441 4.554 49.819 ;
     RECT  52.092 49.739 52.614 49.819 ;
     RECT  83.415 48.191 83.862 49.855 ;
     RECT  52.02 49.819 52.614 49.883 ;
     RECT  2.304 49.819 4.554 49.891 ;
     RECT  5.4 49.819 5.418 49.891 ;
     RECT  36.648 49.747 41.022 49.891 ;
     RECT  41.76 49.171 47.79 49.891 ;
     RECT  48.744 49.585 51.297 49.891 ;
     RECT  36.648 49.891 47.898 49.981 ;
     RECT  48.636 49.891 51.297 49.981 ;
     RECT  58.716 49.891 58.734 50.008 ;
     RECT  2.304 49.891 5.418 50.009 ;
     RECT  36.648 49.981 51.297 50.009 ;
     RECT  52.02 49.883 52.038 50.009 ;
     RECT  60.336 49.783 60.354 50.009 ;
     RECT  61.815 48.425 62.097 50.017 ;
     RECT  58.716 50.008 59.382 50.045 ;
     RECT  83.415 49.855 84.042 50.053 ;
     RECT  2.304 50.009 5.382 50.081 ;
     RECT  72.615 45.185 72.897 50.107 ;
     RECT  58.716 50.045 58.734 50.117 ;
     RECT  72.615 50.107 73.314 50.125 ;
     RECT  3.456 50.081 5.382 50.279 ;
     RECT  6.3 49.469 6.318 50.279 ;
     RECT  2.304 50.081 2.697 50.288 ;
     RECT  85.464 49.739 85.482 50.315 ;
     RECT  80.964 50.125 80.982 50.387 ;
     RECT  74.664 50.251 74.682 50.431 ;
     RECT  78.015 49.001 78.297 50.431 ;
     RECT  59.544 50.161 59.562 50.459 ;
     RECT  61.815 50.017 62.118 50.521 ;
     RECT  36.648 50.009 43.794 50.539 ;
     RECT  66.024 50.431 66.042 50.549 ;
     RECT  83.232 50.053 84.042 50.549 ;
     RECT  67.215 49.577 67.497 50.557 ;
     RECT  61.452 50.521 62.73 50.573 ;
     RECT  72.144 50.125 73.314 50.585 ;
     RECT  83.415 50.549 84.042 50.585 ;
     RECT  7.308 49.811 8.097 50.621 ;
     RECT  72.396 50.585 73.314 50.629 ;
     RECT  74.268 50.431 74.682 50.629 ;
     RECT  61.815 50.573 62.73 50.657 ;
     RECT  66.708 50.557 67.497 50.665 ;
     RECT  66.708 50.665 67.59 50.693 ;
     RECT  70.74 50.593 70.758 50.693 ;
     RECT  72.396 50.629 74.682 50.693 ;
     RECT  6.516 50.431 6.534 50.729 ;
     RECT  44.676 50.009 51.297 50.729 ;
     RECT  74.016 50.693 74.682 50.729 ;
     RECT  72.396 50.693 73.134 50.765 ;
     RECT  72.396 50.765 72.99 50.819 ;
     RECT  81.972 50.701 82.638 50.855 ;
     RECT  3.708 50.279 5.382 50.891 ;
     RECT  36.216 50.539 43.794 50.899 ;
     RECT  74.088 50.729 74.682 50.927 ;
     RECT  36.216 50.899 43.83 50.963 ;
     RECT  67.215 50.693 67.59 50.963 ;
     RECT  74.268 50.927 74.682 50.963 ;
     RECT  37.188 50.963 38.862 50.999 ;
     RECT  76.968 49.981 76.986 50.999 ;
     RECT  2.415 50.288 2.697 51.067 ;
     RECT  84.888 50.635 84.906 51.067 ;
     RECT  37.188 50.999 37.926 51.089 ;
     RECT  38.844 50.999 38.862 51.089 ;
     RECT  44.748 50.729 51.297 51.089 ;
     RECT  65.448 50.971 65.466 51.089 ;
     RECT  82.188 50.855 82.638 51.125 ;
     RECT  39.672 50.963 43.83 51.133 ;
     RECT  74.628 50.963 74.682 51.16 ;
     RECT  2.304 51.067 2.697 51.169 ;
     RECT  3.708 50.891 5.202 51.169 ;
     RECT  78.015 50.431 78.678 51.169 ;
     RECT  39.672 51.133 44.01 51.197 ;
     RECT  74.628 51.16 75.042 51.197 ;
     RECT  39.78 51.197 41.022 51.233 ;
     RECT  41.796 51.197 44.01 51.233 ;
     RECT  44.748 51.089 47.07 51.233 ;
     RECT  64.512 51.205 64.53 51.245 ;
     RECT  2.304 51.169 5.202 51.269 ;
     RECT  37.188 51.089 37.746 51.269 ;
     RECT  40.215 51.233 41.022 51.269 ;
     RECT  41.94 51.233 44.01 51.359 ;
     RECT  47.88 51.089 51.297 51.359 ;
     RECT  78.015 51.169 78.858 51.359 ;
     RECT  84.888 51.067 85.482 51.395 ;
     RECT  82.188 51.125 82.206 51.431 ;
     RECT  48.096 51.359 51.297 51.439 ;
     RECT  68.4 51.205 68.418 51.467 ;
     RECT  48.096 51.439 51.498 51.475 ;
     RECT  75.78 51.241 75.798 51.503 ;
     RECT  67.215 50.963 67.497 51.511 ;
     RECT  72.615 50.819 72.99 51.595 ;
     RECT  66.6 51.511 67.497 51.629 ;
     RECT  6.84 51.709 6.858 51.745 ;
     RECT  72.615 51.595 73.134 51.745 ;
     RECT  34.815 49.811 35.37 51.781 ;
     RECT  72.54 51.745 73.134 51.781 ;
     RECT  6.12 51.745 6.858 51.809 ;
     RECT  65.664 51.781 65.682 51.821 ;
     RECT  61.815 50.657 62.097 51.871 ;
     RECT  4.464 51.269 5.202 51.899 ;
     RECT  48.096 51.475 51.678 51.899 ;
     RECT  69.372 51.781 69.39 51.899 ;
     RECT  42.552 51.359 44.01 51.907 ;
     RECT  44.748 51.233 46.746 51.907 ;
     RECT  84.888 51.395 84.906 51.931 ;
     RECT  2.376 51.269 3.654 51.935 ;
     RECT  81.504 51.781 81.522 51.935 ;
     RECT  34.776 51.781 35.37 52.015 ;
     RECT  6.12 51.809 6.786 52.043 ;
     RECT  2.415 51.935 3.654 52.051 ;
     RECT  4.464 51.899 4.914 52.051 ;
     RECT  72.54 51.781 73.854 52.051 ;
     RECT  74.628 51.197 74.682 52.051 ;
     RECT  48.096 51.899 51.462 52.061 ;
     RECT  54.684 51.871 54.702 52.079 ;
     RECT  76.968 51.745 76.986 52.079 ;
     RECT  61.815 51.871 62.334 52.169 ;
     RECT  63.468 52.051 63.486 52.169 ;
     RECT  72.54 52.051 74.682 52.169 ;
     RECT  37.188 51.269 37.206 52.177 ;
     RECT  63.324 52.171 63.342 52.211 ;
     RECT  42.552 51.907 46.746 52.249 ;
     RECT  42.444 52.249 46.746 52.267 ;
     RECT  78.015 51.359 78.678 52.313 ;
     RECT  72.54 52.169 74.178 52.321 ;
     RECT  0.108 51.781 0.126 52.349 ;
     RECT  6.768 52.043 6.786 52.349 ;
     RECT  72.216 52.321 74.178 52.405 ;
     RECT  34.2 52.015 35.37 52.411 ;
     RECT  37.188 52.177 37.818 52.411 ;
     RECT  68.796 52.051 68.814 52.439 ;
     RECT  82.656 52.213 82.674 52.439 ;
     RECT  72.18 52.405 74.178 52.445 ;
     RECT  48.096 52.061 51.297 52.447 ;
     RECT  67.215 51.629 67.497 52.447 ;
     RECT  66.564 52.447 67.497 52.459 ;
     RECT  40.215 51.269 40.95 52.547 ;
     RECT  37.188 52.411 38.322 52.549 ;
     RECT  72.216 52.445 74.178 52.583 ;
     RECT  36.9 52.549 38.322 52.591 ;
     RECT  2.415 52.051 4.914 52.681 ;
     RECT  78.015 52.313 78.297 52.681 ;
     RECT  84.852 51.931 84.906 52.747 ;
     RECT  84.852 52.747 85.482 52.781 ;
     RECT  83.415 50.585 83.862 52.825 ;
     RECT  34.2 52.411 35.91 52.829 ;
     RECT  42.264 52.267 46.746 52.843 ;
     RECT  42.084 52.843 46.746 52.853 ;
     RECT  64.26 52.321 64.278 52.853 ;
     RECT  36.9 52.591 38.358 52.889 ;
     RECT  48.024 52.447 51.297 52.951 ;
     RECT  34.2 52.829 35.802 52.979 ;
     RECT  57.78 52.939 57.798 52.979 ;
     RECT  66.348 52.459 67.497 52.979 ;
     RECT  47.988 52.951 51.297 52.987 ;
     RECT  66.348 52.979 66.366 53.015 ;
     RECT  81.9 52.861 81.918 53.015 ;
     RECT  72.216 52.583 73.746 53.038 ;
     RECT  37.188 52.889 38.358 53.131 ;
     RECT  65.088 52.861 65.106 53.131 ;
     RECT  69.912 52.987 69.93 53.131 ;
     RECT  47.988 52.987 51.354 53.249 ;
     RECT  57.924 53.131 57.942 53.249 ;
     RECT  58.716 53.131 58.806 53.249 ;
     RECT  65.088 53.131 65.25 53.249 ;
     RECT  77.364 52.681 78.297 53.249 ;
     RECT  65.088 53.249 65.106 53.285 ;
     RECT  69.804 53.131 69.93 53.285 ;
     RECT  61.815 52.169 62.097 53.293 ;
     RECT  42.084 52.853 46.35 53.32 ;
     RECT  2.415 52.681 5.418 53.321 ;
     RECT  54.72 53.221 54.738 53.321 ;
     RECT  82.368 53.221 82.386 53.321 ;
     RECT  70.704 52.861 70.722 53.329 ;
     RECT  72.396 53.038 73.746 53.357 ;
     RECT  70.056 53.329 70.722 53.365 ;
     RECT  80.964 52.321 80.982 53.393 ;
     RECT  41.976 53.32 46.35 53.401 ;
     RECT  53.496 53.365 53.514 53.401 ;
     RECT  72.615 53.357 73.746 53.401 ;
     RECT  53.496 53.401 53.802 53.491 ;
     RECT  78.015 53.249 78.297 53.491 ;
     RECT  6.84 53.329 6.858 53.519 ;
     RECT  52.992 53.491 53.802 53.519 ;
     RECT  61.38 53.293 62.097 53.519 ;
     RECT  2.415 53.321 4.95 53.555 ;
     RECT  58.716 53.249 58.734 53.555 ;
     RECT  68.796 53.401 68.814 53.555 ;
     RECT  72.615 53.401 74.07 53.555 ;
     RECT  82.512 53.401 82.53 53.555 ;
     RECT  83.415 52.825 84.042 53.555 ;
     RECT  83.415 53.555 83.862 53.563 ;
     RECT  54.684 53.527 54.702 53.591 ;
     RECT  78.015 53.491 78.678 53.591 ;
     RECT  52.992 53.519 53.514 53.597 ;
     RECT  72.615 53.555 73.494 53.597 ;
     RECT  0.54 52.861 0.558 53.645 ;
     RECT  85.464 52.781 85.482 53.645 ;
     RECT  37.188 53.131 38.826 53.671 ;
     RECT  34.2 52.979 35.514 53.789 ;
     RECT  34.308 53.789 35.514 53.833 ;
     RECT  47.988 53.249 51.297 53.833 ;
     RECT  52.992 53.597 53.01 53.861 ;
     RECT  37.188 53.671 38.97 53.897 ;
     RECT  47.916 53.833 51.297 53.941 ;
     RECT  30.78 53.869 30.798 53.969 ;
     RECT  2.415 53.555 2.697 53.995 ;
     RECT  37.188 53.897 38.862 54.031 ;
     RECT  41.796 53.401 46.35 54.031 ;
     RECT  47.736 53.941 51.297 54.031 ;
     RECT  34.308 53.833 35.586 54.043 ;
     RECT  2.304 53.995 2.697 54.131 ;
     RECT  70.056 53.365 70.83 54.131 ;
     RECT  47.664 54.031 51.297 54.133 ;
     RECT  76.86 53.563 76.878 54.175 ;
     RECT  3.42 53.555 4.95 54.211 ;
     RECT  5.724 54.139 5.742 54.211 ;
     RECT  47.628 54.133 51.297 54.211 ;
     RECT  70.488 54.131 70.83 54.211 ;
     RECT  71.64 54.175 71.658 54.211 ;
     RECT  76.104 54.031 76.122 54.211 ;
     RECT  76.86 54.175 76.914 54.211 ;
     RECT  67.215 52.979 67.497 54.301 ;
     RECT  70.488 54.211 71.658 54.329 ;
     RECT  76.104 54.211 76.914 54.365 ;
     RECT  37.08 54.031 38.862 54.373 ;
     RECT  83.232 53.563 83.862 54.409 ;
     RECT  84.888 53.995 84.906 54.427 ;
     RECT  3.42 54.211 5.886 54.445 ;
     RECT  56.415 49.577 56.697 54.445 ;
     RECT  63.612 54.211 63.63 54.445 ;
     RECT  66.78 54.301 67.497 54.445 ;
     RECT  82.728 54.409 83.862 54.445 ;
     RECT  34.308 54.043 35.622 54.472 ;
     RECT  40.215 52.547 40.806 54.481 ;
     RECT  41.688 54.031 46.35 54.481 ;
     RECT  55.872 54.445 56.697 54.481 ;
     RECT  61.815 53.519 62.097 54.481 ;
     RECT  78.015 53.591 78.297 54.481 ;
     RECT  82.728 54.445 84.042 54.481 ;
     RECT  36.504 54.373 38.862 54.509 ;
     RECT  40.215 54.481 46.35 54.571 ;
     RECT  47.088 54.211 51.297 54.571 ;
     RECT  54.108 54.481 54.126 54.571 ;
     RECT  55.584 54.481 56.697 54.571 ;
     RECT  65.412 54.139 65.43 54.571 ;
     RECT  72.615 53.597 72.897 54.571 ;
     RECT  40.215 54.571 51.297 54.599 ;
     RECT  55.584 54.571 57.402 54.599 ;
     RECT  63.468 54.445 63.63 54.599 ;
     RECT  65.34 54.571 65.43 54.599 ;
     RECT  76.752 54.365 76.914 54.599 ;
     RECT  82.656 54.481 84.042 54.599 ;
     RECT  55.872 54.599 57.402 54.605 ;
     RECT  84.816 54.427 84.906 54.605 ;
     RECT  3.42 54.445 6.354 54.635 ;
     RECT  56.415 54.605 57.402 54.635 ;
     RECT  63.468 54.599 63.486 54.635 ;
     RECT  64.44 54.571 64.458 54.635 ;
     RECT  66.672 54.445 67.497 54.635 ;
     RECT  70.704 54.329 71.334 54.635 ;
     RECT  72.615 54.571 73.602 54.635 ;
     RECT  82.656 54.599 82.674 54.635 ;
     RECT  65.34 54.599 65.358 54.671 ;
     RECT  78.015 54.481 78.678 54.671 ;
     RECT  78.015 54.671 78.354 54.679 ;
     RECT  36.504 54.509 38.61 54.707 ;
     RECT  76.752 54.599 76.77 54.707 ;
     RECT  34.308 54.472 35.658 54.715 ;
     RECT  61.815 54.481 62.694 54.715 ;
     RECT  54.108 54.571 54.63 54.751 ;
     RECT  72.615 54.635 72.99 54.751 ;
     RECT  54.108 54.751 54.81 54.779 ;
     RECT  42.156 54.599 51.297 54.841 ;
     RECT  52.2 54.751 52.218 54.841 ;
     RECT  67.215 54.635 67.497 54.841 ;
     RECT  2.415 54.131 2.697 54.859 ;
     RECT  84.888 54.605 84.906 54.859 ;
     RECT  3.42 54.635 5.994 54.869 ;
     RECT  57.528 54.643 57.546 54.869 ;
     RECT  68.904 54.643 68.922 54.869 ;
     RECT  77.544 54.679 78.354 54.869 ;
     RECT  2.304 54.859 2.697 54.877 ;
     RECT  3.42 54.869 5.886 54.877 ;
     RECT  2.304 54.877 5.886 54.905 ;
     RECT  61.56 54.715 62.694 54.905 ;
     RECT  53.172 54.751 53.19 54.913 ;
     RECT  34.2 54.715 36.27 54.941 ;
     RECT  58.32 54.751 58.77 54.941 ;
     RECT  74.52 54.751 74.538 54.941 ;
     RECT  72.396 54.751 72.99 54.977 ;
     RECT  42.156 54.841 52.218 55.012 ;
     RECT  2.304 54.905 5.31 55.013 ;
     RECT  34.2 54.941 35.55 55.013 ;
     RECT  42.156 55.012 52.254 55.013 ;
     RECT  53.172 54.913 53.262 55.013 ;
     RECT  54.792 54.779 54.81 55.013 ;
     RECT  58.68 54.941 58.77 55.013 ;
     RECT  81.972 54.751 81.99 55.013 ;
     RECT  67.215 54.841 68.166 55.021 ;
     RECT  2.304 55.013 4.878 55.049 ;
     RECT  42.156 55.013 51.297 55.049 ;
     RECT  52.236 55.013 52.254 55.111 ;
     RECT  52.236 55.111 52.758 55.139 ;
     RECT  60.192 54.715 60.21 55.139 ;
     RECT  6.84 55.021 6.858 55.211 ;
     RECT  52.74 55.139 52.758 55.247 ;
     RECT  34.272 55.013 35.55 55.283 ;
     RECT  42.156 55.049 44.73 55.283 ;
     RECT  40.215 54.599 41.31 55.291 ;
     RECT  84.888 54.859 85.374 55.291 ;
     RECT  61.56 54.905 62.097 55.319 ;
     RECT  0.54 54.949 0.558 55.325 ;
     RECT  72.615 54.977 72.99 55.453 ;
     RECT  83.415 54.599 84.042 55.453 ;
     RECT  84.888 55.291 85.482 55.481 ;
     RECT  37.044 54.707 38.61 55.489 ;
     RECT  40.212 55.291 41.31 55.489 ;
     RECT  45.615 55.049 51.297 55.517 ;
     RECT  78.015 54.869 78.354 55.561 ;
     RECT  45.615 55.517 48.078 55.565 ;
     RECT  60.768 55.291 60.786 55.613 ;
     RECT  34.488 55.283 35.55 55.679 ;
     RECT  48.996 55.517 51.297 55.679 ;
     RECT  59.22 55.291 59.238 55.679 ;
     RECT  67.215 55.021 68.418 55.679 ;
     RECT  72.615 55.453 73.062 55.679 ;
     RECT  78.015 55.561 78.678 55.687 ;
     RECT  67.215 55.679 68.31 55.715 ;
     RECT  46.872 55.565 48.078 55.751 ;
     RECT  67.215 55.715 68.058 55.751 ;
     RECT  46.872 55.751 47.898 55.787 ;
     RECT  34.56 55.679 35.55 55.795 ;
     RECT  36.36 55.489 38.61 55.831 ;
     RECT  39.996 55.489 41.31 55.831 ;
     RECT  36.36 55.831 41.31 55.921 ;
     RECT  42.156 55.283 42.642 55.921 ;
     RECT  49.14 55.679 51.297 55.949 ;
     RECT  34.56 55.795 35.622 55.957 ;
     RECT  36.36 55.921 42.642 55.957 ;
     RECT  46.872 55.787 47.79 55.985 ;
     RECT  72.615 55.679 72.99 55.985 ;
     RECT  84.888 55.481 85.374 56.021 ;
     RECT  32.904 55.561 32.922 56.029 ;
     RECT  34.56 55.957 42.642 56.065 ;
     RECT  43.668 55.283 44.73 56.065 ;
     RECT  2.415 55.049 4.878 56.101 ;
     RECT  6.84 56.029 6.858 56.101 ;
     RECT  45.615 55.565 45.897 56.101 ;
     RECT  74.988 55.291 75.006 56.101 ;
     RECT  2.415 56.101 5.058 56.107 ;
     RECT  32.904 56.029 33.102 56.129 ;
     RECT  46.872 55.985 47.61 56.129 ;
     RECT  72.615 55.985 72.897 56.191 ;
     RECT  50.724 55.949 51.297 56.203 ;
     RECT  6.804 56.101 6.858 56.219 ;
     RECT  46.872 56.129 47.142 56.219 ;
     RECT  50.724 56.203 51.858 56.219 ;
     RECT  74.664 56.101 75.006 56.219 ;
     RECT  52.596 56.191 52.614 56.237 ;
     RECT  49.644 55.949 49.95 56.255 ;
     RECT  74.736 56.219 75.006 56.255 ;
     RECT  2.304 56.107 5.058 56.291 ;
     RECT  82.656 55.453 84.042 56.291 ;
     RECT  72.576 56.191 72.897 56.327 ;
     RECT  34.56 56.065 44.73 56.335 ;
     RECT  34.56 56.335 44.802 56.371 ;
     RECT  45.576 56.101 45.897 56.371 ;
     RECT  46.872 56.219 47.07 56.371 ;
     RECT  59.868 56.227 59.886 56.371 ;
     RECT  60.624 56.263 60.642 56.371 ;
     RECT  78.015 55.687 78.75 56.371 ;
     RECT  34.56 56.371 47.07 56.381 ;
     RECT  49.644 56.255 49.77 56.381 ;
     RECT  2.304 56.291 4.986 56.399 ;
     RECT  49.752 56.381 49.77 56.399 ;
     RECT  78.015 56.371 79.254 56.399 ;
     RECT  2.415 56.399 4.986 56.489 ;
     RECT  47.052 56.381 47.07 56.489 ;
     RECT  59.868 56.371 60.642 56.489 ;
     RECT  75.132 56.371 75.222 56.489 ;
     RECT  79.236 56.399 79.254 56.489 ;
     RECT  2.415 56.489 4.914 56.525 ;
     RECT  59.868 56.489 60.534 56.525 ;
     RECT  85.356 56.021 85.374 56.533 ;
     RECT  76.356 56.371 76.374 56.561 ;
     RECT  85.356 56.533 85.482 56.573 ;
     RECT  73.764 56.371 73.782 56.633 ;
     RECT  81.504 56.299 81.522 56.633 ;
     RECT  56.415 54.635 56.697 56.731 ;
     RECT  10.116 56.641 10.134 56.759 ;
     RECT  51.015 56.219 51.858 56.759 ;
     RECT  56.304 56.731 56.697 56.768 ;
     RECT  34.56 56.381 46.242 56.779 ;
     RECT  83.232 56.291 84.042 56.795 ;
     RECT  6.84 56.219 6.858 56.831 ;
     RECT  83.232 56.795 83.898 56.867 ;
     RECT  0.108 56.299 0.126 57.005 ;
     RECT  64.512 56.767 64.53 57.029 ;
     RECT  84.888 56.971 84.906 57.037 ;
     RECT  34.524 56.779 46.242 57.065 ;
     RECT  82.404 56.371 82.422 57.073 ;
     RECT  34.74 57.065 46.242 57.145 ;
     RECT  72.615 56.327 72.897 57.145 ;
     RECT  70.704 56.101 70.722 57.173 ;
     RECT  72.072 57.145 72.897 57.181 ;
     RECT  82.404 57.073 82.674 57.181 ;
     RECT  34.74 57.145 46.674 57.299 ;
     RECT  77.256 57.001 77.274 57.299 ;
     RECT  34.776 57.299 44.658 57.335 ;
     RECT  84.852 57.037 84.906 57.389 ;
     RECT  71.676 57.181 72.897 57.403 ;
     RECT  71.676 57.403 72.954 57.407 ;
     RECT  72.072 57.407 72.954 57.437 ;
     RECT  34.776 57.335 44.442 57.443 ;
     RECT  61.815 55.319 62.097 57.451 ;
     RECT  67.215 55.751 67.497 57.451 ;
     RECT  72.36 57.437 72.954 57.451 ;
     RECT  78.015 56.399 78.297 57.451 ;
     RECT  30.78 57.181 30.798 57.479 ;
     RECT  61.524 57.451 62.097 57.569 ;
     RECT  60.588 57.541 60.606 57.581 ;
     RECT  34.776 57.443 44.226 57.641 ;
     RECT  72.36 57.451 73.098 57.641 ;
     RECT  72.468 57.641 73.098 57.691 ;
     RECT  2.415 56.525 4.554 57.721 ;
     RECT  45.612 57.299 46.674 57.721 ;
     RECT  72.468 57.691 73.818 57.721 ;
     RECT  81.972 57.181 82.674 57.811 ;
     RECT  0.54 57.541 0.558 57.821 ;
     RECT  60.732 57.721 60.75 57.839 ;
     RECT  78.015 57.451 78.462 57.839 ;
     RECT  66.672 57.451 67.497 57.875 ;
     RECT  81.828 57.811 82.674 57.911 ;
     RECT  45.612 57.721 46.89 57.955 ;
     RECT  72.468 57.721 73.89 57.955 ;
     RECT  45.612 57.955 47.034 57.983 ;
     RECT  83.415 56.867 83.898 57.991 ;
     RECT  36.108 57.641 44.226 58.019 ;
     RECT  45.612 57.983 46.206 58.081 ;
     RECT  47.016 57.983 47.034 58.109 ;
     RECT  81.972 57.911 82.674 58.109 ;
     RECT  2.415 57.721 4.878 58.123 ;
     RECT  8.82 57.991 8.838 58.145 ;
     RECT  36.108 58.019 41.13 58.145 ;
     RECT  81.972 58.109 82.35 58.145 ;
     RECT  72.468 57.955 74.178 58.157 ;
     RECT  2.415 58.123 5.022 58.189 ;
     RECT  2.415 58.189 5.094 58.219 ;
     RECT  2.304 58.219 5.094 58.225 ;
     RECT  45.576 58.081 46.206 58.225 ;
     RECT  75.204 56.489 75.222 58.225 ;
     RECT  41.94 58.019 44.226 58.253 ;
     RECT  59.472 58.081 59.49 58.261 ;
     RECT  2.304 58.225 5.166 58.289 ;
     RECT  34.776 57.641 35.298 58.289 ;
     RECT  2.415 58.289 5.166 58.351 ;
     RECT  36.108 58.145 41.094 58.379 ;
     RECT  47.304 58.225 47.394 58.379 ;
     RECT  59.472 58.261 59.634 58.379 ;
     RECT  74.592 58.225 75.222 58.379 ;
     RECT  59.472 58.379 59.49 58.387 ;
     RECT  59.112 58.387 59.49 58.415 ;
     RECT  85.464 57.787 85.482 58.415 ;
     RECT  34.815 58.289 35.298 58.531 ;
     RECT  36.108 58.379 37.458 58.531 ;
     RECT  45.216 58.225 46.206 58.531 ;
     RECT  42.156 58.253 44.226 58.621 ;
     RECT  45.144 58.531 46.206 58.621 ;
     RECT  42.156 58.621 46.206 58.649 ;
     RECT  59.112 58.415 59.13 58.649 ;
     RECT  74.628 58.379 75.222 58.649 ;
     RECT  2.415 58.351 5.238 58.685 ;
     RECT  83.415 57.991 84.042 58.685 ;
     RECT  34.815 58.531 37.458 58.733 ;
     RECT  72.468 58.157 73.818 58.733 ;
     RECT  78.015 57.839 78.297 58.801 ;
     RECT  67.215 57.875 67.497 58.891 ;
     RECT  34.815 58.733 37.422 58.919 ;
     RECT  82.224 58.145 82.35 58.927 ;
     RECT  61.815 57.569 62.097 59.029 ;
     RECT  2.415 58.685 5.094 59.035 ;
     RECT  61.488 59.029 62.097 59.069 ;
     RECT  42.156 58.649 44.874 59.071 ;
     RECT  61.815 59.069 62.097 59.071 ;
     RECT  72.468 58.733 73.53 59.071 ;
     RECT  82.224 58.927 82.674 59.071 ;
     RECT  2.304 59.035 5.094 59.099 ;
     RECT  82.008 59.071 82.674 59.099 ;
     RECT  42.084 59.071 44.874 59.117 ;
     RECT  2.415 59.099 5.094 59.189 ;
     RECT  55.08 58.801 55.098 59.189 ;
     RECT  58.716 59.071 58.734 59.189 ;
     RECT  61.815 59.071 62.442 59.189 ;
     RECT  77.58 58.801 78.297 59.189 ;
     RECT  54.144 58.699 54.162 59.225 ;
     RECT  70.74 58.891 70.758 59.225 ;
     RECT  82.008 59.099 82.026 59.225 ;
     RECT  38.268 58.379 41.094 59.233 ;
     RECT  72.432 59.071 73.53 59.233 ;
     RECT  38.268 59.233 41.13 59.269 ;
     RECT  63.216 59.161 63.234 59.341 ;
     RECT  77.868 59.189 78.297 59.341 ;
     RECT  67.104 58.891 67.497 59.369 ;
     RECT  47.304 58.379 47.322 59.431 ;
     RECT  2.415 59.189 4.95 59.459 ;
     RECT  42.156 59.117 44.838 59.459 ;
     RECT  63.216 59.341 63.342 59.459 ;
     RECT  72.396 59.233 73.53 59.459 ;
     RECT  77.868 59.341 78.75 59.459 ;
     RECT  84.888 58.651 84.906 59.467 ;
     RECT  63.216 59.459 63.234 59.495 ;
     RECT  38.268 59.269 41.238 59.503 ;
     RECT  2.415 59.459 4.662 59.531 ;
     RECT  46.728 59.431 47.322 59.531 ;
     RECT  81.504 59.341 81.522 59.567 ;
     RECT  38.232 59.503 41.238 59.575 ;
     RECT  48.456 59.233 48.474 59.575 ;
     RECT  36.108 58.919 37.422 59.611 ;
     RECT  38.232 59.575 41.274 59.611 ;
     RECT  74.628 58.649 74.97 59.611 ;
     RECT  34.815 58.919 35.226 59.707 ;
     RECT  36.108 59.611 41.274 59.707 ;
     RECT  48.24 59.575 48.474 59.729 ;
     RECT  59.292 59.503 59.31 59.729 ;
     RECT  72.432 59.459 73.53 59.729 ;
     RECT  84.852 59.467 84.906 59.737 ;
     RECT  78.015 59.459 78.75 59.765 ;
     RECT  72.615 59.729 73.53 59.801 ;
     RECT  84.852 59.737 85.482 59.837 ;
     RECT  47.412 59.803 47.61 59.843 ;
     RECT  34.815 59.707 41.274 59.845 ;
     RECT  2.415 59.531 4.626 59.881 ;
     RECT  5.904 59.341 5.922 59.881 ;
     RECT  48.42 59.729 48.474 59.881 ;
     RECT  49.248 59.809 49.266 59.881 ;
     RECT  74.34 59.611 75.114 59.881 ;
     RECT  2.304 59.881 4.626 59.933 ;
     RECT  85.356 59.837 85.482 59.933 ;
     RECT  5.76 59.881 5.922 59.971 ;
     RECT  45.615 58.649 45.897 59.995 ;
     RECT  83.415 58.685 83.862 60.007 ;
     RECT  45.615 59.995 46.494 60.035 ;
     RECT  5.508 59.971 5.922 60.043 ;
     RECT  51.015 56.759 51.297 60.043 ;
     RECT  47.412 59.843 47.466 60.071 ;
     RECT  5.508 60.043 6.102 60.115 ;
     RECT  83.34 60.007 83.862 60.115 ;
     RECT  42.228 59.459 44.838 60.151 ;
     RECT  45.615 60.035 45.897 60.151 ;
     RECT  74.268 59.881 75.114 60.151 ;
     RECT  83.34 60.115 83.97 60.151 ;
     RECT  5.508 60.115 6.606 60.179 ;
     RECT  48.42 59.881 49.266 60.179 ;
     RECT  5.508 60.179 5.634 60.221 ;
     RECT  83.196 60.151 83.97 60.241 ;
     RECT  5.508 60.221 5.526 60.269 ;
     RECT  59.976 59.881 59.994 60.269 ;
     RECT  74.088 60.151 75.294 60.269 ;
     RECT  78.015 59.765 78.462 60.269 ;
     RECT  79.38 59.971 79.398 60.269 ;
     RECT  61.815 59.189 62.097 60.277 ;
     RECT  2.34 59.933 4.626 60.313 ;
     RECT  34.815 59.845 41.31 60.313 ;
     RECT  42.228 60.151 45.897 60.313 ;
     RECT  34.815 60.313 45.897 60.317 ;
     RECT  6.588 60.179 6.606 60.341 ;
     RECT  47.412 60.071 47.43 60.341 ;
     RECT  75.096 60.269 75.294 60.341 ;
     RECT  82.62 60.241 83.97 60.341 ;
     RECT  34.815 60.317 44.838 60.377 ;
     RECT  75.276 60.341 75.294 60.377 ;
     RECT  50.868 60.043 51.297 60.379 ;
     RECT  48.636 60.179 49.266 60.385 ;
     RECT  34.815 60.377 44.73 60.413 ;
     RECT  61.815 60.277 62.766 60.413 ;
     RECT  70.704 59.611 70.722 60.413 ;
     RECT  74.088 60.269 74.178 60.413 ;
     RECT  79.524 60.277 79.542 60.413 ;
     RECT  50.364 60.379 51.297 60.419 ;
     RECT  2.34 60.313 4.842 60.539 ;
     RECT  50.508 60.419 51.297 60.539 ;
     RECT  82.728 60.341 83.97 60.539 ;
     RECT  48.636 60.385 49.518 60.575 ;
     RECT  85.356 59.933 85.374 60.611 ;
     RECT  34.815 60.413 44.622 60.691 ;
     RECT  49.032 60.575 49.518 60.691 ;
     RECT  34.776 60.691 44.622 60.809 ;
     RECT  66.384 60.808 66.402 60.845 ;
     RECT  34.776 60.809 37.674 60.917 ;
     RECT  46.764 60.691 46.782 60.917 ;
     RECT  49.032 60.691 49.662 60.917 ;
     RECT  2.34 60.539 4.59 60.953 ;
     RECT  72.615 59.801 73.278 60.989 ;
     RECT  2.415 60.953 4.59 61.037 ;
     RECT  78.015 60.269 78.297 61.051 ;
     RECT  49.032 60.917 49.41 61.079 ;
     RECT  69.912 60.961 69.93 61.079 ;
     RECT  84.888 60.715 84.906 61.147 ;
     RECT  74.16 60.413 74.178 61.151 ;
     RECT  76.968 60.925 76.986 61.151 ;
     RECT  38.484 60.809 44.622 61.159 ;
     RECT  81.504 60.961 81.522 61.223 ;
     RECT  38.484 61.159 44.694 61.231 ;
     RECT  77.976 61.051 78.297 61.259 ;
     RECT  38.484 61.231 44.73 61.321 ;
     RECT  45.615 60.317 45.897 61.321 ;
     RECT  47.916 61.003 47.934 61.321 ;
     RECT  75.348 61.189 75.366 61.321 ;
     RECT  49.284 61.079 49.41 61.349 ;
     RECT  61.815 60.413 62.097 61.357 ;
     RECT  8.964 61.051 8.982 61.429 ;
     RECT  70.704 61.357 70.722 61.457 ;
     RECT  75.06 61.321 75.366 61.457 ;
     RECT  47.916 61.321 48.114 61.465 ;
     RECT  2.415 61.037 4.554 61.493 ;
     RECT  8.928 61.429 8.982 61.493 ;
     RECT  76.32 61.231 76.338 61.493 ;
     RECT  34.815 60.917 37.674 61.531 ;
     RECT  38.484 61.321 45.897 61.531 ;
     RECT  84.852 61.147 84.906 61.579 ;
     RECT  7.815 50.621 8.097 61.591 ;
     RECT  59.832 61.579 59.85 61.591 ;
     RECT  61.632 61.357 62.097 61.591 ;
     RECT  67.215 59.369 67.497 61.591 ;
     RECT  8.928 61.493 8.946 61.619 ;
     RECT  32.904 56.129 32.922 61.619 ;
     RECT  59.832 61.591 60.066 61.619 ;
     RECT  74.844 61.579 75.006 61.619 ;
     RECT  7.815 61.591 8.154 61.627 ;
     RECT  47.556 61.465 48.114 61.655 ;
     RECT  61.632 61.591 62.766 61.655 ;
     RECT  84.852 61.579 85.482 61.655 ;
     RECT  5.832 61.501 5.85 61.661 ;
     RECT  72.615 60.989 73.098 61.663 ;
     RECT  7.815 61.627 8.802 61.664 ;
     RECT  59.976 61.619 60.066 61.691 ;
     RECT  0.108 61.579 0.126 61.709 ;
     RECT  6.84 61.591 6.858 61.709 ;
     RECT  84.852 61.655 84.906 61.727 ;
     RECT  2.415 61.493 4.41 61.771 ;
     RECT  7.815 61.664 8.154 61.771 ;
     RECT  72.504 61.663 73.098 61.771 ;
     RECT  82.728 60.539 83.862 61.771 ;
     RECT  2.304 61.771 4.41 61.799 ;
     RECT  47.664 61.655 48.114 61.799 ;
     RECT  7.38 61.771 8.154 61.889 ;
     RECT  59.976 61.691 59.994 61.889 ;
     RECT  61.815 61.655 62.766 61.889 ;
     RECT  66.996 61.591 67.497 61.889 ;
     RECT  72.504 61.771 73.638 61.889 ;
     RECT  74.988 61.619 75.006 61.889 ;
     RECT  56.415 56.768 56.697 61.897 ;
     RECT  72.504 61.889 73.566 61.897 ;
     RECT  81.972 61.771 81.99 61.897 ;
     RECT  82.728 61.771 84.042 61.897 ;
     RECT  47.664 61.799 47.682 61.925 ;
     RECT  81.972 61.897 84.042 61.925 ;
     RECT  9.72 61.771 9.738 61.961 ;
     RECT  71.496 61.861 71.514 61.961 ;
     RECT  75.78 61.771 75.798 61.961 ;
     RECT  70.74 61.591 70.758 61.997 ;
     RECT  81.972 61.925 83.826 61.997 ;
     RECT  72.396 61.897 73.566 62.005 ;
     RECT  78.015 61.259 78.297 62.005 ;
     RECT  34.815 61.531 45.897 62.033 ;
     RECT  72.36 62.005 73.566 62.041 ;
     RECT  71.82 62.041 73.566 62.042 ;
     RECT  2.304 61.799 3.618 62.045 ;
     RECT  82.548 61.997 83.826 62.069 ;
     RECT  84.888 61.727 84.906 62.069 ;
     RECT  54.9 61.933 54.918 62.131 ;
     RECT  34.815 62.033 44.622 62.159 ;
     RECT  71.82 62.042 73.53 62.159 ;
     RECT  77.652 62.005 78.297 62.159 ;
     RECT  34.815 62.159 41.85 62.189 ;
     RECT  54.9 62.131 55.026 62.195 ;
     RECT  56.34 61.897 56.697 62.195 ;
     RECT  82.548 62.069 83.754 62.195 ;
     RECT  4.392 61.799 4.41 62.231 ;
     RECT  43.236 62.159 44.622 62.231 ;
     RECT  2.415 62.045 3.618 62.267 ;
     RECT  80.964 62.041 80.982 62.267 ;
     RECT  36 62.189 41.85 62.303 ;
     RECT  72.36 62.159 73.53 62.303 ;
     RECT  2.415 62.267 3.294 62.339 ;
     RECT  36 62.303 38.79 62.339 ;
     RECT  43.236 62.231 43.902 62.339 ;
     RECT  82.548 62.195 83.697 62.339 ;
     RECT  7.815 61.889 8.097 62.387 ;
     RECT  13.215 2.413 13.497 62.387 ;
     RECT  18.615 18.959 18.897 62.387 ;
     RECT  24.015 45.533 24.297 62.387 ;
     RECT  29.415 23.549 29.697 62.387 ;
     RECT  45.615 62.033 45.897 62.387 ;
     RECT  51.015 60.539 51.297 62.387 ;
     RECT  56.415 62.195 56.697 62.387 ;
     RECT  61.815 61.889 62.097 62.387 ;
     RECT  67.215 61.889 67.497 62.387 ;
     RECT  72.36 62.303 72.897 62.387 ;
     RECT  83.415 62.339 83.697 62.387 ;
     RECT  2.415 62.339 2.934 62.429 ;
     RECT  32.688 61.735 32.706 62.429 ;
     RECT  34.815 62.189 35.226 62.429 ;
     RECT  36 62.339 36.954 62.429 ;
     RECT  43.272 62.339 43.902 62.429 ;
     RECT  49.284 61.349 49.302 62.429 ;
     RECT  72.36 62.387 72.774 62.429 ;
     RECT  51.015 62.387 51.105 62.437 ;
     RECT  78.015 62.159 78.297 62.437 ;
     RECT  2.415 62.429 2.79 62.465 ;
     RECT  36 62.429 36.45 62.465 ;
     RECT  39.528 62.303 41.85 62.465 ;
     RECT  85.464 62.395 85.482 62.465 ;
     RECT  36.432 62.465 36.45 62.537 ;
     RECT  38.16 62.339 38.79 62.537 ;
     RECT  40.215 62.465 41.31 62.537 ;
     RECT  43.308 62.429 43.902 62.537 ;
     RECT  50.22 62.437 51.105 62.537 ;
     RECT  55.008 62.195 55.026 62.537 ;
     RECT  72.36 62.429 72.705 62.537 ;
     RECT  78.015 62.437 78.678 62.537 ;
     RECT  82.548 62.339 82.674 62.537 ;
     RECT  43.452 62.537 43.902 62.573 ;
     RECT  38.772 62.537 38.79 62.609 ;
     RECT  43.452 62.573 43.866 62.609 ;
     RECT  82.656 62.537 82.674 62.609 ;
     RECT  31.32 62.545 31.338 62.621 ;
     RECT  34.815 62.429 35.082 62.621 ;
     RECT  2.415 62.465 2.505 62.657 ;
     RECT  7.815 62.387 7.905 62.657 ;
     RECT  13.215 62.387 13.305 62.657 ;
     RECT  18.615 62.387 18.705 62.657 ;
     RECT  24.015 62.387 24.105 62.657 ;
     RECT  29.415 62.387 29.505 62.657 ;
     RECT  34.815 62.621 34.905 62.657 ;
     RECT  40.215 62.537 40.59 62.657 ;
     RECT  45.615 62.387 45.705 62.657 ;
     RECT  50.4 62.537 51.105 62.657 ;
     RECT  56.415 62.387 56.505 62.657 ;
     RECT  61.815 62.387 61.905 62.657 ;
     RECT  67.215 62.387 67.305 62.657 ;
     RECT  72.615 62.537 72.705 62.657 ;
     RECT  78.015 62.537 78.105 62.657 ;
     RECT  83.415 62.387 83.505 62.657 ;
     RECT  40.572 62.657 40.59 62.699 ;
     RECT  43.848 62.609 43.866 62.699 ;
     RECT  50.4 62.657 50.418 63.869 ;
    LAYER M4 ;
     RECT  0.084 2.352 0.569 2.376 ;
     RECT  0.06 2.376 0.569 2.784 ;
     RECT  0.084 2.784 0.569 2.808 ;
     RECT  0.06 2.808 0.569 3.216 ;
     RECT  0.084 3.216 0.569 3.24 ;
     RECT  0.06 3.24 0.569 3.6 ;
     RECT  0.084 3.6 0.569 3.624 ;
     RECT  0.06 3.624 0.569 4.032 ;
     RECT  0.084 4.032 0.569 4.056 ;
     RECT  0.06 4.056 0.569 4.464 ;
     RECT  0.084 4.464 0.569 4.488 ;
     RECT  0.06 4.488 0.569 4.896 ;
     RECT  0.084 4.896 0.569 4.92 ;
     RECT  0.06 4.92 0.569 5.28 ;
     RECT  0.084 5.28 0.569 5.304 ;
     RECT  0.06 5.304 0.569 5.712 ;
     RECT  0.084 5.712 0.569 5.736 ;
     RECT  0.06 5.736 0.569 6.144 ;
     RECT  0.084 6.144 0.569 6.168 ;
     RECT  0.06 6.168 0.569 6.576 ;
     RECT  0.084 6.576 0.569 6.6 ;
     RECT  0.06 6.6 0.569 6.96 ;
     RECT  0.084 6.96 0.569 6.984 ;
     RECT  0.06 6.984 0.569 7.392 ;
     RECT  0.084 7.392 0.569 7.416 ;
     RECT  0.06 7.416 0.569 7.824 ;
     RECT  0.084 7.824 0.569 7.848 ;
     RECT  0.06 7.848 0.569 8.256 ;
     RECT  0.084 8.256 0.569 8.28 ;
     RECT  0.06 8.28 0.569 8.64 ;
     RECT  0.084 8.64 0.569 8.664 ;
     RECT  0.06 8.664 0.569 9.072 ;
     RECT  0.084 9.072 0.569 9.096 ;
     RECT  0.06 9.096 0.569 9.504 ;
     RECT  0.084 9.504 0.569 9.528 ;
     RECT  0.06 9.528 0.569 9.936 ;
     RECT  0.084 9.936 0.569 9.96 ;
     RECT  0.06 9.96 0.569 10.32 ;
     RECT  0.084 10.32 0.569 10.344 ;
     RECT  0.06 10.344 0.569 10.752 ;
     RECT  0.084 10.752 0.569 10.776 ;
     RECT  0.06 10.776 0.569 11.184 ;
     RECT  0.084 11.184 0.569 11.208 ;
     RECT  0.06 11.208 0.569 11.616 ;
     RECT  0.084 11.616 0.569 11.64 ;
     RECT  0.06 11.64 0.569 12 ;
     RECT  0.084 12 0.569 12.024 ;
     RECT  0.06 12.024 0.569 12.432 ;
     RECT  0.084 12.432 0.569 12.456 ;
     RECT  0.06 12.456 0.569 12.864 ;
     RECT  0.084 12.864 0.569 12.888 ;
     RECT  0.06 12.888 0.569 13.296 ;
     RECT  0.084 13.296 0.569 13.32 ;
     RECT  0.06 13.32 0.569 13.68 ;
     RECT  0.084 13.68 0.569 13.704 ;
     RECT  0.06 13.704 0.569 14.112 ;
     RECT  0.084 14.112 0.569 14.136 ;
     RECT  0.06 14.136 0.569 14.544 ;
     RECT  0.084 14.544 0.569 14.568 ;
     RECT  0.06 14.568 0.569 14.976 ;
     RECT  0.084 14.976 0.569 15 ;
     RECT  0.06 15 0.569 15.36 ;
     RECT  0.084 15.36 0.569 15.384 ;
     RECT  0.06 15.384 0.569 15.792 ;
     RECT  0.084 15.792 0.569 15.816 ;
     RECT  0.06 15.816 0.569 16.224 ;
     RECT  0.084 16.224 0.569 16.248 ;
     RECT  0.06 16.248 0.569 16.656 ;
     RECT  0.084 16.656 0.569 16.68 ;
     RECT  0.06 16.68 0.569 17.04 ;
     RECT  0.084 17.04 0.569 17.064 ;
     RECT  0.06 17.064 0.569 17.472 ;
     RECT  0.084 17.472 0.569 17.496 ;
     RECT  0.06 17.496 0.569 17.904 ;
     RECT  0.084 17.904 0.569 17.928 ;
     RECT  0.06 17.928 0.569 18.336 ;
     RECT  0.084 18.336 0.569 18.36 ;
     RECT  0.06 18.36 0.569 18.72 ;
     RECT  0.084 18.72 0.569 18.744 ;
     RECT  0.06 18.744 0.569 19.152 ;
     RECT  0.084 19.152 0.569 19.176 ;
     RECT  0.06 19.176 0.569 19.584 ;
     RECT  0.084 19.584 0.569 19.608 ;
     RECT  0.06 19.608 0.569 20.016 ;
     RECT  0.084 20.016 0.569 20.04 ;
     RECT  0.06 20.04 0.569 20.4 ;
     RECT  0.084 20.4 0.569 20.424 ;
     RECT  0.06 20.424 0.569 20.832 ;
     RECT  0.084 20.832 0.569 20.856 ;
     RECT  0.06 20.856 0.569 21.264 ;
     RECT  0.084 21.264 0.569 21.288 ;
     RECT  0.06 21.288 0.569 21.696 ;
     RECT  0.084 21.696 0.569 21.72 ;
     RECT  0.06 21.72 0.569 22.08 ;
     RECT  0.084 22.08 0.569 22.104 ;
     RECT  0.06 22.104 0.569 22.512 ;
     RECT  0.084 22.512 0.569 22.536 ;
     RECT  0.06 22.536 0.569 22.944 ;
     RECT  0.084 22.944 0.569 22.968 ;
     RECT  0.06 22.968 0.569 23.376 ;
     RECT  0.084 23.376 0.569 23.4 ;
     RECT  0.06 23.4 0.569 23.76 ;
     RECT  0.084 23.76 0.569 23.784 ;
     RECT  0.06 23.784 0.569 24.192 ;
     RECT  0.084 24.192 0.569 24.216 ;
     RECT  0.06 24.216 0.569 24.624 ;
     RECT  0.084 24.624 0.569 24.648 ;
     RECT  0.06 24.648 0.569 25.056 ;
     RECT  0.084 25.056 0.569 25.08 ;
     RECT  0.06 25.08 0.569 25.44 ;
     RECT  0.084 25.44 0.569 25.464 ;
     RECT  0.06 25.464 0.569 25.872 ;
     RECT  0.084 25.872 0.569 25.896 ;
     RECT  0.06 25.896 0.569 26.304 ;
     RECT  0.084 26.304 0.569 26.328 ;
     RECT  0.06 26.328 0.569 26.736 ;
     RECT  0.084 26.736 0.569 26.76 ;
     RECT  0.06 26.76 0.569 27.12 ;
     RECT  0.084 27.12 0.569 27.144 ;
     RECT  0.06 27.144 0.569 27.552 ;
     RECT  0.084 27.552 0.569 27.576 ;
     RECT  0.06 27.576 0.569 27.984 ;
     RECT  0.084 27.984 0.569 28.008 ;
     RECT  0.06 28.008 0.569 28.416 ;
     RECT  0.084 28.416 0.569 28.44 ;
     RECT  0.06 28.44 0.569 28.8 ;
     RECT  0.084 28.8 0.569 28.824 ;
     RECT  0.06 28.824 0.569 29.232 ;
     RECT  0.084 29.232 0.569 29.256 ;
     RECT  0.06 29.256 0.569 29.664 ;
     RECT  0.084 29.664 0.569 29.688 ;
     RECT  0.06 29.688 0.569 30.096 ;
     RECT  0.084 30.096 0.569 30.12 ;
     RECT  0.06 30.12 0.569 30.48 ;
     RECT  0.084 30.48 0.569 30.504 ;
     RECT  0.06 30.504 0.569 30.912 ;
     RECT  0.084 30.912 0.569 30.936 ;
     RECT  0.06 30.936 0.569 31.344 ;
     RECT  0.084 31.344 0.569 31.368 ;
     RECT  0.06 31.368 0.569 31.776 ;
     RECT  0.084 31.776 0.569 31.8 ;
     RECT  0.06 31.8 0.569 32.16 ;
     RECT  0.084 32.16 0.569 32.184 ;
     RECT  0.06 32.184 0.569 32.592 ;
     RECT  0.084 32.592 0.569 32.616 ;
     RECT  0.06 32.616 0.569 33.024 ;
     RECT  0.084 33.024 0.569 33.048 ;
     RECT  0.06 33.048 0.569 33.456 ;
     RECT  0.084 33.456 0.569 33.48 ;
     RECT  0.06 33.48 0.569 33.84 ;
     RECT  0.084 33.84 0.569 33.864 ;
     RECT  0.06 33.864 0.569 34.272 ;
     RECT  0.084 34.272 0.569 34.296 ;
     RECT  0.06 34.296 0.569 34.704 ;
     RECT  0.084 34.704 0.569 34.728 ;
     RECT  0.06 34.728 0.569 35.136 ;
     RECT  0.084 35.136 0.569 35.16 ;
     RECT  0.06 35.16 0.569 35.52 ;
     RECT  0.084 35.52 0.569 35.544 ;
     RECT  0.06 35.544 0.569 35.952 ;
     RECT  0.084 35.952 0.569 35.976 ;
     RECT  0.06 35.976 0.569 36.384 ;
     RECT  0.084 36.384 0.569 36.408 ;
     RECT  0.06 36.408 0.569 36.816 ;
     RECT  0.084 36.816 0.569 36.84 ;
     RECT  0.06 36.84 0.569 37.2 ;
     RECT  0.084 37.2 0.569 37.224 ;
     RECT  0.06 37.224 0.569 37.632 ;
     RECT  0.084 37.632 0.569 37.656 ;
     RECT  0.06 37.656 0.569 38.064 ;
     RECT  0.084 38.064 0.569 38.088 ;
     RECT  0.06 38.088 0.569 38.496 ;
     RECT  0.084 38.496 0.569 38.52 ;
     RECT  0.06 38.52 0.569 38.88 ;
     RECT  0.084 38.88 0.569 38.904 ;
     RECT  0.06 38.904 0.569 39.312 ;
     RECT  0.084 39.312 0.569 39.336 ;
     RECT  0.06 39.336 0.569 39.744 ;
     RECT  0.084 39.744 0.569 39.768 ;
     RECT  0.06 39.768 0.569 40.176 ;
     RECT  0.084 40.176 0.569 40.2 ;
     RECT  0.06 40.2 0.569 40.56 ;
     RECT  0.084 40.56 0.569 40.584 ;
     RECT  0.06 40.584 0.569 40.992 ;
     RECT  0.084 40.992 0.569 41.016 ;
     RECT  0.06 41.016 0.569 41.424 ;
     RECT  0.084 41.424 0.569 41.448 ;
     RECT  0.06 41.448 0.569 41.856 ;
     RECT  0.084 41.856 0.569 41.88 ;
     RECT  0.06 41.88 0.569 42.24 ;
     RECT  0.084 42.24 0.569 42.264 ;
     RECT  0.06 42.264 0.569 42.672 ;
     RECT  0.084 42.672 0.569 42.696 ;
     RECT  0.06 42.696 0.569 43.104 ;
     RECT  0.084 43.104 0.569 43.128 ;
     RECT  0.06 43.128 0.569 43.536 ;
     RECT  0.084 43.536 0.569 43.56 ;
     RECT  0.06 43.56 0.569 43.92 ;
     RECT  0.084 43.92 0.569 43.944 ;
     RECT  0.06 43.944 0.569 44.352 ;
     RECT  0.084 44.352 0.569 44.376 ;
     RECT  0.06 44.376 0.569 44.784 ;
     RECT  0.084 44.784 0.569 44.808 ;
     RECT  0.06 44.808 0.569 45.216 ;
     RECT  0.084 45.216 0.569 45.24 ;
     RECT  0.06 45.24 0.569 45.6 ;
     RECT  0.084 45.6 0.569 45.624 ;
     RECT  0.06 45.624 0.569 46.032 ;
     RECT  0.084 46.032 0.569 46.056 ;
     RECT  0.06 46.056 0.569 46.464 ;
     RECT  0.084 46.464 0.569 46.488 ;
     RECT  0.06 46.488 0.569 46.896 ;
     RECT  0.084 46.896 0.569 46.92 ;
     RECT  0.06 46.92 0.569 47.28 ;
     RECT  0.084 47.28 0.569 47.304 ;
     RECT  0.06 47.304 0.569 47.712 ;
     RECT  0.084 47.712 0.569 47.736 ;
     RECT  0.06 47.736 0.569 48.144 ;
     RECT  0.084 48.144 0.569 48.168 ;
     RECT  0.06 48.168 0.569 48.576 ;
     RECT  0.084 48.576 0.569 48.6 ;
     RECT  0.06 48.6 0.569 48.96 ;
     RECT  0.084 48.96 0.569 48.984 ;
     RECT  0.06 48.984 0.569 49.392 ;
     RECT  0.084 49.392 0.569 49.416 ;
     RECT  0.06 49.416 0.569 49.824 ;
     RECT  0.084 49.824 0.569 49.848 ;
     RECT  0.06 49.848 0.569 50.256 ;
     RECT  0.084 50.256 0.569 50.28 ;
     RECT  0.06 50.28 0.569 50.64 ;
     RECT  0.084 50.64 0.569 50.664 ;
     RECT  0.06 50.664 0.569 51.072 ;
     RECT  0.084 51.072 0.569 51.096 ;
     RECT  0.06 51.096 0.569 51.504 ;
     RECT  0.084 51.504 0.569 51.528 ;
     RECT  0.06 51.528 0.569 51.936 ;
     RECT  0.084 51.936 0.569 51.96 ;
     RECT  0.06 51.96 0.569 52.32 ;
     RECT  0.084 52.32 0.569 52.344 ;
     RECT  0.06 52.344 0.569 52.752 ;
     RECT  0.084 52.752 0.569 52.776 ;
     RECT  0.06 52.776 0.569 53.184 ;
     RECT  0.084 53.184 0.569 53.208 ;
     RECT  0.06 53.208 0.569 53.616 ;
     RECT  0.084 53.616 0.569 53.64 ;
     RECT  0.06 53.64 0.569 54 ;
     RECT  0.084 54 0.569 54.024 ;
     RECT  0.06 54.024 0.569 54.432 ;
     RECT  0.084 54.432 0.569 54.456 ;
     RECT  0.06 54.456 0.569 54.864 ;
     RECT  0.084 54.864 0.569 54.888 ;
     RECT  0.06 54.888 0.569 55.296 ;
     RECT  0.084 55.296 0.569 55.32 ;
     RECT  0.06 55.32 0.569 55.68 ;
     RECT  0.084 55.68 0.569 55.704 ;
     RECT  0.06 55.704 0.569 56.112 ;
     RECT  0.084 56.112 0.569 56.136 ;
     RECT  0.06 56.136 0.569 56.544 ;
     RECT  0.084 56.544 0.569 56.568 ;
     RECT  0.06 56.568 0.569 56.976 ;
     RECT  0.084 56.976 0.569 57 ;
     RECT  0.06 57 0.569 57.36 ;
     RECT  0.084 57.36 0.569 57.384 ;
     RECT  0.06 57.384 0.569 57.792 ;
     RECT  0.084 57.792 0.569 57.816 ;
     RECT  0.06 57.816 0.569 58.224 ;
     RECT  0.084 58.224 0.569 58.248 ;
     RECT  0.06 58.248 0.569 58.656 ;
     RECT  0.084 58.656 0.569 58.68 ;
     RECT  0.06 58.68 0.569 59.04 ;
     RECT  0.084 59.04 0.569 59.064 ;
     RECT  0.06 59.064 0.569 59.472 ;
     RECT  0.084 59.472 0.569 59.496 ;
     RECT  0.06 59.496 0.569 59.904 ;
     RECT  0.084 59.904 0.569 59.928 ;
     RECT  0.06 59.928 0.569 60.336 ;
     RECT  0.084 60.336 0.569 60.36 ;
     RECT  0.06 60.36 0.569 60.72 ;
     RECT  0.084 60.72 0.569 60.744 ;
     RECT  0.06 60.744 0.569 61.152 ;
     RECT  0.084 61.152 0.569 61.176 ;
     RECT  0.06 61.176 0.569 61.584 ;
     RECT  0.084 61.584 0.569 61.608 ;
     RECT  0.06 61.608 0.569 62.016 ;
     RECT  0.084 62.016 0.569 62.04 ;
     RECT  0.06 62.04 0.569 62.4 ;
     RECT  0.084 62.4 0.569 62.424 ;
     RECT  0.569 2.352 2.401 6.168 ;
     RECT  2.401 2.256 2.408 6.168 ;
     RECT  0.569 7.392 2.408 36.84 ;
     RECT  0.569 38.064 2.408 43.128 ;
     RECT  0.569 44.352 2.408 52.776 ;
     RECT  0.569 54 2.408 62.424 ;
     RECT  2.408 2.148 2.512 62.652 ;
     RECT  2.512 2.256 2.513 62.424 ;
     RECT  2.513 2.256 2.704 62.382 ;
     RECT  2.704 9.072 2.765 19.608 ;
     RECT  2.704 23.376 2.801 27.144 ;
     RECT  2.704 55.536 2.801 61.704 ;
     RECT  2.704 2.256 2.819 2.808 ;
     RECT  2.765 12.528 2.837 19.608 ;
     RECT  2.801 25.008 2.837 27.144 ;
     RECT  2.704 34.704 2.837 35.448 ;
     RECT  2.704 36.624 2.837 36.84 ;
     RECT  2.704 48.096 2.837 48.984 ;
     RECT  2.801 58.128 2.837 61.704 ;
     RECT  2.704 44.352 2.873 45.336 ;
     RECT  2.765 9.072 2.917 11.208 ;
     RECT  2.801 55.536 3.053 56.904 ;
     RECT  2.837 13.68 3.125 19.608 ;
     RECT  3.125 13.68 3.155 18.456 ;
     RECT  3.155 13.68 3.377 14.232 ;
     RECT  3.155 15.792 3.377 18.456 ;
     RECT  2.837 25.008 3.443 26.76 ;
     RECT  2.873 45.312 3.443 45.336 ;
     RECT  2.704 50.16 3.443 53.016 ;
     RECT  2.819 2.784 3.449 2.808 ;
     RECT  2.704 30.096 3.491 33.576 ;
     RECT  2.704 46.464 3.521 47.016 ;
     RECT  2.837 60.912 3.557 61.704 ;
     RECT  2.704 39.312 3.685 43.128 ;
     RECT  2.704 5.712 3.695 5.736 ;
     RECT  3.685 39.264 3.731 43.128 ;
     RECT  3.443 50.16 3.737 50.712 ;
     RECT  2.704 28.416 3.805 28.824 ;
     RECT  2.837 58.128 3.805 58.152 ;
     RECT  2.837 59.472 3.805 59.928 ;
     RECT  2.704 38.208 3.841 38.232 ;
     RECT  3.731 39.264 3.841 39.336 ;
     RECT  2.837 34.752 3.881 35.448 ;
     RECT  3.805 27.744 3.884 28.824 ;
     RECT  3.491 30.096 3.884 31.128 ;
     RECT  2.704 20.928 3.913 21.048 ;
     RECT  3.521 46.464 3.913 46.584 ;
     RECT  2.704 54.432 3.913 54.456 ;
     RECT  3.805 58.128 3.913 59.928 ;
     RECT  2.704 3.984 3.949 4.488 ;
     RECT  3.377 16.56 3.953 18.456 ;
     RECT  3.884 27.744 3.971 31.128 ;
     RECT  3.913 56.928 3.971 59.928 ;
     RECT  3.731 41.136 3.973 43.128 ;
     RECT  3.737 50.16 3.973 50.664 ;
     RECT  2.917 10.704 3.98 11.208 ;
     RECT  2.837 12.528 3.98 12.552 ;
     RECT  3.971 56.928 3.997 58.152 ;
     RECT  2.837 48.096 4.021 48.168 ;
     RECT  3.973 49.536 4.021 50.664 ;
     RECT  2.704 7.392 4.025 7.992 ;
     RECT  3.98 10.704 4.025 12.552 ;
     RECT  2.704 22.224 4.025 22.248 ;
     RECT  2.801 23.856 4.025 23.88 ;
     RECT  3.973 41.136 4.025 43.848 ;
     RECT  4.021 48.096 4.025 50.664 ;
     RECT  3.443 52.32 4.025 53.016 ;
     RECT  3.997 56.928 4.025 56.952 ;
     RECT  3.971 59.232 4.025 59.928 ;
     RECT  2.917 9.072 4.061 9.528 ;
     RECT  4.025 48.096 4.061 49.56 ;
     RECT  4.025 11.952 4.093 12.552 ;
     RECT  3.377 13.68 4.093 14.136 ;
     RECT  3.491 32.592 4.097 33.432 ;
     RECT  4.025 59.232 4.097 59.496 ;
     RECT  3.695 5.712 4.129 6.312 ;
     RECT  4.061 9.504 4.133 9.528 ;
     RECT  3.913 46.128 4.133 46.584 ;
     RECT  4.061 48.096 4.133 49.032 ;
     RECT  3.881 35.136 4.169 35.448 ;
     RECT  4.093 11.952 4.211 14.136 ;
     RECT  4.129 5.712 4.213 6.84 ;
     RECT  3.913 20.784 4.237 21.048 ;
     RECT  4.237 20.784 4.307 21.528 ;
     RECT  3.971 28.368 4.321 29.112 ;
     RECT  4.025 7.968 4.349 7.992 ;
     RECT  4.169 35.136 4.421 35.16 ;
     RECT  3.841 38.208 4.451 39.336 ;
     RECT  4.364 47.76 4.451 47.784 ;
     RECT  3.053 55.824 4.451 55.944 ;
     RECT  3.953 17.904 4.457 18.456 ;
     RECT  4.025 43.104 4.493 43.848 ;
     RECT  4.025 52.992 4.493 53.016 ;
     RECT  4.097 32.592 4.565 33.288 ;
     RECT  4.451 38.208 4.637 38.232 ;
     RECT  4.211 12.912 4.745 14.136 ;
     RECT  3.953 16.56 4.745 16.584 ;
     RECT  2.837 36.624 4.745 36.648 ;
     RECT  3.949 3.984 4.849 4.584 ;
     RECT  4.213 5.712 4.849 6.312 ;
     RECT  4.097 59.232 4.961 59.256 ;
     RECT  4.457 18.432 5.033 18.456 ;
     RECT  3.997 58.128 5.033 58.152 ;
     RECT  4.025 41.136 5.065 41.64 ;
     RECT  4.849 3.984 5.069 6.312 ;
     RECT  5.065 40.992 5.105 41.64 ;
     RECT  5.069 4.848 5.171 6.312 ;
     RECT  4.745 13.68 5.177 14.136 ;
     RECT  4.133 46.128 5.177 46.152 ;
     RECT  4.453 51.84 5.177 51.864 ;
     RECT  5.171 5.712 5.321 6.312 ;
     RECT  5.177 13.68 5.429 13.704 ;
     RECT  3.443 25.008 5.429 25.464 ;
     RECT  5.321 6.288 5.465 6.312 ;
     RECT  5.429 25.008 5.465 25.032 ;
     RECT  3.125 19.584 5.537 19.608 ;
     RECT  5.353 46.704 5.537 46.728 ;
     RECT  4.565 33.264 5.564 33.288 ;
     RECT  3.557 61.008 5.564 61.704 ;
     RECT  4.025 10.704 5.609 10.728 ;
     RECT  3.913 54.144 5.645 54.456 ;
     RECT  5.564 32.448 5.651 33.288 ;
     RECT  5.564 60.192 5.651 61.704 ;
     RECT  4.493 43.824 5.681 43.848 ;
     RECT  3.971 30.096 5.753 30.12 ;
     RECT  5.645 54.144 5.753 54.168 ;
     RECT  4.273 23.376 5.897 23.4 ;
     RECT  4.321 28.368 6.14 28.392 ;
     RECT  3.443 26.64 6.181 26.664 ;
     RECT  6.14 28.08 6.181 28.392 ;
     RECT  6.181 26.64 6.227 28.392 ;
     RECT  5.785 29.424 6.227 29.448 ;
     RECT  3.971 31.104 6.293 31.128 ;
     RECT  4.133 49.008 6.329 49.032 ;
     RECT  5.125 3.408 6.473 3.432 ;
     RECT  5.105 40.992 6.473 41.16 ;
     RECT  6.469 34.8 6.553 34.824 ;
     RECT  6.227 26.64 7.513 27.336 ;
     RECT  4.307 20.88 7.808 21.528 ;
     RECT  7.513 26.592 7.808 27.336 ;
     RECT  5.651 33.264 7.808 33.288 ;
     RECT  4.451 39.312 7.808 39.336 ;
     RECT  6.473 41.136 7.808 41.16 ;
     RECT  4.885 56.496 7.808 56.52 ;
     RECT  5.651 61.632 7.808 61.704 ;
     RECT  7.808 2.148 7.912 62.652 ;
     RECT  7.912 2.418 8.104 62.382 ;
     RECT  8.104 61.632 8.813 61.656 ;
     RECT  8.104 20.88 13.208 21.528 ;
     RECT  8.104 26.592 13.208 26.616 ;
     RECT  8.104 33.264 13.208 33.288 ;
     RECT  8.104 39.312 13.208 39.336 ;
     RECT  8.104 41.136 13.208 41.16 ;
     RECT  8.104 56.496 13.208 56.52 ;
     RECT  13.208 2.148 13.312 62.652 ;
     RECT  13.312 2.418 13.504 62.382 ;
     RECT  13.504 39.312 16.693 39.336 ;
     RECT  15.577 46.032 16.693 46.056 ;
     RECT  16.693 38.784 16.739 39.336 ;
     RECT  16.693 45.6 16.777 46.056 ;
     RECT  13.504 33.264 16.789 33.288 ;
     RECT  16.739 38.784 16.835 38.808 ;
     RECT  16.789 33.264 17.165 33.48 ;
     RECT  13.504 20.88 18.608 21.528 ;
     RECT  13.504 26.592 18.608 26.616 ;
     RECT  17.165 33.264 18.608 33.288 ;
     RECT  13.504 41.136 18.608 41.16 ;
     RECT  16.777 46.032 18.608 46.056 ;
     RECT  13.504 56.496 18.608 56.52 ;
     RECT  18.608 2.148 18.712 62.652 ;
     RECT  18.712 2.418 18.904 62.382 ;
     RECT  18.904 45.936 22.789 45.96 ;
     RECT  22.789 45.504 22.835 45.96 ;
     RECT  22.835 45.504 22.849 45.528 ;
     RECT  18.904 20.88 24.008 21.528 ;
     RECT  18.904 26.592 24.008 26.616 ;
     RECT  18.904 33.264 24.008 33.288 ;
     RECT  18.904 41.136 24.008 41.16 ;
     RECT  22.849 44.688 24.008 45.528 ;
     RECT  18.904 56.496 24.008 56.52 ;
     RECT  24.008 2.148 24.112 62.652 ;
     RECT  24.112 2.418 24.304 62.382 ;
     RECT  24.304 44.688 24.437 45.528 ;
     RECT  24.437 44.688 26.773 45.432 ;
     RECT  24.304 33.264 28.165 33.288 ;
     RECT  26.773 44.688 28.211 45.528 ;
     RECT  28.165 32.448 28.357 33.288 ;
     RECT  28.316 23.616 28.403 23.64 ;
     RECT  24.304 20.88 29.408 21.528 ;
     RECT  28.501 23.28 29.408 23.304 ;
     RECT  24.304 26.592 29.408 26.616 ;
     RECT  28.357 32.304 29.408 33.288 ;
     RECT  24.304 41.136 29.408 41.16 ;
     RECT  28.211 45.504 29.408 45.528 ;
     RECT  24.304 56.496 29.408 56.52 ;
     RECT  29.408 2.148 29.512 62.652 ;
     RECT  29.512 2.418 29.704 62.382 ;
     RECT  29.704 45.504 30.449 45.528 ;
     RECT  30.757 64.656 30.899 64.68 ;
     RECT  30.853 62.592 31.349 62.616 ;
     RECT  29.704 20.88 33.932 21.528 ;
     RECT  33.932 20.592 33.973 21.528 ;
     RECT  34.261 52.032 34.441 52.056 ;
     RECT  34.369 53.328 34.441 53.352 ;
     RECT  29.704 56.496 34.513 56.52 ;
     RECT  34.513 56.496 34.549 56.808 ;
     RECT  34.441 52.032 34.585 53.352 ;
     RECT  34.585 52.032 34.657 53.544 ;
     RECT  34.261 55.248 34.693 55.272 ;
     RECT  34.549 56.352 34.738 56.808 ;
     RECT  29.704 23.28 34.801 23.304 ;
     RECT  29.704 41.136 34.801 41.16 ;
     RECT  34.657 52.032 34.801 53.64 ;
     RECT  34.693 54.624 34.801 55.272 ;
     RECT  33.973 20.112 34.808 21.528 ;
     RECT  34.801 23.04 34.808 23.304 ;
     RECT  29.704 26.592 34.808 26.616 ;
     RECT  29.704 32.304 34.808 33.288 ;
     RECT  34.657 39.84 34.808 39.864 ;
     RECT  34.801 41.136 34.808 41.208 ;
     RECT  31.525 45.552 34.808 45.576 ;
     RECT  34.801 52.032 34.808 55.272 ;
     RECT  34.738 56.352 34.808 56.856 ;
     RECT  34.808 2.148 34.912 62.652 ;
     RECT  34.912 2.418 35.104 62.616 ;
     RECT  35.104 52.224 35.201 54.648 ;
     RECT  35.104 37.968 35.219 42.552 ;
     RECT  35.104 61.056 35.219 62.616 ;
     RECT  35.077 64.656 35.219 64.68 ;
     RECT  35.219 37.968 35.26 41.256 ;
     RECT  35.201 52.56 35.309 54.648 ;
     RECT  35.26 40.992 35.489 41.256 ;
     RECT  35.104 31.92 35.525 33.288 ;
     RECT  35.26 37.968 35.525 39.912 ;
     RECT  35.309 52.56 35.525 54.504 ;
     RECT  35.525 54.048 35.633 54.504 ;
     RECT  35.633 54.48 35.669 54.504 ;
     RECT  35.104 58.656 35.74 58.68 ;
     RECT  35.489 40.992 35.777 41.16 ;
     RECT  35.104 45.552 35.843 45.576 ;
     RECT  35.525 37.968 35.885 39.864 ;
     RECT  35.104 49.776 35.939 50.568 ;
     RECT  35.525 52.56 35.939 52.968 ;
     RECT  35.885 37.968 35.957 39.336 ;
     RECT  35.219 61.056 36.029 62.184 ;
     RECT  35.104 10.896 36.097 10.92 ;
     RECT  35.104 12.336 36.097 12.408 ;
     RECT  35.104 20.112 36.173 24.12 ;
     RECT  36.133 13.728 36.205 13.752 ;
     RECT  35.104 59.712 36.205 59.736 ;
     RECT  36.205 59.712 36.245 59.88 ;
     RECT  35.104 9.888 36.313 9.912 ;
     RECT  36.097 10.896 36.313 12.408 ;
     RECT  35.104 56.352 36.349 57.624 ;
     RECT  36.245 59.856 36.349 59.88 ;
     RECT  36.029 61.056 36.349 61.992 ;
     RECT  35.957 38.208 36.569 39.336 ;
     RECT  36.349 59.856 36.677 61.992 ;
     RECT  35.939 50.448 36.781 50.568 ;
     RECT  36.349 55.776 36.781 57.624 ;
     RECT  36.601 58.704 36.781 58.728 ;
     RECT  36.173 20.112 36.805 21.528 ;
     RECT  36.569 38.304 36.821 39.336 ;
     RECT  36.781 55.776 36.893 58.824 ;
     RECT  36.745 6.768 36.925 6.792 ;
     RECT  35.939 52.56 36.929 52.584 ;
     RECT  36.893 55.776 36.929 58.728 ;
     RECT  36.925 6.72 36.961 6.792 ;
     RECT  36.929 55.776 36.961 57.048 ;
     RECT  36.493 8.304 36.997 8.328 ;
     RECT  35.525 31.92 36.997 32.472 ;
     RECT  36.677 59.856 37.001 61.56 ;
     RECT  36.313 9.888 37.004 12.408 ;
     RECT  36.205 13.68 37.004 13.752 ;
     RECT  36.961 6.72 37.033 6.84 ;
     RECT  36.997 8.304 37.033 8.76 ;
     RECT  35.219 42.528 37.061 42.552 ;
     RECT  36.821 38.688 37.091 39.336 ;
     RECT  35.777 41.136 37.093 41.16 ;
     RECT  37.004 9.888 37.1 13.752 ;
     RECT  36.997 31.92 37.105 32.616 ;
     RECT  37.033 3.84 37.141 3.864 ;
     RECT  36.173 23.088 37.141 24.12 ;
     RECT  37.105 31.824 37.141 33.432 ;
     RECT  37.091 38.784 37.145 39.336 ;
     RECT  37.001 59.856 37.181 60.408 ;
     RECT  37.141 31.488 37.213 33.432 ;
     RECT  37.141 22.8 37.225 24.12 ;
     RECT  37.1 9.744 37.253 13.752 ;
     RECT  36.781 50.448 37.253 50.712 ;
     RECT  36.929 58.416 37.253 58.728 ;
     RECT  35.104 26.592 37.285 26.616 ;
     RECT  37.033 6.72 37.321 8.76 ;
     RECT  37.253 9.744 37.321 12.024 ;
     RECT  36.805 19.776 37.321 21.528 ;
     RECT  36.961 55.536 37.321 57.048 ;
     RECT  37.321 6.72 37.331 12.024 ;
     RECT  37.213 30.816 37.393 33.432 ;
     RECT  37.253 13.248 37.397 13.752 ;
     RECT  37.331 6.72 37.505 11.832 ;
     RECT  37.393 30.816 37.537 33.672 ;
     RECT  37.061 42.528 37.573 42.792 ;
     RECT  37.253 50.448 37.573 50.568 ;
     RECT  37.505 10.704 37.577 11.832 ;
     RECT  37.321 54.816 37.609 57.048 ;
     RECT  37.577 10.752 37.649 11.832 ;
     RECT  37.609 54.72 37.685 57.048 ;
     RECT  37.249 5.472 37.717 5.496 ;
     RECT  37.505 6.72 37.717 9.144 ;
     RECT  37.537 30.816 37.717 34.2 ;
     RECT  37.321 52.896 37.717 52.92 ;
     RECT  37.717 30.816 37.721 34.632 ;
     RECT  37.717 5.472 37.763 9.144 ;
     RECT  37.717 52.896 37.763 53.592 ;
     RECT  37.685 54.72 37.763 54.936 ;
     RECT  37.573 50.256 37.789 50.568 ;
     RECT  37.763 53.568 37.804 53.592 ;
     RECT  37.285 26.304 37.853 26.616 ;
     RECT  37.763 5.472 37.865 5.88 ;
     RECT  37.685 55.968 37.865 57.048 ;
     RECT  37.141 3.84 37.901 4.296 ;
     RECT  37.225 23.28 37.907 24.12 ;
     RECT  37.721 30.816 37.933 30.84 ;
     RECT  37.853 26.304 37.937 27.384 ;
     RECT  37.763 54.816 37.937 54.936 ;
     RECT  37.763 7.392 37.973 7.608 ;
     RECT  37.321 19.776 37.973 22.248 ;
     RECT  37.933 30.432 37.973 30.84 ;
     RECT  37.001 61.536 38.009 61.56 ;
     RECT  37.937 54.816 38.045 54.84 ;
     RECT  37.901 3.84 38.077 3.96 ;
     RECT  37.181 59.856 38.149 60.12 ;
     RECT  37.865 55.968 38.153 56.52 ;
     RECT  38.149 59.856 38.153 61.464 ;
     RECT  37.721 31.824 38.261 34.632 ;
     RECT  38.005 37.248 38.329 37.272 ;
     RECT  38.261 31.824 38.333 34.008 ;
     RECT  37.145 38.784 38.365 39.24 ;
     RECT  38.333 33.936 38.387 34.008 ;
     RECT  37.253 58.704 38.405 58.728 ;
     RECT  35.104 48.432 38.437 48.456 ;
     RECT  37.789 50.016 38.437 50.568 ;
     RECT  38.329 36.48 38.531 37.272 ;
     RECT  38.437 48.24 38.545 48.456 ;
     RECT  37.573 42.528 38.549 43.176 ;
     RECT  38.545 48 38.581 48.456 ;
     RECT  38.549 42.528 38.585 43.08 ;
     RECT  37.973 7.584 38.621 7.608 ;
     RECT  37.397 13.248 38.621 13.272 ;
     RECT  38.585 42.528 38.621 42.984 ;
     RECT  38.365 38.64 38.653 39.24 ;
     RECT  37.093 40.704 38.653 41.16 ;
     RECT  38.333 31.824 38.657 32.616 ;
     RECT  38.657 31.824 38.693 32.472 ;
     RECT  38.581 47.856 38.693 48.456 ;
     RECT  37.763 9.072 38.725 9.144 ;
     RECT  38.437 49.632 38.725 50.568 ;
     RECT  37.937 26.304 38.761 27.336 ;
     RECT  37.609 15.36 38.821 15.384 ;
     RECT  37.907 23.28 38.833 23.304 ;
     RECT  38.653 40.704 38.837 42.072 ;
     RECT  38.725 49.632 38.837 50.856 ;
     RECT  38.78 18.192 38.867 18.216 ;
     RECT  37.973 19.776 38.867 21.528 ;
     RECT  38.077 3.744 38.869 3.96 ;
     RECT  38.725 9.072 38.905 9.24 ;
     RECT  38.821 15.36 38.908 15.576 ;
     RECT  38.531 36.576 38.977 37.272 ;
     RECT  38.653 38.4 38.977 39.24 ;
     RECT  38.869 2.88 39.013 3.96 ;
     RECT  37.865 5.472 39.013 5.496 ;
     RECT  38.153 60.624 39.013 61.464 ;
     RECT  38.153 56.496 39.121 56.52 ;
     RECT  39.013 2.736 39.125 3.96 ;
     RECT  38.905 8.16 39.161 9.24 ;
     RECT  39.013 60.624 39.161 61.512 ;
     RECT  39.125 2.784 39.193 3.96 ;
     RECT  39.013 5.424 39.193 5.496 ;
     RECT  38.387 33.984 39.197 34.008 ;
     RECT  38.693 47.952 39.197 48.456 ;
     RECT  39.161 8.16 39.233 9.144 ;
     RECT  38.833 23.088 39.265 23.304 ;
     RECT  39.121 58.368 39.301 58.392 ;
     RECT  39.193 2.784 39.308 5.496 ;
     RECT  38.761 26.112 39.337 27.336 ;
     RECT  39.161 61.44 39.349 61.512 ;
     RECT  39.301 58.08 39.445 58.392 ;
     RECT  39.193 10.704 39.517 10.728 ;
     RECT  39.445 12.336 39.517 12.36 ;
     RECT  39.452 24.384 39.553 24.408 ;
     RECT  39.553 24.384 39.589 24.696 ;
     RECT  39.337 26.112 39.589 27.96 ;
     RECT  39.121 56.4 39.589 56.52 ;
     RECT  39.589 56.4 39.596 56.76 ;
     RECT  39.445 58.08 39.596 59.208 ;
     RECT  39.445 14.208 39.685 14.232 ;
     RECT  38.837 40.704 39.805 41.16 ;
     RECT  39.589 24.384 39.869 27.96 ;
     RECT  39.697 29.04 39.869 29.064 ;
     RECT  37.973 30.432 39.884 30.456 ;
     RECT  39.265 22.512 39.925 23.304 ;
     RECT  39.869 24.384 39.925 29.064 ;
     RECT  39.884 30.432 39.925 30.792 ;
     RECT  39.517 10.704 39.949 12.36 ;
     RECT  38.867 19.776 39.949 19.8 ;
     RECT  38.693 32.304 39.949 32.472 ;
     RECT  39.301 18.24 39.98 18.264 ;
     RECT  39.949 19.488 39.98 19.8 ;
     RECT  39.661 44.448 39.985 45 ;
     RECT  39.98 18.24 39.993 19.8 ;
     RECT  38.867 20.88 39.993 21.528 ;
     RECT  39.993 18.24 40.057 21.528 ;
     RECT  39.985 44.448 40.069 45.72 ;
     RECT  39.805 40.704 40.093 41.208 ;
     RECT  39.308 2.784 40.208 5.736 ;
     RECT  39.949 7.344 40.208 7.368 ;
     RECT  39.949 10.176 40.208 12.36 ;
     RECT  39.685 14.208 40.208 15.048 ;
     RECT  39.481 16.272 40.208 16.392 ;
     RECT  40.057 18.144 40.208 21.528 ;
     RECT  39.925 22.512 40.208 30.792 ;
     RECT  39.949 31.776 40.208 32.472 ;
     RECT  38.341 35.424 40.208 35.448 ;
     RECT  38.977 36.576 40.208 39.24 ;
     RECT  40.093 40.704 40.208 41.448 ;
     RECT  40.069 43.872 40.208 45.72 ;
     RECT  40.021 46.752 40.208 46.776 ;
     RECT  39.197 47.952 40.208 48.36 ;
     RECT  38.837 49.632 40.208 50.712 ;
     RECT  39.596 56.4 40.208 59.208 ;
     RECT  39.349 61.44 40.208 62.04 ;
     RECT  40.208 2.148 40.312 62.652 ;
     RECT  40.312 2.418 40.504 62.382 ;
     RECT  40.504 9.12 40.529 11.784 ;
     RECT  40.504 26.544 40.565 27.912 ;
     RECT  40.565 26.592 40.601 27.912 ;
     RECT  40.601 26.592 40.637 27.672 ;
     RECT  40.504 56.448 40.673 58.152 ;
     RECT  40.504 25.296 40.709 25.464 ;
     RECT  40.504 3.408 40.889 5.208 ;
     RECT  40.504 30.432 40.925 33.672 ;
     RECT  40.529 9.12 41.069 10.92 ;
     RECT  41.069 10.176 41.105 10.92 ;
     RECT  40.504 34.656 41.105 39.48 ;
     RECT  40.504 29.04 41.249 29.4 ;
     RECT  40.504 18.144 41.285 21.528 ;
     RECT  41.105 34.656 41.315 39.24 ;
     RECT  41.315 34.656 41.356 38.808 ;
     RECT  40.709 25.44 41.357 25.464 ;
     RECT  40.925 30.816 41.465 33.672 ;
     RECT  40.504 6.384 41.533 7.512 ;
     RECT  41.105 10.896 41.533 10.92 ;
     RECT  40.504 16.272 41.533 16.392 ;
     RECT  41.356 34.656 41.537 37.656 ;
     RECT  40.504 13.344 41.569 13.368 ;
     RECT  41.533 10.896 41.573 11.4 ;
     RECT  41.285 18.192 41.573 21.528 ;
     RECT  41.573 18.24 41.605 21.528 ;
     RECT  40.504 41.04 41.713 42.072 ;
     RECT  41.533 15.504 41.717 16.392 ;
     RECT  40.504 50.592 41.749 51.288 ;
     RECT  40.889 3.408 41.753 5.064 ;
     RECT  41.713 41.04 41.753 42.36 ;
     RECT  41.753 3.408 41.821 4.44 ;
     RECT  41.537 34.992 41.825 37.656 ;
     RECT  41.569 12.528 41.861 13.368 ;
     RECT  41.749 49.008 41.891 51.288 ;
     RECT  40.504 45.696 41.893 45.72 ;
     RECT  41.533 6.24 41.929 7.512 ;
     RECT  41.465 30.864 41.929 33.672 ;
     RECT  41.861 13.344 41.933 13.368 ;
     RECT  41.825 34.992 41.933 36.456 ;
     RECT  41.785 54.144 41.965 54.168 ;
     RECT  41.929 6.24 41.969 8.088 ;
     RECT  40.637 26.592 41.969 27.192 ;
     RECT  41.821 3.168 41.989 4.44 ;
     RECT  41.929 44.208 42.001 44.232 ;
     RECT  41.969 6.24 42.037 7.08 ;
     RECT  41.965 53.328 42.073 54.168 ;
     RECT  41.989 2.832 42.077 4.44 ;
     RECT  41.891 49.728 42.145 51.288 ;
     RECT  40.673 56.448 42.145 57.96 ;
     RECT  42.073 59.088 42.145 59.112 ;
     RECT  42.145 49.728 42.253 51.336 ;
     RECT  42.073 52.848 42.253 54.168 ;
     RECT  41.929 30.864 42.257 33.816 ;
     RECT  41.893 45.696 42.289 45.768 ;
     RECT  41.825 37.44 42.325 37.656 ;
     RECT  41.356 38.784 42.325 38.808 ;
     RECT  41.933 35.136 42.365 36.456 ;
     RECT  41.845 47.856 42.397 47.88 ;
     RECT  41.753 41.04 42.469 41.16 ;
     RECT  42.289 45.504 42.469 45.768 ;
     RECT  42.397 47.856 42.469 48.024 ;
     RECT  42.253 49.728 42.469 54.168 ;
     RECT  42.325 37.44 42.473 38.808 ;
     RECT  41.605 18.24 42.509 21.672 ;
     RECT  42.365 35.136 42.515 35.16 ;
     RECT  42.145 56.448 42.541 59.112 ;
     RECT  40.504 61.44 42.541 61.608 ;
     RECT  42.469 45.504 42.577 46.056 ;
     RECT  42.509 18.24 42.613 21.576 ;
     RECT  42.577 45.504 42.613 46.824 ;
     RECT  42.469 47.856 42.613 48.072 ;
     RECT  42.473 37.44 42.617 38.184 ;
     RECT  41.717 16.272 42.649 16.392 ;
     RECT  42.613 17.616 42.649 21.576 ;
     RECT  42.649 16.272 42.653 21.576 ;
     RECT  42.541 56.448 42.709 59.16 ;
     RECT  41.969 8.064 42.721 8.088 ;
     RECT  41.069 9.12 42.721 9.144 ;
     RECT  42.001 44.16 42.721 44.232 ;
     RECT  42.613 45.504 42.721 48.072 ;
     RECT  42.721 8.064 42.757 9.144 ;
     RECT  42.365 36.432 42.797 36.456 ;
     RECT  42.757 8.064 42.841 9.24 ;
     RECT  42.469 40.368 42.865 41.16 ;
     RECT  41.753 42.336 42.865 42.36 ;
     RECT  42.469 49.728 42.865 54.216 ;
     RECT  42.649 27.888 42.869 27.912 ;
     RECT  42.865 49.728 42.869 54.6 ;
     RECT  41.249 29.04 42.901 29.352 ;
     RECT  42.721 44.16 42.901 48.072 ;
     RECT  42.901 43.92 42.905 48.072 ;
     RECT  42.869 51.264 42.937 54.6 ;
     RECT  42.865 40.368 42.947 42.36 ;
     RECT  42.947 40.368 42.973 42.168 ;
     RECT  42.905 45.696 42.977 48.072 ;
     RECT  40.504 23.04 43.009 23.064 ;
     RECT  40.504 24.096 43.009 24.12 ;
     RECT  42.905 43.92 43.049 43.944 ;
     RECT  42.709 56.448 43.081 59.784 ;
     RECT  42.541 61.248 43.081 61.608 ;
     RECT  42.977 47.856 43.085 48.072 ;
     RECT  42.077 3.024 43.189 4.44 ;
     RECT  43.081 56.448 43.193 61.608 ;
     RECT  42.841 9.072 43.225 9.24 ;
     RECT  42.617 37.44 43.225 37.656 ;
     RECT  43.085 48.048 43.229 48.072 ;
     RECT  42.937 51.264 43.229 54.648 ;
     RECT  43.009 23.04 43.233 24.12 ;
     RECT  42.973 39.888 43.265 42.168 ;
     RECT  43.193 57.936 43.265 61.608 ;
     RECT  43.265 39.888 43.297 41.064 ;
     RECT  43.233 22.656 43.333 24.12 ;
     RECT  43.117 25.584 43.333 25.608 ;
     RECT  41.969 26.592 43.333 26.616 ;
     RECT  42.653 18.816 43.337 21.576 ;
     RECT  42.901 34.992 43.337 35.016 ;
     RECT  42.977 45.696 43.337 46.824 ;
     RECT  42.037 5.616 43.373 7.08 ;
     RECT  43.193 56.448 43.373 56.712 ;
     RECT  43.333 22.656 43.379 26.904 ;
     RECT  43.379 22.656 43.42 24.792 ;
     RECT  41.573 11.376 43.436 11.4 ;
     RECT  43.229 51.264 43.445 51.768 ;
     RECT  43.436 11.04 43.477 11.4 ;
     RECT  42.653 16.272 43.477 17.736 ;
     RECT  43.477 15.984 43.481 17.736 ;
     RECT  43.445 51.264 43.481 51.288 ;
     RECT  43.189 3.024 43.513 4.632 ;
     RECT  43.373 5.616 43.513 6.936 ;
     RECT  43.373 56.496 43.517 56.712 ;
     RECT  43.477 10.944 43.523 11.4 ;
     RECT  42.901 28.512 43.621 29.352 ;
     RECT  42.257 30.864 43.657 33.672 ;
     RECT  43.297 39.408 43.657 41.064 ;
     RECT  42.841 8.064 43.661 8.088 ;
     RECT  43.229 52.896 43.661 54.648 ;
     RECT  43.513 3.024 43.715 6.936 ;
     RECT  43.657 38.784 43.733 41.064 ;
     RECT  43.337 18.816 43.769 21.528 ;
     RECT  43.42 22.656 43.769 24.552 ;
     RECT  43.225 36.528 43.801 37.656 ;
     RECT  43.337 45.696 43.841 45.768 ;
     RECT  43.661 54.096 43.861 54.648 ;
     RECT  43.801 36.288 43.873 37.656 ;
     RECT  43.225 9.072 43.877 9.912 ;
     RECT  43.337 46.8 43.877 46.824 ;
     RECT  43.265 57.936 43.907 61.464 ;
     RECT  43.715 3.648 43.913 6.936 ;
     RECT  43.877 9.072 43.913 9.144 ;
     RECT  43.733 38.784 43.913 40.392 ;
     RECT  43.661 52.896 43.913 52.92 ;
     RECT  43.907 58.512 43.913 61.464 ;
     RECT  43.441 62.544 43.913 62.568 ;
     RECT  43.769 24.096 43.949 24.552 ;
     RECT  43.621 28.512 44.053 29.688 ;
     RECT  43.657 30.864 44.053 34.248 ;
     RECT  43.481 17.472 44.057 17.736 ;
     RECT  43.873 36.24 44.057 37.656 ;
     RECT  44.057 36.24 44.093 36.648 ;
     RECT  43.841 45.696 44.108 45.72 ;
     RECT  44.108 45.552 44.165 45.72 ;
     RECT  44.165 45.552 44.195 45.576 ;
     RECT  44.053 28.512 44.201 34.248 ;
     RECT  44.201 29.04 44.237 34.248 ;
     RECT  43.513 14.784 44.269 14.808 ;
     RECT  43.949 24.24 44.273 24.552 ;
     RECT  43.913 58.512 44.273 61.416 ;
     RECT  44.269 13.92 44.293 14.808 ;
     RECT  43.481 15.984 44.293 16.488 ;
     RECT  43.913 3.888 44.309 6.936 ;
     RECT  43.265 42.144 44.341 42.168 ;
     RECT  43.441 12.528 44.377 12.552 ;
     RECT  44.057 17.664 44.377 17.736 ;
     RECT  44.309 6.624 44.381 6.936 ;
     RECT  42.869 49.728 44.449 49.848 ;
     RECT  44.093 36.24 44.453 36.6 ;
     RECT  43.517 56.688 44.485 56.712 ;
     RECT  44.377 11.952 44.489 12.552 ;
     RECT  43.769 19.92 44.489 21.528 ;
     RECT  44.293 13.92 44.521 16.488 ;
     RECT  44.273 58.512 44.524 60.792 ;
     RECT  43.379 26.064 44.525 26.904 ;
     RECT  44.485 56.688 44.525 57.048 ;
     RECT  43.523 10.944 44.593 10.968 ;
     RECT  44.341 41.952 44.597 42.168 ;
     RECT  44.449 48.96 44.665 49.848 ;
     RECT  44.665 48.96 44.701 50.616 ;
     RECT  43.913 40.368 44.737 40.392 ;
     RECT  44.237 34.224 44.809 34.248 ;
     RECT  44.377 17.664 44.989 17.784 ;
     RECT  43.769 18.816 44.989 18.84 ;
     RECT  44.737 40.368 44.989 40.92 ;
     RECT  44.597 41.952 44.989 41.976 ;
     RECT  44.701 48.96 45.025 50.712 ;
     RECT  44.453 36.24 45.133 36.552 ;
     RECT  43.913 38.784 45.133 39.336 ;
     RECT  44.989 40.368 45.133 41.976 ;
     RECT  43.913 9.072 45.205 9.096 ;
     RECT  43.861 54.096 45.205 55.464 ;
     RECT  45.205 9.072 45.241 9.288 ;
     RECT  44.593 10.656 45.241 10.968 ;
     RECT  44.521 12.624 45.241 16.488 ;
     RECT  44.989 17.664 45.241 18.84 ;
     RECT  44.525 26.592 45.241 26.904 ;
     RECT  44.237 29.04 45.241 32.616 ;
     RECT  44.732 43.152 45.385 43.176 ;
     RECT  45.349 47.04 45.385 47.064 ;
     RECT  45.205 53.328 45.493 55.464 ;
     RECT  44.525 57.024 45.493 57.048 ;
     RECT  44.809 34.224 45.529 34.392 ;
     RECT  45.241 12.624 45.565 18.84 ;
     RECT  45.241 26.592 45.565 32.616 ;
     RECT  45.529 33.888 45.565 34.392 ;
     RECT  45.565 26.064 45.601 34.392 ;
     RECT  45.133 35.856 45.601 36.552 ;
     RECT  44.057 37.632 45.601 37.656 ;
     RECT  45.493 53.328 45.601 57.048 ;
     RECT  44.524 58.512 45.601 60.312 ;
     RECT  44.309 3.888 45.608 5.064 ;
     RECT  44.381 6.624 45.608 6.648 ;
     RECT  45.241 9.072 45.608 10.968 ;
     RECT  45.565 11.952 45.608 18.84 ;
     RECT  44.489 20.352 45.608 21.528 ;
     RECT  43.769 22.656 45.608 22.68 ;
     RECT  44.273 24.528 45.608 24.552 ;
     RECT  45.601 26.064 45.608 37.656 ;
     RECT  45.133 38.784 45.608 41.976 ;
     RECT  45.385 43.152 45.608 43.32 ;
     RECT  44.773 44.448 45.608 44.472 ;
     RECT  45.169 45.696 45.608 45.72 ;
     RECT  45.385 47.04 45.608 47.16 ;
     RECT  45.025 48.96 45.608 51.384 ;
     RECT  45.601 53.328 45.608 60.312 ;
     RECT  45.608 2.148 45.712 62.652 ;
     RECT  45.712 2.418 45.904 62.382 ;
     RECT  45.904 15.312 45.965 15.336 ;
     RECT  45.904 53.088 46.001 56.376 ;
     RECT  45.904 9.264 46.037 10.968 ;
     RECT  45.904 31.92 46.037 37.896 ;
     RECT  46.037 31.92 46.067 34.728 ;
     RECT  46.037 9.264 46.109 9.864 ;
     RECT  45.904 45.408 46.145 45.48 ;
     RECT  46.001 53.328 46.145 56.376 ;
     RECT  45.904 57.6 46.163 57.624 ;
     RECT  46.109 9.264 46.181 9.816 ;
     RECT  45.904 4.512 46.211 6.888 ;
     RECT  46.037 10.944 46.211 10.968 ;
     RECT  46.037 36.048 46.217 37.896 ;
     RECT  46.145 53.616 46.253 56.376 ;
     RECT  46.067 31.92 46.289 34.248 ;
     RECT  46.211 4.512 46.307 5.736 ;
     RECT  46.211 6.864 46.325 6.888 ;
     RECT  46.253 53.616 46.361 53.64 ;
     RECT  45.904 49.536 46.397 51.816 ;
     RECT  46.289 33.888 46.469 34.248 ;
     RECT  46.181 9.264 46.541 9.288 ;
     RECT  45.904 30.912 46.605 30.936 ;
     RECT  46.289 31.92 46.636 32.568 ;
     RECT  46.397 49.536 46.684 50.856 ;
     RECT  46.307 4.512 46.721 5.112 ;
     RECT  45.904 29.328 46.757 29.496 ;
     RECT  46.253 54.624 46.757 56.376 ;
     RECT  45.904 18.384 46.787 23.304 ;
     RECT  45.904 11.952 46.793 13.32 ;
     RECT  46.787 18.384 46.829 19.608 ;
     RECT  46.787 20.784 46.865 23.304 ;
     RECT  45.904 47.04 46.897 48.408 ;
     RECT  46.793 12.528 46.937 13.32 ;
     RECT  46.865 20.832 46.937 23.304 ;
     RECT  46.757 56.352 46.937 56.376 ;
     RECT  46.217 36.672 47.027 37.896 ;
     RECT  47.027 36.768 47.077 37.896 ;
     RECT  45.904 39.312 47.077 39.336 ;
     RECT  46.829 18.384 47.153 19.368 ;
     RECT  45.904 16.56 47.257 17.4 ;
     RECT  46.897 46.752 47.333 48.408 ;
     RECT  46.937 20.928 47.369 23.304 ;
     RECT  46.636 32.064 47.369 32.568 ;
     RECT  45.904 25.056 47.405 27.912 ;
     RECT  47.257 16.56 47.437 18.216 ;
     RECT  46.757 29.472 47.437 29.496 ;
     RECT  46.145 45.456 47.461 45.48 ;
     RECT  47.333 46.752 47.461 47.16 ;
     RECT  47.276 15.072 47.509 15.096 ;
     RECT  47.437 43.872 47.519 43.896 ;
     RECT  47.437 29.472 47.545 29.928 ;
     RECT  45.904 60 47.564 60.024 ;
     RECT  47.077 36.768 47.585 39.336 ;
     RECT  45.904 42.72 47.603 42.744 ;
     RECT  46.757 54.624 47.617 55.32 ;
     RECT  47.564 59.808 47.651 60.024 ;
     RECT  47.437 28.128 47.653 28.248 ;
     RECT  47.461 45.456 47.692 47.16 ;
     RECT  47.692 46.512 47.693 47.16 ;
     RECT  47.405 25.056 47.701 27.096 ;
     RECT  47.585 37.056 47.729 39.336 ;
     RECT  47.557 41.568 47.729 41.592 ;
     RECT  46.469 34.224 47.756 34.248 ;
     RECT  47.519 43.872 47.761 44.328 ;
     RECT  47.729 37.584 47.795 39.336 ;
     RECT  47.795 38.112 47.801 39.336 ;
     RECT  47.545 9.936 47.833 9.96 ;
     RECT  47.509 14.976 47.833 15.096 ;
     RECT  47.437 16.32 47.833 18.216 ;
     RECT  47.701 24.528 47.837 27.096 ;
     RECT  47.801 39.312 47.837 39.336 ;
     RECT  47.692 45.456 47.845 45.48 ;
     RECT  47.369 20.928 47.873 22.776 ;
     RECT  47.617 54.144 47.873 55.32 ;
     RECT  47.833 14.976 47.905 18.216 ;
     RECT  46.721 4.656 47.909 4.68 ;
     RECT  47.153 19.344 47.909 19.368 ;
     RECT  47.756 33.552 47.909 34.248 ;
     RECT  47.845 45.408 47.932 45.48 ;
     RECT  47.837 25.056 47.939 27.096 ;
     RECT  47.369 32.304 47.941 32.568 ;
     RECT  47.605 61.008 47.945 61.032 ;
     RECT  47.653 28.128 47.981 28.44 ;
     RECT  47.932 45.456 47.981 45.48 ;
     RECT  47.905 14.4 48.017 18.216 ;
     RECT  47.761 42.768 48.017 44.328 ;
     RECT  47.333 48.384 48.053 48.408 ;
     RECT  47.833 9.936 48.085 10.68 ;
     RECT  48.013 52.464 48.085 52.488 ;
     RECT  48.017 14.4 48.125 17.16 ;
     RECT  47.873 54.144 48.157 54.168 ;
     RECT  48.188 4.608 48.229 4.632 ;
     RECT  46.684 49.824 48.229 50.856 ;
     RECT  47.873 55.296 48.229 55.32 ;
     RECT  48.229 49.584 48.265 50.856 ;
     RECT  48.085 51.888 48.265 52.488 ;
     RECT  47.981 28.272 48.269 28.44 ;
     RECT  48.157 54.096 48.269 54.168 ;
     RECT  48.229 3.936 48.275 4.632 ;
     RECT  48.229 55.296 48.275 55.896 ;
     RECT  46.937 12.528 48.409 12.744 ;
     RECT  48.125 16.608 48.413 17.16 ;
     RECT  48.125 14.4 48.449 15.384 ;
     RECT  48.413 17.136 48.449 17.16 ;
     RECT  47.873 20.928 48.449 22.632 ;
     RECT  47.939 25.056 48.449 26.904 ;
     RECT  48.085 9.936 48.517 10.872 ;
     RECT  48.017 43.296 48.521 44.328 ;
     RECT  48.269 54.096 48.521 54.12 ;
     RECT  48.517 9.84 48.625 10.872 ;
     RECT  47.693 46.512 48.629 46.536 ;
     RECT  48.409 12.528 48.661 12.792 ;
     RECT  48.449 20.928 48.665 22.056 ;
     RECT  48.449 14.4 48.669 15 ;
     RECT  47.545 29.472 48.701 30.12 ;
     RECT  48.265 49.584 48.733 52.488 ;
     RECT  48.733 49.008 48.805 52.488 ;
     RECT  47.941 32.304 48.841 33.384 ;
     RECT  48.805 34.8 48.877 34.824 ;
     RECT  48.373 23.808 48.908 23.832 ;
     RECT  48.841 32.016 48.913 33.384 ;
     RECT  48.449 25.056 48.953 26.808 ;
     RECT  48.521 43.296 48.985 44.136 ;
     RECT  48.908 23.808 48.995 24.072 ;
     RECT  48.877 34.8 49.021 34.92 ;
     RECT  48.805 49.008 49.021 52.824 ;
     RECT  49.021 34.8 49.129 35.496 ;
     RECT  48.275 55.872 49.129 55.896 ;
     RECT  49.021 48.288 49.139 52.824 ;
     RECT  49.1 45.312 49.187 45.336 ;
     RECT  48.701 29.472 49.205 29.496 ;
     RECT  48.661 12.528 49.345 13.128 ;
     RECT  48.669 14.208 49.345 15 ;
     RECT  47.801 38.112 49.381 38.136 ;
     RECT  48.913 46.752 49.453 46.776 ;
     RECT  49.129 55.872 49.453 55.944 ;
     RECT  48.625 9.648 49.457 10.872 ;
     RECT  49.345 12.528 49.457 15 ;
     RECT  49.237 45.504 49.493 45.528 ;
     RECT  49.457 9.648 49.571 10.824 ;
     RECT  49.453 54.96 49.633 55.944 ;
     RECT  49.457 14.976 49.637 15 ;
     RECT  49.628 41.28 49.669 41.304 ;
     RECT  49.453 46.752 49.669 47.112 ;
     RECT  48.913 31.344 49.705 33.384 ;
     RECT  48.733 39.888 49.715 39.912 ;
     RECT  49.669 41.28 49.715 41.976 ;
     RECT  49.139 48.768 49.741 52.824 ;
     RECT  49.705 31.248 49.745 33.384 ;
     RECT  49.745 31.248 49.777 33.048 ;
     RECT  49.571 9.84 49.781 10.824 ;
     RECT  48.269 28.416 49.813 28.44 ;
     RECT  49.741 48.768 49.817 53.544 ;
     RECT  49.129 34.464 49.853 35.736 ;
     RECT  49.777 30.864 49.889 33.048 ;
     RECT  49.889 31.248 49.961 33.048 ;
     RECT  49.561 24.48 49.993 24.504 ;
     RECT  48.953 25.728 49.993 26.808 ;
     RECT  49.715 41.952 50.101 41.976 ;
     RECT  48.985 43.104 50.101 44.136 ;
     RECT  49.669 46.224 50.101 47.112 ;
     RECT  49.817 48.768 50.101 49.608 ;
     RECT  48.665 20.928 50.341 21.672 ;
     RECT  49.457 12.528 50.437 13.896 ;
     RECT  49.853 35.616 50.497 35.736 ;
     RECT  49.817 50.736 50.581 53.544 ;
     RECT  49.633 54.96 50.581 56.376 ;
     RECT  48.481 18.24 50.677 18.264 ;
     RECT  49.813 27.936 50.725 28.44 ;
     RECT  50.389 63.84 50.771 63.864 ;
     RECT  50.437 12.336 50.869 14.232 ;
     RECT  50.857 15.312 50.869 15.336 ;
     RECT  48.275 3.936 51.008 3.96 ;
     RECT  49.781 9.84 51.008 10.152 ;
     RECT  50.869 12.336 51.008 15.336 ;
     RECT  50.677 17.184 51.008 17.208 ;
     RECT  50.677 18.24 51.008 18.504 ;
     RECT  50.341 20.16 51.008 21.672 ;
     RECT  49.993 24.48 51.008 26.808 ;
     RECT  50.725 27.936 51.008 29.208 ;
     RECT  49.961 31.248 51.008 31.272 ;
     RECT  49.961 32.304 51.008 33.048 ;
     RECT  49.853 34.464 51.008 34.488 ;
     RECT  50.497 35.616 51.008 35.88 ;
     RECT  50.773 36.912 51.008 36.936 ;
     RECT  49.381 38.112 51.008 38.184 ;
     RECT  50.101 41.952 51.008 44.136 ;
     RECT  50.101 46.224 51.008 49.608 ;
     RECT  50.581 50.736 51.008 56.376 ;
     RECT  48.625 60.384 51.008 60.408 ;
     RECT  51.008 2.148 51.112 62.652 ;
     RECT  51.112 2.418 51.304 62.382 ;
     RECT  51.304 11.424 51.365 16.824 ;
     RECT  51.304 52.032 51.473 52.056 ;
     RECT  51.304 27.984 51.509 28.536 ;
     RECT  51.304 32.448 51.545 33.048 ;
     RECT  51.304 29.52 51.581 29.544 ;
     RECT  51.304 22.704 51.587 24.504 ;
     RECT  51.304 18.384 51.617 18.504 ;
     RECT  51.304 20.16 51.635 20.952 ;
     RECT  51.587 22.752 51.653 24.504 ;
     RECT  51.304 44.064 51.653 44.904 ;
     RECT  51.617 18.384 51.681 18.408 ;
     RECT  51.653 22.752 51.683 24.312 ;
     RECT  51.365 14.208 51.689 16.824 ;
     RECT  51.635 20.16 51.689 20.184 ;
     RECT  51.365 11.424 51.731 12.792 ;
     RECT  51.304 26.016 51.761 26.808 ;
     RECT  51.509 28.176 51.761 28.536 ;
     RECT  51.304 8.688 51.797 10.296 ;
     RECT  51.304 56.208 51.869 56.376 ;
     RECT  51.761 28.224 51.941 28.536 ;
     RECT  51.304 34.08 52.156 34.488 ;
     RECT  51.731 11.424 52.193 11.976 ;
     RECT  51.304 3.168 52.265 3.432 ;
     RECT  51.941 28.512 52.265 28.536 ;
     RECT  51.797 10.08 52.297 10.296 ;
     RECT  52.193 11.424 52.297 11.736 ;
     RECT  51.304 46.752 52.297 48.792 ;
     RECT  51.797 8.688 52.301 9.096 ;
     RECT  52.156 34.464 52.373 34.488 ;
     RECT  52.297 46.752 52.453 48.936 ;
     RECT  51.653 44.88 52.499 44.904 ;
     RECT  51.683 22.8 52.553 23.64 ;
     RECT  52.453 45.936 52.553 48.936 ;
     RECT  51.304 41.952 52.589 42.552 ;
     RECT  52.297 10.08 52.661 11.736 ;
     RECT  52.453 43.872 52.729 43.896 ;
     RECT  51.689 14.784 52.768 16.824 ;
     RECT  52.661 10.08 52.769 10.92 ;
     RECT  51.761 26.208 52.769 26.808 ;
     RECT  52.553 46.32 52.769 48.936 ;
     RECT  52.729 43.872 52.805 44.472 ;
     RECT  51.545 32.448 52.837 32.904 ;
     RECT  52.769 10.08 52.841 10.104 ;
     RECT  52.769 46.464 52.885 48.936 ;
     RECT  52.589 42.528 53.017 42.552 ;
     RECT  53.017 42.528 53.021 42.744 ;
     RECT  52.301 8.688 53.324 8.712 ;
     RECT  52.265 3.168 53.341 3.192 ;
     RECT  53.324 8.4 53.341 8.712 ;
     RECT  53.341 2.784 53.345 3.192 ;
     RECT  53.341 8.4 53.411 8.904 ;
     RECT  53.372 13.584 53.413 13.608 ;
     RECT  52.768 14.736 53.413 16.824 ;
     RECT  53.413 13.584 53.417 16.824 ;
     RECT  53.417 13.584 53.459 14.28 ;
     RECT  52.805 44.064 53.489 44.472 ;
     RECT  53.365 6.816 53.741 6.84 ;
     RECT  53.417 15.84 53.891 16.824 ;
     RECT  54.025 22.176 54.131 22.2 ;
     RECT  52.769 26.784 54.277 26.808 ;
     RECT  54.277 26.256 54.317 26.808 ;
     RECT  54.085 23.52 54.428 23.544 ;
     RECT  54.241 11.712 54.493 11.736 ;
     RECT  54.428 23.52 54.515 24.504 ;
     RECT  53.021 42.72 54.517 42.744 ;
     RECT  54.493 11.712 54.529 11.784 ;
     RECT  54.517 42.72 54.569 43.176 ;
     RECT  54.529 11.472 54.601 11.784 ;
     RECT  52.885 46.464 54.601 49.032 ;
     RECT  54.569 43.152 54.604 43.176 ;
     RECT  53.485 53.568 54.611 53.592 ;
     RECT  51.869 56.208 54.661 56.232 ;
     RECT  54.601 11.472 54.673 11.976 ;
     RECT  54.661 56.208 54.707 56.76 ;
     RECT  54.133 58.704 54.707 58.728 ;
     RECT  53.411 8.88 54.745 8.904 ;
     RECT  54.673 11.424 54.745 11.976 ;
     RECT  54.601 45.504 54.749 49.032 ;
     RECT  54.749 48.384 54.821 49.032 ;
     RECT  54.745 8.88 54.829 9.48 ;
     RECT  54.745 11.424 54.829 12.456 ;
     RECT  52.837 31.968 54.851 32.904 ;
     RECT  54.829 11.424 54.857 11.736 ;
     RECT  53.489 44.448 54.889 44.472 ;
     RECT  54.749 45.504 54.889 47.112 ;
     RECT  54.857 11.472 54.893 11.736 ;
     RECT  54.515 23.52 54.893 23.688 ;
     RECT  54.893 11.472 55.001 11.688 ;
     RECT  54.853 13.008 55.109 13.032 ;
     RECT  54.851 31.968 55.187 32.472 ;
     RECT  53.891 16.752 55.213 16.824 ;
     RECT  54.829 8.88 55.237 8.904 ;
     RECT  55.213 16.752 55.253 16.92 ;
     RECT  55.237 7.968 55.283 8.904 ;
     RECT  54.889 44.448 55.433 47.112 ;
     RECT  54.317 26.256 55.933 26.28 ;
     RECT  55.001 11.664 56.293 11.688 ;
     RECT  53.345 2.784 56.408 2.808 ;
     RECT  55.283 7.968 56.408 7.992 ;
     RECT  56.293 11.664 56.408 12.552 ;
     RECT  53.459 14.208 56.408 14.28 ;
     RECT  55.253 16.8 56.408 16.92 ;
     RECT  54.949 20.64 56.408 20.664 ;
     RECT  54.893 23.664 56.408 23.688 ;
     RECT  55.933 26.256 56.408 26.568 ;
     RECT  56.365 29.76 56.408 29.784 ;
     RECT  55.187 31.968 56.408 31.992 ;
     RECT  54.805 35.328 56.408 35.352 ;
     RECT  55.433 44.448 56.408 46.872 ;
     RECT  54.821 48.384 56.408 48.936 ;
     RECT  54.565 54.576 56.408 54.6 ;
     RECT  54.707 56.736 56.408 56.76 ;
     RECT  56.408 2.148 56.512 62.652 ;
     RECT  56.512 2.418 56.704 62.382 ;
     RECT  56.704 11.664 56.729 12.792 ;
     RECT  56.704 7.968 56.801 7.992 ;
     RECT  56.704 26.544 56.819 26.568 ;
     RECT  56.704 28.656 56.819 28.68 ;
     RECT  56.704 29.76 56.963 29.784 ;
     RECT  56.704 30.816 56.963 30.84 ;
     RECT  56.704 31.968 56.963 31.992 ;
     RECT  56.704 16.8 57.155 16.824 ;
     RECT  56.704 20.544 57.169 20.568 ;
     RECT  56.704 45.696 57.197 45.72 ;
     RECT  56.704 48.384 57.521 48.456 ;
     RECT  57.692 36.48 57.779 36.504 ;
     RECT  56.729 11.952 57.781 12.792 ;
     RECT  56.704 23.664 57.781 23.688 ;
     RECT  56.704 49.44 57.781 49.464 ;
     RECT  56.704 54.576 57.781 54.6 ;
     RECT  57.761 21.648 57.788 21.672 ;
     RECT  57.74 6.24 57.827 6.264 ;
     RECT  57.781 23.376 57.827 23.688 ;
     RECT  57.781 49.44 57.827 50.04 ;
     RECT  57.74 52.944 57.827 52.968 ;
     RECT  57.781 54.384 57.827 54.6 ;
     RECT  57.788 21.12 57.845 21.672 ;
     RECT  56.704 18.192 57.875 18.456 ;
     RECT  57.845 21.12 57.875 21.144 ;
     RECT  57.781 10.992 57.881 12.792 ;
     RECT  57.98 43.296 58.067 43.32 ;
     RECT  57.697 14.64 58.117 14.664 ;
     RECT  57.881 12.384 58.163 12.792 ;
     RECT  58.117 14.208 58.163 14.664 ;
     RECT  56.704 46.848 58.669 46.872 ;
     RECT  58.669 30.768 58.693 30.792 ;
     RECT  58.669 46.752 58.709 46.872 ;
     RECT  58.693 30.768 58.773 30.888 ;
     RECT  58.163 14.208 59.141 14.232 ;
     RECT  57.827 50.016 59.393 50.04 ;
     RECT  59.389 28.368 59.413 28.392 ;
     RECT  58.773 30.864 59.459 30.888 ;
     RECT  58.163 12.384 59.497 12.552 ;
     RECT  57.733 35.328 59.573 35.352 ;
     RECT  57.875 18.432 59.605 18.456 ;
     RECT  59.497 12.192 59.651 12.552 ;
     RECT  59.413 28.368 59.699 29.208 ;
     RECT  58.709 46.752 59.713 46.776 ;
     RECT  59.641 24.528 59.725 24.552 ;
     RECT  59.641 25.632 59.725 25.656 ;
     RECT  58.021 44.88 59.897 44.904 ;
     RECT  57.827 23.376 60.083 23.4 ;
     RECT  57.827 54.384 60.181 54.408 ;
     RECT  60.037 24.912 60.185 25.128 ;
     RECT  60.181 54.384 60.265 54.744 ;
     RECT  60.037 22.128 60.293 22.152 ;
     RECT  60.716 55.584 60.803 55.608 ;
     RECT  59.821 61.584 61.333 61.608 ;
     RECT  59.713 46.752 61.669 46.824 ;
     RECT  61.004 10.512 61.808 10.536 ;
     RECT  59.651 12.192 61.808 12.216 ;
     RECT  59.605 18.432 61.808 18.744 ;
     RECT  60.185 24.912 61.808 24.936 ;
     RECT  57.733 38.736 61.808 38.76 ;
     RECT  61.405 44.976 61.808 45 ;
     RECT  61.669 46.224 61.808 46.824 ;
     RECT  57.521 48.384 61.808 48.408 ;
     RECT  61.441 50.544 61.808 50.568 ;
     RECT  60.265 54.384 61.808 54.408 ;
     RECT  60.577 57.552 61.808 57.576 ;
     RECT  61.333 59.04 61.808 59.064 ;
     RECT  61.333 60.816 61.808 61.608 ;
     RECT  61.808 2.148 61.912 62.652 ;
     RECT  61.912 2.418 62.104 62.382 ;
     RECT  62.104 46.08 62.243 47.16 ;
     RECT  62.243 46.08 62.489 46.824 ;
     RECT  62.104 38.688 62.81 38.76 ;
     RECT  62.81 38.688 63.133 38.712 ;
     RECT  62.489 46.08 63.205 46.104 ;
     RECT  63.205 45.696 63.245 46.104 ;
     RECT  62.104 50.544 63.349 50.568 ;
     RECT  63.308 52.176 63.349 52.2 ;
     RECT  63.349 50.544 63.395 52.2 ;
     RECT  62.104 48.384 63.781 48.408 ;
     RECT  63.395 50.544 63.827 51.24 ;
     RECT  62.104 24.912 63.857 24.936 ;
     RECT  63.781 48.384 64.361 48.84 ;
     RECT  62.104 54.576 64.469 54.6 ;
     RECT  63.133 38.544 65.429 38.712 ;
     RECT  65.429 38.544 65.507 39.384 ;
     RECT  65.507 38.688 65.513 39.384 ;
     RECT  65.461 36.528 65.548 37.032 ;
     RECT  63.827 51.216 65.612 51.24 ;
     RECT  65.612 51.216 65.653 51.816 ;
     RECT  65.653 51.216 65.699 52.488 ;
     RECT  63.245 45.696 66.035 45.72 ;
     RECT  65.948 47.232 66.035 47.256 ;
     RECT  65.989 44.448 66.161 44.472 ;
     RECT  66.092 35.04 66.179 35.064 ;
     RECT  65.548 37.008 66.661 37.032 ;
     RECT  62.104 17.04 67.093 17.064 ;
     RECT  64.361 48.384 67.165 48.456 ;
     RECT  63.601 4.656 67.208 4.68 ;
     RECT  67.093 16.56 67.208 17.064 ;
     RECT  62.104 18.672 67.208 18.696 ;
     RECT  66.985 20.064 67.208 20.088 ;
     RECT  67.093 22.8 67.208 22.824 ;
     RECT  66.841 27.936 67.208 27.96 ;
     RECT  66.133 33.408 67.208 33.432 ;
     RECT  66.661 37.008 67.208 37.128 ;
     RECT  65.513 38.688 67.208 38.712 ;
     RECT  64.825 42.72 67.208 42.744 ;
     RECT  66.985 45.792 67.208 45.816 ;
     RECT  67.165 48.384 67.208 49.032 ;
     RECT  65.699 52.464 67.208 52.488 ;
     RECT  62.104 60.816 67.208 60.84 ;
     RECT  67.208 2.148 67.312 62.652 ;
     RECT  67.312 2.418 67.504 62.382 ;
     RECT  67.504 48.384 67.565 49.032 ;
     RECT  67.504 27.936 67.709 29.256 ;
     RECT  67.504 14.064 67.859 14.856 ;
     RECT  67.504 16.56 67.859 16.584 ;
     RECT  67.504 44.976 67.859 47.352 ;
     RECT  67.709 28.464 68.147 29.256 ;
     RECT  67.504 30.24 68.188 30.264 ;
     RECT  67.859 47.328 68.213 47.352 ;
     RECT  67.504 6.288 68.387 7.464 ;
     RECT  67.504 2.832 68.435 3.576 ;
     RECT  68.435 2.832 68.476 2.856 ;
     RECT  68.54 22.416 68.561 22.44 ;
     RECT  68.561 22.416 68.581 23.4 ;
     RECT  67.504 12.528 68.609 12.936 ;
     RECT  68.581 21.648 68.627 23.4 ;
     RECT  68.627 22.752 68.645 23.4 ;
     RECT  67.859 44.976 68.677 45 ;
     RECT  68.677 44.544 68.717 45 ;
     RECT  67.504 18.768 68.869 18.792 ;
     RECT  67.504 20.064 68.869 20.088 ;
     RECT  68.869 18.768 68.915 20.088 ;
     RECT  68.915 18.768 68.956 19.176 ;
     RECT  67.504 37.104 69.077 37.128 ;
     RECT  69.317 11.424 69.401 11.448 ;
     RECT  68.645 22.752 69.401 22.776 ;
     RECT  67.504 42.72 69.493 42.744 ;
     RECT  69.493 42.72 69.539 42.936 ;
     RECT  67.565 48.384 69.541 48.408 ;
     RECT  69.541 48.144 69.587 48.408 ;
     RECT  68.387 6.816 69.617 6.84 ;
     RECT  69.539 42.912 69.932 42.936 ;
     RECT  67.504 38.688 70.019 38.712 ;
     RECT  69.932 42.912 70.019 43.128 ;
     RECT  70.021 54.096 70.045 54.12 ;
     RECT  67.504 55.44 70.067 55.464 ;
     RECT  70.045 53.568 70.108 54.12 ;
     RECT  67.504 4.656 70.117 4.68 ;
     RECT  67.504 10.032 70.117 10.056 ;
     RECT  68.609 12.528 70.117 12.552 ;
     RECT  68.147 29.232 70.157 29.256 ;
     RECT  70.117 12.528 70.163 13.08 ;
     RECT  70.117 14.64 70.261 14.664 ;
     RECT  69.937 15.648 70.261 15.672 ;
     RECT  70.261 14.64 70.301 15.672 ;
     RECT  68.627 21.648 70.357 21.672 ;
     RECT  69.757 31.296 70.369 31.32 ;
     RECT  70.301 14.832 70.403 15.672 ;
     RECT  68.956 18.768 70.403 18.792 ;
     RECT  70.369 31.104 70.409 31.32 ;
     RECT  70.117 4.656 70.508 5.112 ;
     RECT  70.357 21.12 70.586 21.672 ;
     RECT  70.508 4.656 70.595 5.208 ;
     RECT  70.117 9.648 70.693 10.056 ;
     RECT  70.403 14.832 70.697 15.48 ;
     RECT  70.613 28.512 70.697 28.776 ;
     RECT  70.697 14.832 70.733 14.856 ;
     RECT  70.019 42.912 70.739 42.936 ;
     RECT  70.409 31.104 70.981 31.128 ;
     RECT  69.587 48.144 70.981 48.168 ;
     RECT  70.94 49.44 70.981 49.464 ;
     RECT  70.981 49.44 71.027 49.608 ;
     RECT  70.645 17.04 71.053 17.064 ;
     RECT  69.973 35.712 71.089 35.736 ;
     RECT  71.053 16.896 71.093 17.064 ;
     RECT  70.981 47.856 71.129 48.168 ;
     RECT  68.717 44.544 71.165 44.568 ;
     RECT  70.595 4.656 71.237 4.68 ;
     RECT  71.089 27.744 71.315 27.768 ;
     RECT  70.693 9.648 71.381 10.872 ;
     RECT  70.081 26.736 71.417 26.76 ;
     RECT  70.981 30.24 71.453 31.128 ;
     RECT  70.108 53.568 71.468 53.592 ;
     RECT  71.468 53.568 71.509 54.312 ;
     RECT  71.509 52.992 71.555 54.312 ;
     RECT  71.381 10.848 71.701 10.872 ;
     RECT  71.665 4.608 71.797 4.632 ;
     RECT  71.089 34.8 71.809 35.736 ;
     RECT  71.555 52.992 72.14 53.016 ;
     RECT  72.061 57.408 72.181 57.432 ;
     RECT  70.697 28.752 72.205 28.776 ;
     RECT  70.586 21.12 72.413 21.624 ;
     RECT  72.169 24.336 72.421 24.36 ;
     RECT  71.737 32.736 72.449 32.76 ;
     RECT  72.449 32.448 72.469 32.76 ;
     RECT  71.797 3.696 72.608 4.632 ;
     RECT  71.629 6.096 72.608 6.12 ;
     RECT  70.909 8.496 72.608 8.52 ;
     RECT  71.381 9.792 72.608 9.816 ;
     RECT  71.701 10.848 72.608 11.256 ;
     RECT  70.163 13.056 72.608 13.08 ;
     RECT  71.093 16.896 72.608 16.92 ;
     RECT  72.413 21.12 72.608 21.672 ;
     RECT  72.421 24.336 72.608 24.456 ;
     RECT  72.205 28.752 72.608 28.824 ;
     RECT  71.453 31.104 72.608 31.128 ;
     RECT  72.469 32.448 72.608 33.096 ;
     RECT  71.809 34.176 72.608 35.736 ;
     RECT  71.845 38.4 72.608 38.424 ;
     RECT  69.037 40.32 72.608 40.344 ;
     RECT  71.129 48.144 72.608 48.168 ;
     RECT  71.027 49.584 72.608 49.608 ;
     RECT  72.14 52.416 72.608 53.016 ;
     RECT  72.469 56.352 72.608 56.376 ;
     RECT  72.181 57.408 72.608 58.152 ;
     RECT  72.608 2.148 72.712 62.652 ;
     RECT  72.712 2.418 72.904 62.382 ;
     RECT  72.904 34.464 72.965 40.44 ;
     RECT  72.904 57.408 72.965 58.728 ;
     RECT  72.965 34.896 73.145 40.44 ;
     RECT  73.145 34.896 73.181 38.424 ;
     RECT  72.904 52.992 73.181 53.592 ;
     RECT  72.904 50.112 73.187 51.624 ;
     RECT  72.904 24.432 73.289 24.456 ;
     RECT  73.187 50.112 73.325 50.136 ;
     RECT  72.904 3.696 73.397 4.584 ;
     RECT  73.145 40.32 73.433 40.44 ;
     RECT  72.904 18.192 73.475 18.84 ;
     RECT  73.181 53.568 73.549 53.592 ;
     RECT  72.904 7.968 73.577 8.52 ;
     RECT  73.181 35.904 73.577 38.424 ;
     RECT  72.904 11.232 73.613 11.256 ;
     RECT  72.904 54.576 73.613 54.6 ;
     RECT  72.965 57.696 73.829 58.728 ;
     RECT  72.904 33.072 73.973 33.096 ;
     RECT  73.577 8.496 74.081 8.52 ;
     RECT  72.904 41.616 74.081 41.64 ;
     RECT  73.181 34.896 74.153 34.92 ;
     RECT  73.577 35.904 74.153 35.928 ;
     RECT  74.101 15.84 74.188 15.864 ;
     RECT  72.904 60 74.329 60.024 ;
     RECT  74.329 60 74.369 60.168 ;
     RECT  73.397 4.56 74.405 4.584 ;
     RECT  72.904 16.896 74.725 16.92 ;
     RECT  74.725 16.8 74.801 16.92 ;
     RECT  74.369 60.144 74.867 60.168 ;
     RECT  74.821 61.2 74.908 61.608 ;
     RECT  72.904 28.8 74.972 28.824 ;
     RECT  73.187 51.168 75.053 51.192 ;
     RECT  74.972 28.464 75.059 28.824 ;
     RECT  72.904 20.064 75.061 20.088 ;
     RECT  75.02 18.048 75.107 18.072 ;
     RECT  75.013 30.24 75.161 30.264 ;
     RECT  73.829 58.128 75.233 58.152 ;
     RECT  75.061 19.104 75.251 20.088 ;
     RECT  75.251 19.104 75.292 19.128 ;
     RECT  73.577 37.008 75.341 37.032 ;
     RECT  74.908 61.2 75.377 61.224 ;
     RECT  74.801 16.8 75.521 16.824 ;
     RECT  73.433 40.416 75.593 40.44 ;
     RECT  78.008 2.148 78.112 62.652 ;
     RECT  78.112 2.418 78.304 62.382 ;
     RECT  83.408 2.148 83.512 62.652 ;
     RECT  83.512 2.418 83.704 62.382 ;
     RECT  83.704 2.784 83.837 2.808 ;
     RECT  84.841 7.392 84.877 7.416 ;
     RECT  84.841 9.504 84.877 9.528 ;
     RECT  84.805 10.752 84.877 10.776 ;
     RECT  84.841 12.864 84.877 12.888 ;
     RECT  84.841 14.112 84.877 14.136 ;
     RECT  84.841 17.904 84.877 17.928 ;
     RECT  84.841 20.016 84.877 20.856 ;
     RECT  84.841 28.8 84.877 28.824 ;
     RECT  84.841 33.84 84.877 33.864 ;
     RECT  84.841 40.992 84.877 41.016 ;
     RECT  84.841 42.24 84.877 42.264 ;
     RECT  84.841 44.784 84.877 44.808 ;
     RECT  84.841 51.936 84.877 51.96 ;
     RECT  84.805 54.432 84.877 54.6 ;
     RECT  84.841 57.36 84.877 57.384 ;
     RECT  84.841 59.472 84.877 59.496 ;
     RECT  84.841 61.152 84.877 61.176 ;
     RECT  84.877 27.984 84.913 31.368 ;
     RECT  84.877 32.592 84.913 33.864 ;
     RECT  84.877 2.784 85.093 3.624 ;
     RECT  84.877 4.896 85.093 15.384 ;
     RECT  84.913 27.984 85.093 33.864 ;
     RECT  84.877 35.136 85.093 37.224 ;
     RECT  85.093 2.784 85.345 15.384 ;
     RECT  84.877 16.656 85.345 20.856 ;
     RECT  84.877 38.88 85.345 42.696 ;
     RECT  84.877 43.92 85.345 46.92 ;
     RECT  84.877 54 85.345 54.6 ;
     RECT  84.877 55.68 85.345 55.704 ;
     RECT  84.877 56.976 85.345 57.384 ;
     RECT  84.877 58.656 85.345 59.496 ;
     RECT  84.877 60.72 85.345 62.04 ;
     RECT  85.345 2.784 85.453 20.856 ;
     RECT  84.877 22.08 85.453 26.76 ;
     RECT  85.093 27.984 85.453 37.224 ;
     RECT  85.345 38.88 85.453 46.92 ;
     RECT  84.877 48.144 85.453 49.416 ;
     RECT  84.877 50.64 85.453 52.344 ;
     RECT  85.345 54 85.453 57.384 ;
     RECT  85.345 58.656 85.453 62.04 ;
     RECT  85.453 2.352 86.316 2.376 ;
     RECT  85.453 2.376 86.364 2.784 ;
     RECT  85.453 2.784 86.316 2.808 ;
     RECT  85.453 2.808 86.364 3.216 ;
     RECT  85.453 3.216 86.316 3.24 ;
     RECT  85.453 3.24 86.364 3.6 ;
     RECT  85.453 3.6 86.316 3.624 ;
     RECT  85.453 3.624 86.364 4.032 ;
     RECT  85.453 4.032 86.316 4.056 ;
     RECT  85.453 4.056 86.364 4.464 ;
     RECT  85.453 4.464 86.316 4.488 ;
     RECT  85.453 4.488 86.364 4.896 ;
     RECT  85.453 4.896 86.316 4.92 ;
     RECT  85.453 4.92 86.364 5.28 ;
     RECT  85.453 5.28 86.316 5.304 ;
     RECT  85.453 5.304 86.364 5.712 ;
     RECT  85.453 5.712 86.316 5.736 ;
     RECT  85.453 5.736 86.364 6.144 ;
     RECT  85.453 6.144 86.316 6.168 ;
     RECT  85.453 6.168 86.364 6.576 ;
     RECT  85.453 6.576 86.316 6.6 ;
     RECT  85.453 6.6 86.364 6.96 ;
     RECT  85.453 6.96 86.316 6.984 ;
     RECT  85.453 6.984 86.364 7.392 ;
     RECT  85.453 7.392 86.316 7.416 ;
     RECT  85.453 7.416 86.364 7.824 ;
     RECT  85.453 7.824 86.316 7.848 ;
     RECT  85.453 7.848 86.364 8.256 ;
     RECT  85.453 8.256 86.316 8.28 ;
     RECT  85.453 8.28 86.364 8.64 ;
     RECT  85.453 8.64 86.316 8.664 ;
     RECT  85.453 8.664 86.364 9.072 ;
     RECT  85.453 9.072 86.316 9.096 ;
     RECT  85.453 9.096 86.364 9.504 ;
     RECT  85.453 9.504 86.316 9.528 ;
     RECT  85.453 9.528 86.364 9.936 ;
     RECT  85.453 9.936 86.316 9.96 ;
     RECT  85.453 9.96 86.364 10.32 ;
     RECT  85.453 10.32 86.316 10.344 ;
     RECT  85.453 10.344 86.364 10.752 ;
     RECT  85.453 10.752 86.316 10.776 ;
     RECT  85.453 10.776 86.364 11.184 ;
     RECT  85.453 11.184 86.316 11.208 ;
     RECT  85.453 11.208 86.364 11.616 ;
     RECT  85.453 11.616 86.316 11.64 ;
     RECT  85.453 11.64 86.364 12 ;
     RECT  85.453 12 86.316 12.024 ;
     RECT  85.453 12.024 86.364 12.432 ;
     RECT  85.453 12.432 86.316 12.456 ;
     RECT  85.453 12.456 86.364 12.864 ;
     RECT  85.453 12.864 86.316 12.888 ;
     RECT  85.453 12.888 86.364 13.296 ;
     RECT  85.453 13.296 86.316 13.32 ;
     RECT  85.453 13.32 86.364 13.68 ;
     RECT  85.453 13.68 86.316 13.704 ;
     RECT  85.453 13.704 86.364 14.112 ;
     RECT  85.453 14.112 86.316 14.136 ;
     RECT  85.453 14.136 86.364 14.544 ;
     RECT  85.453 14.544 86.316 14.568 ;
     RECT  85.453 14.568 86.364 14.976 ;
     RECT  85.453 14.976 86.316 15 ;
     RECT  85.453 15 86.364 15.36 ;
     RECT  85.453 15.36 86.316 15.384 ;
     RECT  85.453 15.384 86.364 15.792 ;
     RECT  85.453 15.792 86.316 15.816 ;
     RECT  85.453 15.816 86.364 16.224 ;
     RECT  85.453 16.224 86.316 16.248 ;
     RECT  85.453 16.248 86.364 16.656 ;
     RECT  85.453 16.656 86.316 16.68 ;
     RECT  85.453 16.68 86.364 17.04 ;
     RECT  85.453 17.04 86.316 17.064 ;
     RECT  85.453 17.064 86.364 17.472 ;
     RECT  85.453 17.472 86.316 17.496 ;
     RECT  85.453 17.496 86.364 17.904 ;
     RECT  85.453 17.904 86.316 17.928 ;
     RECT  85.453 17.928 86.364 18.336 ;
     RECT  85.453 18.336 86.316 18.36 ;
     RECT  85.453 18.36 86.364 18.72 ;
     RECT  85.453 18.72 86.316 18.744 ;
     RECT  85.453 18.744 86.364 19.152 ;
     RECT  85.453 19.152 86.316 19.176 ;
     RECT  85.453 19.176 86.364 19.584 ;
     RECT  85.453 19.584 86.316 19.608 ;
     RECT  85.453 19.608 86.364 20.016 ;
     RECT  85.453 20.016 86.316 20.04 ;
     RECT  85.453 20.04 86.364 20.4 ;
     RECT  85.453 20.4 86.316 20.424 ;
     RECT  85.453 20.424 86.364 20.832 ;
     RECT  85.453 20.832 86.316 20.856 ;
     RECT  85.453 20.856 86.364 21.264 ;
     RECT  85.453 21.264 86.316 21.288 ;
     RECT  85.453 21.288 86.364 21.696 ;
     RECT  85.453 21.696 86.316 21.72 ;
     RECT  85.453 21.72 86.364 22.08 ;
     RECT  85.453 22.08 86.316 22.104 ;
     RECT  85.453 22.104 86.364 22.512 ;
     RECT  85.453 22.512 86.316 22.536 ;
     RECT  85.453 22.536 86.364 22.944 ;
     RECT  85.453 22.944 86.316 22.968 ;
     RECT  85.453 22.968 86.364 23.376 ;
     RECT  85.453 23.376 86.316 23.4 ;
     RECT  85.453 23.4 86.364 23.76 ;
     RECT  85.453 23.76 86.316 23.784 ;
     RECT  85.453 23.784 86.364 24.192 ;
     RECT  85.453 24.192 86.316 24.216 ;
     RECT  85.453 24.216 86.364 24.624 ;
     RECT  85.453 24.624 86.316 24.648 ;
     RECT  85.453 24.648 86.364 25.056 ;
     RECT  85.453 25.056 86.316 25.08 ;
     RECT  85.453 25.08 86.364 25.44 ;
     RECT  85.453 25.44 86.316 25.464 ;
     RECT  85.453 25.464 86.364 25.872 ;
     RECT  85.453 25.872 86.316 25.896 ;
     RECT  85.453 25.896 86.364 26.304 ;
     RECT  85.453 26.304 86.316 26.328 ;
     RECT  85.453 26.328 86.364 26.736 ;
     RECT  85.453 26.736 86.316 26.76 ;
     RECT  85.453 26.76 86.364 27.12 ;
     RECT  85.453 27.12 86.316 27.144 ;
     RECT  85.453 27.144 86.364 27.552 ;
     RECT  85.453 27.552 86.316 27.576 ;
     RECT  85.453 27.576 86.364 27.984 ;
     RECT  85.453 27.984 86.316 28.008 ;
     RECT  85.453 28.008 86.364 28.416 ;
     RECT  85.453 28.416 86.316 28.44 ;
     RECT  85.453 28.44 86.364 28.8 ;
     RECT  85.453 28.8 86.316 28.824 ;
     RECT  85.453 28.824 86.364 29.232 ;
     RECT  85.453 29.232 86.316 29.256 ;
     RECT  85.453 29.256 86.364 29.664 ;
     RECT  85.453 29.664 86.316 29.688 ;
     RECT  85.453 29.688 86.364 30.096 ;
     RECT  85.453 30.096 86.316 30.12 ;
     RECT  85.453 30.12 86.364 30.48 ;
     RECT  85.453 30.48 86.316 30.504 ;
     RECT  85.453 30.504 86.364 30.912 ;
     RECT  85.453 30.912 86.316 30.936 ;
     RECT  85.453 30.936 86.364 31.344 ;
     RECT  85.453 31.344 86.316 31.368 ;
     RECT  85.453 31.368 86.364 31.776 ;
     RECT  85.453 31.776 86.316 31.8 ;
     RECT  85.453 31.8 86.364 32.16 ;
     RECT  85.453 32.16 86.316 32.184 ;
     RECT  85.453 32.184 86.364 32.592 ;
     RECT  85.453 32.592 86.316 32.616 ;
     RECT  85.453 32.616 86.364 33.024 ;
     RECT  85.453 33.024 86.316 33.048 ;
     RECT  85.453 33.048 86.364 33.456 ;
     RECT  85.453 33.456 86.316 33.48 ;
     RECT  85.453 33.48 86.364 33.84 ;
     RECT  85.453 33.84 86.316 33.864 ;
     RECT  85.453 33.864 86.364 34.272 ;
     RECT  85.453 34.272 86.316 34.296 ;
     RECT  85.453 34.296 86.364 34.704 ;
     RECT  85.453 34.704 86.316 34.728 ;
     RECT  85.453 34.728 86.364 35.136 ;
     RECT  85.453 35.136 86.316 35.16 ;
     RECT  85.453 35.16 86.364 35.52 ;
     RECT  85.453 35.52 86.316 35.544 ;
     RECT  85.453 35.544 86.364 35.952 ;
     RECT  85.453 35.952 86.316 35.976 ;
     RECT  85.453 35.976 86.364 36.384 ;
     RECT  85.453 36.384 86.316 36.408 ;
     RECT  85.453 36.408 86.364 36.816 ;
     RECT  85.453 36.816 86.316 36.84 ;
     RECT  85.453 36.84 86.364 37.2 ;
     RECT  85.453 37.2 86.316 37.224 ;
     RECT  85.453 37.224 86.364 37.632 ;
     RECT  85.453 37.632 86.316 37.656 ;
     RECT  85.453 37.656 86.364 38.064 ;
     RECT  85.453 38.064 86.316 38.088 ;
     RECT  85.453 38.088 86.364 38.496 ;
     RECT  85.453 38.496 86.316 38.52 ;
     RECT  85.453 38.52 86.364 38.88 ;
     RECT  85.453 38.88 86.316 38.904 ;
     RECT  85.453 38.904 86.364 39.312 ;
     RECT  85.453 39.312 86.316 39.336 ;
     RECT  85.453 39.336 86.364 39.744 ;
     RECT  85.453 39.744 86.316 39.768 ;
     RECT  85.453 39.768 86.364 40.176 ;
     RECT  85.453 40.176 86.316 40.2 ;
     RECT  85.453 40.2 86.364 40.56 ;
     RECT  85.453 40.56 86.316 40.584 ;
     RECT  85.453 40.584 86.364 40.992 ;
     RECT  85.453 40.992 86.316 41.016 ;
     RECT  85.453 41.016 86.364 41.424 ;
     RECT  85.453 41.424 86.316 41.448 ;
     RECT  85.453 41.448 86.364 41.856 ;
     RECT  85.453 41.856 86.316 41.88 ;
     RECT  85.453 41.88 86.364 42.24 ;
     RECT  85.453 42.24 86.316 42.264 ;
     RECT  85.453 42.264 86.364 42.672 ;
     RECT  85.453 42.672 86.316 42.696 ;
     RECT  85.453 42.696 86.364 43.104 ;
     RECT  85.453 43.104 86.316 43.128 ;
     RECT  85.453 43.128 86.364 43.536 ;
     RECT  85.453 43.536 86.316 43.56 ;
     RECT  85.453 43.56 86.364 43.92 ;
     RECT  85.453 43.92 86.316 43.944 ;
     RECT  85.453 43.944 86.364 44.352 ;
     RECT  85.453 44.352 86.316 44.376 ;
     RECT  85.453 44.376 86.364 44.784 ;
     RECT  85.453 44.784 86.316 44.808 ;
     RECT  85.453 44.808 86.364 45.216 ;
     RECT  85.453 45.216 86.316 45.24 ;
     RECT  85.453 45.24 86.364 45.6 ;
     RECT  85.453 45.6 86.316 45.624 ;
     RECT  85.453 45.624 86.364 46.032 ;
     RECT  85.453 46.032 86.316 46.056 ;
     RECT  85.453 46.056 86.364 46.464 ;
     RECT  85.453 46.464 86.316 46.488 ;
     RECT  85.453 46.488 86.364 46.896 ;
     RECT  85.453 46.896 86.316 46.92 ;
     RECT  85.453 46.92 86.364 47.28 ;
     RECT  85.453 47.28 86.316 47.304 ;
     RECT  85.453 47.304 86.364 47.712 ;
     RECT  85.453 47.712 86.316 47.736 ;
     RECT  85.453 47.736 86.364 48.144 ;
     RECT  85.453 48.144 86.316 48.168 ;
     RECT  85.453 48.168 86.364 48.576 ;
     RECT  85.453 48.576 86.316 48.6 ;
     RECT  85.453 48.6 86.364 48.96 ;
     RECT  85.453 48.96 86.316 48.984 ;
     RECT  85.453 48.984 86.364 49.392 ;
     RECT  85.453 49.392 86.316 49.416 ;
     RECT  85.453 49.416 86.364 49.824 ;
     RECT  85.453 49.824 86.316 49.848 ;
     RECT  85.453 49.848 86.364 50.256 ;
     RECT  85.453 50.256 86.316 50.28 ;
     RECT  85.453 50.28 86.364 50.64 ;
     RECT  85.453 50.64 86.316 50.664 ;
     RECT  85.453 50.664 86.364 51.072 ;
     RECT  85.453 51.072 86.316 51.096 ;
     RECT  85.453 51.096 86.364 51.504 ;
     RECT  85.453 51.504 86.316 51.528 ;
     RECT  85.453 51.528 86.364 51.936 ;
     RECT  85.453 51.936 86.316 51.96 ;
     RECT  85.453 51.96 86.364 52.32 ;
     RECT  85.453 52.32 86.316 52.344 ;
     RECT  85.453 52.344 86.364 52.752 ;
     RECT  85.453 52.752 86.316 52.776 ;
     RECT  85.453 52.776 86.364 53.184 ;
     RECT  85.453 53.184 86.316 53.208 ;
     RECT  85.453 53.208 86.364 53.616 ;
     RECT  85.453 53.616 86.316 53.64 ;
     RECT  85.453 53.64 86.364 54 ;
     RECT  85.453 54 86.316 54.024 ;
     RECT  85.453 54.024 86.364 54.432 ;
     RECT  85.453 54.432 86.316 54.456 ;
     RECT  85.453 54.456 86.364 54.864 ;
     RECT  85.453 54.864 86.316 54.888 ;
     RECT  85.453 54.888 86.364 55.296 ;
     RECT  85.453 55.296 86.316 55.32 ;
     RECT  85.453 55.32 86.364 55.68 ;
     RECT  85.453 55.68 86.316 55.704 ;
     RECT  85.453 55.704 86.364 56.112 ;
     RECT  85.453 56.112 86.316 56.136 ;
     RECT  85.453 56.136 86.364 56.544 ;
     RECT  85.453 56.544 86.316 56.568 ;
     RECT  85.453 56.568 86.364 56.976 ;
     RECT  85.453 56.976 86.316 57 ;
     RECT  85.453 57 86.364 57.36 ;
     RECT  85.453 57.36 86.316 57.384 ;
     RECT  85.453 57.384 86.364 57.792 ;
     RECT  85.453 57.792 86.316 57.816 ;
     RECT  85.453 57.816 86.364 58.224 ;
     RECT  85.453 58.224 86.316 58.248 ;
     RECT  85.453 58.248 86.364 58.656 ;
     RECT  85.453 58.656 86.316 58.68 ;
     RECT  85.453 58.68 86.364 59.04 ;
     RECT  85.453 59.04 86.316 59.064 ;
     RECT  85.453 59.064 86.364 59.472 ;
     RECT  85.453 59.472 86.316 59.496 ;
     RECT  85.453 59.496 86.364 59.904 ;
     RECT  85.453 59.904 86.316 59.928 ;
     RECT  85.453 59.928 86.364 60.336 ;
     RECT  85.453 60.336 86.316 60.36 ;
     RECT  85.453 60.36 86.364 60.72 ;
     RECT  85.453 60.72 86.316 60.744 ;
     RECT  85.453 60.744 86.364 61.152 ;
     RECT  85.453 61.152 86.316 61.176 ;
     RECT  85.453 61.176 86.364 61.584 ;
     RECT  85.453 61.584 86.316 61.608 ;
     RECT  85.453 61.608 86.364 62.016 ;
     RECT  85.453 62.016 86.316 62.04 ;
     RECT  85.453 62.04 86.364 62.4 ;
     RECT  85.453 62.4 86.316 62.424 ;
    LAYER M5 ;
     RECT  2.4 2.137 2.52 2.151 ;
     RECT  7.8 2.137 7.92 2.151 ;
     RECT  13.2 2.137 13.32 2.151 ;
     RECT  18.6 2.137 18.72 2.151 ;
     RECT  24 2.137 24.12 2.151 ;
     RECT  29.4 2.137 29.52 2.151 ;
     RECT  34.8 2.137 34.92 2.151 ;
     RECT  40.2 2.137 40.32 2.151 ;
     RECT  45.6 2.137 45.72 2.151 ;
     RECT  51 2.137 51.12 2.151 ;
     RECT  56.4 2.137 56.52 2.151 ;
     RECT  61.8 2.137 61.92 2.151 ;
     RECT  67.2 2.137 67.32 2.151 ;
     RECT  72.6 2.137 72.72 2.151 ;
     RECT  78 2.137 78.12 2.151 ;
     RECT  83.4 2.137 83.52 2.151 ;
     RECT  2.4 2.151 2.712 2.245 ;
     RECT  40.2 2.151 40.512 2.773 ;
     RECT  67.2 2.151 67.512 2.821 ;
     RECT  42 2.821 42.024 3.443 ;
     RECT  72.6 2.151 72.912 3.685 ;
     RECT  2.4 2.245 2.808 4.163 ;
     RECT  45.6 2.151 45.912 4.501 ;
     RECT  43.68 3.013 43.704 4.597 ;
     RECT  43.68 4.597 44.04 4.643 ;
     RECT  48.24 3.925 48.264 4.643 ;
     RECT  71.808 3.685 72.912 4.643 ;
     RECT  67.2 2.821 68.424 4.691 ;
     RECT  5.136 3.397 5.16 4.883 ;
     RECT  70.56 4.645 70.584 5.077 ;
     RECT  70.128 5.077 70.584 5.219 ;
     RECT  39.36 2.773 40.512 5.747 ;
     RECT  37.152 4.261 37.176 5.845 ;
     RECT  44.016 4.643 44.04 5.987 ;
     RECT  67.2 4.691 68.28 6.277 ;
     RECT  3.744 6.277 3.768 6.805 ;
     RECT  40.2 5.747 40.512 6.853 ;
     RECT  45.6 4.501 46.296 6.899 ;
     RECT  40.2 6.853 41.448 7.379 ;
     RECT  67.2 6.277 68.376 7.475 ;
     RECT  3.744 6.805 4.2 8.003 ;
     RECT  53.376 6.805 53.4 8.435 ;
     RECT  51 2.151 51.312 8.869 ;
     RECT  55.248 7.957 55.272 8.869 ;
     RECT  54.768 8.869 55.272 8.915 ;
     RECT  37.152 5.845 37.752 9.107 ;
     RECT  42.768 6.805 42.792 9.251 ;
     RECT  54.768 8.915 54.792 9.491 ;
     RECT  70.128 5.219 70.152 9.637 ;
     RECT  71.28 8.485 71.304 9.637 ;
     RECT  70.128 9.637 71.304 9.683 ;
     RECT  70.368 9.683 71.304 9.827 ;
     RECT  2.4 4.163 2.712 10.165 ;
     RECT  51 8.869 51.72 10.261 ;
     RECT  49.536 9.637 49.56 10.307 ;
     RECT  61.8 2.151 62.112 10.501 ;
     RECT  37.152 9.107 37.176 10.789 ;
     RECT  40.2 7.379 40.512 10.885 ;
     RECT  57.792 6.229 57.816 11.027 ;
     RECT  2.4 10.165 2.904 11.125 ;
     RECT  51 10.261 51.864 11.459 ;
     RECT  69.36 10.021 69.384 11.459 ;
     RECT  39.888 10.885 40.512 11.651 ;
     RECT  4.176 8.003 4.2 11.941 ;
     RECT  4.032 11.941 4.2 11.987 ;
     RECT  37.152 10.789 37.32 11.989 ;
     RECT  37.056 11.989 37.32 12.035 ;
     RECT  61.056 10.501 62.112 12.227 ;
     RECT  51 11.459 51.72 12.325 ;
     RECT  54.768 11.653 54.792 12.467 ;
     RECT  67.2 7.475 67.512 12.517 ;
     RECT  70.368 9.827 70.392 12.517 ;
     RECT  2.4 11.125 3 12.563 ;
     RECT  45.6 6.899 46.2 12.755 ;
     RECT  50.448 12.325 51.72 12.803 ;
     RECT  37.056 12.035 37.176 13.715 ;
     RECT  2.4 12.563 2.712 14.197 ;
     RECT  4.032 11.987 4.056 14.197 ;
     RECT  40.2 11.651 40.512 14.197 ;
     RECT  50.448 12.803 51.432 14.243 ;
     RECT  53.424 13.573 53.448 14.243 ;
     RECT  58.128 12.373 58.152 14.675 ;
     RECT  70.128 12.517 70.392 14.675 ;
     RECT  43.488 11.029 43.512 14.773 ;
     RECT  50.88 14.243 51.432 14.867 ;
     RECT  48.72 14.197 48.744 15.011 ;
     RECT  39.744 14.197 40.512 15.013 ;
     RECT  2.4 14.197 4.056 15.107 ;
     RECT  43.488 14.773 44.328 15.347 ;
     RECT  39.696 15.013 40.512 15.349 ;
     RECT  70.368 14.675 70.392 15.445 ;
     RECT  70.368 15.445 70.68 15.637 ;
     RECT  43.488 15.347 43.512 16.019 ;
     RECT  38.832 15.349 40.512 16.307 ;
     RECT  67.2 12.517 67.848 16.549 ;
     RECT  47.328 15.061 47.352 16.595 ;
     RECT  67.104 16.549 67.848 16.595 ;
     RECT  53.856 15.829 53.88 16.787 ;
     RECT  56.4 2.151 56.712 16.789 ;
     RECT  74.112 15.829 74.136 16.931 ;
     RECT  42.816 16.261 42.84 17.075 ;
     RECT  70.128 15.637 70.68 17.075 ;
     RECT  45.6 12.755 45.912 17.077 ;
     RECT  51 14.867 51.432 17.173 ;
     RECT  2.4 15.107 2.904 17.461 ;
     RECT  4.032 15.107 4.056 17.461 ;
     RECT  56.4 16.789 57.144 18.181 ;
     RECT  72.6 4.643 72.912 18.181 ;
     RECT  40.2 16.307 40.512 18.229 ;
     RECT  50.688 17.173 51.432 18.373 ;
     RECT  2.4 17.461 4.056 18.467 ;
     RECT  59.616 12.517 59.64 18.613 ;
     RECT  59.616 18.613 59.832 18.755 ;
     RECT  70.128 17.075 70.152 18.757 ;
     RECT  70.128 18.757 70.392 18.803 ;
     RECT  72.6 18.181 73.464 18.851 ;
     RECT  75.072 18.037 75.096 19.093 ;
     RECT  75.072 19.093 75.24 19.139 ;
     RECT  37.152 13.715 37.176 19.765 ;
     RECT  68.88 19.141 68.904 20.053 ;
     RECT  68.592 20.053 68.904 20.099 ;
     RECT  75.216 19.139 75.24 20.099 ;
     RECT  34.8 2.151 35.112 20.101 ;
     RECT  38.832 16.307 38.856 20.147 ;
     RECT  50.688 18.373 51.624 20.149 ;
     RECT  40.032 18.229 40.512 20.339 ;
     RECT  56.4 18.181 57.864 20.579 ;
     RECT  33.984 20.101 35.112 20.627 ;
     RECT  42.672 20.437 42.696 20.771 ;
     RECT  4.032 18.467 4.056 20.773 ;
     RECT  4.032 20.773 4.296 20.819 ;
     RECT  45.6 17.077 46.776 20.821 ;
     RECT  50.352 20.149 51.624 20.963 ;
     RECT  2.4 18.467 2.712 21.013 ;
     RECT  70.368 18.803 70.392 21.109 ;
     RECT  57.84 20.579 57.864 21.155 ;
     RECT  70.368 21.109 70.68 21.155 ;
     RECT  36.816 19.765 37.176 21.443 ;
     RECT  29.4 2.151 29.712 21.445 ;
     RECT  45.6 20.821 46.824 21.539 ;
     RECT  72.6 18.851 72.912 21.637 ;
     RECT  41.616 20.725 41.64 21.683 ;
     RECT  50.352 20.963 51.48 21.683 ;
     RECT  59.664 18.755 59.688 22.117 ;
     RECT  54.96 20.629 54.984 22.165 ;
     RECT  37.152 21.443 37.176 22.213 ;
     RECT  2.4 21.013 2.952 22.259 ;
     RECT  51 21.683 51.48 22.693 ;
     RECT  51 22.693 51.576 22.741 ;
     RECT  37.152 22.213 37.896 22.835 ;
     RECT  67.104 16.595 67.512 22.835 ;
     RECT  34.8 20.627 35.112 23.029 ;
     RECT  40.2 20.339 40.512 23.029 ;
     RECT  43.248 22.645 43.272 23.173 ;
     RECT  43.248 23.173 43.368 23.219 ;
     RECT  28.512 21.445 29.712 23.315 ;
     RECT  68.592 20.099 68.616 23.411 ;
     RECT  54.096 22.165 54.984 23.555 ;
     RECT  57.792 21.637 57.816 23.699 ;
     RECT  48.96 21.637 48.984 24.083 ;
     RECT  34.8 23.029 35.208 24.131 ;
     RECT  37.872 22.835 37.896 24.131 ;
     RECT  51 22.741 51.672 24.323 ;
     RECT  39.504 23.029 40.512 24.419 ;
     RECT  72.432 21.637 72.912 24.467 ;
     RECT  51 24.323 51.576 24.469 ;
     RECT  47.712 22.741 47.736 24.563 ;
     RECT  59.664 22.117 60.072 24.563 ;
     RECT  2.4 22.259 2.712 24.997 ;
     RECT  4.272 20.819 4.296 24.997 ;
     RECT  50.88 24.469 51.576 25.139 ;
     RECT  60.048 24.563 60.072 25.139 ;
     RECT  45.6 21.539 45.912 26.197 ;
     RECT  51 25.139 51.576 26.197 ;
     RECT  43.344 23.219 43.368 26.243 ;
     RECT  50.064 26.197 51.576 26.243 ;
     RECT  54.48 23.555 54.984 26.291 ;
     RECT  50.064 26.243 51.312 26.435 ;
     RECT  56.4 20.579 56.712 26.533 ;
     RECT  70.656 21.155 70.68 26.725 ;
     RECT  2.4 24.997 4.296 26.771 ;
     RECT  45.6 26.197 46.728 27.107 ;
     RECT  39.936 24.419 40.512 27.157 ;
     RECT  37.872 26.293 37.896 27.395 ;
     RECT  4.272 26.771 4.296 27.733 ;
     RECT  47.904 26.629 47.928 28.451 ;
     RECT  67.2 22.835 67.512 28.453 ;
     RECT  51 26.435 51.312 28.501 ;
     RECT  70.656 26.725 71.304 28.547 ;
     RECT  39.888 27.157 40.512 28.595 ;
     RECT  71.28 28.547 71.304 28.787 ;
     RECT  3.936 27.733 4.296 29.123 ;
     RECT  59.664 25.621 59.688 29.173 ;
     RECT  50.736 28.501 51.312 29.219 ;
     RECT  59.424 29.173 59.688 29.219 ;
     RECT  45.6 27.107 45.912 29.317 ;
     RECT  6.192 27.301 6.216 29.459 ;
     RECT  56.4 26.533 56.808 29.749 ;
     RECT  44.928 29.317 45.912 30.275 ;
     RECT  67.2 28.453 68.136 30.275 ;
     RECT  75.024 28.453 75.048 30.275 ;
     RECT  3.936 29.123 3.96 30.323 ;
     RECT  2.4 26.771 2.712 30.421 ;
     RECT  59.424 29.219 59.448 30.757 ;
     RECT  39.936 28.595 40.512 30.803 ;
     RECT  58.704 30.757 59.448 30.899 ;
     RECT  44.976 30.275 45.912 30.901 ;
     RECT  44.976 30.901 46.584 31.955 ;
     RECT  56.4 29.749 56.952 32.003 ;
     RECT  42.72 30.997 42.744 32.051 ;
     RECT  28.368 23.605 28.392 32.437 ;
     RECT  54.96 26.291 54.984 32.437 ;
     RECT  72.6 24.467 72.912 32.437 ;
     RECT  28.176 32.437 28.392 32.483 ;
     RECT  40.2 30.803 40.512 32.773 ;
     RECT  51 29.219 51.312 32.869 ;
     RECT  54.96 32.437 55.176 32.869 ;
     RECT  44.976 31.955 45.912 33.061 ;
     RECT  43.2 32.293 43.224 33.109 ;
     RECT  5.616 32.437 5.64 33.253 ;
     RECT  5.616 33.253 6.504 33.299 ;
     RECT  44.976 33.061 46.008 33.349 ;
     RECT  2.4 30.421 3.48 33.587 ;
     RECT  43.2 33.109 43.848 33.637 ;
     RECT  40.2 32.773 41.448 33.683 ;
     RECT  42.48 33.637 43.848 33.683 ;
     RECT  38.016 33.541 38.04 33.923 ;
     RECT  72.48 32.437 72.912 34.165 ;
     RECT  44.976 33.349 46.056 34.259 ;
     RECT  47.808 33.541 47.832 34.259 ;
     RECT  51 32.869 52.104 34.499 ;
     RECT  45.6 34.259 46.056 34.739 ;
     RECT  6.48 33.299 6.504 34.835 ;
     RECT  71.856 34.165 72.912 34.835 ;
     RECT  42.48 33.683 43.224 35.171 ;
     RECT  54.816 32.869 55.176 35.363 ;
     RECT  38.352 33.925 38.376 35.413 ;
     RECT  38.352 35.413 38.52 35.459 ;
     RECT  51 34.499 51.312 35.605 ;
     RECT  45.6 34.739 45.912 35.845 ;
     RECT  38.496 35.459 38.52 36.515 ;
     RECT  43.2 35.171 43.224 36.517 ;
     RECT  66.144 33.397 66.168 36.517 ;
     RECT  45.312 35.845 45.912 36.563 ;
     RECT  43.2 36.517 43.368 36.995 ;
     RECT  65.472 36.517 66.168 36.997 ;
     RECT  67.2 30.275 67.512 36.997 ;
     RECT  65.472 36.997 67.512 37.043 ;
     RECT  66.672 37.043 67.512 37.139 ;
     RECT  46.992 36.661 47.016 37.573 ;
     RECT  46.992 37.573 47.784 37.619 ;
     RECT  47.76 37.619 47.784 38.147 ;
     RECT  50.208 35.605 51.312 38.149 ;
     RECT  72.6 34.835 72.912 38.389 ;
     RECT  40.2 33.683 40.512 38.581 ;
     RECT  34.8 24.131 35.112 38.677 ;
     RECT  57.744 35.317 57.768 38.725 ;
     RECT  57.744 38.725 58.056 38.771 ;
     RECT  16.8 33.445 16.824 38.773 ;
     RECT  16.704 38.773 16.824 38.819 ;
     RECT  37.056 38.677 37.08 38.819 ;
     RECT  4.416 39.109 4.44 39.253 ;
     RECT  34.8 38.677 35.208 39.301 ;
     RECT  65.472 37.043 65.496 39.395 ;
     RECT  72.6 38.389 73.128 39.395 ;
     RECT  49.392 38.149 51.312 39.923 ;
     RECT  69.984 35.701 70.008 40.309 ;
     RECT  40.2 38.581 41.304 41.075 ;
     RECT  3.696 39.253 4.44 41.651 ;
     RECT  49.68 39.923 51.312 41.987 ;
     RECT  43.2 36.995 43.224 42.325 ;
     RECT  4.416 41.651 4.44 42.709 ;
     RECT  37.104 40.693 37.128 42.803 ;
     RECT  69.504 40.309 70.008 42.901 ;
     RECT  69.504 42.901 70.728 42.947 ;
     RECT  45.6 36.563 45.912 43.141 ;
     RECT  55.152 35.363 55.176 43.141 ;
     RECT  3.984 42.709 4.44 43.859 ;
     RECT  40.2 41.075 40.512 43.861 ;
     RECT  47.568 41.557 47.592 43.861 ;
     RECT  42.912 42.325 43.224 43.955 ;
     RECT  47.568 43.861 47.88 44.339 ;
     RECT  40.08 43.861 40.512 44.483 ;
     RECT  44.784 43.141 45.912 44.483 ;
     RECT  54.528 43.141 55.176 44.483 ;
     RECT  69.984 42.947 70.728 44.579 ;
     RECT  28.176 32.483 28.2 44.723 ;
     RECT  55.152 44.483 55.176 44.725 ;
     RECT  56.4 32.003 56.712 44.725 ;
     RECT  58.032 38.771 58.056 44.915 ;
     RECT  61.8 12.227 62.112 44.965 ;
     RECT  67.2 37.139 67.512 44.965 ;
     RECT  2.4 33.587 2.712 45.301 ;
     RECT  50.112 41.987 51.312 45.301 ;
     RECT  47.856 44.339 47.88 45.443 ;
     RECT  34.8 39.301 35.592 45.541 ;
     RECT  43.2 43.955 43.224 45.541 ;
     RECT  16.704 38.819 16.728 45.635 ;
     RECT  55.152 44.725 56.712 45.635 ;
     RECT  40.2 44.483 40.512 45.685 ;
     RECT  43.2 45.541 44.184 45.685 ;
     RECT  55.68 45.635 56.712 45.731 ;
     RECT  22.8 45.493 22.824 45.971 ;
     RECT  47.616 45.445 47.64 46.165 ;
     RECT  47.472 46.165 47.64 46.211 ;
     RECT  61.68 44.965 62.112 46.259 ;
     RECT  2.4 45.301 3.432 46.499 ;
     RECT  40.08 45.685 40.512 46.787 ;
     RECT  42.768 45.685 44.184 46.787 ;
     RECT  47.472 46.211 47.496 46.787 ;
     RECT  49.152 45.301 51.312 46.787 ;
     RECT  52.464 43.861 52.488 46.787 ;
     RECT  61.8 46.259 62.112 47.125 ;
     RECT  67.2 44.965 67.848 47.363 ;
     RECT  54.144 46.501 54.168 47.891 ;
     RECT  69.984 44.579 70.008 48.133 ;
     RECT  72.6 39.395 72.912 48.133 ;
     RECT  69.552 48.133 70.008 48.179 ;
     RECT  61.8 47.125 62.232 48.419 ;
     RECT  69.552 48.179 69.576 48.419 ;
     RECT  34.8 45.541 35.832 48.421 ;
     RECT  38.784 48.277 38.808 48.421 ;
     RECT  55.824 45.731 56.712 48.421 ;
     RECT  66 44.437 66.024 48.467 ;
     RECT  55.824 48.421 57.048 48.947 ;
     RECT  49.104 48.277 49.128 48.997 ;
     RECT  41.856 47.845 41.88 49.043 ;
     RECT  49.008 48.997 49.128 49.043 ;
     RECT  52.896 48.901 52.92 49.043 ;
     RECT  56.4 48.947 57.048 49.429 ;
     RECT  56.4 49.429 57.816 49.475 ;
     RECT  70.992 47.845 71.016 49.475 ;
     RECT  4.416 43.859 4.44 49.525 ;
     RECT  45.6 44.483 45.912 49.525 ;
     RECT  49.008 49.043 49.032 49.573 ;
     RECT  50.112 46.787 51.312 49.619 ;
     RECT  38.784 48.421 39.048 49.667 ;
     RECT  48.24 49.573 49.032 49.715 ;
     RECT  43.2 46.787 44.184 49.859 ;
     RECT  3.984 49.525 4.44 50.243 ;
     RECT  2.4 46.499 2.712 50.677 ;
     RECT  39.024 49.667 39.048 50.723 ;
     RECT  72.192 48.133 72.912 50.725 ;
     RECT  45.6 49.525 46.632 50.771 ;
     RECT  63.792 48.805 63.816 51.205 ;
     RECT  63.36 51.205 63.816 51.251 ;
     RECT  2.4 50.677 3.432 51.539 ;
     RECT  72.192 50.725 73.176 51.635 ;
     RECT  49.92 50.965 49.944 51.923 ;
     RECT  34.8 48.421 35.928 52.021 ;
     RECT  63.36 51.251 63.384 52.211 ;
     RECT  65.664 51.205 65.688 52.499 ;
     RECT  34.704 52.021 35.928 52.979 ;
     RECT  4.416 50.243 4.44 52.981 ;
     RECT  72.192 51.635 72.912 52.981 ;
     RECT  45.6 50.771 45.912 53.557 ;
     RECT  71.52 52.981 72.912 53.557 ;
     RECT  51 49.619 51.312 54.085 ;
     RECT  3.984 52.981 4.44 54.179 ;
     RECT  71.52 53.557 73.512 54.323 ;
     RECT  54.576 53.557 54.6 54.565 ;
     RECT  54.576 54.565 54.696 54.611 ;
     RECT  57.792 49.475 57.816 54.611 ;
     RECT  72.192 54.323 73.512 54.611 ;
     RECT  45.6 53.557 46.008 54.659 ;
     RECT  37.728 52.885 37.752 54.755 ;
     RECT  60.192 48.373 60.216 54.755 ;
     RECT  44.304 54.085 44.328 54.803 ;
     RECT  43.2 49.859 43.224 55.429 ;
     RECT  70.032 54.085 70.056 55.475 ;
     RECT  45.6 54.659 45.912 55.525 ;
     RECT  4.416 54.179 4.44 55.813 ;
     RECT  4.32 55.813 4.44 55.859 ;
     RECT  48.24 49.715 48.264 55.907 ;
     RECT  45.504 55.525 45.912 56.341 ;
     RECT  50.592 54.085 51.312 56.387 ;
     RECT  40.2 46.787 40.512 56.389 ;
     RECT  37.056 55.765 37.08 56.483 ;
     RECT  34.704 52.979 35.832 56.819 ;
     RECT  4.32 55.859 4.344 56.917 ;
     RECT  45.504 56.341 46.152 57.059 ;
     RECT  60.768 55.573 60.792 57.541 ;
     RECT  61.8 48.419 62.112 57.541 ;
     RECT  60.768 57.541 62.112 57.587 ;
     RECT  34.8 56.819 35.832 57.635 ;
     RECT  45.6 57.059 46.152 57.635 ;
     RECT  43.2 55.429 43.896 57.971 ;
     RECT  72.192 54.611 72.912 58.163 ;
     RECT  3.936 56.917 4.344 58.739 ;
     RECT  54.672 54.611 54.696 58.739 ;
     RECT  42.192 57.541 42.216 58.883 ;
     RECT  61.44 57.587 62.112 59.029 ;
     RECT  39.648 56.389 40.512 59.219 ;
     RECT  34.8 57.635 35.688 59.747 ;
     RECT  43.2 57.971 43.368 59.749 ;
     RECT  44.544 58.501 44.568 59.749 ;
     RECT  44.448 59.749 44.568 59.795 ;
     RECT  37.632 58.693 37.656 59.891 ;
     RECT  50.88 56.387 51.312 60.419 ;
     RECT  42.72 59.749 43.368 60.467 ;
     RECT  44.448 59.795 44.472 60.803 ;
     RECT  4.32 58.739 4.344 61.043 ;
     RECT  47.616 59.797 47.64 61.043 ;
     RECT  40.2 59.219 40.512 61.477 ;
     RECT  42.72 60.467 43.224 61.619 ;
     RECT  61.344 59.029 62.112 61.619 ;
     RECT  74.832 60.133 74.856 61.619 ;
     RECT  5.616 60.181 5.64 61.667 ;
     RECT  39.36 61.477 40.512 62.051 ;
     RECT  34.8 59.747 35.112 62.581 ;
     RECT  2.4 51.539 2.712 62.649 ;
     RECT  7.8 2.151 8.112 62.649 ;
     RECT  13.2 2.151 13.512 62.649 ;
     RECT  18.6 2.151 18.912 62.649 ;
     RECT  24 2.151 24.312 62.649 ;
     RECT  29.4 23.315 29.712 62.649 ;
     RECT  40.2 62.051 40.512 62.649 ;
     RECT  45.6 57.635 45.912 62.649 ;
     RECT  51 60.419 51.312 62.649 ;
     RECT  56.4 49.475 56.712 62.649 ;
     RECT  61.8 61.619 62.112 62.649 ;
     RECT  67.2 47.363 67.512 62.649 ;
     RECT  72.6 58.163 72.912 62.649 ;
     RECT  78 2.151 78.312 62.649 ;
     RECT  83.4 2.151 83.712 62.649 ;
     RECT  2.4 62.649 2.52 62.663 ;
     RECT  7.8 62.649 7.92 62.663 ;
     RECT  13.2 62.649 13.32 62.663 ;
     RECT  18.6 62.649 18.72 62.663 ;
     RECT  24 62.649 24.12 62.663 ;
     RECT  29.4 62.649 29.52 62.663 ;
     RECT  34.8 62.581 35.208 62.663 ;
     RECT  40.2 62.649 40.32 62.663 ;
     RECT  45.6 62.649 45.72 62.663 ;
     RECT  51 62.649 51.12 62.663 ;
     RECT  56.4 62.649 56.52 62.663 ;
     RECT  61.8 62.649 61.92 62.663 ;
     RECT  67.2 62.649 67.32 62.663 ;
     RECT  72.6 62.649 72.72 62.663 ;
     RECT  78 62.649 78.12 62.663 ;
     RECT  83.4 62.649 83.52 62.663 ;
     RECT  30.864 62.581 30.888 64.645 ;
     RECT  35.184 62.663 35.208 64.645 ;
     RECT  30.768 64.645 30.888 64.691 ;
     RECT  35.088 64.645 35.208 64.691 ;
     RECT  40.512 2.821 42 3.443 ;
     RECT  56.712 6.229 57.792 11.027 ;
     RECT  2.712 6.277 3.744 8.003 ;
     RECT  41.448 6.853 42.768 7.379 ;
     RECT  55.272 7.957 56.4 8.915 ;
     RECT  2.712 8.003 4.176 10.165 ;
     RECT  70.152 8.485 71.28 9.637 ;
     RECT  71.304 8.485 72.6 9.827 ;
     RECT  49.56 9.637 51 10.307 ;
     RECT  70.128 9.683 70.368 10.021 ;
     RECT  69.384 10.021 70.368 11.459 ;
     RECT  2.904 10.165 4.176 11.125 ;
     RECT  56.712 11.027 57.816 12.373 ;
     RECT  3 11.125 4.176 11.941 ;
     RECT  70.128 11.459 70.368 12.517 ;
     RECT  3 11.941 4.032 12.563 ;
     RECT  56.712 12.373 58.128 14.675 ;
     RECT  58.152 12.517 59.616 14.675 ;
     RECT  2.712 12.563 4.032 14.197 ;
     RECT  70.128 14.675 70.368 15.637 ;
     RECT  44.328 14.773 45.6 15.347 ;
     RECT  45.912 15.061 47.328 16.595 ;
     RECT  2.904 15.107 4.032 17.461 ;
     RECT  72.912 15.829 74.112 16.931 ;
     RECT  38.856 16.307 40.2 18.229 ;
     RECT  45.912 16.595 46.776 17.077 ;
     RECT  72.912 16.931 73.464 18.181 ;
     RECT  38.856 18.229 40.032 20.147 ;
     RECT  2.712 18.467 4.032 20.819 ;
     RECT  70.128 18.803 70.368 19.141 ;
     RECT  67.512 19.141 68.88 20.053 ;
     RECT  68.904 19.141 70.368 20.099 ;
     RECT  67.512 20.053 68.592 23.411 ;
     RECT  56.712 20.579 57.84 21.155 ;
     RECT  54.984 20.629 56.4 32.437 ;
     RECT  40.512 20.725 41.616 21.683 ;
     RECT  41.64 20.725 42.672 20.771 ;
     RECT  2.712 20.819 4.272 21.013 ;
     RECT  2.952 21.013 4.272 22.259 ;
     RECT  56.712 21.155 57.816 21.637 ;
     RECT  48.984 21.637 50.352 21.683 ;
     RECT  56.712 21.637 57.792 23.699 ;
     RECT  47.736 22.741 48.96 24.083 ;
     RECT  28.512 23.315 29.4 23.605 ;
     RECT  28.392 23.605 29.4 32.483 ;
     RECT  59.664 24.563 60.048 25.139 ;
     RECT  50.88 25.139 51 26.197 ;
     RECT  59.664 25.139 59.688 25.621 ;
     RECT  46.728 26.629 47.904 27.107 ;
     RECT  71.304 26.725 72.6 28.787 ;
     RECT  2.712 26.771 4.272 27.733 ;
     RECT  2.712 27.733 3.936 30.323 ;
     RECT  2.712 30.323 3.48 30.421 ;
     RECT  45.912 31.955 46.056 33.061 ;
     RECT  55.176 32.437 56.4 44.725 ;
     RECT  28.2 32.483 29.4 44.723 ;
     RECT  46.008 33.061 46.056 33.349 ;
     RECT  43.848 33.109 44.976 33.683 ;
     RECT  6.504 33.253 7.8 34.835 ;
     RECT  66.168 33.397 67.2 36.997 ;
     RECT  41.448 33.637 42.48 33.683 ;
     RECT  56.712 35.317 57.744 38.771 ;
     RECT  45.912 36.661 46.992 37.619 ;
     RECT  65.496 37.043 66.672 37.139 ;
     RECT  56.712 38.771 58.032 44.915 ;
     RECT  2.712 39.253 3.696 41.651 ;
     RECT  35.592 40.693 37.104 42.803 ;
     RECT  2.712 41.651 4.416 42.709 ;
     RECT  2.712 42.709 3.984 43.859 ;
     RECT  2.712 43.859 4.416 45.301 ;
     RECT  51.312 43.861 52.464 46.787 ;
     RECT  47.616 44.339 47.856 45.443 ;
     RECT  66.024 44.437 67.2 48.467 ;
     RECT  40.08 44.483 40.2 45.685 ;
     RECT  44.784 44.483 45.6 45.541 ;
     RECT  3.432 45.301 4.416 46.499 ;
     RECT  47.88 45.301 49.152 45.443 ;
     RECT  47.616 45.443 49.152 45.445 ;
     RECT  47.64 45.445 49.152 46.211 ;
     RECT  22.824 45.493 24 45.971 ;
     RECT  44.184 45.541 45.6 49.859 ;
     RECT  40.08 46.787 40.2 48.277 ;
     RECT  42.768 46.787 43.2 47.845 ;
     RECT  49.152 46.787 50.112 48.277 ;
     RECT  40.512 47.845 41.856 49.043 ;
     RECT  41.88 47.845 43.2 49.043 ;
     RECT  70.008 47.845 70.992 48.179 ;
     RECT  71.016 48.133 72.192 49.475 ;
     RECT  69.576 48.179 70.992 48.419 ;
     RECT  38.808 48.277 40.2 48.421 ;
     RECT  49.128 48.277 50.112 49.043 ;
     RECT  39.048 48.421 40.2 50.723 ;
     RECT  49.032 49.043 50.112 49.619 ;
     RECT  56.712 49.475 57.792 54.611 ;
     RECT  2.712 49.525 3.984 50.243 ;
     RECT  49.032 49.619 51 49.715 ;
     RECT  49.92 49.715 51 50.965 ;
     RECT  2.712 50.243 4.416 50.677 ;
     RECT  3.432 50.677 4.416 51.539 ;
     RECT  49.944 50.965 51 51.923 ;
     RECT  62.112 51.205 63.36 52.211 ;
     RECT  65.688 51.205 67.2 52.499 ;
     RECT  2.712 51.539 4.416 52.981 ;
     RECT  2.712 52.981 3.984 54.179 ;
     RECT  43.224 54.085 44.304 54.803 ;
     RECT  44.328 54.085 45.6 54.803 ;
     RECT  70.056 54.085 71.52 54.323 ;
     RECT  43.224 54.803 43.896 55.429 ;
     RECT  45.504 54.803 45.6 55.525 ;
     RECT  60.792 55.573 61.8 57.541 ;
     RECT  35.832 55.765 37.056 56.483 ;
     RECT  2.712 56.917 3.936 58.739 ;
     RECT  45.504 57.059 45.6 58.501 ;
     RECT  42.216 57.541 43.2 58.883 ;
     RECT  61.344 57.587 61.44 59.029 ;
     RECT  43.368 57.971 43.896 58.501 ;
     RECT  43.368 58.501 44.544 59.749 ;
     RECT  44.568 58.501 45.6 59.795 ;
     RECT  42.72 58.883 43.2 59.749 ;
     RECT  43.368 59.749 44.448 60.467 ;
     RECT  44.472 59.795 45.6 60.803 ;
     RECT  4.344 60.181 5.616 61.043 ;
     RECT  43.224 60.467 44.448 60.803 ;
     RECT  29.712 62.581 30.864 62.649 ;
     RECT  29.52 62.649 30.864 62.663 ;
  END
END ot_s81hd_lsc_t9
END LIBRARY
